VERSION 5.8 ;
BUSBITCHARS "[]" ;
DIVIDERCHAR "/" ;
UNITS
    DATABASE MICRONS 1000 ;
END UNITS

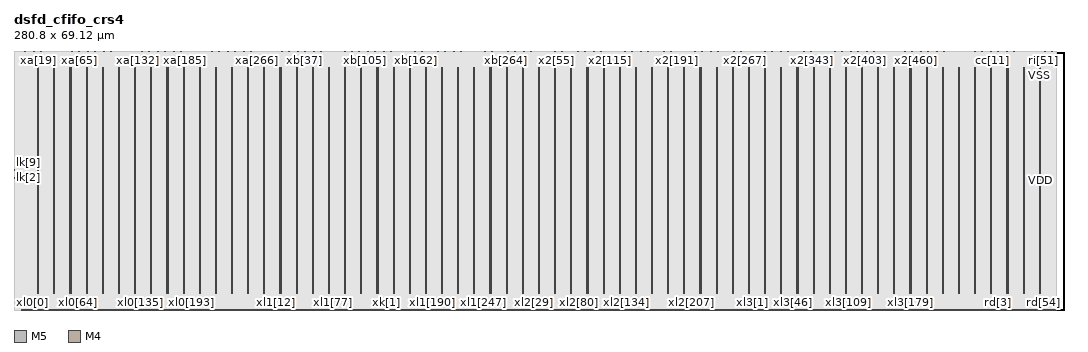
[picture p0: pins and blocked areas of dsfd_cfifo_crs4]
MACRO dsfd_cfifo_crs4
  FOREIGN dsfd_cfifo_crs4 0 0 ;
  CLASS BLOCK ;
  SIZE 280.8 BY 69.12 ;
  PIN cc[0]
    DIRECTION OUTPUT ;
    USE SIGNAL ;
    PORT
      LAYER M5 ;
        RECT  259.104 69.036 259.128 69.12 ;
    END
  END cc[0]
  PIN cc[10]
    DIRECTION OUTPUT ;
    USE SIGNAL ;
    PORT
      LAYER M5 ;
        RECT  261.504 69.036 261.528 69.12 ;
    END
  END cc[10]
  PIN cc[11]
    DIRECTION OUTPUT ;
    USE SIGNAL ;
    PORT
      LAYER M5 ;
        RECT  261.744 69.036 261.768 69.12 ;
    END
  END cc[11]
  PIN cc[12]
    DIRECTION OUTPUT ;
    USE SIGNAL ;
    PORT
      LAYER M5 ;
        RECT  261.984 69.036 262.008 69.12 ;
    END
  END cc[12]
  PIN cc[13]
    DIRECTION OUTPUT ;
    USE SIGNAL ;
    PORT
      LAYER M5 ;
        RECT  262.176 69.036 262.2 69.12 ;
    END
  END cc[13]
  PIN cc[14]
    DIRECTION OUTPUT ;
    USE SIGNAL ;
    PORT
      LAYER M5 ;
        RECT  262.416 69.036 262.44 69.12 ;
    END
  END cc[14]
  PIN cc[1]
    DIRECTION OUTPUT ;
    USE SIGNAL ;
    PORT
      LAYER M5 ;
        RECT  259.344 69.036 259.368 69.12 ;
    END
  END cc[1]
  PIN cc[2]
    DIRECTION OUTPUT ;
    USE SIGNAL ;
    PORT
      LAYER M5 ;
        RECT  259.584 69.036 259.608 69.12 ;
    END
  END cc[2]
  PIN cc[3]
    DIRECTION OUTPUT ;
    USE SIGNAL ;
    PORT
      LAYER M5 ;
        RECT  259.824 69.036 259.848 69.12 ;
    END
  END cc[3]
  PIN cc[4]
    DIRECTION OUTPUT ;
    USE SIGNAL ;
    PORT
      LAYER M5 ;
        RECT  260.064 69.036 260.088 69.12 ;
    END
  END cc[4]
  PIN cc[5]
    DIRECTION OUTPUT ;
    USE SIGNAL ;
    PORT
      LAYER M5 ;
        RECT  260.304 69.036 260.328 69.12 ;
    END
  END cc[5]
  PIN cc[6]
    DIRECTION OUTPUT ;
    USE SIGNAL ;
    PORT
      LAYER M5 ;
        RECT  260.544 69.036 260.568 69.12 ;
    END
  END cc[6]
  PIN cc[7]
    DIRECTION OUTPUT ;
    USE SIGNAL ;
    PORT
      LAYER M5 ;
        RECT  260.784 69.036 260.808 69.12 ;
    END
  END cc[7]
  PIN cc[8]
    DIRECTION OUTPUT ;
    USE SIGNAL ;
    PORT
      LAYER M5 ;
        RECT  261.024 69.036 261.048 69.12 ;
    END
  END cc[8]
  PIN cc[9]
    DIRECTION OUTPUT ;
    USE SIGNAL ;
    PORT
      LAYER M5 ;
        RECT  261.264 69.036 261.288 69.12 ;
    END
  END cc[9]
  PIN cr
    DIRECTION INPUT ;
    USE SIGNAL ;
    PORT
      LAYER M5 ;
        RECT  140.304 69.036 140.328 69.12 ;
    END
  END cr
  PIN cr_s
    DIRECTION INPUT ;
    USE SIGNAL ;
    PORT
      LAYER M5 ;
        RECT  270.624 0 270.648 0.084 ;
    END
  END cr_s
  PIN lk[0]
    DIRECTION INPUT ;
    USE SIGNAL ;
    PORT
      LAYER M4 ;
        RECT  0 35.04 0.084 35.064 ;
    END
  END lk[0]
  PIN lk[10]
    DIRECTION INPUT ;
    USE SIGNAL ;
    PORT
      LAYER M4 ;
        RECT  0 37.44 0.084 37.464 ;
    END
  END lk[10]
  PIN lk[11]
    DIRECTION INPUT ;
    USE SIGNAL ;
    PORT
      LAYER M4 ;
        RECT  0 37.68 0.084 37.704 ;
    END
  END lk[11]
  PIN lk[1]
    DIRECTION INPUT ;
    USE SIGNAL ;
    PORT
      LAYER M4 ;
        RECT  0 35.28 0.084 35.304 ;
    END
  END lk[1]
  PIN lk[2]
    DIRECTION INPUT ;
    USE SIGNAL ;
    PORT
      LAYER M4 ;
        RECT  0 35.52 0.084 35.544 ;
    END
  END lk[2]
  PIN lk[3]
    DIRECTION INPUT ;
    USE SIGNAL ;
    PORT
      LAYER M4 ;
        RECT  0 35.76 0.084 35.784 ;
    END
  END lk[3]
  PIN lk[4]
    DIRECTION INPUT ;
    USE SIGNAL ;
    PORT
      LAYER M4 ;
        RECT  0 36 0.084 36.024 ;
    END
  END lk[4]
  PIN lk[5]
    DIRECTION INPUT ;
    USE SIGNAL ;
    PORT
      LAYER M4 ;
        RECT  0 36.24 0.084 36.264 ;
    END
  END lk[5]
  PIN lk[6]
    DIRECTION INPUT ;
    USE SIGNAL ;
    PORT
      LAYER M4 ;
        RECT  0 36.48 0.084 36.504 ;
    END
  END lk[6]
  PIN lk[7]
    DIRECTION INPUT ;
    USE SIGNAL ;
    PORT
      LAYER M4 ;
        RECT  0 36.72 0.084 36.744 ;
    END
  END lk[7]
  PIN lk[8]
    DIRECTION INPUT ;
    USE SIGNAL ;
    PORT
      LAYER M4 ;
        RECT  0 36.96 0.084 36.984 ;
    END
  END lk[8]
  PIN lk[9]
    DIRECTION INPUT ;
    USE SIGNAL ;
    PORT
      LAYER M4 ;
        RECT  0 37.2 0.084 37.224 ;
    END
  END lk[9]
  PIN rd[0]
    DIRECTION OUTPUT ;
    USE SIGNAL ;
    PORT
      LAYER M5 ;
        RECT  262.512 0 262.536 0.084 ;
    END
  END rd[0]
  PIN rd[10]
    DIRECTION OUTPUT ;
    USE SIGNAL ;
    PORT
      LAYER M5 ;
        RECT  264.864 0 264.888 0.084 ;
    END
  END rd[10]
  PIN rd[11]
    DIRECTION OUTPUT ;
    USE SIGNAL ;
    PORT
      LAYER M5 ;
        RECT  265.104 0 265.128 0.084 ;
    END
  END rd[11]
  PIN rd[12]
    DIRECTION OUTPUT ;
    USE SIGNAL ;
    PORT
      LAYER M5 ;
        RECT  265.344 0 265.368 0.084 ;
    END
  END rd[12]
  PIN rd[13]
    DIRECTION OUTPUT ;
    USE SIGNAL ;
    PORT
      LAYER M5 ;
        RECT  265.584 0 265.608 0.084 ;
    END
  END rd[13]
  PIN rd[14]
    DIRECTION OUTPUT ;
    USE SIGNAL ;
    PORT
      LAYER M5 ;
        RECT  265.824 0 265.848 0.084 ;
    END
  END rd[14]
  PIN rd[15]
    DIRECTION OUTPUT ;
    USE SIGNAL ;
    PORT
      LAYER M5 ;
        RECT  266.064 0 266.088 0.084 ;
    END
  END rd[15]
  PIN rd[16]
    DIRECTION OUTPUT ;
    USE SIGNAL ;
    PORT
      LAYER M5 ;
        RECT  266.304 0 266.328 0.084 ;
    END
  END rd[16]
  PIN rd[17]
    DIRECTION OUTPUT ;
    USE SIGNAL ;
    PORT
      LAYER M5 ;
        RECT  266.496 0 266.52 0.084 ;
    END
  END rd[17]
  PIN rd[18]
    DIRECTION OUTPUT ;
    USE SIGNAL ;
    PORT
      LAYER M5 ;
        RECT  266.736 0 266.76 0.084 ;
    END
  END rd[18]
  PIN rd[19]
    DIRECTION OUTPUT ;
    USE SIGNAL ;
    PORT
      LAYER M5 ;
        RECT  266.976 0 267 0.084 ;
    END
  END rd[19]
  PIN rd[1]
    DIRECTION OUTPUT ;
    USE SIGNAL ;
    PORT
      LAYER M5 ;
        RECT  262.752 0 262.776 0.084 ;
    END
  END rd[1]
  PIN rd[20]
    DIRECTION OUTPUT ;
    USE SIGNAL ;
    PORT
      LAYER M5 ;
        RECT  267.216 0 267.24 0.084 ;
    END
  END rd[20]
  PIN rd[21]
    DIRECTION OUTPUT ;
    USE SIGNAL ;
    PORT
      LAYER M5 ;
        RECT  267.456 0 267.48 0.084 ;
    END
  END rd[21]
  PIN rd[22]
    DIRECTION OUTPUT ;
    USE SIGNAL ;
    PORT
      LAYER M5 ;
        RECT  267.696 0 267.72 0.084 ;
    END
  END rd[22]
  PIN rd[23]
    DIRECTION OUTPUT ;
    USE SIGNAL ;
    PORT
      LAYER M5 ;
        RECT  267.936 0 267.96 0.084 ;
    END
  END rd[23]
  PIN rd[24]
    DIRECTION OUTPUT ;
    USE SIGNAL ;
    PORT
      LAYER M5 ;
        RECT  268.176 0 268.2 0.084 ;
    END
  END rd[24]
  PIN rd[25]
    DIRECTION OUTPUT ;
    USE SIGNAL ;
    PORT
      LAYER M5 ;
        RECT  268.416 0 268.44 0.084 ;
    END
  END rd[25]
  PIN rd[26]
    DIRECTION OUTPUT ;
    USE SIGNAL ;
    PORT
      LAYER M5 ;
        RECT  268.656 0 268.68 0.084 ;
    END
  END rd[26]
  PIN rd[27]
    DIRECTION OUTPUT ;
    USE SIGNAL ;
    PORT
      LAYER M5 ;
        RECT  268.896 0 268.92 0.084 ;
    END
  END rd[27]
  PIN rd[28]
    DIRECTION OUTPUT ;
    USE SIGNAL ;
    PORT
      LAYER M5 ;
        RECT  269.136 0 269.16 0.084 ;
    END
  END rd[28]
  PIN rd[29]
    DIRECTION OUTPUT ;
    USE SIGNAL ;
    PORT
      LAYER M5 ;
        RECT  269.328 0 269.352 0.084 ;
    END
  END rd[29]
  PIN rd[2]
    DIRECTION OUTPUT ;
    USE SIGNAL ;
    PORT
      LAYER M5 ;
        RECT  262.992 0 263.016 0.084 ;
    END
  END rd[2]
  PIN rd[30]
    DIRECTION OUTPUT ;
    USE SIGNAL ;
    PORT
      LAYER M5 ;
        RECT  269.568 0 269.592 0.084 ;
    END
  END rd[30]
  PIN rd[31]
    DIRECTION OUTPUT ;
    USE SIGNAL ;
    PORT
      LAYER M5 ;
        RECT  269.808 0 269.832 0.084 ;
    END
  END rd[31]
  PIN rd[32]
    DIRECTION OUTPUT ;
    USE SIGNAL ;
    PORT
      LAYER M5 ;
        RECT  270.048 0 270.072 0.084 ;
    END
  END rd[32]
  PIN rd[33]
    DIRECTION OUTPUT ;
    USE SIGNAL ;
    PORT
      LAYER M5 ;
        RECT  270.288 0 270.312 0.084 ;
    END
  END rd[33]
  PIN rd[34]
    DIRECTION OUTPUT ;
    USE SIGNAL ;
    PORT
      LAYER M5 ;
        RECT  270.528 0 270.552 0.084 ;
    END
  END rd[34]
  PIN rd[35]
    DIRECTION OUTPUT ;
    USE SIGNAL ;
    PORT
      LAYER M5 ;
        RECT  270.768 0 270.792 0.084 ;
    END
  END rd[35]
  PIN rd[36]
    DIRECTION OUTPUT ;
    USE SIGNAL ;
    PORT
      LAYER M5 ;
        RECT  271.008 0 271.032 0.084 ;
    END
  END rd[36]
  PIN rd[37]
    DIRECTION OUTPUT ;
    USE SIGNAL ;
    PORT
      LAYER M5 ;
        RECT  271.248 0 271.272 0.084 ;
    END
  END rd[37]
  PIN rd[38]
    DIRECTION OUTPUT ;
    USE SIGNAL ;
    PORT
      LAYER M5 ;
        RECT  271.488 0 271.512 0.084 ;
    END
  END rd[38]
  PIN rd[39]
    DIRECTION OUTPUT ;
    USE SIGNAL ;
    PORT
      LAYER M5 ;
        RECT  271.728 0 271.752 0.084 ;
    END
  END rd[39]
  PIN rd[3]
    DIRECTION OUTPUT ;
    USE SIGNAL ;
    PORT
      LAYER M5 ;
        RECT  263.232 0 263.256 0.084 ;
    END
  END rd[3]
  PIN rd[40]
    DIRECTION OUTPUT ;
    USE SIGNAL ;
    PORT
      LAYER M5 ;
        RECT  271.968 0 271.992 0.084 ;
    END
  END rd[40]
  PIN rd[41]
    DIRECTION OUTPUT ;
    USE SIGNAL ;
    PORT
      LAYER M5 ;
        RECT  272.16 0 272.184 0.084 ;
    END
  END rd[41]
  PIN rd[42]
    DIRECTION OUTPUT ;
    USE SIGNAL ;
    PORT
      LAYER M5 ;
        RECT  272.4 0 272.424 0.084 ;
    END
  END rd[42]
  PIN rd[43]
    DIRECTION OUTPUT ;
    USE SIGNAL ;
    PORT
      LAYER M5 ;
        RECT  272.64 0 272.664 0.084 ;
    END
  END rd[43]
  PIN rd[44]
    DIRECTION OUTPUT ;
    USE SIGNAL ;
    PORT
      LAYER M5 ;
        RECT  272.88 0 272.904 0.084 ;
    END
  END rd[44]
  PIN rd[45]
    DIRECTION OUTPUT ;
    USE SIGNAL ;
    PORT
      LAYER M5 ;
        RECT  273.12 0 273.144 0.084 ;
    END
  END rd[45]
  PIN rd[46]
    DIRECTION OUTPUT ;
    USE SIGNAL ;
    PORT
      LAYER M5 ;
        RECT  273.36 0 273.384 0.084 ;
    END
  END rd[46]
  PIN rd[47]
    DIRECTION OUTPUT ;
    USE SIGNAL ;
    PORT
      LAYER M5 ;
        RECT  273.6 0 273.624 0.084 ;
    END
  END rd[47]
  PIN rd[48]
    DIRECTION OUTPUT ;
    USE SIGNAL ;
    PORT
      LAYER M5 ;
        RECT  273.84 0 273.864 0.084 ;
    END
  END rd[48]
  PIN rd[49]
    DIRECTION OUTPUT ;
    USE SIGNAL ;
    PORT
      LAYER M5 ;
        RECT  274.08 0 274.104 0.084 ;
    END
  END rd[49]
  PIN rd[4]
    DIRECTION OUTPUT ;
    USE SIGNAL ;
    PORT
      LAYER M5 ;
        RECT  263.472 0 263.496 0.084 ;
    END
  END rd[4]
  PIN rd[50]
    DIRECTION OUTPUT ;
    USE SIGNAL ;
    PORT
      LAYER M5 ;
        RECT  274.32 0 274.344 0.084 ;
    END
  END rd[50]
  PIN rd[51]
    DIRECTION OUTPUT ;
    USE SIGNAL ;
    PORT
      LAYER M5 ;
        RECT  274.56 0 274.584 0.084 ;
    END
  END rd[51]
  PIN rd[52]
    DIRECTION OUTPUT ;
    USE SIGNAL ;
    PORT
      LAYER M5 ;
        RECT  274.8 0 274.824 0.084 ;
    END
  END rd[52]
  PIN rd[53]
    DIRECTION OUTPUT ;
    USE SIGNAL ;
    PORT
      LAYER M5 ;
        RECT  274.992 0 275.016 0.084 ;
    END
  END rd[53]
  PIN rd[54]
    DIRECTION OUTPUT ;
    USE SIGNAL ;
    PORT
      LAYER M5 ;
        RECT  275.232 0 275.256 0.084 ;
    END
  END rd[54]
  PIN rd[55]
    DIRECTION OUTPUT ;
    USE SIGNAL ;
    PORT
      LAYER M5 ;
        RECT  275.472 0 275.496 0.084 ;
    END
  END rd[55]
  PIN rd[56]
    DIRECTION OUTPUT ;
    USE SIGNAL ;
    PORT
      LAYER M5 ;
        RECT  275.712 0 275.736 0.084 ;
    END
  END rd[56]
  PIN rd[57]
    DIRECTION OUTPUT ;
    USE SIGNAL ;
    PORT
      LAYER M5 ;
        RECT  275.952 0 275.976 0.084 ;
    END
  END rd[57]
  PIN rd[58]
    DIRECTION OUTPUT ;
    USE SIGNAL ;
    PORT
      LAYER M5 ;
        RECT  276.192 0 276.216 0.084 ;
    END
  END rd[58]
  PIN rd[59]
    DIRECTION OUTPUT ;
    USE SIGNAL ;
    PORT
      LAYER M5 ;
        RECT  276.432 0 276.456 0.084 ;
    END
  END rd[59]
  PIN rd[5]
    DIRECTION OUTPUT ;
    USE SIGNAL ;
    PORT
      LAYER M5 ;
        RECT  263.664 0 263.688 0.084 ;
    END
  END rd[5]
  PIN rd[60]
    DIRECTION OUTPUT ;
    USE SIGNAL ;
    PORT
      LAYER M5 ;
        RECT  276.672 0 276.696 0.084 ;
    END
  END rd[60]
  PIN rd[61]
    DIRECTION OUTPUT ;
    USE SIGNAL ;
    PORT
      LAYER M5 ;
        RECT  276.912 0 276.936 0.084 ;
    END
  END rd[61]
  PIN rd[62]
    DIRECTION OUTPUT ;
    USE SIGNAL ;
    PORT
      LAYER M5 ;
        RECT  277.152 0 277.176 0.084 ;
    END
  END rd[62]
  PIN rd[63]
    DIRECTION OUTPUT ;
    USE SIGNAL ;
    PORT
      LAYER M5 ;
        RECT  277.392 0 277.416 0.084 ;
    END
  END rd[63]
  PIN rd[64]
    DIRECTION OUTPUT ;
    USE SIGNAL ;
    PORT
      LAYER M5 ;
        RECT  277.632 0 277.656 0.084 ;
    END
  END rd[64]
  PIN rd[65]
    DIRECTION OUTPUT ;
    USE SIGNAL ;
    PORT
      LAYER M5 ;
        RECT  277.824 0 277.848 0.084 ;
    END
  END rd[65]
  PIN rd[66]
    DIRECTION OUTPUT ;
    USE SIGNAL ;
    PORT
      LAYER M5 ;
        RECT  278.064 0 278.088 0.084 ;
    END
  END rd[66]
  PIN rd[67]
    DIRECTION OUTPUT ;
    USE SIGNAL ;
    PORT
      LAYER M5 ;
        RECT  278.304 0 278.328 0.084 ;
    END
  END rd[67]
  PIN rd[68]
    DIRECTION OUTPUT ;
    USE SIGNAL ;
    PORT
      LAYER M5 ;
        RECT  278.544 0 278.568 0.084 ;
    END
  END rd[68]
  PIN rd[69]
    DIRECTION OUTPUT ;
    USE SIGNAL ;
    PORT
      LAYER M5 ;
        RECT  278.784 0 278.808 0.084 ;
    END
  END rd[69]
  PIN rd[6]
    DIRECTION OUTPUT ;
    USE SIGNAL ;
    PORT
      LAYER M5 ;
        RECT  263.904 0 263.928 0.084 ;
    END
  END rd[6]
  PIN rd[7]
    DIRECTION OUTPUT ;
    USE SIGNAL ;
    PORT
      LAYER M5 ;
        RECT  264.144 0 264.168 0.084 ;
    END
  END rd[7]
  PIN rd[8]
    DIRECTION OUTPUT ;
    USE SIGNAL ;
    PORT
      LAYER M5 ;
        RECT  264.384 0 264.408 0.084 ;
    END
  END rd[8]
  PIN rd[9]
    DIRECTION OUTPUT ;
    USE SIGNAL ;
    PORT
      LAYER M5 ;
        RECT  264.624 0 264.648 0.084 ;
    END
  END rd[9]
  PIN ri[0]
    DIRECTION INPUT ;
    USE SIGNAL ;
    PORT
      LAYER M5 ;
        RECT  263.136 69.036 263.16 69.12 ;
    END
  END ri[0]
  PIN ri[10]
    DIRECTION INPUT ;
    USE SIGNAL ;
    PORT
      LAYER M5 ;
        RECT  265.536 69.036 265.56 69.12 ;
    END
  END ri[10]
  PIN ri[11]
    DIRECTION INPUT ;
    USE SIGNAL ;
    PORT
      LAYER M5 ;
        RECT  265.776 69.036 265.8 69.12 ;
    END
  END ri[11]
  PIN ri[12]
    DIRECTION INPUT ;
    USE SIGNAL ;
    PORT
      LAYER M5 ;
        RECT  265.968 69.036 265.992 69.12 ;
    END
  END ri[12]
  PIN ri[13]
    DIRECTION INPUT ;
    USE SIGNAL ;
    PORT
      LAYER M5 ;
        RECT  266.208 69.036 266.232 69.12 ;
    END
  END ri[13]
  PIN ri[14]
    DIRECTION INPUT ;
    USE SIGNAL ;
    PORT
      LAYER M5 ;
        RECT  266.448 69.036 266.472 69.12 ;
    END
  END ri[14]
  PIN ri[15]
    DIRECTION INPUT ;
    USE SIGNAL ;
    PORT
      LAYER M5 ;
        RECT  266.688 69.036 266.712 69.12 ;
    END
  END ri[15]
  PIN ri[16]
    DIRECTION INPUT ;
    USE SIGNAL ;
    PORT
      LAYER M5 ;
        RECT  266.928 69.036 266.952 69.12 ;
    END
  END ri[16]
  PIN ri[17]
    DIRECTION INPUT ;
    USE SIGNAL ;
    PORT
      LAYER M5 ;
        RECT  267.168 69.036 267.192 69.12 ;
    END
  END ri[17]
  PIN ri[18]
    DIRECTION INPUT ;
    USE SIGNAL ;
    PORT
      LAYER M5 ;
        RECT  267.408 69.036 267.432 69.12 ;
    END
  END ri[18]
  PIN ri[19]
    DIRECTION INPUT ;
    USE SIGNAL ;
    PORT
      LAYER M5 ;
        RECT  267.648 69.036 267.672 69.12 ;
    END
  END ri[19]
  PIN ri[1]
    DIRECTION INPUT ;
    USE SIGNAL ;
    PORT
      LAYER M5 ;
        RECT  263.376 69.036 263.4 69.12 ;
    END
  END ri[1]
  PIN ri[20]
    DIRECTION INPUT ;
    USE SIGNAL ;
    PORT
      LAYER M5 ;
        RECT  267.888 69.036 267.912 69.12 ;
    END
  END ri[20]
  PIN ri[21]
    DIRECTION INPUT ;
    USE SIGNAL ;
    PORT
      LAYER M5 ;
        RECT  268.128 69.036 268.152 69.12 ;
    END
  END ri[21]
  PIN ri[22]
    DIRECTION INPUT ;
    USE SIGNAL ;
    PORT
      LAYER M5 ;
        RECT  268.368 69.036 268.392 69.12 ;
    END
  END ri[22]
  PIN ri[23]
    DIRECTION INPUT ;
    USE SIGNAL ;
    PORT
      LAYER M5 ;
        RECT  268.608 69.036 268.632 69.12 ;
    END
  END ri[23]
  PIN ri[24]
    DIRECTION INPUT ;
    USE SIGNAL ;
    PORT
      LAYER M5 ;
        RECT  268.848 69.036 268.872 69.12 ;
    END
  END ri[24]
  PIN ri[25]
    DIRECTION INPUT ;
    USE SIGNAL ;
    PORT
      LAYER M5 ;
        RECT  269.088 69.036 269.112 69.12 ;
    END
  END ri[25]
  PIN ri[26]
    DIRECTION INPUT ;
    USE SIGNAL ;
    PORT
      LAYER M5 ;
        RECT  269.328 69.036 269.352 69.12 ;
    END
  END ri[26]
  PIN ri[27]
    DIRECTION INPUT ;
    USE SIGNAL ;
    PORT
      LAYER M5 ;
        RECT  269.568 69.036 269.592 69.12 ;
    END
  END ri[27]
  PIN ri[28]
    DIRECTION INPUT ;
    USE SIGNAL ;
    PORT
      LAYER M5 ;
        RECT  269.76 69.036 269.784 69.12 ;
    END
  END ri[28]
  PIN ri[29]
    DIRECTION INPUT ;
    USE SIGNAL ;
    PORT
      LAYER M5 ;
        RECT  270 69.036 270.024 69.12 ;
    END
  END ri[29]
  PIN ri[2]
    DIRECTION INPUT ;
    USE SIGNAL ;
    PORT
      LAYER M5 ;
        RECT  263.616 69.036 263.64 69.12 ;
    END
  END ri[2]
  PIN ri[30]
    DIRECTION INPUT ;
    USE SIGNAL ;
    PORT
      LAYER M5 ;
        RECT  270.24 69.036 270.264 69.12 ;
    END
  END ri[30]
  PIN ri[31]
    DIRECTION INPUT ;
    USE SIGNAL ;
    PORT
      LAYER M5 ;
        RECT  270.48 69.036 270.504 69.12 ;
    END
  END ri[31]
  PIN ri[32]
    DIRECTION INPUT ;
    USE SIGNAL ;
    PORT
      LAYER M5 ;
        RECT  270.72 69.036 270.744 69.12 ;
    END
  END ri[32]
  PIN ri[33]
    DIRECTION INPUT ;
    USE SIGNAL ;
    PORT
      LAYER M5 ;
        RECT  270.96 69.036 270.984 69.12 ;
    END
  END ri[33]
  PIN ri[34]
    DIRECTION INPUT ;
    USE SIGNAL ;
    PORT
      LAYER M5 ;
        RECT  271.2 69.036 271.224 69.12 ;
    END
  END ri[34]
  PIN ri[35]
    DIRECTION INPUT ;
    USE SIGNAL ;
    PORT
      LAYER M5 ;
        RECT  271.44 69.036 271.464 69.12 ;
    END
  END ri[35]
  PIN ri[36]
    DIRECTION INPUT ;
    USE SIGNAL ;
    PORT
      LAYER M5 ;
        RECT  271.68 69.036 271.704 69.12 ;
    END
  END ri[36]
  PIN ri[37]
    DIRECTION INPUT ;
    USE SIGNAL ;
    PORT
      LAYER M5 ;
        RECT  271.92 69.036 271.944 69.12 ;
    END
  END ri[37]
  PIN ri[38]
    DIRECTION INPUT ;
    USE SIGNAL ;
    PORT
      LAYER M5 ;
        RECT  272.16 69.036 272.184 69.12 ;
    END
  END ri[38]
  PIN ri[39]
    DIRECTION INPUT ;
    USE SIGNAL ;
    PORT
      LAYER M5 ;
        RECT  272.4 69.036 272.424 69.12 ;
    END
  END ri[39]
  PIN ri[3]
    DIRECTION INPUT ;
    USE SIGNAL ;
    PORT
      LAYER M5 ;
        RECT  263.856 69.036 263.88 69.12 ;
    END
  END ri[3]
  PIN ri[40]
    DIRECTION INPUT ;
    USE SIGNAL ;
    PORT
      LAYER M5 ;
        RECT  272.64 69.036 272.664 69.12 ;
    END
  END ri[40]
  PIN ri[41]
    DIRECTION INPUT ;
    USE SIGNAL ;
    PORT
      LAYER M5 ;
        RECT  272.88 69.036 272.904 69.12 ;
    END
  END ri[41]
  PIN ri[42]
    DIRECTION INPUT ;
    USE SIGNAL ;
    PORT
      LAYER M5 ;
        RECT  273.12 69.036 273.144 69.12 ;
    END
  END ri[42]
  PIN ri[43]
    DIRECTION INPUT ;
    USE SIGNAL ;
    PORT
      LAYER M5 ;
        RECT  273.36 69.036 273.384 69.12 ;
    END
  END ri[43]
  PIN ri[44]
    DIRECTION INPUT ;
    USE SIGNAL ;
    PORT
      LAYER M5 ;
        RECT  273.552 69.036 273.576 69.12 ;
    END
  END ri[44]
  PIN ri[45]
    DIRECTION INPUT ;
    USE SIGNAL ;
    PORT
      LAYER M5 ;
        RECT  273.792 69.036 273.816 69.12 ;
    END
  END ri[45]
  PIN ri[46]
    DIRECTION INPUT ;
    USE SIGNAL ;
    PORT
      LAYER M5 ;
        RECT  274.032 69.036 274.056 69.12 ;
    END
  END ri[46]
  PIN ri[47]
    DIRECTION INPUT ;
    USE SIGNAL ;
    PORT
      LAYER M5 ;
        RECT  274.272 69.036 274.296 69.12 ;
    END
  END ri[47]
  PIN ri[48]
    DIRECTION INPUT ;
    USE SIGNAL ;
    PORT
      LAYER M5 ;
        RECT  274.512 69.036 274.536 69.12 ;
    END
  END ri[48]
  PIN ri[49]
    DIRECTION INPUT ;
    USE SIGNAL ;
    PORT
      LAYER M5 ;
        RECT  274.752 69.036 274.776 69.12 ;
    END
  END ri[49]
  PIN ri[4]
    DIRECTION INPUT ;
    USE SIGNAL ;
    PORT
      LAYER M5 ;
        RECT  264.096 69.036 264.12 69.12 ;
    END
  END ri[4]
  PIN ri[50]
    DIRECTION INPUT ;
    USE SIGNAL ;
    PORT
      LAYER M5 ;
        RECT  274.992 69.036 275.016 69.12 ;
    END
  END ri[50]
  PIN ri[51]
    DIRECTION INPUT ;
    USE SIGNAL ;
    PORT
      LAYER M5 ;
        RECT  275.232 69.036 275.256 69.12 ;
    END
  END ri[51]
  PIN ri[52]
    DIRECTION INPUT ;
    USE SIGNAL ;
    PORT
      LAYER M5 ;
        RECT  275.472 69.036 275.496 69.12 ;
    END
  END ri[52]
  PIN ri[53]
    DIRECTION INPUT ;
    USE SIGNAL ;
    PORT
      LAYER M5 ;
        RECT  275.712 69.036 275.736 69.12 ;
    END
  END ri[53]
  PIN ri[54]
    DIRECTION INPUT ;
    USE SIGNAL ;
    PORT
      LAYER M5 ;
        RECT  275.952 69.036 275.976 69.12 ;
    END
  END ri[54]
  PIN ri[55]
    DIRECTION INPUT ;
    USE SIGNAL ;
    PORT
      LAYER M5 ;
        RECT  276.192 69.036 276.216 69.12 ;
    END
  END ri[55]
  PIN ri[56]
    DIRECTION INPUT ;
    USE SIGNAL ;
    PORT
      LAYER M5 ;
        RECT  276.432 69.036 276.456 69.12 ;
    END
  END ri[56]
  PIN ri[57]
    DIRECTION INPUT ;
    USE SIGNAL ;
    PORT
      LAYER M5 ;
        RECT  276.672 69.036 276.696 69.12 ;
    END
  END ri[57]
  PIN ri[58]
    DIRECTION INPUT ;
    USE SIGNAL ;
    PORT
      LAYER M5 ;
        RECT  276.912 69.036 276.936 69.12 ;
    END
  END ri[58]
  PIN ri[59]
    DIRECTION INPUT ;
    USE SIGNAL ;
    PORT
      LAYER M5 ;
        RECT  277.152 69.036 277.176 69.12 ;
    END
  END ri[59]
  PIN ri[5]
    DIRECTION INPUT ;
    USE SIGNAL ;
    PORT
      LAYER M5 ;
        RECT  264.336 69.036 264.36 69.12 ;
    END
  END ri[5]
  PIN ri[60]
    DIRECTION INPUT ;
    USE SIGNAL ;
    PORT
      LAYER M5 ;
        RECT  277.344 69.036 277.368 69.12 ;
    END
  END ri[60]
  PIN ri[61]
    DIRECTION INPUT ;
    USE SIGNAL ;
    PORT
      LAYER M5 ;
        RECT  277.584 69.036 277.608 69.12 ;
    END
  END ri[61]
  PIN ri[62]
    DIRECTION INPUT ;
    USE SIGNAL ;
    PORT
      LAYER M5 ;
        RECT  277.824 69.036 277.848 69.12 ;
    END
  END ri[62]
  PIN ri[63]
    DIRECTION INPUT ;
    USE SIGNAL ;
    PORT
      LAYER M5 ;
        RECT  278.064 69.036 278.088 69.12 ;
    END
  END ri[63]
  PIN ri[64]
    DIRECTION INPUT ;
    USE SIGNAL ;
    PORT
      LAYER M5 ;
        RECT  278.304 69.036 278.328 69.12 ;
    END
  END ri[64]
  PIN ri[65]
    DIRECTION INPUT ;
    USE SIGNAL ;
    PORT
      LAYER M5 ;
        RECT  278.544 69.036 278.568 69.12 ;
    END
  END ri[65]
  PIN ri[6]
    DIRECTION INPUT ;
    USE SIGNAL ;
    PORT
      LAYER M5 ;
        RECT  264.576 69.036 264.6 69.12 ;
    END
  END ri[6]
  PIN ri[7]
    DIRECTION INPUT ;
    USE SIGNAL ;
    PORT
      LAYER M5 ;
        RECT  264.816 69.036 264.84 69.12 ;
    END
  END ri[7]
  PIN ri[8]
    DIRECTION INPUT ;
    USE SIGNAL ;
    PORT
      LAYER M5 ;
        RECT  265.056 69.036 265.08 69.12 ;
    END
  END ri[8]
  PIN ri[9]
    DIRECTION INPUT ;
    USE SIGNAL ;
    PORT
      LAYER M5 ;
        RECT  265.296 69.036 265.32 69.12 ;
    END
  END ri[9]
  PIN rs
    DIRECTION OUTPUT ;
    USE SIGNAL ;
    PORT
      LAYER M5 ;
        RECT  278.784 69.036 278.808 69.12 ;
    END
  END rs
  PIN rst
    DIRECTION INPUT ;
    USE SIGNAL ;
    PORT
      LAYER M4 ;
        RECT  0 34.56 0.084 34.584 ;
    END
  END rst
  PIN st[0]
    DIRECTION INPUT ;
    USE SIGNAL ;
    PORT
      LAYER M5 ;
        RECT  262.656 69.036 262.68 69.12 ;
    END
  END st[0]
  PIN st[1]
    DIRECTION INPUT ;
    USE SIGNAL ;
    PORT
      LAYER M5 ;
        RECT  262.896 69.036 262.92 69.12 ;
    END
  END st[1]
  PIN x2[0]
    DIRECTION OUTPUT ;
    USE SIGNAL ;
    PORT
      LAYER M5 ;
        RECT  132.096 69.036 132.12 69.12 ;
    END
  END x2[0]
  PIN x2[100]
    DIRECTION OUTPUT ;
    USE SIGNAL ;
    PORT
      LAYER M5 ;
        RECT  155.808 69.036 155.832 69.12 ;
    END
  END x2[100]
  PIN x2[101]
    DIRECTION OUTPUT ;
    USE SIGNAL ;
    PORT
      LAYER M5 ;
        RECT  156.048 69.036 156.072 69.12 ;
    END
  END x2[101]
  PIN x2[102]
    DIRECTION OUTPUT ;
    USE SIGNAL ;
    PORT
      LAYER M5 ;
        RECT  156.288 69.036 156.312 69.12 ;
    END
  END x2[102]
  PIN x2[103]
    DIRECTION OUTPUT ;
    USE SIGNAL ;
    PORT
      LAYER M5 ;
        RECT  156.48 69.036 156.504 69.12 ;
    END
  END x2[103]
  PIN x2[104]
    DIRECTION OUTPUT ;
    USE SIGNAL ;
    PORT
      LAYER M5 ;
        RECT  156.72 69.036 156.744 69.12 ;
    END
  END x2[104]
  PIN x2[105]
    DIRECTION OUTPUT ;
    USE SIGNAL ;
    PORT
      LAYER M5 ;
        RECT  156.96 69.036 156.984 69.12 ;
    END
  END x2[105]
  PIN x2[106]
    DIRECTION OUTPUT ;
    USE SIGNAL ;
    PORT
      LAYER M5 ;
        RECT  157.2 69.036 157.224 69.12 ;
    END
  END x2[106]
  PIN x2[107]
    DIRECTION OUTPUT ;
    USE SIGNAL ;
    PORT
      LAYER M5 ;
        RECT  157.44 69.036 157.464 69.12 ;
    END
  END x2[107]
  PIN x2[108]
    DIRECTION OUTPUT ;
    USE SIGNAL ;
    PORT
      LAYER M5 ;
        RECT  157.68 69.036 157.704 69.12 ;
    END
  END x2[108]
  PIN x2[109]
    DIRECTION OUTPUT ;
    USE SIGNAL ;
    PORT
      LAYER M5 ;
        RECT  157.92 69.036 157.944 69.12 ;
    END
  END x2[109]
  PIN x2[10]
    DIRECTION OUTPUT ;
    USE SIGNAL ;
    PORT
      LAYER M5 ;
        RECT  134.448 69.036 134.472 69.12 ;
    END
  END x2[10]
  PIN x2[110]
    DIRECTION OUTPUT ;
    USE SIGNAL ;
    PORT
      LAYER M5 ;
        RECT  158.16 69.036 158.184 69.12 ;
    END
  END x2[110]
  PIN x2[111]
    DIRECTION OUTPUT ;
    USE SIGNAL ;
    PORT
      LAYER M5 ;
        RECT  158.4 69.036 158.424 69.12 ;
    END
  END x2[111]
  PIN x2[112]
    DIRECTION OUTPUT ;
    USE SIGNAL ;
    PORT
      LAYER M5 ;
        RECT  158.64 69.036 158.664 69.12 ;
    END
  END x2[112]
  PIN x2[113]
    DIRECTION OUTPUT ;
    USE SIGNAL ;
    PORT
      LAYER M5 ;
        RECT  158.88 69.036 158.904 69.12 ;
    END
  END x2[113]
  PIN x2[114]
    DIRECTION OUTPUT ;
    USE SIGNAL ;
    PORT
      LAYER M5 ;
        RECT  159.12 69.036 159.144 69.12 ;
    END
  END x2[114]
  PIN x2[115]
    DIRECTION OUTPUT ;
    USE SIGNAL ;
    PORT
      LAYER M5 ;
        RECT  159.36 69.036 159.384 69.12 ;
    END
  END x2[115]
  PIN x2[116]
    DIRECTION OUTPUT ;
    USE SIGNAL ;
    PORT
      LAYER M5 ;
        RECT  159.6 69.036 159.624 69.12 ;
    END
  END x2[116]
  PIN x2[117]
    DIRECTION OUTPUT ;
    USE SIGNAL ;
    PORT
      LAYER M5 ;
        RECT  159.84 69.036 159.864 69.12 ;
    END
  END x2[117]
  PIN x2[118]
    DIRECTION OUTPUT ;
    USE SIGNAL ;
    PORT
      LAYER M5 ;
        RECT  160.08 69.036 160.104 69.12 ;
    END
  END x2[118]
  PIN x2[119]
    DIRECTION OUTPUT ;
    USE SIGNAL ;
    PORT
      LAYER M5 ;
        RECT  160.272 69.036 160.296 69.12 ;
    END
  END x2[119]
  PIN x2[11]
    DIRECTION OUTPUT ;
    USE SIGNAL ;
    PORT
      LAYER M5 ;
        RECT  134.688 69.036 134.712 69.12 ;
    END
  END x2[11]
  PIN x2[120]
    DIRECTION OUTPUT ;
    USE SIGNAL ;
    PORT
      LAYER M5 ;
        RECT  160.512 69.036 160.536 69.12 ;
    END
  END x2[120]
  PIN x2[121]
    DIRECTION OUTPUT ;
    USE SIGNAL ;
    PORT
      LAYER M5 ;
        RECT  160.752 69.036 160.776 69.12 ;
    END
  END x2[121]
  PIN x2[122]
    DIRECTION OUTPUT ;
    USE SIGNAL ;
    PORT
      LAYER M5 ;
        RECT  160.992 69.036 161.016 69.12 ;
    END
  END x2[122]
  PIN x2[123]
    DIRECTION OUTPUT ;
    USE SIGNAL ;
    PORT
      LAYER M5 ;
        RECT  161.232 69.036 161.256 69.12 ;
    END
  END x2[123]
  PIN x2[124]
    DIRECTION OUTPUT ;
    USE SIGNAL ;
    PORT
      LAYER M5 ;
        RECT  161.472 69.036 161.496 69.12 ;
    END
  END x2[124]
  PIN x2[125]
    DIRECTION OUTPUT ;
    USE SIGNAL ;
    PORT
      LAYER M5 ;
        RECT  161.712 69.036 161.736 69.12 ;
    END
  END x2[125]
  PIN x2[126]
    DIRECTION OUTPUT ;
    USE SIGNAL ;
    PORT
      LAYER M5 ;
        RECT  161.952 69.036 161.976 69.12 ;
    END
  END x2[126]
  PIN x2[127]
    DIRECTION OUTPUT ;
    USE SIGNAL ;
    PORT
      LAYER M5 ;
        RECT  162.192 69.036 162.216 69.12 ;
    END
  END x2[127]
  PIN x2[128]
    DIRECTION OUTPUT ;
    USE SIGNAL ;
    PORT
      LAYER M5 ;
        RECT  162.432 69.036 162.456 69.12 ;
    END
  END x2[128]
  PIN x2[129]
    DIRECTION OUTPUT ;
    USE SIGNAL ;
    PORT
      LAYER M5 ;
        RECT  162.672 69.036 162.696 69.12 ;
    END
  END x2[129]
  PIN x2[12]
    DIRECTION OUTPUT ;
    USE SIGNAL ;
    PORT
      LAYER M5 ;
        RECT  134.928 69.036 134.952 69.12 ;
    END
  END x2[12]
  PIN x2[130]
    DIRECTION OUTPUT ;
    USE SIGNAL ;
    PORT
      LAYER M5 ;
        RECT  162.912 69.036 162.936 69.12 ;
    END
  END x2[130]
  PIN x2[131]
    DIRECTION OUTPUT ;
    USE SIGNAL ;
    PORT
      LAYER M5 ;
        RECT  163.152 69.036 163.176 69.12 ;
    END
  END x2[131]
  PIN x2[132]
    DIRECTION OUTPUT ;
    USE SIGNAL ;
    PORT
      LAYER M5 ;
        RECT  163.392 69.036 163.416 69.12 ;
    END
  END x2[132]
  PIN x2[133]
    DIRECTION OUTPUT ;
    USE SIGNAL ;
    PORT
      LAYER M5 ;
        RECT  163.632 69.036 163.656 69.12 ;
    END
  END x2[133]
  PIN x2[134]
    DIRECTION OUTPUT ;
    USE SIGNAL ;
    PORT
      LAYER M5 ;
        RECT  163.872 69.036 163.896 69.12 ;
    END
  END x2[134]
  PIN x2[135]
    DIRECTION OUTPUT ;
    USE SIGNAL ;
    PORT
      LAYER M5 ;
        RECT  164.064 69.036 164.088 69.12 ;
    END
  END x2[135]
  PIN x2[136]
    DIRECTION OUTPUT ;
    USE SIGNAL ;
    PORT
      LAYER M5 ;
        RECT  164.304 69.036 164.328 69.12 ;
    END
  END x2[136]
  PIN x2[137]
    DIRECTION OUTPUT ;
    USE SIGNAL ;
    PORT
      LAYER M5 ;
        RECT  164.544 69.036 164.568 69.12 ;
    END
  END x2[137]
  PIN x2[138]
    DIRECTION OUTPUT ;
    USE SIGNAL ;
    PORT
      LAYER M5 ;
        RECT  164.784 69.036 164.808 69.12 ;
    END
  END x2[138]
  PIN x2[139]
    DIRECTION OUTPUT ;
    USE SIGNAL ;
    PORT
      LAYER M5 ;
        RECT  165.024 69.036 165.048 69.12 ;
    END
  END x2[139]
  PIN x2[13]
    DIRECTION OUTPUT ;
    USE SIGNAL ;
    PORT
      LAYER M5 ;
        RECT  135.168 69.036 135.192 69.12 ;
    END
  END x2[13]
  PIN x2[140]
    DIRECTION OUTPUT ;
    USE SIGNAL ;
    PORT
      LAYER M5 ;
        RECT  165.264 69.036 165.288 69.12 ;
    END
  END x2[140]
  PIN x2[141]
    DIRECTION OUTPUT ;
    USE SIGNAL ;
    PORT
      LAYER M5 ;
        RECT  165.504 69.036 165.528 69.12 ;
    END
  END x2[141]
  PIN x2[142]
    DIRECTION OUTPUT ;
    USE SIGNAL ;
    PORT
      LAYER M5 ;
        RECT  165.744 69.036 165.768 69.12 ;
    END
  END x2[142]
  PIN x2[143]
    DIRECTION OUTPUT ;
    USE SIGNAL ;
    PORT
      LAYER M5 ;
        RECT  165.984 69.036 166.008 69.12 ;
    END
  END x2[143]
  PIN x2[144]
    DIRECTION OUTPUT ;
    USE SIGNAL ;
    PORT
      LAYER M5 ;
        RECT  166.224 69.036 166.248 69.12 ;
    END
  END x2[144]
  PIN x2[145]
    DIRECTION OUTPUT ;
    USE SIGNAL ;
    PORT
      LAYER M5 ;
        RECT  166.464 69.036 166.488 69.12 ;
    END
  END x2[145]
  PIN x2[146]
    DIRECTION OUTPUT ;
    USE SIGNAL ;
    PORT
      LAYER M5 ;
        RECT  166.704 69.036 166.728 69.12 ;
    END
  END x2[146]
  PIN x2[147]
    DIRECTION OUTPUT ;
    USE SIGNAL ;
    PORT
      LAYER M5 ;
        RECT  166.944 69.036 166.968 69.12 ;
    END
  END x2[147]
  PIN x2[148]
    DIRECTION OUTPUT ;
    USE SIGNAL ;
    PORT
      LAYER M5 ;
        RECT  167.184 69.036 167.208 69.12 ;
    END
  END x2[148]
  PIN x2[149]
    DIRECTION OUTPUT ;
    USE SIGNAL ;
    PORT
      LAYER M5 ;
        RECT  167.424 69.036 167.448 69.12 ;
    END
  END x2[149]
  PIN x2[14]
    DIRECTION OUTPUT ;
    USE SIGNAL ;
    PORT
      LAYER M5 ;
        RECT  135.408 69.036 135.432 69.12 ;
    END
  END x2[14]
  PIN x2[150]
    DIRECTION OUTPUT ;
    USE SIGNAL ;
    PORT
      LAYER M5 ;
        RECT  167.664 69.036 167.688 69.12 ;
    END
  END x2[150]
  PIN x2[151]
    DIRECTION OUTPUT ;
    USE SIGNAL ;
    PORT
      LAYER M5 ;
        RECT  167.856 69.036 167.88 69.12 ;
    END
  END x2[151]
  PIN x2[152]
    DIRECTION OUTPUT ;
    USE SIGNAL ;
    PORT
      LAYER M5 ;
        RECT  168.096 69.036 168.12 69.12 ;
    END
  END x2[152]
  PIN x2[153]
    DIRECTION OUTPUT ;
    USE SIGNAL ;
    PORT
      LAYER M5 ;
        RECT  168.336 69.036 168.36 69.12 ;
    END
  END x2[153]
  PIN x2[154]
    DIRECTION OUTPUT ;
    USE SIGNAL ;
    PORT
      LAYER M5 ;
        RECT  168.576 69.036 168.6 69.12 ;
    END
  END x2[154]
  PIN x2[155]
    DIRECTION OUTPUT ;
    USE SIGNAL ;
    PORT
      LAYER M5 ;
        RECT  168.816 69.036 168.84 69.12 ;
    END
  END x2[155]
  PIN x2[156]
    DIRECTION OUTPUT ;
    USE SIGNAL ;
    PORT
      LAYER M5 ;
        RECT  169.056 69.036 169.08 69.12 ;
    END
  END x2[156]
  PIN x2[157]
    DIRECTION OUTPUT ;
    USE SIGNAL ;
    PORT
      LAYER M5 ;
        RECT  169.296 69.036 169.32 69.12 ;
    END
  END x2[157]
  PIN x2[158]
    DIRECTION OUTPUT ;
    USE SIGNAL ;
    PORT
      LAYER M5 ;
        RECT  169.536 69.036 169.56 69.12 ;
    END
  END x2[158]
  PIN x2[159]
    DIRECTION OUTPUT ;
    USE SIGNAL ;
    PORT
      LAYER M5 ;
        RECT  169.776 69.036 169.8 69.12 ;
    END
  END x2[159]
  PIN x2[15]
    DIRECTION OUTPUT ;
    USE SIGNAL ;
    PORT
      LAYER M5 ;
        RECT  135.648 69.036 135.672 69.12 ;
    END
  END x2[15]
  PIN x2[160]
    DIRECTION OUTPUT ;
    USE SIGNAL ;
    PORT
      LAYER M5 ;
        RECT  170.016 69.036 170.04 69.12 ;
    END
  END x2[160]
  PIN x2[161]
    DIRECTION OUTPUT ;
    USE SIGNAL ;
    PORT
      LAYER M5 ;
        RECT  170.256 69.036 170.28 69.12 ;
    END
  END x2[161]
  PIN x2[162]
    DIRECTION OUTPUT ;
    USE SIGNAL ;
    PORT
      LAYER M5 ;
        RECT  170.496 69.036 170.52 69.12 ;
    END
  END x2[162]
  PIN x2[163]
    DIRECTION OUTPUT ;
    USE SIGNAL ;
    PORT
      LAYER M5 ;
        RECT  170.736 69.036 170.76 69.12 ;
    END
  END x2[163]
  PIN x2[164]
    DIRECTION OUTPUT ;
    USE SIGNAL ;
    PORT
      LAYER M5 ;
        RECT  170.976 69.036 171 69.12 ;
    END
  END x2[164]
  PIN x2[165]
    DIRECTION OUTPUT ;
    USE SIGNAL ;
    PORT
      LAYER M5 ;
        RECT  171.216 69.036 171.24 69.12 ;
    END
  END x2[165]
  PIN x2[166]
    DIRECTION OUTPUT ;
    USE SIGNAL ;
    PORT
      LAYER M5 ;
        RECT  171.456 69.036 171.48 69.12 ;
    END
  END x2[166]
  PIN x2[167]
    DIRECTION OUTPUT ;
    USE SIGNAL ;
    PORT
      LAYER M5 ;
        RECT  171.648 69.036 171.672 69.12 ;
    END
  END x2[167]
  PIN x2[168]
    DIRECTION OUTPUT ;
    USE SIGNAL ;
    PORT
      LAYER M5 ;
        RECT  171.888 69.036 171.912 69.12 ;
    END
  END x2[168]
  PIN x2[169]
    DIRECTION OUTPUT ;
    USE SIGNAL ;
    PORT
      LAYER M5 ;
        RECT  172.128 69.036 172.152 69.12 ;
    END
  END x2[169]
  PIN x2[16]
    DIRECTION OUTPUT ;
    USE SIGNAL ;
    PORT
      LAYER M5 ;
        RECT  135.888 69.036 135.912 69.12 ;
    END
  END x2[16]
  PIN x2[170]
    DIRECTION OUTPUT ;
    USE SIGNAL ;
    PORT
      LAYER M5 ;
        RECT  172.368 69.036 172.392 69.12 ;
    END
  END x2[170]
  PIN x2[171]
    DIRECTION OUTPUT ;
    USE SIGNAL ;
    PORT
      LAYER M5 ;
        RECT  172.608 69.036 172.632 69.12 ;
    END
  END x2[171]
  PIN x2[172]
    DIRECTION OUTPUT ;
    USE SIGNAL ;
    PORT
      LAYER M5 ;
        RECT  172.848 69.036 172.872 69.12 ;
    END
  END x2[172]
  PIN x2[173]
    DIRECTION OUTPUT ;
    USE SIGNAL ;
    PORT
      LAYER M5 ;
        RECT  173.088 69.036 173.112 69.12 ;
    END
  END x2[173]
  PIN x2[174]
    DIRECTION OUTPUT ;
    USE SIGNAL ;
    PORT
      LAYER M5 ;
        RECT  173.328 69.036 173.352 69.12 ;
    END
  END x2[174]
  PIN x2[175]
    DIRECTION OUTPUT ;
    USE SIGNAL ;
    PORT
      LAYER M5 ;
        RECT  173.568 69.036 173.592 69.12 ;
    END
  END x2[175]
  PIN x2[176]
    DIRECTION OUTPUT ;
    USE SIGNAL ;
    PORT
      LAYER M5 ;
        RECT  173.808 69.036 173.832 69.12 ;
    END
  END x2[176]
  PIN x2[177]
    DIRECTION OUTPUT ;
    USE SIGNAL ;
    PORT
      LAYER M5 ;
        RECT  174.048 69.036 174.072 69.12 ;
    END
  END x2[177]
  PIN x2[178]
    DIRECTION OUTPUT ;
    USE SIGNAL ;
    PORT
      LAYER M5 ;
        RECT  174.288 69.036 174.312 69.12 ;
    END
  END x2[178]
  PIN x2[179]
    DIRECTION OUTPUT ;
    USE SIGNAL ;
    PORT
      LAYER M5 ;
        RECT  174.528 69.036 174.552 69.12 ;
    END
  END x2[179]
  PIN x2[17]
    DIRECTION OUTPUT ;
    USE SIGNAL ;
    PORT
      LAYER M5 ;
        RECT  136.128 69.036 136.152 69.12 ;
    END
  END x2[17]
  PIN x2[180]
    DIRECTION OUTPUT ;
    USE SIGNAL ;
    PORT
      LAYER M5 ;
        RECT  174.768 69.036 174.792 69.12 ;
    END
  END x2[180]
  PIN x2[181]
    DIRECTION OUTPUT ;
    USE SIGNAL ;
    PORT
      LAYER M5 ;
        RECT  175.008 69.036 175.032 69.12 ;
    END
  END x2[181]
  PIN x2[182]
    DIRECTION OUTPUT ;
    USE SIGNAL ;
    PORT
      LAYER M5 ;
        RECT  175.248 69.036 175.272 69.12 ;
    END
  END x2[182]
  PIN x2[183]
    DIRECTION OUTPUT ;
    USE SIGNAL ;
    PORT
      LAYER M5 ;
        RECT  175.44 69.036 175.464 69.12 ;
    END
  END x2[183]
  PIN x2[184]
    DIRECTION OUTPUT ;
    USE SIGNAL ;
    PORT
      LAYER M5 ;
        RECT  175.68 69.036 175.704 69.12 ;
    END
  END x2[184]
  PIN x2[185]
    DIRECTION OUTPUT ;
    USE SIGNAL ;
    PORT
      LAYER M5 ;
        RECT  175.92 69.036 175.944 69.12 ;
    END
  END x2[185]
  PIN x2[186]
    DIRECTION OUTPUT ;
    USE SIGNAL ;
    PORT
      LAYER M5 ;
        RECT  176.16 69.036 176.184 69.12 ;
    END
  END x2[186]
  PIN x2[187]
    DIRECTION OUTPUT ;
    USE SIGNAL ;
    PORT
      LAYER M5 ;
        RECT  176.4 69.036 176.424 69.12 ;
    END
  END x2[187]
  PIN x2[188]
    DIRECTION OUTPUT ;
    USE SIGNAL ;
    PORT
      LAYER M5 ;
        RECT  176.64 69.036 176.664 69.12 ;
    END
  END x2[188]
  PIN x2[189]
    DIRECTION OUTPUT ;
    USE SIGNAL ;
    PORT
      LAYER M5 ;
        RECT  176.88 69.036 176.904 69.12 ;
    END
  END x2[189]
  PIN x2[18]
    DIRECTION OUTPUT ;
    USE SIGNAL ;
    PORT
      LAYER M5 ;
        RECT  136.368 69.036 136.392 69.12 ;
    END
  END x2[18]
  PIN x2[190]
    DIRECTION OUTPUT ;
    USE SIGNAL ;
    PORT
      LAYER M5 ;
        RECT  177.12 69.036 177.144 69.12 ;
    END
  END x2[190]
  PIN x2[191]
    DIRECTION OUTPUT ;
    USE SIGNAL ;
    PORT
      LAYER M5 ;
        RECT  177.36 69.036 177.384 69.12 ;
    END
  END x2[191]
  PIN x2[192]
    DIRECTION OUTPUT ;
    USE SIGNAL ;
    PORT
      LAYER M5 ;
        RECT  177.6 69.036 177.624 69.12 ;
    END
  END x2[192]
  PIN x2[193]
    DIRECTION OUTPUT ;
    USE SIGNAL ;
    PORT
      LAYER M5 ;
        RECT  177.84 69.036 177.864 69.12 ;
    END
  END x2[193]
  PIN x2[194]
    DIRECTION OUTPUT ;
    USE SIGNAL ;
    PORT
      LAYER M5 ;
        RECT  178.08 69.036 178.104 69.12 ;
    END
  END x2[194]
  PIN x2[195]
    DIRECTION OUTPUT ;
    USE SIGNAL ;
    PORT
      LAYER M5 ;
        RECT  178.32 69.036 178.344 69.12 ;
    END
  END x2[195]
  PIN x2[196]
    DIRECTION OUTPUT ;
    USE SIGNAL ;
    PORT
      LAYER M5 ;
        RECT  178.56 69.036 178.584 69.12 ;
    END
  END x2[196]
  PIN x2[197]
    DIRECTION OUTPUT ;
    USE SIGNAL ;
    PORT
      LAYER M5 ;
        RECT  178.8 69.036 178.824 69.12 ;
    END
  END x2[197]
  PIN x2[198]
    DIRECTION OUTPUT ;
    USE SIGNAL ;
    PORT
      LAYER M5 ;
        RECT  179.04 69.036 179.064 69.12 ;
    END
  END x2[198]
  PIN x2[199]
    DIRECTION OUTPUT ;
    USE SIGNAL ;
    PORT
      LAYER M5 ;
        RECT  179.232 69.036 179.256 69.12 ;
    END
  END x2[199]
  PIN x2[19]
    DIRECTION OUTPUT ;
    USE SIGNAL ;
    PORT
      LAYER M5 ;
        RECT  136.608 69.036 136.632 69.12 ;
    END
  END x2[19]
  PIN x2[1]
    DIRECTION OUTPUT ;
    USE SIGNAL ;
    PORT
      LAYER M5 ;
        RECT  132.336 69.036 132.36 69.12 ;
    END
  END x2[1]
  PIN x2[200]
    DIRECTION OUTPUT ;
    USE SIGNAL ;
    PORT
      LAYER M5 ;
        RECT  179.472 69.036 179.496 69.12 ;
    END
  END x2[200]
  PIN x2[201]
    DIRECTION OUTPUT ;
    USE SIGNAL ;
    PORT
      LAYER M5 ;
        RECT  179.712 69.036 179.736 69.12 ;
    END
  END x2[201]
  PIN x2[202]
    DIRECTION OUTPUT ;
    USE SIGNAL ;
    PORT
      LAYER M5 ;
        RECT  179.952 69.036 179.976 69.12 ;
    END
  END x2[202]
  PIN x2[203]
    DIRECTION OUTPUT ;
    USE SIGNAL ;
    PORT
      LAYER M5 ;
        RECT  180.192 69.036 180.216 69.12 ;
    END
  END x2[203]
  PIN x2[204]
    DIRECTION OUTPUT ;
    USE SIGNAL ;
    PORT
      LAYER M5 ;
        RECT  180.432 69.036 180.456 69.12 ;
    END
  END x2[204]
  PIN x2[205]
    DIRECTION OUTPUT ;
    USE SIGNAL ;
    PORT
      LAYER M5 ;
        RECT  180.672 69.036 180.696 69.12 ;
    END
  END x2[205]
  PIN x2[206]
    DIRECTION OUTPUT ;
    USE SIGNAL ;
    PORT
      LAYER M5 ;
        RECT  180.912 69.036 180.936 69.12 ;
    END
  END x2[206]
  PIN x2[207]
    DIRECTION OUTPUT ;
    USE SIGNAL ;
    PORT
      LAYER M5 ;
        RECT  181.152 69.036 181.176 69.12 ;
    END
  END x2[207]
  PIN x2[208]
    DIRECTION OUTPUT ;
    USE SIGNAL ;
    PORT
      LAYER M5 ;
        RECT  181.392 69.036 181.416 69.12 ;
    END
  END x2[208]
  PIN x2[209]
    DIRECTION OUTPUT ;
    USE SIGNAL ;
    PORT
      LAYER M5 ;
        RECT  181.632 69.036 181.656 69.12 ;
    END
  END x2[209]
  PIN x2[20]
    DIRECTION OUTPUT ;
    USE SIGNAL ;
    PORT
      LAYER M5 ;
        RECT  136.848 69.036 136.872 69.12 ;
    END
  END x2[20]
  PIN x2[210]
    DIRECTION OUTPUT ;
    USE SIGNAL ;
    PORT
      LAYER M5 ;
        RECT  181.872 69.036 181.896 69.12 ;
    END
  END x2[210]
  PIN x2[211]
    DIRECTION OUTPUT ;
    USE SIGNAL ;
    PORT
      LAYER M5 ;
        RECT  182.112 69.036 182.136 69.12 ;
    END
  END x2[211]
  PIN x2[212]
    DIRECTION OUTPUT ;
    USE SIGNAL ;
    PORT
      LAYER M5 ;
        RECT  182.352 69.036 182.376 69.12 ;
    END
  END x2[212]
  PIN x2[213]
    DIRECTION OUTPUT ;
    USE SIGNAL ;
    PORT
      LAYER M5 ;
        RECT  182.592 69.036 182.616 69.12 ;
    END
  END x2[213]
  PIN x2[214]
    DIRECTION OUTPUT ;
    USE SIGNAL ;
    PORT
      LAYER M5 ;
        RECT  182.832 69.036 182.856 69.12 ;
    END
  END x2[214]
  PIN x2[215]
    DIRECTION OUTPUT ;
    USE SIGNAL ;
    PORT
      LAYER M5 ;
        RECT  183.024 69.036 183.048 69.12 ;
    END
  END x2[215]
  PIN x2[216]
    DIRECTION OUTPUT ;
    USE SIGNAL ;
    PORT
      LAYER M5 ;
        RECT  183.264 69.036 183.288 69.12 ;
    END
  END x2[216]
  PIN x2[217]
    DIRECTION OUTPUT ;
    USE SIGNAL ;
    PORT
      LAYER M5 ;
        RECT  183.504 69.036 183.528 69.12 ;
    END
  END x2[217]
  PIN x2[218]
    DIRECTION OUTPUT ;
    USE SIGNAL ;
    PORT
      LAYER M5 ;
        RECT  183.744 69.036 183.768 69.12 ;
    END
  END x2[218]
  PIN x2[219]
    DIRECTION OUTPUT ;
    USE SIGNAL ;
    PORT
      LAYER M5 ;
        RECT  183.984 69.036 184.008 69.12 ;
    END
  END x2[219]
  PIN x2[21]
    DIRECTION OUTPUT ;
    USE SIGNAL ;
    PORT
      LAYER M5 ;
        RECT  137.088 69.036 137.112 69.12 ;
    END
  END x2[21]
  PIN x2[220]
    DIRECTION OUTPUT ;
    USE SIGNAL ;
    PORT
      LAYER M5 ;
        RECT  184.224 69.036 184.248 69.12 ;
    END
  END x2[220]
  PIN x2[221]
    DIRECTION OUTPUT ;
    USE SIGNAL ;
    PORT
      LAYER M5 ;
        RECT  184.464 69.036 184.488 69.12 ;
    END
  END x2[221]
  PIN x2[222]
    DIRECTION OUTPUT ;
    USE SIGNAL ;
    PORT
      LAYER M5 ;
        RECT  184.704 69.036 184.728 69.12 ;
    END
  END x2[222]
  PIN x2[223]
    DIRECTION OUTPUT ;
    USE SIGNAL ;
    PORT
      LAYER M5 ;
        RECT  184.944 69.036 184.968 69.12 ;
    END
  END x2[223]
  PIN x2[224]
    DIRECTION OUTPUT ;
    USE SIGNAL ;
    PORT
      LAYER M5 ;
        RECT  185.184 69.036 185.208 69.12 ;
    END
  END x2[224]
  PIN x2[225]
    DIRECTION OUTPUT ;
    USE SIGNAL ;
    PORT
      LAYER M5 ;
        RECT  185.424 69.036 185.448 69.12 ;
    END
  END x2[225]
  PIN x2[226]
    DIRECTION OUTPUT ;
    USE SIGNAL ;
    PORT
      LAYER M5 ;
        RECT  185.664 69.036 185.688 69.12 ;
    END
  END x2[226]
  PIN x2[227]
    DIRECTION OUTPUT ;
    USE SIGNAL ;
    PORT
      LAYER M5 ;
        RECT  185.904 69.036 185.928 69.12 ;
    END
  END x2[227]
  PIN x2[228]
    DIRECTION OUTPUT ;
    USE SIGNAL ;
    PORT
      LAYER M5 ;
        RECT  186.144 69.036 186.168 69.12 ;
    END
  END x2[228]
  PIN x2[229]
    DIRECTION OUTPUT ;
    USE SIGNAL ;
    PORT
      LAYER M5 ;
        RECT  186.384 69.036 186.408 69.12 ;
    END
  END x2[229]
  PIN x2[22]
    DIRECTION OUTPUT ;
    USE SIGNAL ;
    PORT
      LAYER M5 ;
        RECT  137.328 69.036 137.352 69.12 ;
    END
  END x2[22]
  PIN x2[230]
    DIRECTION OUTPUT ;
    USE SIGNAL ;
    PORT
      LAYER M5 ;
        RECT  186.624 69.036 186.648 69.12 ;
    END
  END x2[230]
  PIN x2[231]
    DIRECTION OUTPUT ;
    USE SIGNAL ;
    PORT
      LAYER M5 ;
        RECT  186.816 69.036 186.84 69.12 ;
    END
  END x2[231]
  PIN x2[232]
    DIRECTION OUTPUT ;
    USE SIGNAL ;
    PORT
      LAYER M5 ;
        RECT  187.056 69.036 187.08 69.12 ;
    END
  END x2[232]
  PIN x2[233]
    DIRECTION OUTPUT ;
    USE SIGNAL ;
    PORT
      LAYER M5 ;
        RECT  187.296 69.036 187.32 69.12 ;
    END
  END x2[233]
  PIN x2[234]
    DIRECTION OUTPUT ;
    USE SIGNAL ;
    PORT
      LAYER M5 ;
        RECT  187.536 69.036 187.56 69.12 ;
    END
  END x2[234]
  PIN x2[235]
    DIRECTION OUTPUT ;
    USE SIGNAL ;
    PORT
      LAYER M5 ;
        RECT  187.776 69.036 187.8 69.12 ;
    END
  END x2[235]
  PIN x2[236]
    DIRECTION OUTPUT ;
    USE SIGNAL ;
    PORT
      LAYER M5 ;
        RECT  188.016 69.036 188.04 69.12 ;
    END
  END x2[236]
  PIN x2[237]
    DIRECTION OUTPUT ;
    USE SIGNAL ;
    PORT
      LAYER M5 ;
        RECT  188.256 69.036 188.28 69.12 ;
    END
  END x2[237]
  PIN x2[238]
    DIRECTION OUTPUT ;
    USE SIGNAL ;
    PORT
      LAYER M5 ;
        RECT  188.496 69.036 188.52 69.12 ;
    END
  END x2[238]
  PIN x2[239]
    DIRECTION OUTPUT ;
    USE SIGNAL ;
    PORT
      LAYER M5 ;
        RECT  188.736 69.036 188.76 69.12 ;
    END
  END x2[239]
  PIN x2[23]
    DIRECTION OUTPUT ;
    USE SIGNAL ;
    PORT
      LAYER M5 ;
        RECT  137.568 69.036 137.592 69.12 ;
    END
  END x2[23]
  PIN x2[240]
    DIRECTION OUTPUT ;
    USE SIGNAL ;
    PORT
      LAYER M5 ;
        RECT  188.976 69.036 189 69.12 ;
    END
  END x2[240]
  PIN x2[241]
    DIRECTION OUTPUT ;
    USE SIGNAL ;
    PORT
      LAYER M5 ;
        RECT  189.216 69.036 189.24 69.12 ;
    END
  END x2[241]
  PIN x2[242]
    DIRECTION OUTPUT ;
    USE SIGNAL ;
    PORT
      LAYER M5 ;
        RECT  189.456 69.036 189.48 69.12 ;
    END
  END x2[242]
  PIN x2[243]
    DIRECTION OUTPUT ;
    USE SIGNAL ;
    PORT
      LAYER M5 ;
        RECT  189.696 69.036 189.72 69.12 ;
    END
  END x2[243]
  PIN x2[244]
    DIRECTION OUTPUT ;
    USE SIGNAL ;
    PORT
      LAYER M5 ;
        RECT  189.936 69.036 189.96 69.12 ;
    END
  END x2[244]
  PIN x2[245]
    DIRECTION OUTPUT ;
    USE SIGNAL ;
    PORT
      LAYER M5 ;
        RECT  190.176 69.036 190.2 69.12 ;
    END
  END x2[245]
  PIN x2[246]
    DIRECTION OUTPUT ;
    USE SIGNAL ;
    PORT
      LAYER M5 ;
        RECT  190.416 69.036 190.44 69.12 ;
    END
  END x2[246]
  PIN x2[247]
    DIRECTION OUTPUT ;
    USE SIGNAL ;
    PORT
      LAYER M5 ;
        RECT  190.608 69.036 190.632 69.12 ;
    END
  END x2[247]
  PIN x2[248]
    DIRECTION OUTPUT ;
    USE SIGNAL ;
    PORT
      LAYER M5 ;
        RECT  190.848 69.036 190.872 69.12 ;
    END
  END x2[248]
  PIN x2[249]
    DIRECTION OUTPUT ;
    USE SIGNAL ;
    PORT
      LAYER M5 ;
        RECT  191.088 69.036 191.112 69.12 ;
    END
  END x2[249]
  PIN x2[24]
    DIRECTION OUTPUT ;
    USE SIGNAL ;
    PORT
      LAYER M5 ;
        RECT  137.76 69.036 137.784 69.12 ;
    END
  END x2[24]
  PIN x2[250]
    DIRECTION OUTPUT ;
    USE SIGNAL ;
    PORT
      LAYER M5 ;
        RECT  191.328 69.036 191.352 69.12 ;
    END
  END x2[250]
  PIN x2[251]
    DIRECTION OUTPUT ;
    USE SIGNAL ;
    PORT
      LAYER M5 ;
        RECT  191.568 69.036 191.592 69.12 ;
    END
  END x2[251]
  PIN x2[252]
    DIRECTION OUTPUT ;
    USE SIGNAL ;
    PORT
      LAYER M5 ;
        RECT  191.808 69.036 191.832 69.12 ;
    END
  END x2[252]
  PIN x2[253]
    DIRECTION OUTPUT ;
    USE SIGNAL ;
    PORT
      LAYER M5 ;
        RECT  192.048 69.036 192.072 69.12 ;
    END
  END x2[253]
  PIN x2[254]
    DIRECTION OUTPUT ;
    USE SIGNAL ;
    PORT
      LAYER M5 ;
        RECT  192.288 69.036 192.312 69.12 ;
    END
  END x2[254]
  PIN x2[255]
    DIRECTION OUTPUT ;
    USE SIGNAL ;
    PORT
      LAYER M5 ;
        RECT  192.528 69.036 192.552 69.12 ;
    END
  END x2[255]
  PIN x2[256]
    DIRECTION OUTPUT ;
    USE SIGNAL ;
    PORT
      LAYER M5 ;
        RECT  192.768 69.036 192.792 69.12 ;
    END
  END x2[256]
  PIN x2[257]
    DIRECTION OUTPUT ;
    USE SIGNAL ;
    PORT
      LAYER M5 ;
        RECT  193.008 69.036 193.032 69.12 ;
    END
  END x2[257]
  PIN x2[258]
    DIRECTION OUTPUT ;
    USE SIGNAL ;
    PORT
      LAYER M5 ;
        RECT  193.248 69.036 193.272 69.12 ;
    END
  END x2[258]
  PIN x2[259]
    DIRECTION OUTPUT ;
    USE SIGNAL ;
    PORT
      LAYER M5 ;
        RECT  193.488 69.036 193.512 69.12 ;
    END
  END x2[259]
  PIN x2[25]
    DIRECTION OUTPUT ;
    USE SIGNAL ;
    PORT
      LAYER M5 ;
        RECT  138 69.036 138.024 69.12 ;
    END
  END x2[25]
  PIN x2[260]
    DIRECTION OUTPUT ;
    USE SIGNAL ;
    PORT
      LAYER M5 ;
        RECT  193.728 69.036 193.752 69.12 ;
    END
  END x2[260]
  PIN x2[261]
    DIRECTION OUTPUT ;
    USE SIGNAL ;
    PORT
      LAYER M5 ;
        RECT  193.968 69.036 193.992 69.12 ;
    END
  END x2[261]
  PIN x2[262]
    DIRECTION OUTPUT ;
    USE SIGNAL ;
    PORT
      LAYER M5 ;
        RECT  194.16 69.036 194.184 69.12 ;
    END
  END x2[262]
  PIN x2[263]
    DIRECTION OUTPUT ;
    USE SIGNAL ;
    PORT
      LAYER M5 ;
        RECT  194.4 69.036 194.424 69.12 ;
    END
  END x2[263]
  PIN x2[264]
    DIRECTION OUTPUT ;
    USE SIGNAL ;
    PORT
      LAYER M5 ;
        RECT  194.64 69.036 194.664 69.12 ;
    END
  END x2[264]
  PIN x2[265]
    DIRECTION OUTPUT ;
    USE SIGNAL ;
    PORT
      LAYER M5 ;
        RECT  194.88 69.036 194.904 69.12 ;
    END
  END x2[265]
  PIN x2[266]
    DIRECTION OUTPUT ;
    USE SIGNAL ;
    PORT
      LAYER M5 ;
        RECT  195.12 69.036 195.144 69.12 ;
    END
  END x2[266]
  PIN x2[267]
    DIRECTION OUTPUT ;
    USE SIGNAL ;
    PORT
      LAYER M5 ;
        RECT  195.36 69.036 195.384 69.12 ;
    END
  END x2[267]
  PIN x2[268]
    DIRECTION OUTPUT ;
    USE SIGNAL ;
    PORT
      LAYER M5 ;
        RECT  195.6 69.036 195.624 69.12 ;
    END
  END x2[268]
  PIN x2[269]
    DIRECTION OUTPUT ;
    USE SIGNAL ;
    PORT
      LAYER M5 ;
        RECT  195.84 69.036 195.864 69.12 ;
    END
  END x2[269]
  PIN x2[26]
    DIRECTION OUTPUT ;
    USE SIGNAL ;
    PORT
      LAYER M5 ;
        RECT  138.24 69.036 138.264 69.12 ;
    END
  END x2[26]
  PIN x2[270]
    DIRECTION OUTPUT ;
    USE SIGNAL ;
    PORT
      LAYER M5 ;
        RECT  196.08 69.036 196.104 69.12 ;
    END
  END x2[270]
  PIN x2[271]
    DIRECTION OUTPUT ;
    USE SIGNAL ;
    PORT
      LAYER M5 ;
        RECT  196.32 69.036 196.344 69.12 ;
    END
  END x2[271]
  PIN x2[272]
    DIRECTION OUTPUT ;
    USE SIGNAL ;
    PORT
      LAYER M5 ;
        RECT  196.56 69.036 196.584 69.12 ;
    END
  END x2[272]
  PIN x2[273]
    DIRECTION OUTPUT ;
    USE SIGNAL ;
    PORT
      LAYER M5 ;
        RECT  196.8 69.036 196.824 69.12 ;
    END
  END x2[273]
  PIN x2[274]
    DIRECTION OUTPUT ;
    USE SIGNAL ;
    PORT
      LAYER M5 ;
        RECT  197.04 69.036 197.064 69.12 ;
    END
  END x2[274]
  PIN x2[275]
    DIRECTION OUTPUT ;
    USE SIGNAL ;
    PORT
      LAYER M5 ;
        RECT  197.28 69.036 197.304 69.12 ;
    END
  END x2[275]
  PIN x2[276]
    DIRECTION OUTPUT ;
    USE SIGNAL ;
    PORT
      LAYER M5 ;
        RECT  197.52 69.036 197.544 69.12 ;
    END
  END x2[276]
  PIN x2[277]
    DIRECTION OUTPUT ;
    USE SIGNAL ;
    PORT
      LAYER M5 ;
        RECT  197.76 69.036 197.784 69.12 ;
    END
  END x2[277]
  PIN x2[278]
    DIRECTION OUTPUT ;
    USE SIGNAL ;
    PORT
      LAYER M5 ;
        RECT  197.952 69.036 197.976 69.12 ;
    END
  END x2[278]
  PIN x2[279]
    DIRECTION OUTPUT ;
    USE SIGNAL ;
    PORT
      LAYER M5 ;
        RECT  198.192 69.036 198.216 69.12 ;
    END
  END x2[279]
  PIN x2[27]
    DIRECTION OUTPUT ;
    USE SIGNAL ;
    PORT
      LAYER M5 ;
        RECT  138.48 69.036 138.504 69.12 ;
    END
  END x2[27]
  PIN x2[280]
    DIRECTION OUTPUT ;
    USE SIGNAL ;
    PORT
      LAYER M5 ;
        RECT  198.432 69.036 198.456 69.12 ;
    END
  END x2[280]
  PIN x2[281]
    DIRECTION OUTPUT ;
    USE SIGNAL ;
    PORT
      LAYER M5 ;
        RECT  198.672 69.036 198.696 69.12 ;
    END
  END x2[281]
  PIN x2[282]
    DIRECTION OUTPUT ;
    USE SIGNAL ;
    PORT
      LAYER M5 ;
        RECT  198.912 69.036 198.936 69.12 ;
    END
  END x2[282]
  PIN x2[283]
    DIRECTION OUTPUT ;
    USE SIGNAL ;
    PORT
      LAYER M5 ;
        RECT  199.152 69.036 199.176 69.12 ;
    END
  END x2[283]
  PIN x2[284]
    DIRECTION OUTPUT ;
    USE SIGNAL ;
    PORT
      LAYER M5 ;
        RECT  199.392 69.036 199.416 69.12 ;
    END
  END x2[284]
  PIN x2[285]
    DIRECTION OUTPUT ;
    USE SIGNAL ;
    PORT
      LAYER M5 ;
        RECT  199.632 69.036 199.656 69.12 ;
    END
  END x2[285]
  PIN x2[286]
    DIRECTION OUTPUT ;
    USE SIGNAL ;
    PORT
      LAYER M5 ;
        RECT  199.872 69.036 199.896 69.12 ;
    END
  END x2[286]
  PIN x2[287]
    DIRECTION OUTPUT ;
    USE SIGNAL ;
    PORT
      LAYER M5 ;
        RECT  200.112 69.036 200.136 69.12 ;
    END
  END x2[287]
  PIN x2[288]
    DIRECTION OUTPUT ;
    USE SIGNAL ;
    PORT
      LAYER M5 ;
        RECT  200.352 69.036 200.376 69.12 ;
    END
  END x2[288]
  PIN x2[289]
    DIRECTION OUTPUT ;
    USE SIGNAL ;
    PORT
      LAYER M5 ;
        RECT  200.592 69.036 200.616 69.12 ;
    END
  END x2[289]
  PIN x2[28]
    DIRECTION OUTPUT ;
    USE SIGNAL ;
    PORT
      LAYER M5 ;
        RECT  138.72 69.036 138.744 69.12 ;
    END
  END x2[28]
  PIN x2[290]
    DIRECTION OUTPUT ;
    USE SIGNAL ;
    PORT
      LAYER M5 ;
        RECT  200.832 69.036 200.856 69.12 ;
    END
  END x2[290]
  PIN x2[291]
    DIRECTION OUTPUT ;
    USE SIGNAL ;
    PORT
      LAYER M5 ;
        RECT  201.072 69.036 201.096 69.12 ;
    END
  END x2[291]
  PIN x2[292]
    DIRECTION OUTPUT ;
    USE SIGNAL ;
    PORT
      LAYER M5 ;
        RECT  201.312 69.036 201.336 69.12 ;
    END
  END x2[292]
  PIN x2[293]
    DIRECTION OUTPUT ;
    USE SIGNAL ;
    PORT
      LAYER M5 ;
        RECT  201.552 69.036 201.576 69.12 ;
    END
  END x2[293]
  PIN x2[294]
    DIRECTION OUTPUT ;
    USE SIGNAL ;
    PORT
      LAYER M5 ;
        RECT  201.744 69.036 201.768 69.12 ;
    END
  END x2[294]
  PIN x2[295]
    DIRECTION OUTPUT ;
    USE SIGNAL ;
    PORT
      LAYER M5 ;
        RECT  201.984 69.036 202.008 69.12 ;
    END
  END x2[295]
  PIN x2[296]
    DIRECTION OUTPUT ;
    USE SIGNAL ;
    PORT
      LAYER M5 ;
        RECT  202.224 69.036 202.248 69.12 ;
    END
  END x2[296]
  PIN x2[297]
    DIRECTION OUTPUT ;
    USE SIGNAL ;
    PORT
      LAYER M5 ;
        RECT  202.464 69.036 202.488 69.12 ;
    END
  END x2[297]
  PIN x2[298]
    DIRECTION OUTPUT ;
    USE SIGNAL ;
    PORT
      LAYER M5 ;
        RECT  202.704 69.036 202.728 69.12 ;
    END
  END x2[298]
  PIN x2[299]
    DIRECTION OUTPUT ;
    USE SIGNAL ;
    PORT
      LAYER M5 ;
        RECT  202.944 69.036 202.968 69.12 ;
    END
  END x2[299]
  PIN x2[29]
    DIRECTION OUTPUT ;
    USE SIGNAL ;
    PORT
      LAYER M5 ;
        RECT  138.96 69.036 138.984 69.12 ;
    END
  END x2[29]
  PIN x2[2]
    DIRECTION OUTPUT ;
    USE SIGNAL ;
    PORT
      LAYER M5 ;
        RECT  132.576 69.036 132.6 69.12 ;
    END
  END x2[2]
  PIN x2[300]
    DIRECTION OUTPUT ;
    USE SIGNAL ;
    PORT
      LAYER M5 ;
        RECT  203.184 69.036 203.208 69.12 ;
    END
  END x2[300]
  PIN x2[301]
    DIRECTION OUTPUT ;
    USE SIGNAL ;
    PORT
      LAYER M5 ;
        RECT  203.424 69.036 203.448 69.12 ;
    END
  END x2[301]
  PIN x2[302]
    DIRECTION OUTPUT ;
    USE SIGNAL ;
    PORT
      LAYER M5 ;
        RECT  203.664 69.036 203.688 69.12 ;
    END
  END x2[302]
  PIN x2[303]
    DIRECTION OUTPUT ;
    USE SIGNAL ;
    PORT
      LAYER M5 ;
        RECT  203.904 69.036 203.928 69.12 ;
    END
  END x2[303]
  PIN x2[304]
    DIRECTION OUTPUT ;
    USE SIGNAL ;
    PORT
      LAYER M5 ;
        RECT  204.144 69.036 204.168 69.12 ;
    END
  END x2[304]
  PIN x2[305]
    DIRECTION OUTPUT ;
    USE SIGNAL ;
    PORT
      LAYER M5 ;
        RECT  204.384 69.036 204.408 69.12 ;
    END
  END x2[305]
  PIN x2[306]
    DIRECTION OUTPUT ;
    USE SIGNAL ;
    PORT
      LAYER M5 ;
        RECT  204.624 69.036 204.648 69.12 ;
    END
  END x2[306]
  PIN x2[307]
    DIRECTION OUTPUT ;
    USE SIGNAL ;
    PORT
      LAYER M5 ;
        RECT  204.864 69.036 204.888 69.12 ;
    END
  END x2[307]
  PIN x2[308]
    DIRECTION OUTPUT ;
    USE SIGNAL ;
    PORT
      LAYER M5 ;
        RECT  205.104 69.036 205.128 69.12 ;
    END
  END x2[308]
  PIN x2[309]
    DIRECTION OUTPUT ;
    USE SIGNAL ;
    PORT
      LAYER M5 ;
        RECT  205.344 69.036 205.368 69.12 ;
    END
  END x2[309]
  PIN x2[30]
    DIRECTION OUTPUT ;
    USE SIGNAL ;
    PORT
      LAYER M5 ;
        RECT  139.2 69.036 139.224 69.12 ;
    END
  END x2[30]
  PIN x2[310]
    DIRECTION OUTPUT ;
    USE SIGNAL ;
    PORT
      LAYER M5 ;
        RECT  205.536 69.036 205.56 69.12 ;
    END
  END x2[310]
  PIN x2[311]
    DIRECTION OUTPUT ;
    USE SIGNAL ;
    PORT
      LAYER M5 ;
        RECT  205.776 69.036 205.8 69.12 ;
    END
  END x2[311]
  PIN x2[312]
    DIRECTION OUTPUT ;
    USE SIGNAL ;
    PORT
      LAYER M5 ;
        RECT  206.016 69.036 206.04 69.12 ;
    END
  END x2[312]
  PIN x2[313]
    DIRECTION OUTPUT ;
    USE SIGNAL ;
    PORT
      LAYER M5 ;
        RECT  206.256 69.036 206.28 69.12 ;
    END
  END x2[313]
  PIN x2[314]
    DIRECTION OUTPUT ;
    USE SIGNAL ;
    PORT
      LAYER M5 ;
        RECT  206.496 69.036 206.52 69.12 ;
    END
  END x2[314]
  PIN x2[315]
    DIRECTION OUTPUT ;
    USE SIGNAL ;
    PORT
      LAYER M5 ;
        RECT  206.736 69.036 206.76 69.12 ;
    END
  END x2[315]
  PIN x2[316]
    DIRECTION OUTPUT ;
    USE SIGNAL ;
    PORT
      LAYER M5 ;
        RECT  206.976 69.036 207 69.12 ;
    END
  END x2[316]
  PIN x2[317]
    DIRECTION OUTPUT ;
    USE SIGNAL ;
    PORT
      LAYER M5 ;
        RECT  207.216 69.036 207.24 69.12 ;
    END
  END x2[317]
  PIN x2[318]
    DIRECTION OUTPUT ;
    USE SIGNAL ;
    PORT
      LAYER M5 ;
        RECT  207.456 69.036 207.48 69.12 ;
    END
  END x2[318]
  PIN x2[319]
    DIRECTION OUTPUT ;
    USE SIGNAL ;
    PORT
      LAYER M5 ;
        RECT  207.696 69.036 207.72 69.12 ;
    END
  END x2[319]
  PIN x2[31]
    DIRECTION OUTPUT ;
    USE SIGNAL ;
    PORT
      LAYER M5 ;
        RECT  139.44 69.036 139.464 69.12 ;
    END
  END x2[31]
  PIN x2[320]
    DIRECTION OUTPUT ;
    USE SIGNAL ;
    PORT
      LAYER M5 ;
        RECT  207.936 69.036 207.96 69.12 ;
    END
  END x2[320]
  PIN x2[321]
    DIRECTION OUTPUT ;
    USE SIGNAL ;
    PORT
      LAYER M5 ;
        RECT  208.176 69.036 208.2 69.12 ;
    END
  END x2[321]
  PIN x2[322]
    DIRECTION OUTPUT ;
    USE SIGNAL ;
    PORT
      LAYER M5 ;
        RECT  208.416 69.036 208.44 69.12 ;
    END
  END x2[322]
  PIN x2[323]
    DIRECTION OUTPUT ;
    USE SIGNAL ;
    PORT
      LAYER M5 ;
        RECT  208.656 69.036 208.68 69.12 ;
    END
  END x2[323]
  PIN x2[324]
    DIRECTION OUTPUT ;
    USE SIGNAL ;
    PORT
      LAYER M5 ;
        RECT  208.896 69.036 208.92 69.12 ;
    END
  END x2[324]
  PIN x2[325]
    DIRECTION OUTPUT ;
    USE SIGNAL ;
    PORT
      LAYER M5 ;
        RECT  209.136 69.036 209.16 69.12 ;
    END
  END x2[325]
  PIN x2[326]
    DIRECTION OUTPUT ;
    USE SIGNAL ;
    PORT
      LAYER M5 ;
        RECT  209.328 69.036 209.352 69.12 ;
    END
  END x2[326]
  PIN x2[327]
    DIRECTION OUTPUT ;
    USE SIGNAL ;
    PORT
      LAYER M5 ;
        RECT  209.568 69.036 209.592 69.12 ;
    END
  END x2[327]
  PIN x2[328]
    DIRECTION OUTPUT ;
    USE SIGNAL ;
    PORT
      LAYER M5 ;
        RECT  209.808 69.036 209.832 69.12 ;
    END
  END x2[328]
  PIN x2[329]
    DIRECTION OUTPUT ;
    USE SIGNAL ;
    PORT
      LAYER M5 ;
        RECT  210.048 69.036 210.072 69.12 ;
    END
  END x2[329]
  PIN x2[32]
    DIRECTION OUTPUT ;
    USE SIGNAL ;
    PORT
      LAYER M5 ;
        RECT  139.68 69.036 139.704 69.12 ;
    END
  END x2[32]
  PIN x2[330]
    DIRECTION OUTPUT ;
    USE SIGNAL ;
    PORT
      LAYER M5 ;
        RECT  210.288 69.036 210.312 69.12 ;
    END
  END x2[330]
  PIN x2[331]
    DIRECTION OUTPUT ;
    USE SIGNAL ;
    PORT
      LAYER M5 ;
        RECT  210.528 69.036 210.552 69.12 ;
    END
  END x2[331]
  PIN x2[332]
    DIRECTION OUTPUT ;
    USE SIGNAL ;
    PORT
      LAYER M5 ;
        RECT  210.768 69.036 210.792 69.12 ;
    END
  END x2[332]
  PIN x2[333]
    DIRECTION OUTPUT ;
    USE SIGNAL ;
    PORT
      LAYER M5 ;
        RECT  211.008 69.036 211.032 69.12 ;
    END
  END x2[333]
  PIN x2[334]
    DIRECTION OUTPUT ;
    USE SIGNAL ;
    PORT
      LAYER M5 ;
        RECT  211.248 69.036 211.272 69.12 ;
    END
  END x2[334]
  PIN x2[335]
    DIRECTION OUTPUT ;
    USE SIGNAL ;
    PORT
      LAYER M5 ;
        RECT  211.488 69.036 211.512 69.12 ;
    END
  END x2[335]
  PIN x2[336]
    DIRECTION OUTPUT ;
    USE SIGNAL ;
    PORT
      LAYER M5 ;
        RECT  211.728 69.036 211.752 69.12 ;
    END
  END x2[336]
  PIN x2[337]
    DIRECTION OUTPUT ;
    USE SIGNAL ;
    PORT
      LAYER M5 ;
        RECT  211.968 69.036 211.992 69.12 ;
    END
  END x2[337]
  PIN x2[338]
    DIRECTION OUTPUT ;
    USE SIGNAL ;
    PORT
      LAYER M5 ;
        RECT  212.208 69.036 212.232 69.12 ;
    END
  END x2[338]
  PIN x2[339]
    DIRECTION OUTPUT ;
    USE SIGNAL ;
    PORT
      LAYER M5 ;
        RECT  212.448 69.036 212.472 69.12 ;
    END
  END x2[339]
  PIN x2[33]
    DIRECTION OUTPUT ;
    USE SIGNAL ;
    PORT
      LAYER M5 ;
        RECT  139.92 69.036 139.944 69.12 ;
    END
  END x2[33]
  PIN x2[340]
    DIRECTION OUTPUT ;
    USE SIGNAL ;
    PORT
      LAYER M5 ;
        RECT  212.688 69.036 212.712 69.12 ;
    END
  END x2[340]
  PIN x2[341]
    DIRECTION OUTPUT ;
    USE SIGNAL ;
    PORT
      LAYER M5 ;
        RECT  212.928 69.036 212.952 69.12 ;
    END
  END x2[341]
  PIN x2[342]
    DIRECTION OUTPUT ;
    USE SIGNAL ;
    PORT
      LAYER M5 ;
        RECT  213.12 69.036 213.144 69.12 ;
    END
  END x2[342]
  PIN x2[343]
    DIRECTION OUTPUT ;
    USE SIGNAL ;
    PORT
      LAYER M5 ;
        RECT  213.36 69.036 213.384 69.12 ;
    END
  END x2[343]
  PIN x2[344]
    DIRECTION OUTPUT ;
    USE SIGNAL ;
    PORT
      LAYER M5 ;
        RECT  213.6 69.036 213.624 69.12 ;
    END
  END x2[344]
  PIN x2[345]
    DIRECTION OUTPUT ;
    USE SIGNAL ;
    PORT
      LAYER M5 ;
        RECT  213.84 69.036 213.864 69.12 ;
    END
  END x2[345]
  PIN x2[346]
    DIRECTION OUTPUT ;
    USE SIGNAL ;
    PORT
      LAYER M5 ;
        RECT  214.08 69.036 214.104 69.12 ;
    END
  END x2[346]
  PIN x2[347]
    DIRECTION OUTPUT ;
    USE SIGNAL ;
    PORT
      LAYER M5 ;
        RECT  214.32 69.036 214.344 69.12 ;
    END
  END x2[347]
  PIN x2[348]
    DIRECTION OUTPUT ;
    USE SIGNAL ;
    PORT
      LAYER M5 ;
        RECT  214.56 69.036 214.584 69.12 ;
    END
  END x2[348]
  PIN x2[349]
    DIRECTION OUTPUT ;
    USE SIGNAL ;
    PORT
      LAYER M5 ;
        RECT  214.8 69.036 214.824 69.12 ;
    END
  END x2[349]
  PIN x2[34]
    DIRECTION OUTPUT ;
    USE SIGNAL ;
    PORT
      LAYER M5 ;
        RECT  140.16 69.036 140.184 69.12 ;
    END
  END x2[34]
  PIN x2[350]
    DIRECTION OUTPUT ;
    USE SIGNAL ;
    PORT
      LAYER M5 ;
        RECT  215.04 69.036 215.064 69.12 ;
    END
  END x2[350]
  PIN x2[351]
    DIRECTION OUTPUT ;
    USE SIGNAL ;
    PORT
      LAYER M5 ;
        RECT  215.28 69.036 215.304 69.12 ;
    END
  END x2[351]
  PIN x2[352]
    DIRECTION OUTPUT ;
    USE SIGNAL ;
    PORT
      LAYER M5 ;
        RECT  215.52 69.036 215.544 69.12 ;
    END
  END x2[352]
  PIN x2[353]
    DIRECTION OUTPUT ;
    USE SIGNAL ;
    PORT
      LAYER M5 ;
        RECT  215.76 69.036 215.784 69.12 ;
    END
  END x2[353]
  PIN x2[354]
    DIRECTION OUTPUT ;
    USE SIGNAL ;
    PORT
      LAYER M5 ;
        RECT  216 69.036 216.024 69.12 ;
    END
  END x2[354]
  PIN x2[355]
    DIRECTION OUTPUT ;
    USE SIGNAL ;
    PORT
      LAYER M5 ;
        RECT  216.24 69.036 216.264 69.12 ;
    END
  END x2[355]
  PIN x2[356]
    DIRECTION OUTPUT ;
    USE SIGNAL ;
    PORT
      LAYER M5 ;
        RECT  216.48 69.036 216.504 69.12 ;
    END
  END x2[356]
  PIN x2[357]
    DIRECTION OUTPUT ;
    USE SIGNAL ;
    PORT
      LAYER M5 ;
        RECT  216.72 69.036 216.744 69.12 ;
    END
  END x2[357]
  PIN x2[358]
    DIRECTION OUTPUT ;
    USE SIGNAL ;
    PORT
      LAYER M5 ;
        RECT  216.912 69.036 216.936 69.12 ;
    END
  END x2[358]
  PIN x2[359]
    DIRECTION OUTPUT ;
    USE SIGNAL ;
    PORT
      LAYER M5 ;
        RECT  217.152 69.036 217.176 69.12 ;
    END
  END x2[359]
  PIN x2[35]
    DIRECTION OUTPUT ;
    USE SIGNAL ;
    PORT
      LAYER M5 ;
        RECT  140.4 69.036 140.424 69.12 ;
    END
  END x2[35]
  PIN x2[360]
    DIRECTION OUTPUT ;
    USE SIGNAL ;
    PORT
      LAYER M5 ;
        RECT  217.392 69.036 217.416 69.12 ;
    END
  END x2[360]
  PIN x2[361]
    DIRECTION OUTPUT ;
    USE SIGNAL ;
    PORT
      LAYER M5 ;
        RECT  217.632 69.036 217.656 69.12 ;
    END
  END x2[361]
  PIN x2[362]
    DIRECTION OUTPUT ;
    USE SIGNAL ;
    PORT
      LAYER M5 ;
        RECT  217.872 69.036 217.896 69.12 ;
    END
  END x2[362]
  PIN x2[363]
    DIRECTION OUTPUT ;
    USE SIGNAL ;
    PORT
      LAYER M5 ;
        RECT  218.112 69.036 218.136 69.12 ;
    END
  END x2[363]
  PIN x2[364]
    DIRECTION OUTPUT ;
    USE SIGNAL ;
    PORT
      LAYER M5 ;
        RECT  218.352 69.036 218.376 69.12 ;
    END
  END x2[364]
  PIN x2[365]
    DIRECTION OUTPUT ;
    USE SIGNAL ;
    PORT
      LAYER M5 ;
        RECT  218.592 69.036 218.616 69.12 ;
    END
  END x2[365]
  PIN x2[366]
    DIRECTION OUTPUT ;
    USE SIGNAL ;
    PORT
      LAYER M5 ;
        RECT  218.832 69.036 218.856 69.12 ;
    END
  END x2[366]
  PIN x2[367]
    DIRECTION OUTPUT ;
    USE SIGNAL ;
    PORT
      LAYER M5 ;
        RECT  219.072 69.036 219.096 69.12 ;
    END
  END x2[367]
  PIN x2[368]
    DIRECTION OUTPUT ;
    USE SIGNAL ;
    PORT
      LAYER M5 ;
        RECT  219.312 69.036 219.336 69.12 ;
    END
  END x2[368]
  PIN x2[369]
    DIRECTION OUTPUT ;
    USE SIGNAL ;
    PORT
      LAYER M5 ;
        RECT  219.552 69.036 219.576 69.12 ;
    END
  END x2[369]
  PIN x2[36]
    DIRECTION OUTPUT ;
    USE SIGNAL ;
    PORT
      LAYER M5 ;
        RECT  140.64 69.036 140.664 69.12 ;
    END
  END x2[36]
  PIN x2[370]
    DIRECTION OUTPUT ;
    USE SIGNAL ;
    PORT
      LAYER M5 ;
        RECT  219.792 69.036 219.816 69.12 ;
    END
  END x2[370]
  PIN x2[371]
    DIRECTION OUTPUT ;
    USE SIGNAL ;
    PORT
      LAYER M5 ;
        RECT  220.032 69.036 220.056 69.12 ;
    END
  END x2[371]
  PIN x2[372]
    DIRECTION OUTPUT ;
    USE SIGNAL ;
    PORT
      LAYER M5 ;
        RECT  220.272 69.036 220.296 69.12 ;
    END
  END x2[372]
  PIN x2[373]
    DIRECTION OUTPUT ;
    USE SIGNAL ;
    PORT
      LAYER M5 ;
        RECT  220.512 69.036 220.536 69.12 ;
    END
  END x2[373]
  PIN x2[374]
    DIRECTION OUTPUT ;
    USE SIGNAL ;
    PORT
      LAYER M5 ;
        RECT  220.704 69.036 220.728 69.12 ;
    END
  END x2[374]
  PIN x2[375]
    DIRECTION OUTPUT ;
    USE SIGNAL ;
    PORT
      LAYER M5 ;
        RECT  220.944 69.036 220.968 69.12 ;
    END
  END x2[375]
  PIN x2[376]
    DIRECTION OUTPUT ;
    USE SIGNAL ;
    PORT
      LAYER M5 ;
        RECT  221.184 69.036 221.208 69.12 ;
    END
  END x2[376]
  PIN x2[377]
    DIRECTION OUTPUT ;
    USE SIGNAL ;
    PORT
      LAYER M5 ;
        RECT  221.424 69.036 221.448 69.12 ;
    END
  END x2[377]
  PIN x2[378]
    DIRECTION OUTPUT ;
    USE SIGNAL ;
    PORT
      LAYER M5 ;
        RECT  221.664 69.036 221.688 69.12 ;
    END
  END x2[378]
  PIN x2[379]
    DIRECTION OUTPUT ;
    USE SIGNAL ;
    PORT
      LAYER M5 ;
        RECT  221.904 69.036 221.928 69.12 ;
    END
  END x2[379]
  PIN x2[37]
    DIRECTION OUTPUT ;
    USE SIGNAL ;
    PORT
      LAYER M5 ;
        RECT  140.88 69.036 140.904 69.12 ;
    END
  END x2[37]
  PIN x2[380]
    DIRECTION OUTPUT ;
    USE SIGNAL ;
    PORT
      LAYER M5 ;
        RECT  222.144 69.036 222.168 69.12 ;
    END
  END x2[380]
  PIN x2[381]
    DIRECTION OUTPUT ;
    USE SIGNAL ;
    PORT
      LAYER M5 ;
        RECT  222.384 69.036 222.408 69.12 ;
    END
  END x2[381]
  PIN x2[382]
    DIRECTION OUTPUT ;
    USE SIGNAL ;
    PORT
      LAYER M5 ;
        RECT  222.624 69.036 222.648 69.12 ;
    END
  END x2[382]
  PIN x2[383]
    DIRECTION OUTPUT ;
    USE SIGNAL ;
    PORT
      LAYER M5 ;
        RECT  222.864 69.036 222.888 69.12 ;
    END
  END x2[383]
  PIN x2[384]
    DIRECTION OUTPUT ;
    USE SIGNAL ;
    PORT
      LAYER M5 ;
        RECT  223.104 69.036 223.128 69.12 ;
    END
  END x2[384]
  PIN x2[385]
    DIRECTION OUTPUT ;
    USE SIGNAL ;
    PORT
      LAYER M5 ;
        RECT  223.344 69.036 223.368 69.12 ;
    END
  END x2[385]
  PIN x2[386]
    DIRECTION OUTPUT ;
    USE SIGNAL ;
    PORT
      LAYER M5 ;
        RECT  223.584 69.036 223.608 69.12 ;
    END
  END x2[386]
  PIN x2[387]
    DIRECTION OUTPUT ;
    USE SIGNAL ;
    PORT
      LAYER M5 ;
        RECT  223.824 69.036 223.848 69.12 ;
    END
  END x2[387]
  PIN x2[388]
    DIRECTION OUTPUT ;
    USE SIGNAL ;
    PORT
      LAYER M5 ;
        RECT  224.064 69.036 224.088 69.12 ;
    END
  END x2[388]
  PIN x2[389]
    DIRECTION OUTPUT ;
    USE SIGNAL ;
    PORT
      LAYER M5 ;
        RECT  224.304 69.036 224.328 69.12 ;
    END
  END x2[389]
  PIN x2[38]
    DIRECTION OUTPUT ;
    USE SIGNAL ;
    PORT
      LAYER M5 ;
        RECT  141.12 69.036 141.144 69.12 ;
    END
  END x2[38]
  PIN x2[390]
    DIRECTION OUTPUT ;
    USE SIGNAL ;
    PORT
      LAYER M5 ;
        RECT  224.496 69.036 224.52 69.12 ;
    END
  END x2[390]
  PIN x2[391]
    DIRECTION OUTPUT ;
    USE SIGNAL ;
    PORT
      LAYER M5 ;
        RECT  224.736 69.036 224.76 69.12 ;
    END
  END x2[391]
  PIN x2[392]
    DIRECTION OUTPUT ;
    USE SIGNAL ;
    PORT
      LAYER M5 ;
        RECT  224.976 69.036 225 69.12 ;
    END
  END x2[392]
  PIN x2[393]
    DIRECTION OUTPUT ;
    USE SIGNAL ;
    PORT
      LAYER M5 ;
        RECT  225.216 69.036 225.24 69.12 ;
    END
  END x2[393]
  PIN x2[394]
    DIRECTION OUTPUT ;
    USE SIGNAL ;
    PORT
      LAYER M5 ;
        RECT  225.456 69.036 225.48 69.12 ;
    END
  END x2[394]
  PIN x2[395]
    DIRECTION OUTPUT ;
    USE SIGNAL ;
    PORT
      LAYER M5 ;
        RECT  225.696 69.036 225.72 69.12 ;
    END
  END x2[395]
  PIN x2[396]
    DIRECTION OUTPUT ;
    USE SIGNAL ;
    PORT
      LAYER M5 ;
        RECT  225.936 69.036 225.96 69.12 ;
    END
  END x2[396]
  PIN x2[397]
    DIRECTION OUTPUT ;
    USE SIGNAL ;
    PORT
      LAYER M5 ;
        RECT  226.176 69.036 226.2 69.12 ;
    END
  END x2[397]
  PIN x2[398]
    DIRECTION OUTPUT ;
    USE SIGNAL ;
    PORT
      LAYER M5 ;
        RECT  226.416 69.036 226.44 69.12 ;
    END
  END x2[398]
  PIN x2[399]
    DIRECTION OUTPUT ;
    USE SIGNAL ;
    PORT
      LAYER M5 ;
        RECT  226.656 69.036 226.68 69.12 ;
    END
  END x2[399]
  PIN x2[39]
    DIRECTION OUTPUT ;
    USE SIGNAL ;
    PORT
      LAYER M5 ;
        RECT  141.312 69.036 141.336 69.12 ;
    END
  END x2[39]
  PIN x2[3]
    DIRECTION OUTPUT ;
    USE SIGNAL ;
    PORT
      LAYER M5 ;
        RECT  132.816 69.036 132.84 69.12 ;
    END
  END x2[3]
  PIN x2[400]
    DIRECTION OUTPUT ;
    USE SIGNAL ;
    PORT
      LAYER M5 ;
        RECT  226.896 69.036 226.92 69.12 ;
    END
  END x2[400]
  PIN x2[401]
    DIRECTION OUTPUT ;
    USE SIGNAL ;
    PORT
      LAYER M5 ;
        RECT  227.136 69.036 227.16 69.12 ;
    END
  END x2[401]
  PIN x2[402]
    DIRECTION OUTPUT ;
    USE SIGNAL ;
    PORT
      LAYER M5 ;
        RECT  227.376 69.036 227.4 69.12 ;
    END
  END x2[402]
  PIN x2[403]
    DIRECTION OUTPUT ;
    USE SIGNAL ;
    PORT
      LAYER M5 ;
        RECT  227.616 69.036 227.64 69.12 ;
    END
  END x2[403]
  PIN x2[404]
    DIRECTION OUTPUT ;
    USE SIGNAL ;
    PORT
      LAYER M5 ;
        RECT  227.856 69.036 227.88 69.12 ;
    END
  END x2[404]
  PIN x2[405]
    DIRECTION OUTPUT ;
    USE SIGNAL ;
    PORT
      LAYER M5 ;
        RECT  228.096 69.036 228.12 69.12 ;
    END
  END x2[405]
  PIN x2[406]
    DIRECTION OUTPUT ;
    USE SIGNAL ;
    PORT
      LAYER M5 ;
        RECT  228.288 69.036 228.312 69.12 ;
    END
  END x2[406]
  PIN x2[407]
    DIRECTION OUTPUT ;
    USE SIGNAL ;
    PORT
      LAYER M5 ;
        RECT  228.528 69.036 228.552 69.12 ;
    END
  END x2[407]
  PIN x2[408]
    DIRECTION OUTPUT ;
    USE SIGNAL ;
    PORT
      LAYER M5 ;
        RECT  228.768 69.036 228.792 69.12 ;
    END
  END x2[408]
  PIN x2[409]
    DIRECTION OUTPUT ;
    USE SIGNAL ;
    PORT
      LAYER M5 ;
        RECT  229.008 69.036 229.032 69.12 ;
    END
  END x2[409]
  PIN x2[40]
    DIRECTION OUTPUT ;
    USE SIGNAL ;
    PORT
      LAYER M5 ;
        RECT  141.552 69.036 141.576 69.12 ;
    END
  END x2[40]
  PIN x2[410]
    DIRECTION OUTPUT ;
    USE SIGNAL ;
    PORT
      LAYER M5 ;
        RECT  229.248 69.036 229.272 69.12 ;
    END
  END x2[410]
  PIN x2[411]
    DIRECTION OUTPUT ;
    USE SIGNAL ;
    PORT
      LAYER M5 ;
        RECT  229.488 69.036 229.512 69.12 ;
    END
  END x2[411]
  PIN x2[412]
    DIRECTION OUTPUT ;
    USE SIGNAL ;
    PORT
      LAYER M5 ;
        RECT  229.728 69.036 229.752 69.12 ;
    END
  END x2[412]
  PIN x2[413]
    DIRECTION OUTPUT ;
    USE SIGNAL ;
    PORT
      LAYER M5 ;
        RECT  229.968 69.036 229.992 69.12 ;
    END
  END x2[413]
  PIN x2[414]
    DIRECTION OUTPUT ;
    USE SIGNAL ;
    PORT
      LAYER M5 ;
        RECT  230.208 69.036 230.232 69.12 ;
    END
  END x2[414]
  PIN x2[415]
    DIRECTION OUTPUT ;
    USE SIGNAL ;
    PORT
      LAYER M5 ;
        RECT  230.448 69.036 230.472 69.12 ;
    END
  END x2[415]
  PIN x2[416]
    DIRECTION OUTPUT ;
    USE SIGNAL ;
    PORT
      LAYER M5 ;
        RECT  230.688 69.036 230.712 69.12 ;
    END
  END x2[416]
  PIN x2[417]
    DIRECTION OUTPUT ;
    USE SIGNAL ;
    PORT
      LAYER M5 ;
        RECT  230.928 69.036 230.952 69.12 ;
    END
  END x2[417]
  PIN x2[418]
    DIRECTION OUTPUT ;
    USE SIGNAL ;
    PORT
      LAYER M5 ;
        RECT  231.168 69.036 231.192 69.12 ;
    END
  END x2[418]
  PIN x2[419]
    DIRECTION OUTPUT ;
    USE SIGNAL ;
    PORT
      LAYER M5 ;
        RECT  231.408 69.036 231.432 69.12 ;
    END
  END x2[419]
  PIN x2[41]
    DIRECTION OUTPUT ;
    USE SIGNAL ;
    PORT
      LAYER M5 ;
        RECT  141.792 69.036 141.816 69.12 ;
    END
  END x2[41]
  PIN x2[420]
    DIRECTION OUTPUT ;
    USE SIGNAL ;
    PORT
      LAYER M5 ;
        RECT  231.648 69.036 231.672 69.12 ;
    END
  END x2[420]
  PIN x2[421]
    DIRECTION OUTPUT ;
    USE SIGNAL ;
    PORT
      LAYER M5 ;
        RECT  231.888 69.036 231.912 69.12 ;
    END
  END x2[421]
  PIN x2[422]
    DIRECTION OUTPUT ;
    USE SIGNAL ;
    PORT
      LAYER M5 ;
        RECT  232.08 69.036 232.104 69.12 ;
    END
  END x2[422]
  PIN x2[423]
    DIRECTION OUTPUT ;
    USE SIGNAL ;
    PORT
      LAYER M5 ;
        RECT  232.32 69.036 232.344 69.12 ;
    END
  END x2[423]
  PIN x2[424]
    DIRECTION OUTPUT ;
    USE SIGNAL ;
    PORT
      LAYER M5 ;
        RECT  232.56 69.036 232.584 69.12 ;
    END
  END x2[424]
  PIN x2[425]
    DIRECTION OUTPUT ;
    USE SIGNAL ;
    PORT
      LAYER M5 ;
        RECT  232.8 69.036 232.824 69.12 ;
    END
  END x2[425]
  PIN x2[426]
    DIRECTION OUTPUT ;
    USE SIGNAL ;
    PORT
      LAYER M5 ;
        RECT  233.04 69.036 233.064 69.12 ;
    END
  END x2[426]
  PIN x2[427]
    DIRECTION OUTPUT ;
    USE SIGNAL ;
    PORT
      LAYER M5 ;
        RECT  233.28 69.036 233.304 69.12 ;
    END
  END x2[427]
  PIN x2[428]
    DIRECTION OUTPUT ;
    USE SIGNAL ;
    PORT
      LAYER M5 ;
        RECT  233.52 69.036 233.544 69.12 ;
    END
  END x2[428]
  PIN x2[429]
    DIRECTION OUTPUT ;
    USE SIGNAL ;
    PORT
      LAYER M5 ;
        RECT  233.76 69.036 233.784 69.12 ;
    END
  END x2[429]
  PIN x2[42]
    DIRECTION OUTPUT ;
    USE SIGNAL ;
    PORT
      LAYER M5 ;
        RECT  142.032 69.036 142.056 69.12 ;
    END
  END x2[42]
  PIN x2[430]
    DIRECTION OUTPUT ;
    USE SIGNAL ;
    PORT
      LAYER M5 ;
        RECT  234 69.036 234.024 69.12 ;
    END
  END x2[430]
  PIN x2[431]
    DIRECTION OUTPUT ;
    USE SIGNAL ;
    PORT
      LAYER M5 ;
        RECT  234.24 69.036 234.264 69.12 ;
    END
  END x2[431]
  PIN x2[432]
    DIRECTION OUTPUT ;
    USE SIGNAL ;
    PORT
      LAYER M5 ;
        RECT  234.48 69.036 234.504 69.12 ;
    END
  END x2[432]
  PIN x2[433]
    DIRECTION OUTPUT ;
    USE SIGNAL ;
    PORT
      LAYER M5 ;
        RECT  234.72 69.036 234.744 69.12 ;
    END
  END x2[433]
  PIN x2[434]
    DIRECTION OUTPUT ;
    USE SIGNAL ;
    PORT
      LAYER M5 ;
        RECT  234.96 69.036 234.984 69.12 ;
    END
  END x2[434]
  PIN x2[435]
    DIRECTION OUTPUT ;
    USE SIGNAL ;
    PORT
      LAYER M5 ;
        RECT  235.2 69.036 235.224 69.12 ;
    END
  END x2[435]
  PIN x2[436]
    DIRECTION OUTPUT ;
    USE SIGNAL ;
    PORT
      LAYER M5 ;
        RECT  235.44 69.036 235.464 69.12 ;
    END
  END x2[436]
  PIN x2[437]
    DIRECTION OUTPUT ;
    USE SIGNAL ;
    PORT
      LAYER M5 ;
        RECT  235.68 69.036 235.704 69.12 ;
    END
  END x2[437]
  PIN x2[438]
    DIRECTION OUTPUT ;
    USE SIGNAL ;
    PORT
      LAYER M5 ;
        RECT  235.872 69.036 235.896 69.12 ;
    END
  END x2[438]
  PIN x2[439]
    DIRECTION OUTPUT ;
    USE SIGNAL ;
    PORT
      LAYER M5 ;
        RECT  236.112 69.036 236.136 69.12 ;
    END
  END x2[439]
  PIN x2[43]
    DIRECTION OUTPUT ;
    USE SIGNAL ;
    PORT
      LAYER M5 ;
        RECT  142.272 69.036 142.296 69.12 ;
    END
  END x2[43]
  PIN x2[440]
    DIRECTION OUTPUT ;
    USE SIGNAL ;
    PORT
      LAYER M5 ;
        RECT  236.352 69.036 236.376 69.12 ;
    END
  END x2[440]
  PIN x2[441]
    DIRECTION OUTPUT ;
    USE SIGNAL ;
    PORT
      LAYER M5 ;
        RECT  236.592 69.036 236.616 69.12 ;
    END
  END x2[441]
  PIN x2[442]
    DIRECTION OUTPUT ;
    USE SIGNAL ;
    PORT
      LAYER M5 ;
        RECT  236.832 69.036 236.856 69.12 ;
    END
  END x2[442]
  PIN x2[443]
    DIRECTION OUTPUT ;
    USE SIGNAL ;
    PORT
      LAYER M5 ;
        RECT  237.072 69.036 237.096 69.12 ;
    END
  END x2[443]
  PIN x2[444]
    DIRECTION OUTPUT ;
    USE SIGNAL ;
    PORT
      LAYER M5 ;
        RECT  237.312 69.036 237.336 69.12 ;
    END
  END x2[444]
  PIN x2[445]
    DIRECTION OUTPUT ;
    USE SIGNAL ;
    PORT
      LAYER M5 ;
        RECT  237.552 69.036 237.576 69.12 ;
    END
  END x2[445]
  PIN x2[446]
    DIRECTION OUTPUT ;
    USE SIGNAL ;
    PORT
      LAYER M5 ;
        RECT  237.792 69.036 237.816 69.12 ;
    END
  END x2[446]
  PIN x2[447]
    DIRECTION OUTPUT ;
    USE SIGNAL ;
    PORT
      LAYER M5 ;
        RECT  238.032 69.036 238.056 69.12 ;
    END
  END x2[447]
  PIN x2[448]
    DIRECTION OUTPUT ;
    USE SIGNAL ;
    PORT
      LAYER M5 ;
        RECT  238.272 69.036 238.296 69.12 ;
    END
  END x2[448]
  PIN x2[449]
    DIRECTION OUTPUT ;
    USE SIGNAL ;
    PORT
      LAYER M5 ;
        RECT  238.512 69.036 238.536 69.12 ;
    END
  END x2[449]
  PIN x2[44]
    DIRECTION OUTPUT ;
    USE SIGNAL ;
    PORT
      LAYER M5 ;
        RECT  142.512 69.036 142.536 69.12 ;
    END
  END x2[44]
  PIN x2[450]
    DIRECTION OUTPUT ;
    USE SIGNAL ;
    PORT
      LAYER M5 ;
        RECT  238.752 69.036 238.776 69.12 ;
    END
  END x2[450]
  PIN x2[451]
    DIRECTION OUTPUT ;
    USE SIGNAL ;
    PORT
      LAYER M5 ;
        RECT  238.992 69.036 239.016 69.12 ;
    END
  END x2[451]
  PIN x2[452]
    DIRECTION OUTPUT ;
    USE SIGNAL ;
    PORT
      LAYER M5 ;
        RECT  239.232 69.036 239.256 69.12 ;
    END
  END x2[452]
  PIN x2[453]
    DIRECTION OUTPUT ;
    USE SIGNAL ;
    PORT
      LAYER M5 ;
        RECT  239.472 69.036 239.496 69.12 ;
    END
  END x2[453]
  PIN x2[454]
    DIRECTION OUTPUT ;
    USE SIGNAL ;
    PORT
      LAYER M5 ;
        RECT  239.664 69.036 239.688 69.12 ;
    END
  END x2[454]
  PIN x2[455]
    DIRECTION OUTPUT ;
    USE SIGNAL ;
    PORT
      LAYER M5 ;
        RECT  239.904 69.036 239.928 69.12 ;
    END
  END x2[455]
  PIN x2[456]
    DIRECTION OUTPUT ;
    USE SIGNAL ;
    PORT
      LAYER M5 ;
        RECT  240.144 69.036 240.168 69.12 ;
    END
  END x2[456]
  PIN x2[457]
    DIRECTION OUTPUT ;
    USE SIGNAL ;
    PORT
      LAYER M5 ;
        RECT  240.384 69.036 240.408 69.12 ;
    END
  END x2[457]
  PIN x2[458]
    DIRECTION OUTPUT ;
    USE SIGNAL ;
    PORT
      LAYER M5 ;
        RECT  240.624 69.036 240.648 69.12 ;
    END
  END x2[458]
  PIN x2[459]
    DIRECTION OUTPUT ;
    USE SIGNAL ;
    PORT
      LAYER M5 ;
        RECT  240.864 69.036 240.888 69.12 ;
    END
  END x2[459]
  PIN x2[45]
    DIRECTION OUTPUT ;
    USE SIGNAL ;
    PORT
      LAYER M5 ;
        RECT  142.752 69.036 142.776 69.12 ;
    END
  END x2[45]
  PIN x2[460]
    DIRECTION OUTPUT ;
    USE SIGNAL ;
    PORT
      LAYER M5 ;
        RECT  241.104 69.036 241.128 69.12 ;
    END
  END x2[460]
  PIN x2[461]
    DIRECTION OUTPUT ;
    USE SIGNAL ;
    PORT
      LAYER M5 ;
        RECT  241.344 69.036 241.368 69.12 ;
    END
  END x2[461]
  PIN x2[462]
    DIRECTION OUTPUT ;
    USE SIGNAL ;
    PORT
      LAYER M5 ;
        RECT  241.584 69.036 241.608 69.12 ;
    END
  END x2[462]
  PIN x2[463]
    DIRECTION OUTPUT ;
    USE SIGNAL ;
    PORT
      LAYER M5 ;
        RECT  241.824 69.036 241.848 69.12 ;
    END
  END x2[463]
  PIN x2[464]
    DIRECTION OUTPUT ;
    USE SIGNAL ;
    PORT
      LAYER M5 ;
        RECT  242.064 69.036 242.088 69.12 ;
    END
  END x2[464]
  PIN x2[465]
    DIRECTION OUTPUT ;
    USE SIGNAL ;
    PORT
      LAYER M5 ;
        RECT  242.304 69.036 242.328 69.12 ;
    END
  END x2[465]
  PIN x2[466]
    DIRECTION OUTPUT ;
    USE SIGNAL ;
    PORT
      LAYER M5 ;
        RECT  242.544 69.036 242.568 69.12 ;
    END
  END x2[466]
  PIN x2[467]
    DIRECTION OUTPUT ;
    USE SIGNAL ;
    PORT
      LAYER M5 ;
        RECT  242.784 69.036 242.808 69.12 ;
    END
  END x2[467]
  PIN x2[468]
    DIRECTION OUTPUT ;
    USE SIGNAL ;
    PORT
      LAYER M5 ;
        RECT  243.024 69.036 243.048 69.12 ;
    END
  END x2[468]
  PIN x2[469]
    DIRECTION OUTPUT ;
    USE SIGNAL ;
    PORT
      LAYER M5 ;
        RECT  243.264 69.036 243.288 69.12 ;
    END
  END x2[469]
  PIN x2[46]
    DIRECTION OUTPUT ;
    USE SIGNAL ;
    PORT
      LAYER M5 ;
        RECT  142.992 69.036 143.016 69.12 ;
    END
  END x2[46]
  PIN x2[470]
    DIRECTION OUTPUT ;
    USE SIGNAL ;
    PORT
      LAYER M5 ;
        RECT  243.456 69.036 243.48 69.12 ;
    END
  END x2[470]
  PIN x2[471]
    DIRECTION OUTPUT ;
    USE SIGNAL ;
    PORT
      LAYER M5 ;
        RECT  243.696 69.036 243.72 69.12 ;
    END
  END x2[471]
  PIN x2[472]
    DIRECTION OUTPUT ;
    USE SIGNAL ;
    PORT
      LAYER M5 ;
        RECT  243.936 69.036 243.96 69.12 ;
    END
  END x2[472]
  PIN x2[473]
    DIRECTION OUTPUT ;
    USE SIGNAL ;
    PORT
      LAYER M5 ;
        RECT  244.176 69.036 244.2 69.12 ;
    END
  END x2[473]
  PIN x2[474]
    DIRECTION OUTPUT ;
    USE SIGNAL ;
    PORT
      LAYER M5 ;
        RECT  244.416 69.036 244.44 69.12 ;
    END
  END x2[474]
  PIN x2[475]
    DIRECTION OUTPUT ;
    USE SIGNAL ;
    PORT
      LAYER M5 ;
        RECT  244.656 69.036 244.68 69.12 ;
    END
  END x2[475]
  PIN x2[476]
    DIRECTION OUTPUT ;
    USE SIGNAL ;
    PORT
      LAYER M5 ;
        RECT  244.896 69.036 244.92 69.12 ;
    END
  END x2[476]
  PIN x2[477]
    DIRECTION OUTPUT ;
    USE SIGNAL ;
    PORT
      LAYER M5 ;
        RECT  245.136 69.036 245.16 69.12 ;
    END
  END x2[477]
  PIN x2[478]
    DIRECTION OUTPUT ;
    USE SIGNAL ;
    PORT
      LAYER M5 ;
        RECT  245.376 69.036 245.4 69.12 ;
    END
  END x2[478]
  PIN x2[479]
    DIRECTION OUTPUT ;
    USE SIGNAL ;
    PORT
      LAYER M5 ;
        RECT  245.616 69.036 245.64 69.12 ;
    END
  END x2[479]
  PIN x2[47]
    DIRECTION OUTPUT ;
    USE SIGNAL ;
    PORT
      LAYER M5 ;
        RECT  143.232 69.036 143.256 69.12 ;
    END
  END x2[47]
  PIN x2[480]
    DIRECTION OUTPUT ;
    USE SIGNAL ;
    PORT
      LAYER M5 ;
        RECT  245.856 69.036 245.88 69.12 ;
    END
  END x2[480]
  PIN x2[481]
    DIRECTION OUTPUT ;
    USE SIGNAL ;
    PORT
      LAYER M5 ;
        RECT  246.096 69.036 246.12 69.12 ;
    END
  END x2[481]
  PIN x2[482]
    DIRECTION OUTPUT ;
    USE SIGNAL ;
    PORT
      LAYER M5 ;
        RECT  246.336 69.036 246.36 69.12 ;
    END
  END x2[482]
  PIN x2[483]
    DIRECTION OUTPUT ;
    USE SIGNAL ;
    PORT
      LAYER M5 ;
        RECT  246.576 69.036 246.6 69.12 ;
    END
  END x2[483]
  PIN x2[484]
    DIRECTION OUTPUT ;
    USE SIGNAL ;
    PORT
      LAYER M5 ;
        RECT  246.816 69.036 246.84 69.12 ;
    END
  END x2[484]
  PIN x2[485]
    DIRECTION OUTPUT ;
    USE SIGNAL ;
    PORT
      LAYER M5 ;
        RECT  247.008 69.036 247.032 69.12 ;
    END
  END x2[485]
  PIN x2[486]
    DIRECTION OUTPUT ;
    USE SIGNAL ;
    PORT
      LAYER M5 ;
        RECT  247.248 69.036 247.272 69.12 ;
    END
  END x2[486]
  PIN x2[487]
    DIRECTION OUTPUT ;
    USE SIGNAL ;
    PORT
      LAYER M5 ;
        RECT  247.488 69.036 247.512 69.12 ;
    END
  END x2[487]
  PIN x2[488]
    DIRECTION OUTPUT ;
    USE SIGNAL ;
    PORT
      LAYER M5 ;
        RECT  247.728 69.036 247.752 69.12 ;
    END
  END x2[488]
  PIN x2[489]
    DIRECTION OUTPUT ;
    USE SIGNAL ;
    PORT
      LAYER M5 ;
        RECT  247.968 69.036 247.992 69.12 ;
    END
  END x2[489]
  PIN x2[48]
    DIRECTION OUTPUT ;
    USE SIGNAL ;
    PORT
      LAYER M5 ;
        RECT  143.472 69.036 143.496 69.12 ;
    END
  END x2[48]
  PIN x2[490]
    DIRECTION OUTPUT ;
    USE SIGNAL ;
    PORT
      LAYER M5 ;
        RECT  248.208 69.036 248.232 69.12 ;
    END
  END x2[490]
  PIN x2[491]
    DIRECTION OUTPUT ;
    USE SIGNAL ;
    PORT
      LAYER M5 ;
        RECT  248.448 69.036 248.472 69.12 ;
    END
  END x2[491]
  PIN x2[492]
    DIRECTION OUTPUT ;
    USE SIGNAL ;
    PORT
      LAYER M5 ;
        RECT  248.688 69.036 248.712 69.12 ;
    END
  END x2[492]
  PIN x2[493]
    DIRECTION OUTPUT ;
    USE SIGNAL ;
    PORT
      LAYER M5 ;
        RECT  248.928 69.036 248.952 69.12 ;
    END
  END x2[493]
  PIN x2[494]
    DIRECTION OUTPUT ;
    USE SIGNAL ;
    PORT
      LAYER M5 ;
        RECT  249.168 69.036 249.192 69.12 ;
    END
  END x2[494]
  PIN x2[495]
    DIRECTION OUTPUT ;
    USE SIGNAL ;
    PORT
      LAYER M5 ;
        RECT  249.408 69.036 249.432 69.12 ;
    END
  END x2[495]
  PIN x2[496]
    DIRECTION OUTPUT ;
    USE SIGNAL ;
    PORT
      LAYER M5 ;
        RECT  249.648 69.036 249.672 69.12 ;
    END
  END x2[496]
  PIN x2[497]
    DIRECTION OUTPUT ;
    USE SIGNAL ;
    PORT
      LAYER M5 ;
        RECT  249.888 69.036 249.912 69.12 ;
    END
  END x2[497]
  PIN x2[498]
    DIRECTION OUTPUT ;
    USE SIGNAL ;
    PORT
      LAYER M5 ;
        RECT  250.128 69.036 250.152 69.12 ;
    END
  END x2[498]
  PIN x2[499]
    DIRECTION OUTPUT ;
    USE SIGNAL ;
    PORT
      LAYER M5 ;
        RECT  250.368 69.036 250.392 69.12 ;
    END
  END x2[499]
  PIN x2[49]
    DIRECTION OUTPUT ;
    USE SIGNAL ;
    PORT
      LAYER M5 ;
        RECT  143.712 69.036 143.736 69.12 ;
    END
  END x2[49]
  PIN x2[4]
    DIRECTION OUTPUT ;
    USE SIGNAL ;
    PORT
      LAYER M5 ;
        RECT  133.056 69.036 133.08 69.12 ;
    END
  END x2[4]
  PIN x2[500]
    DIRECTION OUTPUT ;
    USE SIGNAL ;
    PORT
      LAYER M5 ;
        RECT  250.608 69.036 250.632 69.12 ;
    END
  END x2[500]
  PIN x2[501]
    DIRECTION OUTPUT ;
    USE SIGNAL ;
    PORT
      LAYER M5 ;
        RECT  250.8 69.036 250.824 69.12 ;
    END
  END x2[501]
  PIN x2[502]
    DIRECTION OUTPUT ;
    USE SIGNAL ;
    PORT
      LAYER M5 ;
        RECT  251.04 69.036 251.064 69.12 ;
    END
  END x2[502]
  PIN x2[503]
    DIRECTION OUTPUT ;
    USE SIGNAL ;
    PORT
      LAYER M5 ;
        RECT  251.28 69.036 251.304 69.12 ;
    END
  END x2[503]
  PIN x2[504]
    DIRECTION OUTPUT ;
    USE SIGNAL ;
    PORT
      LAYER M5 ;
        RECT  251.52 69.036 251.544 69.12 ;
    END
  END x2[504]
  PIN x2[505]
    DIRECTION OUTPUT ;
    USE SIGNAL ;
    PORT
      LAYER M5 ;
        RECT  251.76 69.036 251.784 69.12 ;
    END
  END x2[505]
  PIN x2[506]
    DIRECTION OUTPUT ;
    USE SIGNAL ;
    PORT
      LAYER M5 ;
        RECT  252 69.036 252.024 69.12 ;
    END
  END x2[506]
  PIN x2[507]
    DIRECTION OUTPUT ;
    USE SIGNAL ;
    PORT
      LAYER M5 ;
        RECT  252.24 69.036 252.264 69.12 ;
    END
  END x2[507]
  PIN x2[508]
    DIRECTION OUTPUT ;
    USE SIGNAL ;
    PORT
      LAYER M5 ;
        RECT  252.48 69.036 252.504 69.12 ;
    END
  END x2[508]
  PIN x2[509]
    DIRECTION OUTPUT ;
    USE SIGNAL ;
    PORT
      LAYER M5 ;
        RECT  252.72 69.036 252.744 69.12 ;
    END
  END x2[509]
  PIN x2[50]
    DIRECTION OUTPUT ;
    USE SIGNAL ;
    PORT
      LAYER M5 ;
        RECT  143.952 69.036 143.976 69.12 ;
    END
  END x2[50]
  PIN x2[510]
    DIRECTION OUTPUT ;
    USE SIGNAL ;
    PORT
      LAYER M5 ;
        RECT  252.96 69.036 252.984 69.12 ;
    END
  END x2[510]
  PIN x2[511]
    DIRECTION OUTPUT ;
    USE SIGNAL ;
    PORT
      LAYER M5 ;
        RECT  253.2 69.036 253.224 69.12 ;
    END
  END x2[511]
  PIN x2[512]
    DIRECTION OUTPUT ;
    USE SIGNAL ;
    PORT
      LAYER M5 ;
        RECT  253.44 69.036 253.464 69.12 ;
    END
  END x2[512]
  PIN x2[513]
    DIRECTION OUTPUT ;
    USE SIGNAL ;
    PORT
      LAYER M5 ;
        RECT  253.68 69.036 253.704 69.12 ;
    END
  END x2[513]
  PIN x2[514]
    DIRECTION OUTPUT ;
    USE SIGNAL ;
    PORT
      LAYER M5 ;
        RECT  253.92 69.036 253.944 69.12 ;
    END
  END x2[514]
  PIN x2[515]
    DIRECTION OUTPUT ;
    USE SIGNAL ;
    PORT
      LAYER M5 ;
        RECT  254.16 69.036 254.184 69.12 ;
    END
  END x2[515]
  PIN x2[516]
    DIRECTION OUTPUT ;
    USE SIGNAL ;
    PORT
      LAYER M5 ;
        RECT  254.4 69.036 254.424 69.12 ;
    END
  END x2[516]
  PIN x2[517]
    DIRECTION OUTPUT ;
    USE SIGNAL ;
    PORT
      LAYER M5 ;
        RECT  254.592 69.036 254.616 69.12 ;
    END
  END x2[517]
  PIN x2[518]
    DIRECTION OUTPUT ;
    USE SIGNAL ;
    PORT
      LAYER M5 ;
        RECT  254.832 69.036 254.856 69.12 ;
    END
  END x2[518]
  PIN x2[519]
    DIRECTION OUTPUT ;
    USE SIGNAL ;
    PORT
      LAYER M5 ;
        RECT  255.072 69.036 255.096 69.12 ;
    END
  END x2[519]
  PIN x2[51]
    DIRECTION OUTPUT ;
    USE SIGNAL ;
    PORT
      LAYER M5 ;
        RECT  144.192 69.036 144.216 69.12 ;
    END
  END x2[51]
  PIN x2[520]
    DIRECTION OUTPUT ;
    USE SIGNAL ;
    PORT
      LAYER M5 ;
        RECT  255.312 69.036 255.336 69.12 ;
    END
  END x2[520]
  PIN x2[521]
    DIRECTION OUTPUT ;
    USE SIGNAL ;
    PORT
      LAYER M5 ;
        RECT  255.552 69.036 255.576 69.12 ;
    END
  END x2[521]
  PIN x2[522]
    DIRECTION OUTPUT ;
    USE SIGNAL ;
    PORT
      LAYER M5 ;
        RECT  255.792 69.036 255.816 69.12 ;
    END
  END x2[522]
  PIN x2[523]
    DIRECTION OUTPUT ;
    USE SIGNAL ;
    PORT
      LAYER M5 ;
        RECT  256.032 69.036 256.056 69.12 ;
    END
  END x2[523]
  PIN x2[524]
    DIRECTION OUTPUT ;
    USE SIGNAL ;
    PORT
      LAYER M5 ;
        RECT  256.272 69.036 256.296 69.12 ;
    END
  END x2[524]
  PIN x2[525]
    DIRECTION OUTPUT ;
    USE SIGNAL ;
    PORT
      LAYER M5 ;
        RECT  256.512 69.036 256.536 69.12 ;
    END
  END x2[525]
  PIN x2[526]
    DIRECTION OUTPUT ;
    USE SIGNAL ;
    PORT
      LAYER M5 ;
        RECT  256.752 69.036 256.776 69.12 ;
    END
  END x2[526]
  PIN x2[527]
    DIRECTION OUTPUT ;
    USE SIGNAL ;
    PORT
      LAYER M5 ;
        RECT  256.992 69.036 257.016 69.12 ;
    END
  END x2[527]
  PIN x2[528]
    DIRECTION OUTPUT ;
    USE SIGNAL ;
    PORT
      LAYER M5 ;
        RECT  257.232 69.036 257.256 69.12 ;
    END
  END x2[528]
  PIN x2[529]
    DIRECTION OUTPUT ;
    USE SIGNAL ;
    PORT
      LAYER M5 ;
        RECT  257.472 69.036 257.496 69.12 ;
    END
  END x2[529]
  PIN x2[52]
    DIRECTION OUTPUT ;
    USE SIGNAL ;
    PORT
      LAYER M5 ;
        RECT  144.432 69.036 144.456 69.12 ;
    END
  END x2[52]
  PIN x2[530]
    DIRECTION OUTPUT ;
    USE SIGNAL ;
    PORT
      LAYER M5 ;
        RECT  257.712 69.036 257.736 69.12 ;
    END
  END x2[530]
  PIN x2[531]
    DIRECTION OUTPUT ;
    USE SIGNAL ;
    PORT
      LAYER M5 ;
        RECT  257.952 69.036 257.976 69.12 ;
    END
  END x2[531]
  PIN x2[532]
    DIRECTION OUTPUT ;
    USE SIGNAL ;
    PORT
      LAYER M5 ;
        RECT  258.192 69.036 258.216 69.12 ;
    END
  END x2[532]
  PIN x2[533]
    DIRECTION OUTPUT ;
    USE SIGNAL ;
    PORT
      LAYER M5 ;
        RECT  258.384 69.036 258.408 69.12 ;
    END
  END x2[533]
  PIN x2[534]
    DIRECTION OUTPUT ;
    USE SIGNAL ;
    PORT
      LAYER M5 ;
        RECT  258.624 69.036 258.648 69.12 ;
    END
  END x2[534]
  PIN x2[535]
    DIRECTION OUTPUT ;
    USE SIGNAL ;
    PORT
      LAYER M5 ;
        RECT  258.864 69.036 258.888 69.12 ;
    END
  END x2[535]
  PIN x2[53]
    DIRECTION OUTPUT ;
    USE SIGNAL ;
    PORT
      LAYER M5 ;
        RECT  144.672 69.036 144.696 69.12 ;
    END
  END x2[53]
  PIN x2[54]
    DIRECTION OUTPUT ;
    USE SIGNAL ;
    PORT
      LAYER M5 ;
        RECT  144.912 69.036 144.936 69.12 ;
    END
  END x2[54]
  PIN x2[55]
    DIRECTION OUTPUT ;
    USE SIGNAL ;
    PORT
      LAYER M5 ;
        RECT  145.104 69.036 145.128 69.12 ;
    END
  END x2[55]
  PIN x2[56]
    DIRECTION OUTPUT ;
    USE SIGNAL ;
    PORT
      LAYER M5 ;
        RECT  145.344 69.036 145.368 69.12 ;
    END
  END x2[56]
  PIN x2[57]
    DIRECTION OUTPUT ;
    USE SIGNAL ;
    PORT
      LAYER M5 ;
        RECT  145.584 69.036 145.608 69.12 ;
    END
  END x2[57]
  PIN x2[58]
    DIRECTION OUTPUT ;
    USE SIGNAL ;
    PORT
      LAYER M5 ;
        RECT  145.824 69.036 145.848 69.12 ;
    END
  END x2[58]
  PIN x2[59]
    DIRECTION OUTPUT ;
    USE SIGNAL ;
    PORT
      LAYER M5 ;
        RECT  146.064 69.036 146.088 69.12 ;
    END
  END x2[59]
  PIN x2[5]
    DIRECTION OUTPUT ;
    USE SIGNAL ;
    PORT
      LAYER M5 ;
        RECT  133.296 69.036 133.32 69.12 ;
    END
  END x2[5]
  PIN x2[60]
    DIRECTION OUTPUT ;
    USE SIGNAL ;
    PORT
      LAYER M5 ;
        RECT  146.304 69.036 146.328 69.12 ;
    END
  END x2[60]
  PIN x2[61]
    DIRECTION OUTPUT ;
    USE SIGNAL ;
    PORT
      LAYER M5 ;
        RECT  146.544 69.036 146.568 69.12 ;
    END
  END x2[61]
  PIN x2[62]
    DIRECTION OUTPUT ;
    USE SIGNAL ;
    PORT
      LAYER M5 ;
        RECT  146.784 69.036 146.808 69.12 ;
    END
  END x2[62]
  PIN x2[63]
    DIRECTION OUTPUT ;
    USE SIGNAL ;
    PORT
      LAYER M5 ;
        RECT  147.024 69.036 147.048 69.12 ;
    END
  END x2[63]
  PIN x2[64]
    DIRECTION OUTPUT ;
    USE SIGNAL ;
    PORT
      LAYER M5 ;
        RECT  147.264 69.036 147.288 69.12 ;
    END
  END x2[64]
  PIN x2[65]
    DIRECTION OUTPUT ;
    USE SIGNAL ;
    PORT
      LAYER M5 ;
        RECT  147.504 69.036 147.528 69.12 ;
    END
  END x2[65]
  PIN x2[66]
    DIRECTION OUTPUT ;
    USE SIGNAL ;
    PORT
      LAYER M5 ;
        RECT  147.744 69.036 147.768 69.12 ;
    END
  END x2[66]
  PIN x2[67]
    DIRECTION OUTPUT ;
    USE SIGNAL ;
    PORT
      LAYER M5 ;
        RECT  147.984 69.036 148.008 69.12 ;
    END
  END x2[67]
  PIN x2[68]
    DIRECTION OUTPUT ;
    USE SIGNAL ;
    PORT
      LAYER M5 ;
        RECT  148.224 69.036 148.248 69.12 ;
    END
  END x2[68]
  PIN x2[69]
    DIRECTION OUTPUT ;
    USE SIGNAL ;
    PORT
      LAYER M5 ;
        RECT  148.464 69.036 148.488 69.12 ;
    END
  END x2[69]
  PIN x2[6]
    DIRECTION OUTPUT ;
    USE SIGNAL ;
    PORT
      LAYER M5 ;
        RECT  133.536 69.036 133.56 69.12 ;
    END
  END x2[6]
  PIN x2[70]
    DIRECTION OUTPUT ;
    USE SIGNAL ;
    PORT
      LAYER M5 ;
        RECT  148.704 69.036 148.728 69.12 ;
    END
  END x2[70]
  PIN x2[71]
    DIRECTION OUTPUT ;
    USE SIGNAL ;
    PORT
      LAYER M5 ;
        RECT  148.896 69.036 148.92 69.12 ;
    END
  END x2[71]
  PIN x2[72]
    DIRECTION OUTPUT ;
    USE SIGNAL ;
    PORT
      LAYER M5 ;
        RECT  149.136 69.036 149.16 69.12 ;
    END
  END x2[72]
  PIN x2[73]
    DIRECTION OUTPUT ;
    USE SIGNAL ;
    PORT
      LAYER M5 ;
        RECT  149.376 69.036 149.4 69.12 ;
    END
  END x2[73]
  PIN x2[74]
    DIRECTION OUTPUT ;
    USE SIGNAL ;
    PORT
      LAYER M5 ;
        RECT  149.616 69.036 149.64 69.12 ;
    END
  END x2[74]
  PIN x2[75]
    DIRECTION OUTPUT ;
    USE SIGNAL ;
    PORT
      LAYER M5 ;
        RECT  149.856 69.036 149.88 69.12 ;
    END
  END x2[75]
  PIN x2[76]
    DIRECTION OUTPUT ;
    USE SIGNAL ;
    PORT
      LAYER M5 ;
        RECT  150.096 69.036 150.12 69.12 ;
    END
  END x2[76]
  PIN x2[77]
    DIRECTION OUTPUT ;
    USE SIGNAL ;
    PORT
      LAYER M5 ;
        RECT  150.336 69.036 150.36 69.12 ;
    END
  END x2[77]
  PIN x2[78]
    DIRECTION OUTPUT ;
    USE SIGNAL ;
    PORT
      LAYER M5 ;
        RECT  150.576 69.036 150.6 69.12 ;
    END
  END x2[78]
  PIN x2[79]
    DIRECTION OUTPUT ;
    USE SIGNAL ;
    PORT
      LAYER M5 ;
        RECT  150.816 69.036 150.84 69.12 ;
    END
  END x2[79]
  PIN x2[7]
    DIRECTION OUTPUT ;
    USE SIGNAL ;
    PORT
      LAYER M5 ;
        RECT  133.776 69.036 133.8 69.12 ;
    END
  END x2[7]
  PIN x2[80]
    DIRECTION OUTPUT ;
    USE SIGNAL ;
    PORT
      LAYER M5 ;
        RECT  151.056 69.036 151.08 69.12 ;
    END
  END x2[80]
  PIN x2[81]
    DIRECTION OUTPUT ;
    USE SIGNAL ;
    PORT
      LAYER M5 ;
        RECT  151.296 69.036 151.32 69.12 ;
    END
  END x2[81]
  PIN x2[82]
    DIRECTION OUTPUT ;
    USE SIGNAL ;
    PORT
      LAYER M5 ;
        RECT  151.536 69.036 151.56 69.12 ;
    END
  END x2[82]
  PIN x2[83]
    DIRECTION OUTPUT ;
    USE SIGNAL ;
    PORT
      LAYER M5 ;
        RECT  151.776 69.036 151.8 69.12 ;
    END
  END x2[83]
  PIN x2[84]
    DIRECTION OUTPUT ;
    USE SIGNAL ;
    PORT
      LAYER M5 ;
        RECT  152.016 69.036 152.04 69.12 ;
    END
  END x2[84]
  PIN x2[85]
    DIRECTION OUTPUT ;
    USE SIGNAL ;
    PORT
      LAYER M5 ;
        RECT  152.256 69.036 152.28 69.12 ;
    END
  END x2[85]
  PIN x2[86]
    DIRECTION OUTPUT ;
    USE SIGNAL ;
    PORT
      LAYER M5 ;
        RECT  152.496 69.036 152.52 69.12 ;
    END
  END x2[86]
  PIN x2[87]
    DIRECTION OUTPUT ;
    USE SIGNAL ;
    PORT
      LAYER M5 ;
        RECT  152.688 69.036 152.712 69.12 ;
    END
  END x2[87]
  PIN x2[88]
    DIRECTION OUTPUT ;
    USE SIGNAL ;
    PORT
      LAYER M5 ;
        RECT  152.928 69.036 152.952 69.12 ;
    END
  END x2[88]
  PIN x2[89]
    DIRECTION OUTPUT ;
    USE SIGNAL ;
    PORT
      LAYER M5 ;
        RECT  153.168 69.036 153.192 69.12 ;
    END
  END x2[89]
  PIN x2[8]
    DIRECTION OUTPUT ;
    USE SIGNAL ;
    PORT
      LAYER M5 ;
        RECT  133.968 69.036 133.992 69.12 ;
    END
  END x2[8]
  PIN x2[90]
    DIRECTION OUTPUT ;
    USE SIGNAL ;
    PORT
      LAYER M5 ;
        RECT  153.408 69.036 153.432 69.12 ;
    END
  END x2[90]
  PIN x2[91]
    DIRECTION OUTPUT ;
    USE SIGNAL ;
    PORT
      LAYER M5 ;
        RECT  153.648 69.036 153.672 69.12 ;
    END
  END x2[91]
  PIN x2[92]
    DIRECTION OUTPUT ;
    USE SIGNAL ;
    PORT
      LAYER M5 ;
        RECT  153.888 69.036 153.912 69.12 ;
    END
  END x2[92]
  PIN x2[93]
    DIRECTION OUTPUT ;
    USE SIGNAL ;
    PORT
      LAYER M5 ;
        RECT  154.128 69.036 154.152 69.12 ;
    END
  END x2[93]
  PIN x2[94]
    DIRECTION OUTPUT ;
    USE SIGNAL ;
    PORT
      LAYER M5 ;
        RECT  154.368 69.036 154.392 69.12 ;
    END
  END x2[94]
  PIN x2[95]
    DIRECTION OUTPUT ;
    USE SIGNAL ;
    PORT
      LAYER M5 ;
        RECT  154.608 69.036 154.632 69.12 ;
    END
  END x2[95]
  PIN x2[96]
    DIRECTION OUTPUT ;
    USE SIGNAL ;
    PORT
      LAYER M5 ;
        RECT  154.848 69.036 154.872 69.12 ;
    END
  END x2[96]
  PIN x2[97]
    DIRECTION OUTPUT ;
    USE SIGNAL ;
    PORT
      LAYER M5 ;
        RECT  155.088 69.036 155.112 69.12 ;
    END
  END x2[97]
  PIN x2[98]
    DIRECTION OUTPUT ;
    USE SIGNAL ;
    PORT
      LAYER M5 ;
        RECT  155.328 69.036 155.352 69.12 ;
    END
  END x2[98]
  PIN x2[99]
    DIRECTION OUTPUT ;
    USE SIGNAL ;
    PORT
      LAYER M5 ;
        RECT  155.568 69.036 155.592 69.12 ;
    END
  END x2[99]
  PIN x2[9]
    DIRECTION OUTPUT ;
    USE SIGNAL ;
    PORT
      LAYER M5 ;
        RECT  134.208 69.036 134.232 69.12 ;
    END
  END x2[9]
  PIN xa[0]
    DIRECTION OUTPUT ;
    USE SIGNAL ;
    PORT
      LAYER M5 ;
        RECT  1.968 69.036 1.992 69.12 ;
    END
  END xa[0]
  PIN xa[100]
    DIRECTION OUTPUT ;
    USE SIGNAL ;
    PORT
      LAYER M5 ;
        RECT  25.68 69.036 25.704 69.12 ;
    END
  END xa[100]
  PIN xa[101]
    DIRECTION OUTPUT ;
    USE SIGNAL ;
    PORT
      LAYER M5 ;
        RECT  25.92 69.036 25.944 69.12 ;
    END
  END xa[101]
  PIN xa[102]
    DIRECTION OUTPUT ;
    USE SIGNAL ;
    PORT
      LAYER M5 ;
        RECT  26.16 69.036 26.184 69.12 ;
    END
  END xa[102]
  PIN xa[103]
    DIRECTION OUTPUT ;
    USE SIGNAL ;
    PORT
      LAYER M5 ;
        RECT  26.4 69.036 26.424 69.12 ;
    END
  END xa[103]
  PIN xa[104]
    DIRECTION OUTPUT ;
    USE SIGNAL ;
    PORT
      LAYER M5 ;
        RECT  26.64 69.036 26.664 69.12 ;
    END
  END xa[104]
  PIN xa[105]
    DIRECTION OUTPUT ;
    USE SIGNAL ;
    PORT
      LAYER M5 ;
        RECT  26.88 69.036 26.904 69.12 ;
    END
  END xa[105]
  PIN xa[106]
    DIRECTION OUTPUT ;
    USE SIGNAL ;
    PORT
      LAYER M5 ;
        RECT  27.12 69.036 27.144 69.12 ;
    END
  END xa[106]
  PIN xa[107]
    DIRECTION OUTPUT ;
    USE SIGNAL ;
    PORT
      LAYER M5 ;
        RECT  27.36 69.036 27.384 69.12 ;
    END
  END xa[107]
  PIN xa[108]
    DIRECTION OUTPUT ;
    USE SIGNAL ;
    PORT
      LAYER M5 ;
        RECT  27.6 69.036 27.624 69.12 ;
    END
  END xa[108]
  PIN xa[109]
    DIRECTION OUTPUT ;
    USE SIGNAL ;
    PORT
      LAYER M5 ;
        RECT  27.84 69.036 27.864 69.12 ;
    END
  END xa[109]
  PIN xa[10]
    DIRECTION OUTPUT ;
    USE SIGNAL ;
    PORT
      LAYER M5 ;
        RECT  4.368 69.036 4.392 69.12 ;
    END
  END xa[10]
  PIN xa[110]
    DIRECTION OUTPUT ;
    USE SIGNAL ;
    PORT
      LAYER M5 ;
        RECT  28.08 69.036 28.104 69.12 ;
    END
  END xa[110]
  PIN xa[111]
    DIRECTION OUTPUT ;
    USE SIGNAL ;
    PORT
      LAYER M5 ;
        RECT  28.272 69.036 28.296 69.12 ;
    END
  END xa[111]
  PIN xa[112]
    DIRECTION OUTPUT ;
    USE SIGNAL ;
    PORT
      LAYER M5 ;
        RECT  28.512 69.036 28.536 69.12 ;
    END
  END xa[112]
  PIN xa[113]
    DIRECTION OUTPUT ;
    USE SIGNAL ;
    PORT
      LAYER M5 ;
        RECT  28.752 69.036 28.776 69.12 ;
    END
  END xa[113]
  PIN xa[114]
    DIRECTION OUTPUT ;
    USE SIGNAL ;
    PORT
      LAYER M5 ;
        RECT  28.992 69.036 29.016 69.12 ;
    END
  END xa[114]
  PIN xa[115]
    DIRECTION OUTPUT ;
    USE SIGNAL ;
    PORT
      LAYER M5 ;
        RECT  29.232 69.036 29.256 69.12 ;
    END
  END xa[115]
  PIN xa[116]
    DIRECTION OUTPUT ;
    USE SIGNAL ;
    PORT
      LAYER M5 ;
        RECT  29.472 69.036 29.496 69.12 ;
    END
  END xa[116]
  PIN xa[117]
    DIRECTION OUTPUT ;
    USE SIGNAL ;
    PORT
      LAYER M5 ;
        RECT  29.712 69.036 29.736 69.12 ;
    END
  END xa[117]
  PIN xa[118]
    DIRECTION OUTPUT ;
    USE SIGNAL ;
    PORT
      LAYER M5 ;
        RECT  29.952 69.036 29.976 69.12 ;
    END
  END xa[118]
  PIN xa[119]
    DIRECTION OUTPUT ;
    USE SIGNAL ;
    PORT
      LAYER M5 ;
        RECT  30.192 69.036 30.216 69.12 ;
    END
  END xa[119]
  PIN xa[11]
    DIRECTION OUTPUT ;
    USE SIGNAL ;
    PORT
      LAYER M5 ;
        RECT  4.608 69.036 4.632 69.12 ;
    END
  END xa[11]
  PIN xa[120]
    DIRECTION OUTPUT ;
    USE SIGNAL ;
    PORT
      LAYER M5 ;
        RECT  30.432 69.036 30.456 69.12 ;
    END
  END xa[120]
  PIN xa[121]
    DIRECTION OUTPUT ;
    USE SIGNAL ;
    PORT
      LAYER M5 ;
        RECT  30.672 69.036 30.696 69.12 ;
    END
  END xa[121]
  PIN xa[122]
    DIRECTION OUTPUT ;
    USE SIGNAL ;
    PORT
      LAYER M5 ;
        RECT  30.912 69.036 30.936 69.12 ;
    END
  END xa[122]
  PIN xa[123]
    DIRECTION OUTPUT ;
    USE SIGNAL ;
    PORT
      LAYER M5 ;
        RECT  31.152 69.036 31.176 69.12 ;
    END
  END xa[123]
  PIN xa[124]
    DIRECTION OUTPUT ;
    USE SIGNAL ;
    PORT
      LAYER M5 ;
        RECT  31.392 69.036 31.416 69.12 ;
    END
  END xa[124]
  PIN xa[125]
    DIRECTION OUTPUT ;
    USE SIGNAL ;
    PORT
      LAYER M5 ;
        RECT  31.632 69.036 31.656 69.12 ;
    END
  END xa[125]
  PIN xa[126]
    DIRECTION OUTPUT ;
    USE SIGNAL ;
    PORT
      LAYER M5 ;
        RECT  31.872 69.036 31.896 69.12 ;
    END
  END xa[126]
  PIN xa[127]
    DIRECTION OUTPUT ;
    USE SIGNAL ;
    PORT
      LAYER M5 ;
        RECT  32.064 69.036 32.088 69.12 ;
    END
  END xa[127]
  PIN xa[128]
    DIRECTION OUTPUT ;
    USE SIGNAL ;
    PORT
      LAYER M5 ;
        RECT  32.304 69.036 32.328 69.12 ;
    END
  END xa[128]
  PIN xa[129]
    DIRECTION OUTPUT ;
    USE SIGNAL ;
    PORT
      LAYER M5 ;
        RECT  32.544 69.036 32.568 69.12 ;
    END
  END xa[129]
  PIN xa[12]
    DIRECTION OUTPUT ;
    USE SIGNAL ;
    PORT
      LAYER M5 ;
        RECT  4.848 69.036 4.872 69.12 ;
    END
  END xa[12]
  PIN xa[130]
    DIRECTION OUTPUT ;
    USE SIGNAL ;
    PORT
      LAYER M5 ;
        RECT  32.784 69.036 32.808 69.12 ;
    END
  END xa[130]
  PIN xa[131]
    DIRECTION OUTPUT ;
    USE SIGNAL ;
    PORT
      LAYER M5 ;
        RECT  33.024 69.036 33.048 69.12 ;
    END
  END xa[131]
  PIN xa[132]
    DIRECTION OUTPUT ;
    USE SIGNAL ;
    PORT
      LAYER M5 ;
        RECT  33.264 69.036 33.288 69.12 ;
    END
  END xa[132]
  PIN xa[133]
    DIRECTION OUTPUT ;
    USE SIGNAL ;
    PORT
      LAYER M5 ;
        RECT  33.504 69.036 33.528 69.12 ;
    END
  END xa[133]
  PIN xa[134]
    DIRECTION OUTPUT ;
    USE SIGNAL ;
    PORT
      LAYER M5 ;
        RECT  33.744 69.036 33.768 69.12 ;
    END
  END xa[134]
  PIN xa[135]
    DIRECTION OUTPUT ;
    USE SIGNAL ;
    PORT
      LAYER M5 ;
        RECT  33.984 69.036 34.008 69.12 ;
    END
  END xa[135]
  PIN xa[136]
    DIRECTION OUTPUT ;
    USE SIGNAL ;
    PORT
      LAYER M5 ;
        RECT  34.224 69.036 34.248 69.12 ;
    END
  END xa[136]
  PIN xa[137]
    DIRECTION OUTPUT ;
    USE SIGNAL ;
    PORT
      LAYER M5 ;
        RECT  34.464 69.036 34.488 69.12 ;
    END
  END xa[137]
  PIN xa[138]
    DIRECTION OUTPUT ;
    USE SIGNAL ;
    PORT
      LAYER M5 ;
        RECT  34.704 69.036 34.728 69.12 ;
    END
  END xa[138]
  PIN xa[139]
    DIRECTION OUTPUT ;
    USE SIGNAL ;
    PORT
      LAYER M5 ;
        RECT  34.944 69.036 34.968 69.12 ;
    END
  END xa[139]
  PIN xa[13]
    DIRECTION OUTPUT ;
    USE SIGNAL ;
    PORT
      LAYER M5 ;
        RECT  5.088 69.036 5.112 69.12 ;
    END
  END xa[13]
  PIN xa[140]
    DIRECTION OUTPUT ;
    USE SIGNAL ;
    PORT
      LAYER M5 ;
        RECT  35.184 69.036 35.208 69.12 ;
    END
  END xa[140]
  PIN xa[141]
    DIRECTION OUTPUT ;
    USE SIGNAL ;
    PORT
      LAYER M5 ;
        RECT  35.424 69.036 35.448 69.12 ;
    END
  END xa[141]
  PIN xa[142]
    DIRECTION OUTPUT ;
    USE SIGNAL ;
    PORT
      LAYER M5 ;
        RECT  35.664 69.036 35.688 69.12 ;
    END
  END xa[142]
  PIN xa[143]
    DIRECTION OUTPUT ;
    USE SIGNAL ;
    PORT
      LAYER M5 ;
        RECT  35.856 69.036 35.88 69.12 ;
    END
  END xa[143]
  PIN xa[144]
    DIRECTION OUTPUT ;
    USE SIGNAL ;
    PORT
      LAYER M5 ;
        RECT  36.096 69.036 36.12 69.12 ;
    END
  END xa[144]
  PIN xa[145]
    DIRECTION OUTPUT ;
    USE SIGNAL ;
    PORT
      LAYER M5 ;
        RECT  36.336 69.036 36.36 69.12 ;
    END
  END xa[145]
  PIN xa[146]
    DIRECTION OUTPUT ;
    USE SIGNAL ;
    PORT
      LAYER M5 ;
        RECT  36.576 69.036 36.6 69.12 ;
    END
  END xa[146]
  PIN xa[147]
    DIRECTION OUTPUT ;
    USE SIGNAL ;
    PORT
      LAYER M5 ;
        RECT  36.816 69.036 36.84 69.12 ;
    END
  END xa[147]
  PIN xa[148]
    DIRECTION OUTPUT ;
    USE SIGNAL ;
    PORT
      LAYER M5 ;
        RECT  37.056 69.036 37.08 69.12 ;
    END
  END xa[148]
  PIN xa[149]
    DIRECTION OUTPUT ;
    USE SIGNAL ;
    PORT
      LAYER M5 ;
        RECT  37.296 69.036 37.32 69.12 ;
    END
  END xa[149]
  PIN xa[14]
    DIRECTION OUTPUT ;
    USE SIGNAL ;
    PORT
      LAYER M5 ;
        RECT  5.328 69.036 5.352 69.12 ;
    END
  END xa[14]
  PIN xa[150]
    DIRECTION OUTPUT ;
    USE SIGNAL ;
    PORT
      LAYER M5 ;
        RECT  37.536 69.036 37.56 69.12 ;
    END
  END xa[150]
  PIN xa[151]
    DIRECTION OUTPUT ;
    USE SIGNAL ;
    PORT
      LAYER M5 ;
        RECT  37.776 69.036 37.8 69.12 ;
    END
  END xa[151]
  PIN xa[152]
    DIRECTION OUTPUT ;
    USE SIGNAL ;
    PORT
      LAYER M5 ;
        RECT  38.016 69.036 38.04 69.12 ;
    END
  END xa[152]
  PIN xa[153]
    DIRECTION OUTPUT ;
    USE SIGNAL ;
    PORT
      LAYER M5 ;
        RECT  38.256 69.036 38.28 69.12 ;
    END
  END xa[153]
  PIN xa[154]
    DIRECTION OUTPUT ;
    USE SIGNAL ;
    PORT
      LAYER M5 ;
        RECT  38.496 69.036 38.52 69.12 ;
    END
  END xa[154]
  PIN xa[155]
    DIRECTION OUTPUT ;
    USE SIGNAL ;
    PORT
      LAYER M5 ;
        RECT  38.736 69.036 38.76 69.12 ;
    END
  END xa[155]
  PIN xa[156]
    DIRECTION OUTPUT ;
    USE SIGNAL ;
    PORT
      LAYER M5 ;
        RECT  38.976 69.036 39 69.12 ;
    END
  END xa[156]
  PIN xa[157]
    DIRECTION OUTPUT ;
    USE SIGNAL ;
    PORT
      LAYER M5 ;
        RECT  39.216 69.036 39.24 69.12 ;
    END
  END xa[157]
  PIN xa[158]
    DIRECTION OUTPUT ;
    USE SIGNAL ;
    PORT
      LAYER M5 ;
        RECT  39.408 69.036 39.432 69.12 ;
    END
  END xa[158]
  PIN xa[159]
    DIRECTION OUTPUT ;
    USE SIGNAL ;
    PORT
      LAYER M5 ;
        RECT  39.648 69.036 39.672 69.12 ;
    END
  END xa[159]
  PIN xa[15]
    DIRECTION OUTPUT ;
    USE SIGNAL ;
    PORT
      LAYER M5 ;
        RECT  5.52 69.036 5.544 69.12 ;
    END
  END xa[15]
  PIN xa[160]
    DIRECTION OUTPUT ;
    USE SIGNAL ;
    PORT
      LAYER M5 ;
        RECT  39.888 69.036 39.912 69.12 ;
    END
  END xa[160]
  PIN xa[161]
    DIRECTION OUTPUT ;
    USE SIGNAL ;
    PORT
      LAYER M5 ;
        RECT  40.128 69.036 40.152 69.12 ;
    END
  END xa[161]
  PIN xa[162]
    DIRECTION OUTPUT ;
    USE SIGNAL ;
    PORT
      LAYER M5 ;
        RECT  40.368 69.036 40.392 69.12 ;
    END
  END xa[162]
  PIN xa[163]
    DIRECTION OUTPUT ;
    USE SIGNAL ;
    PORT
      LAYER M5 ;
        RECT  40.608 69.036 40.632 69.12 ;
    END
  END xa[163]
  PIN xa[164]
    DIRECTION OUTPUT ;
    USE SIGNAL ;
    PORT
      LAYER M5 ;
        RECT  40.848 69.036 40.872 69.12 ;
    END
  END xa[164]
  PIN xa[165]
    DIRECTION OUTPUT ;
    USE SIGNAL ;
    PORT
      LAYER M5 ;
        RECT  41.088 69.036 41.112 69.12 ;
    END
  END xa[165]
  PIN xa[166]
    DIRECTION OUTPUT ;
    USE SIGNAL ;
    PORT
      LAYER M5 ;
        RECT  41.328 69.036 41.352 69.12 ;
    END
  END xa[166]
  PIN xa[167]
    DIRECTION OUTPUT ;
    USE SIGNAL ;
    PORT
      LAYER M5 ;
        RECT  41.568 69.036 41.592 69.12 ;
    END
  END xa[167]
  PIN xa[168]
    DIRECTION OUTPUT ;
    USE SIGNAL ;
    PORT
      LAYER M5 ;
        RECT  41.808 69.036 41.832 69.12 ;
    END
  END xa[168]
  PIN xa[169]
    DIRECTION OUTPUT ;
    USE SIGNAL ;
    PORT
      LAYER M5 ;
        RECT  42.048 69.036 42.072 69.12 ;
    END
  END xa[169]
  PIN xa[16]
    DIRECTION OUTPUT ;
    USE SIGNAL ;
    PORT
      LAYER M5 ;
        RECT  5.76 69.036 5.784 69.12 ;
    END
  END xa[16]
  PIN xa[170]
    DIRECTION OUTPUT ;
    USE SIGNAL ;
    PORT
      LAYER M5 ;
        RECT  42.288 69.036 42.312 69.12 ;
    END
  END xa[170]
  PIN xa[171]
    DIRECTION OUTPUT ;
    USE SIGNAL ;
    PORT
      LAYER M5 ;
        RECT  42.528 69.036 42.552 69.12 ;
    END
  END xa[171]
  PIN xa[172]
    DIRECTION OUTPUT ;
    USE SIGNAL ;
    PORT
      LAYER M5 ;
        RECT  42.768 69.036 42.792 69.12 ;
    END
  END xa[172]
  PIN xa[173]
    DIRECTION OUTPUT ;
    USE SIGNAL ;
    PORT
      LAYER M5 ;
        RECT  43.008 69.036 43.032 69.12 ;
    END
  END xa[173]
  PIN xa[174]
    DIRECTION OUTPUT ;
    USE SIGNAL ;
    PORT
      LAYER M5 ;
        RECT  43.2 69.036 43.224 69.12 ;
    END
  END xa[174]
  PIN xa[175]
    DIRECTION OUTPUT ;
    USE SIGNAL ;
    PORT
      LAYER M5 ;
        RECT  43.44 69.036 43.464 69.12 ;
    END
  END xa[175]
  PIN xa[176]
    DIRECTION OUTPUT ;
    USE SIGNAL ;
    PORT
      LAYER M5 ;
        RECT  43.68 69.036 43.704 69.12 ;
    END
  END xa[176]
  PIN xa[177]
    DIRECTION OUTPUT ;
    USE SIGNAL ;
    PORT
      LAYER M5 ;
        RECT  43.92 69.036 43.944 69.12 ;
    END
  END xa[177]
  PIN xa[178]
    DIRECTION OUTPUT ;
    USE SIGNAL ;
    PORT
      LAYER M5 ;
        RECT  44.16 69.036 44.184 69.12 ;
    END
  END xa[178]
  PIN xa[179]
    DIRECTION OUTPUT ;
    USE SIGNAL ;
    PORT
      LAYER M5 ;
        RECT  44.4 69.036 44.424 69.12 ;
    END
  END xa[179]
  PIN xa[17]
    DIRECTION OUTPUT ;
    USE SIGNAL ;
    PORT
      LAYER M5 ;
        RECT  6 69.036 6.024 69.12 ;
    END
  END xa[17]
  PIN xa[180]
    DIRECTION OUTPUT ;
    USE SIGNAL ;
    PORT
      LAYER M5 ;
        RECT  44.64 69.036 44.664 69.12 ;
    END
  END xa[180]
  PIN xa[181]
    DIRECTION OUTPUT ;
    USE SIGNAL ;
    PORT
      LAYER M5 ;
        RECT  44.88 69.036 44.904 69.12 ;
    END
  END xa[181]
  PIN xa[182]
    DIRECTION OUTPUT ;
    USE SIGNAL ;
    PORT
      LAYER M5 ;
        RECT  45.12 69.036 45.144 69.12 ;
    END
  END xa[182]
  PIN xa[183]
    DIRECTION OUTPUT ;
    USE SIGNAL ;
    PORT
      LAYER M5 ;
        RECT  45.36 69.036 45.384 69.12 ;
    END
  END xa[183]
  PIN xa[184]
    DIRECTION OUTPUT ;
    USE SIGNAL ;
    PORT
      LAYER M5 ;
        RECT  45.6 69.036 45.624 69.12 ;
    END
  END xa[184]
  PIN xa[185]
    DIRECTION OUTPUT ;
    USE SIGNAL ;
    PORT
      LAYER M5 ;
        RECT  45.84 69.036 45.864 69.12 ;
    END
  END xa[185]
  PIN xa[186]
    DIRECTION OUTPUT ;
    USE SIGNAL ;
    PORT
      LAYER M5 ;
        RECT  46.08 69.036 46.104 69.12 ;
    END
  END xa[186]
  PIN xa[187]
    DIRECTION OUTPUT ;
    USE SIGNAL ;
    PORT
      LAYER M5 ;
        RECT  46.32 69.036 46.344 69.12 ;
    END
  END xa[187]
  PIN xa[188]
    DIRECTION OUTPUT ;
    USE SIGNAL ;
    PORT
      LAYER M5 ;
        RECT  46.56 69.036 46.584 69.12 ;
    END
  END xa[188]
  PIN xa[189]
    DIRECTION OUTPUT ;
    USE SIGNAL ;
    PORT
      LAYER M5 ;
        RECT  46.8 69.036 46.824 69.12 ;
    END
  END xa[189]
  PIN xa[18]
    DIRECTION OUTPUT ;
    USE SIGNAL ;
    PORT
      LAYER M5 ;
        RECT  6.24 69.036 6.264 69.12 ;
    END
  END xa[18]
  PIN xa[190]
    DIRECTION OUTPUT ;
    USE SIGNAL ;
    PORT
      LAYER M5 ;
        RECT  46.992 69.036 47.016 69.12 ;
    END
  END xa[190]
  PIN xa[191]
    DIRECTION OUTPUT ;
    USE SIGNAL ;
    PORT
      LAYER M5 ;
        RECT  47.232 69.036 47.256 69.12 ;
    END
  END xa[191]
  PIN xa[192]
    DIRECTION OUTPUT ;
    USE SIGNAL ;
    PORT
      LAYER M5 ;
        RECT  47.472 69.036 47.496 69.12 ;
    END
  END xa[192]
  PIN xa[193]
    DIRECTION OUTPUT ;
    USE SIGNAL ;
    PORT
      LAYER M5 ;
        RECT  47.712 69.036 47.736 69.12 ;
    END
  END xa[193]
  PIN xa[194]
    DIRECTION OUTPUT ;
    USE SIGNAL ;
    PORT
      LAYER M5 ;
        RECT  47.952 69.036 47.976 69.12 ;
    END
  END xa[194]
  PIN xa[195]
    DIRECTION OUTPUT ;
    USE SIGNAL ;
    PORT
      LAYER M5 ;
        RECT  48.192 69.036 48.216 69.12 ;
    END
  END xa[195]
  PIN xa[196]
    DIRECTION OUTPUT ;
    USE SIGNAL ;
    PORT
      LAYER M5 ;
        RECT  48.432 69.036 48.456 69.12 ;
    END
  END xa[196]
  PIN xa[197]
    DIRECTION OUTPUT ;
    USE SIGNAL ;
    PORT
      LAYER M5 ;
        RECT  48.672 69.036 48.696 69.12 ;
    END
  END xa[197]
  PIN xa[198]
    DIRECTION OUTPUT ;
    USE SIGNAL ;
    PORT
      LAYER M5 ;
        RECT  48.912 69.036 48.936 69.12 ;
    END
  END xa[198]
  PIN xa[199]
    DIRECTION OUTPUT ;
    USE SIGNAL ;
    PORT
      LAYER M5 ;
        RECT  49.152 69.036 49.176 69.12 ;
    END
  END xa[199]
  PIN xa[19]
    DIRECTION OUTPUT ;
    USE SIGNAL ;
    PORT
      LAYER M5 ;
        RECT  6.48 69.036 6.504 69.12 ;
    END
  END xa[19]
  PIN xa[1]
    DIRECTION OUTPUT ;
    USE SIGNAL ;
    PORT
      LAYER M5 ;
        RECT  2.208 69.036 2.232 69.12 ;
    END
  END xa[1]
  PIN xa[200]
    DIRECTION OUTPUT ;
    USE SIGNAL ;
    PORT
      LAYER M5 ;
        RECT  49.392 69.036 49.416 69.12 ;
    END
  END xa[200]
  PIN xa[201]
    DIRECTION OUTPUT ;
    USE SIGNAL ;
    PORT
      LAYER M5 ;
        RECT  49.632 69.036 49.656 69.12 ;
    END
  END xa[201]
  PIN xa[202]
    DIRECTION OUTPUT ;
    USE SIGNAL ;
    PORT
      LAYER M5 ;
        RECT  49.872 69.036 49.896 69.12 ;
    END
  END xa[202]
  PIN xa[203]
    DIRECTION OUTPUT ;
    USE SIGNAL ;
    PORT
      LAYER M5 ;
        RECT  50.112 69.036 50.136 69.12 ;
    END
  END xa[203]
  PIN xa[204]
    DIRECTION OUTPUT ;
    USE SIGNAL ;
    PORT
      LAYER M5 ;
        RECT  50.352 69.036 50.376 69.12 ;
    END
  END xa[204]
  PIN xa[205]
    DIRECTION OUTPUT ;
    USE SIGNAL ;
    PORT
      LAYER M5 ;
        RECT  50.592 69.036 50.616 69.12 ;
    END
  END xa[205]
  PIN xa[206]
    DIRECTION OUTPUT ;
    USE SIGNAL ;
    PORT
      LAYER M5 ;
        RECT  50.784 69.036 50.808 69.12 ;
    END
  END xa[206]
  PIN xa[207]
    DIRECTION OUTPUT ;
    USE SIGNAL ;
    PORT
      LAYER M5 ;
        RECT  51.024 69.036 51.048 69.12 ;
    END
  END xa[207]
  PIN xa[208]
    DIRECTION OUTPUT ;
    USE SIGNAL ;
    PORT
      LAYER M5 ;
        RECT  51.264 69.036 51.288 69.12 ;
    END
  END xa[208]
  PIN xa[209]
    DIRECTION OUTPUT ;
    USE SIGNAL ;
    PORT
      LAYER M5 ;
        RECT  51.504 69.036 51.528 69.12 ;
    END
  END xa[209]
  PIN xa[20]
    DIRECTION OUTPUT ;
    USE SIGNAL ;
    PORT
      LAYER M5 ;
        RECT  6.72 69.036 6.744 69.12 ;
    END
  END xa[20]
  PIN xa[210]
    DIRECTION OUTPUT ;
    USE SIGNAL ;
    PORT
      LAYER M5 ;
        RECT  51.744 69.036 51.768 69.12 ;
    END
  END xa[210]
  PIN xa[211]
    DIRECTION OUTPUT ;
    USE SIGNAL ;
    PORT
      LAYER M5 ;
        RECT  51.984 69.036 52.008 69.12 ;
    END
  END xa[211]
  PIN xa[212]
    DIRECTION OUTPUT ;
    USE SIGNAL ;
    PORT
      LAYER M5 ;
        RECT  52.224 69.036 52.248 69.12 ;
    END
  END xa[212]
  PIN xa[213]
    DIRECTION OUTPUT ;
    USE SIGNAL ;
    PORT
      LAYER M5 ;
        RECT  52.464 69.036 52.488 69.12 ;
    END
  END xa[213]
  PIN xa[214]
    DIRECTION OUTPUT ;
    USE SIGNAL ;
    PORT
      LAYER M5 ;
        RECT  52.704 69.036 52.728 69.12 ;
    END
  END xa[214]
  PIN xa[215]
    DIRECTION OUTPUT ;
    USE SIGNAL ;
    PORT
      LAYER M5 ;
        RECT  52.944 69.036 52.968 69.12 ;
    END
  END xa[215]
  PIN xa[216]
    DIRECTION OUTPUT ;
    USE SIGNAL ;
    PORT
      LAYER M5 ;
        RECT  53.184 69.036 53.208 69.12 ;
    END
  END xa[216]
  PIN xa[217]
    DIRECTION OUTPUT ;
    USE SIGNAL ;
    PORT
      LAYER M5 ;
        RECT  53.424 69.036 53.448 69.12 ;
    END
  END xa[217]
  PIN xa[218]
    DIRECTION OUTPUT ;
    USE SIGNAL ;
    PORT
      LAYER M5 ;
        RECT  53.664 69.036 53.688 69.12 ;
    END
  END xa[218]
  PIN xa[219]
    DIRECTION OUTPUT ;
    USE SIGNAL ;
    PORT
      LAYER M5 ;
        RECT  53.904 69.036 53.928 69.12 ;
    END
  END xa[219]
  PIN xa[21]
    DIRECTION OUTPUT ;
    USE SIGNAL ;
    PORT
      LAYER M5 ;
        RECT  6.96 69.036 6.984 69.12 ;
    END
  END xa[21]
  PIN xa[220]
    DIRECTION OUTPUT ;
    USE SIGNAL ;
    PORT
      LAYER M5 ;
        RECT  54.144 69.036 54.168 69.12 ;
    END
  END xa[220]
  PIN xa[221]
    DIRECTION OUTPUT ;
    USE SIGNAL ;
    PORT
      LAYER M5 ;
        RECT  54.384 69.036 54.408 69.12 ;
    END
  END xa[221]
  PIN xa[222]
    DIRECTION OUTPUT ;
    USE SIGNAL ;
    PORT
      LAYER M5 ;
        RECT  54.576 69.036 54.6 69.12 ;
    END
  END xa[222]
  PIN xa[223]
    DIRECTION OUTPUT ;
    USE SIGNAL ;
    PORT
      LAYER M5 ;
        RECT  54.816 69.036 54.84 69.12 ;
    END
  END xa[223]
  PIN xa[224]
    DIRECTION OUTPUT ;
    USE SIGNAL ;
    PORT
      LAYER M5 ;
        RECT  55.056 69.036 55.08 69.12 ;
    END
  END xa[224]
  PIN xa[225]
    DIRECTION OUTPUT ;
    USE SIGNAL ;
    PORT
      LAYER M5 ;
        RECT  55.296 69.036 55.32 69.12 ;
    END
  END xa[225]
  PIN xa[226]
    DIRECTION OUTPUT ;
    USE SIGNAL ;
    PORT
      LAYER M5 ;
        RECT  55.536 69.036 55.56 69.12 ;
    END
  END xa[226]
  PIN xa[227]
    DIRECTION OUTPUT ;
    USE SIGNAL ;
    PORT
      LAYER M5 ;
        RECT  55.776 69.036 55.8 69.12 ;
    END
  END xa[227]
  PIN xa[228]
    DIRECTION OUTPUT ;
    USE SIGNAL ;
    PORT
      LAYER M5 ;
        RECT  56.016 69.036 56.04 69.12 ;
    END
  END xa[228]
  PIN xa[229]
    DIRECTION OUTPUT ;
    USE SIGNAL ;
    PORT
      LAYER M5 ;
        RECT  56.256 69.036 56.28 69.12 ;
    END
  END xa[229]
  PIN xa[22]
    DIRECTION OUTPUT ;
    USE SIGNAL ;
    PORT
      LAYER M5 ;
        RECT  7.2 69.036 7.224 69.12 ;
    END
  END xa[22]
  PIN xa[230]
    DIRECTION OUTPUT ;
    USE SIGNAL ;
    PORT
      LAYER M5 ;
        RECT  56.496 69.036 56.52 69.12 ;
    END
  END xa[230]
  PIN xa[231]
    DIRECTION OUTPUT ;
    USE SIGNAL ;
    PORT
      LAYER M5 ;
        RECT  56.736 69.036 56.76 69.12 ;
    END
  END xa[231]
  PIN xa[232]
    DIRECTION OUTPUT ;
    USE SIGNAL ;
    PORT
      LAYER M5 ;
        RECT  56.976 69.036 57 69.12 ;
    END
  END xa[232]
  PIN xa[233]
    DIRECTION OUTPUT ;
    USE SIGNAL ;
    PORT
      LAYER M5 ;
        RECT  57.216 69.036 57.24 69.12 ;
    END
  END xa[233]
  PIN xa[234]
    DIRECTION OUTPUT ;
    USE SIGNAL ;
    PORT
      LAYER M5 ;
        RECT  57.456 69.036 57.48 69.12 ;
    END
  END xa[234]
  PIN xa[235]
    DIRECTION OUTPUT ;
    USE SIGNAL ;
    PORT
      LAYER M5 ;
        RECT  57.696 69.036 57.72 69.12 ;
    END
  END xa[235]
  PIN xa[236]
    DIRECTION OUTPUT ;
    USE SIGNAL ;
    PORT
      LAYER M5 ;
        RECT  57.936 69.036 57.96 69.12 ;
    END
  END xa[236]
  PIN xa[237]
    DIRECTION OUTPUT ;
    USE SIGNAL ;
    PORT
      LAYER M5 ;
        RECT  58.176 69.036 58.2 69.12 ;
    END
  END xa[237]
  PIN xa[238]
    DIRECTION OUTPUT ;
    USE SIGNAL ;
    PORT
      LAYER M5 ;
        RECT  58.368 69.036 58.392 69.12 ;
    END
  END xa[238]
  PIN xa[239]
    DIRECTION OUTPUT ;
    USE SIGNAL ;
    PORT
      LAYER M5 ;
        RECT  58.608 69.036 58.632 69.12 ;
    END
  END xa[239]
  PIN xa[23]
    DIRECTION OUTPUT ;
    USE SIGNAL ;
    PORT
      LAYER M5 ;
        RECT  7.44 69.036 7.464 69.12 ;
    END
  END xa[23]
  PIN xa[240]
    DIRECTION OUTPUT ;
    USE SIGNAL ;
    PORT
      LAYER M5 ;
        RECT  58.848 69.036 58.872 69.12 ;
    END
  END xa[240]
  PIN xa[241]
    DIRECTION OUTPUT ;
    USE SIGNAL ;
    PORT
      LAYER M5 ;
        RECT  59.088 69.036 59.112 69.12 ;
    END
  END xa[241]
  PIN xa[242]
    DIRECTION OUTPUT ;
    USE SIGNAL ;
    PORT
      LAYER M5 ;
        RECT  59.328 69.036 59.352 69.12 ;
    END
  END xa[242]
  PIN xa[243]
    DIRECTION OUTPUT ;
    USE SIGNAL ;
    PORT
      LAYER M5 ;
        RECT  59.568 69.036 59.592 69.12 ;
    END
  END xa[243]
  PIN xa[244]
    DIRECTION OUTPUT ;
    USE SIGNAL ;
    PORT
      LAYER M5 ;
        RECT  59.808 69.036 59.832 69.12 ;
    END
  END xa[244]
  PIN xa[245]
    DIRECTION OUTPUT ;
    USE SIGNAL ;
    PORT
      LAYER M5 ;
        RECT  60.048 69.036 60.072 69.12 ;
    END
  END xa[245]
  PIN xa[246]
    DIRECTION OUTPUT ;
    USE SIGNAL ;
    PORT
      LAYER M5 ;
        RECT  60.288 69.036 60.312 69.12 ;
    END
  END xa[246]
  PIN xa[247]
    DIRECTION OUTPUT ;
    USE SIGNAL ;
    PORT
      LAYER M5 ;
        RECT  60.528 69.036 60.552 69.12 ;
    END
  END xa[247]
  PIN xa[248]
    DIRECTION OUTPUT ;
    USE SIGNAL ;
    PORT
      LAYER M5 ;
        RECT  60.768 69.036 60.792 69.12 ;
    END
  END xa[248]
  PIN xa[249]
    DIRECTION OUTPUT ;
    USE SIGNAL ;
    PORT
      LAYER M5 ;
        RECT  61.008 69.036 61.032 69.12 ;
    END
  END xa[249]
  PIN xa[24]
    DIRECTION OUTPUT ;
    USE SIGNAL ;
    PORT
      LAYER M5 ;
        RECT  7.68 69.036 7.704 69.12 ;
    END
  END xa[24]
  PIN xa[250]
    DIRECTION OUTPUT ;
    USE SIGNAL ;
    PORT
      LAYER M5 ;
        RECT  61.248 69.036 61.272 69.12 ;
    END
  END xa[250]
  PIN xa[251]
    DIRECTION OUTPUT ;
    USE SIGNAL ;
    PORT
      LAYER M5 ;
        RECT  61.488 69.036 61.512 69.12 ;
    END
  END xa[251]
  PIN xa[252]
    DIRECTION OUTPUT ;
    USE SIGNAL ;
    PORT
      LAYER M5 ;
        RECT  61.728 69.036 61.752 69.12 ;
    END
  END xa[252]
  PIN xa[253]
    DIRECTION OUTPUT ;
    USE SIGNAL ;
    PORT
      LAYER M5 ;
        RECT  61.968 69.036 61.992 69.12 ;
    END
  END xa[253]
  PIN xa[254]
    DIRECTION OUTPUT ;
    USE SIGNAL ;
    PORT
      LAYER M5 ;
        RECT  62.16 69.036 62.184 69.12 ;
    END
  END xa[254]
  PIN xa[255]
    DIRECTION OUTPUT ;
    USE SIGNAL ;
    PORT
      LAYER M5 ;
        RECT  62.4 69.036 62.424 69.12 ;
    END
  END xa[255]
  PIN xa[256]
    DIRECTION OUTPUT ;
    USE SIGNAL ;
    PORT
      LAYER M5 ;
        RECT  62.64 69.036 62.664 69.12 ;
    END
  END xa[256]
  PIN xa[257]
    DIRECTION OUTPUT ;
    USE SIGNAL ;
    PORT
      LAYER M5 ;
        RECT  62.88 69.036 62.904 69.12 ;
    END
  END xa[257]
  PIN xa[258]
    DIRECTION OUTPUT ;
    USE SIGNAL ;
    PORT
      LAYER M5 ;
        RECT  63.12 69.036 63.144 69.12 ;
    END
  END xa[258]
  PIN xa[259]
    DIRECTION OUTPUT ;
    USE SIGNAL ;
    PORT
      LAYER M5 ;
        RECT  63.36 69.036 63.384 69.12 ;
    END
  END xa[259]
  PIN xa[25]
    DIRECTION OUTPUT ;
    USE SIGNAL ;
    PORT
      LAYER M5 ;
        RECT  7.92 69.036 7.944 69.12 ;
    END
  END xa[25]
  PIN xa[260]
    DIRECTION OUTPUT ;
    USE SIGNAL ;
    PORT
      LAYER M5 ;
        RECT  63.6 69.036 63.624 69.12 ;
    END
  END xa[260]
  PIN xa[261]
    DIRECTION OUTPUT ;
    USE SIGNAL ;
    PORT
      LAYER M5 ;
        RECT  63.84 69.036 63.864 69.12 ;
    END
  END xa[261]
  PIN xa[262]
    DIRECTION OUTPUT ;
    USE SIGNAL ;
    PORT
      LAYER M5 ;
        RECT  64.08 69.036 64.104 69.12 ;
    END
  END xa[262]
  PIN xa[263]
    DIRECTION OUTPUT ;
    USE SIGNAL ;
    PORT
      LAYER M5 ;
        RECT  64.32 69.036 64.344 69.12 ;
    END
  END xa[263]
  PIN xa[264]
    DIRECTION OUTPUT ;
    USE SIGNAL ;
    PORT
      LAYER M5 ;
        RECT  64.56 69.036 64.584 69.12 ;
    END
  END xa[264]
  PIN xa[265]
    DIRECTION OUTPUT ;
    USE SIGNAL ;
    PORT
      LAYER M5 ;
        RECT  64.8 69.036 64.824 69.12 ;
    END
  END xa[265]
  PIN xa[266]
    DIRECTION OUTPUT ;
    USE SIGNAL ;
    PORT
      LAYER M5 ;
        RECT  65.04 69.036 65.064 69.12 ;
    END
  END xa[266]
  PIN xa[267]
    DIRECTION OUTPUT ;
    USE SIGNAL ;
    PORT
      LAYER M5 ;
        RECT  65.28 69.036 65.304 69.12 ;
    END
  END xa[267]
  PIN xa[268]
    DIRECTION OUTPUT ;
    USE SIGNAL ;
    PORT
      LAYER M5 ;
        RECT  65.52 69.036 65.544 69.12 ;
    END
  END xa[268]
  PIN xa[269]
    DIRECTION OUTPUT ;
    USE SIGNAL ;
    PORT
      LAYER M5 ;
        RECT  65.76 69.036 65.784 69.12 ;
    END
  END xa[269]
  PIN xa[26]
    DIRECTION OUTPUT ;
    USE SIGNAL ;
    PORT
      LAYER M5 ;
        RECT  8.16 69.036 8.184 69.12 ;
    END
  END xa[26]
  PIN xa[270]
    DIRECTION OUTPUT ;
    USE SIGNAL ;
    PORT
      LAYER M5 ;
        RECT  65.952 69.036 65.976 69.12 ;
    END
  END xa[270]
  PIN xa[271]
    DIRECTION OUTPUT ;
    USE SIGNAL ;
    PORT
      LAYER M5 ;
        RECT  66.192 69.036 66.216 69.12 ;
    END
  END xa[271]
  PIN xa[272]
    DIRECTION OUTPUT ;
    USE SIGNAL ;
    PORT
      LAYER M5 ;
        RECT  66.432 69.036 66.456 69.12 ;
    END
  END xa[272]
  PIN xa[273]
    DIRECTION OUTPUT ;
    USE SIGNAL ;
    PORT
      LAYER M5 ;
        RECT  66.672 69.036 66.696 69.12 ;
    END
  END xa[273]
  PIN xa[274]
    DIRECTION OUTPUT ;
    USE SIGNAL ;
    PORT
      LAYER M5 ;
        RECT  66.912 69.036 66.936 69.12 ;
    END
  END xa[274]
  PIN xa[275]
    DIRECTION OUTPUT ;
    USE SIGNAL ;
    PORT
      LAYER M5 ;
        RECT  67.152 69.036 67.176 69.12 ;
    END
  END xa[275]
  PIN xa[276]
    DIRECTION OUTPUT ;
    USE SIGNAL ;
    PORT
      LAYER M5 ;
        RECT  67.392 69.036 67.416 69.12 ;
    END
  END xa[276]
  PIN xa[277]
    DIRECTION OUTPUT ;
    USE SIGNAL ;
    PORT
      LAYER M5 ;
        RECT  67.632 69.036 67.656 69.12 ;
    END
  END xa[277]
  PIN xa[278]
    DIRECTION OUTPUT ;
    USE SIGNAL ;
    PORT
      LAYER M5 ;
        RECT  67.872 69.036 67.896 69.12 ;
    END
  END xa[278]
  PIN xa[279]
    DIRECTION OUTPUT ;
    USE SIGNAL ;
    PORT
      LAYER M5 ;
        RECT  68.112 69.036 68.136 69.12 ;
    END
  END xa[279]
  PIN xa[27]
    DIRECTION OUTPUT ;
    USE SIGNAL ;
    PORT
      LAYER M5 ;
        RECT  8.4 69.036 8.424 69.12 ;
    END
  END xa[27]
  PIN xa[280]
    DIRECTION OUTPUT ;
    USE SIGNAL ;
    PORT
      LAYER M5 ;
        RECT  68.352 69.036 68.376 69.12 ;
    END
  END xa[280]
  PIN xa[281]
    DIRECTION OUTPUT ;
    USE SIGNAL ;
    PORT
      LAYER M5 ;
        RECT  68.592 69.036 68.616 69.12 ;
    END
  END xa[281]
  PIN xa[282]
    DIRECTION OUTPUT ;
    USE SIGNAL ;
    PORT
      LAYER M5 ;
        RECT  68.832 69.036 68.856 69.12 ;
    END
  END xa[282]
  PIN xa[28]
    DIRECTION OUTPUT ;
    USE SIGNAL ;
    PORT
      LAYER M5 ;
        RECT  8.64 69.036 8.664 69.12 ;
    END
  END xa[28]
  PIN xa[29]
    DIRECTION OUTPUT ;
    USE SIGNAL ;
    PORT
      LAYER M5 ;
        RECT  8.88 69.036 8.904 69.12 ;
    END
  END xa[29]
  PIN xa[2]
    DIRECTION OUTPUT ;
    USE SIGNAL ;
    PORT
      LAYER M5 ;
        RECT  2.448 69.036 2.472 69.12 ;
    END
  END xa[2]
  PIN xa[30]
    DIRECTION OUTPUT ;
    USE SIGNAL ;
    PORT
      LAYER M5 ;
        RECT  9.12 69.036 9.144 69.12 ;
    END
  END xa[30]
  PIN xa[31]
    DIRECTION OUTPUT ;
    USE SIGNAL ;
    PORT
      LAYER M5 ;
        RECT  9.312 69.036 9.336 69.12 ;
    END
  END xa[31]
  PIN xa[32]
    DIRECTION OUTPUT ;
    USE SIGNAL ;
    PORT
      LAYER M5 ;
        RECT  9.552 69.036 9.576 69.12 ;
    END
  END xa[32]
  PIN xa[33]
    DIRECTION OUTPUT ;
    USE SIGNAL ;
    PORT
      LAYER M5 ;
        RECT  9.792 69.036 9.816 69.12 ;
    END
  END xa[33]
  PIN xa[34]
    DIRECTION OUTPUT ;
    USE SIGNAL ;
    PORT
      LAYER M5 ;
        RECT  10.032 69.036 10.056 69.12 ;
    END
  END xa[34]
  PIN xa[35]
    DIRECTION OUTPUT ;
    USE SIGNAL ;
    PORT
      LAYER M5 ;
        RECT  10.272 69.036 10.296 69.12 ;
    END
  END xa[35]
  PIN xa[36]
    DIRECTION OUTPUT ;
    USE SIGNAL ;
    PORT
      LAYER M5 ;
        RECT  10.512 69.036 10.536 69.12 ;
    END
  END xa[36]
  PIN xa[37]
    DIRECTION OUTPUT ;
    USE SIGNAL ;
    PORT
      LAYER M5 ;
        RECT  10.752 69.036 10.776 69.12 ;
    END
  END xa[37]
  PIN xa[38]
    DIRECTION OUTPUT ;
    USE SIGNAL ;
    PORT
      LAYER M5 ;
        RECT  10.992 69.036 11.016 69.12 ;
    END
  END xa[38]
  PIN xa[39]
    DIRECTION OUTPUT ;
    USE SIGNAL ;
    PORT
      LAYER M5 ;
        RECT  11.232 69.036 11.256 69.12 ;
    END
  END xa[39]
  PIN xa[3]
    DIRECTION OUTPUT ;
    USE SIGNAL ;
    PORT
      LAYER M5 ;
        RECT  2.688 69.036 2.712 69.12 ;
    END
  END xa[3]
  PIN xa[40]
    DIRECTION OUTPUT ;
    USE SIGNAL ;
    PORT
      LAYER M5 ;
        RECT  11.472 69.036 11.496 69.12 ;
    END
  END xa[40]
  PIN xa[41]
    DIRECTION OUTPUT ;
    USE SIGNAL ;
    PORT
      LAYER M5 ;
        RECT  11.712 69.036 11.736 69.12 ;
    END
  END xa[41]
  PIN xa[42]
    DIRECTION OUTPUT ;
    USE SIGNAL ;
    PORT
      LAYER M5 ;
        RECT  11.952 69.036 11.976 69.12 ;
    END
  END xa[42]
  PIN xa[43]
    DIRECTION OUTPUT ;
    USE SIGNAL ;
    PORT
      LAYER M5 ;
        RECT  12.192 69.036 12.216 69.12 ;
    END
  END xa[43]
  PIN xa[44]
    DIRECTION OUTPUT ;
    USE SIGNAL ;
    PORT
      LAYER M5 ;
        RECT  12.432 69.036 12.456 69.12 ;
    END
  END xa[44]
  PIN xa[45]
    DIRECTION OUTPUT ;
    USE SIGNAL ;
    PORT
      LAYER M5 ;
        RECT  12.672 69.036 12.696 69.12 ;
    END
  END xa[45]
  PIN xa[46]
    DIRECTION OUTPUT ;
    USE SIGNAL ;
    PORT
      LAYER M5 ;
        RECT  12.912 69.036 12.936 69.12 ;
    END
  END xa[46]
  PIN xa[47]
    DIRECTION OUTPUT ;
    USE SIGNAL ;
    PORT
      LAYER M5 ;
        RECT  13.104 69.036 13.128 69.12 ;
    END
  END xa[47]
  PIN xa[48]
    DIRECTION OUTPUT ;
    USE SIGNAL ;
    PORT
      LAYER M5 ;
        RECT  13.344 69.036 13.368 69.12 ;
    END
  END xa[48]
  PIN xa[49]
    DIRECTION OUTPUT ;
    USE SIGNAL ;
    PORT
      LAYER M5 ;
        RECT  13.584 69.036 13.608 69.12 ;
    END
  END xa[49]
  PIN xa[4]
    DIRECTION OUTPUT ;
    USE SIGNAL ;
    PORT
      LAYER M5 ;
        RECT  2.928 69.036 2.952 69.12 ;
    END
  END xa[4]
  PIN xa[50]
    DIRECTION OUTPUT ;
    USE SIGNAL ;
    PORT
      LAYER M5 ;
        RECT  13.824 69.036 13.848 69.12 ;
    END
  END xa[50]
  PIN xa[51]
    DIRECTION OUTPUT ;
    USE SIGNAL ;
    PORT
      LAYER M5 ;
        RECT  14.064 69.036 14.088 69.12 ;
    END
  END xa[51]
  PIN xa[52]
    DIRECTION OUTPUT ;
    USE SIGNAL ;
    PORT
      LAYER M5 ;
        RECT  14.304 69.036 14.328 69.12 ;
    END
  END xa[52]
  PIN xa[53]
    DIRECTION OUTPUT ;
    USE SIGNAL ;
    PORT
      LAYER M5 ;
        RECT  14.544 69.036 14.568 69.12 ;
    END
  END xa[53]
  PIN xa[54]
    DIRECTION OUTPUT ;
    USE SIGNAL ;
    PORT
      LAYER M5 ;
        RECT  14.784 69.036 14.808 69.12 ;
    END
  END xa[54]
  PIN xa[55]
    DIRECTION OUTPUT ;
    USE SIGNAL ;
    PORT
      LAYER M5 ;
        RECT  15.024 69.036 15.048 69.12 ;
    END
  END xa[55]
  PIN xa[56]
    DIRECTION OUTPUT ;
    USE SIGNAL ;
    PORT
      LAYER M5 ;
        RECT  15.264 69.036 15.288 69.12 ;
    END
  END xa[56]
  PIN xa[57]
    DIRECTION OUTPUT ;
    USE SIGNAL ;
    PORT
      LAYER M5 ;
        RECT  15.504 69.036 15.528 69.12 ;
    END
  END xa[57]
  PIN xa[58]
    DIRECTION OUTPUT ;
    USE SIGNAL ;
    PORT
      LAYER M5 ;
        RECT  15.744 69.036 15.768 69.12 ;
    END
  END xa[58]
  PIN xa[59]
    DIRECTION OUTPUT ;
    USE SIGNAL ;
    PORT
      LAYER M5 ;
        RECT  15.984 69.036 16.008 69.12 ;
    END
  END xa[59]
  PIN xa[5]
    DIRECTION OUTPUT ;
    USE SIGNAL ;
    PORT
      LAYER M5 ;
        RECT  3.168 69.036 3.192 69.12 ;
    END
  END xa[5]
  PIN xa[60]
    DIRECTION OUTPUT ;
    USE SIGNAL ;
    PORT
      LAYER M5 ;
        RECT  16.224 69.036 16.248 69.12 ;
    END
  END xa[60]
  PIN xa[61]
    DIRECTION OUTPUT ;
    USE SIGNAL ;
    PORT
      LAYER M5 ;
        RECT  16.464 69.036 16.488 69.12 ;
    END
  END xa[61]
  PIN xa[62]
    DIRECTION OUTPUT ;
    USE SIGNAL ;
    PORT
      LAYER M5 ;
        RECT  16.704 69.036 16.728 69.12 ;
    END
  END xa[62]
  PIN xa[63]
    DIRECTION OUTPUT ;
    USE SIGNAL ;
    PORT
      LAYER M5 ;
        RECT  16.896 69.036 16.92 69.12 ;
    END
  END xa[63]
  PIN xa[64]
    DIRECTION OUTPUT ;
    USE SIGNAL ;
    PORT
      LAYER M5 ;
        RECT  17.136 69.036 17.16 69.12 ;
    END
  END xa[64]
  PIN xa[65]
    DIRECTION OUTPUT ;
    USE SIGNAL ;
    PORT
      LAYER M5 ;
        RECT  17.376 69.036 17.4 69.12 ;
    END
  END xa[65]
  PIN xa[66]
    DIRECTION OUTPUT ;
    USE SIGNAL ;
    PORT
      LAYER M5 ;
        RECT  17.616 69.036 17.64 69.12 ;
    END
  END xa[66]
  PIN xa[67]
    DIRECTION OUTPUT ;
    USE SIGNAL ;
    PORT
      LAYER M5 ;
        RECT  17.856 69.036 17.88 69.12 ;
    END
  END xa[67]
  PIN xa[68]
    DIRECTION OUTPUT ;
    USE SIGNAL ;
    PORT
      LAYER M5 ;
        RECT  18.096 69.036 18.12 69.12 ;
    END
  END xa[68]
  PIN xa[69]
    DIRECTION OUTPUT ;
    USE SIGNAL ;
    PORT
      LAYER M5 ;
        RECT  18.336 69.036 18.36 69.12 ;
    END
  END xa[69]
  PIN xa[6]
    DIRECTION OUTPUT ;
    USE SIGNAL ;
    PORT
      LAYER M5 ;
        RECT  3.408 69.036 3.432 69.12 ;
    END
  END xa[6]
  PIN xa[70]
    DIRECTION OUTPUT ;
    USE SIGNAL ;
    PORT
      LAYER M5 ;
        RECT  18.576 69.036 18.6 69.12 ;
    END
  END xa[70]
  PIN xa[71]
    DIRECTION OUTPUT ;
    USE SIGNAL ;
    PORT
      LAYER M5 ;
        RECT  18.816 69.036 18.84 69.12 ;
    END
  END xa[71]
  PIN xa[72]
    DIRECTION OUTPUT ;
    USE SIGNAL ;
    PORT
      LAYER M5 ;
        RECT  19.056 69.036 19.08 69.12 ;
    END
  END xa[72]
  PIN xa[73]
    DIRECTION OUTPUT ;
    USE SIGNAL ;
    PORT
      LAYER M5 ;
        RECT  19.296 69.036 19.32 69.12 ;
    END
  END xa[73]
  PIN xa[74]
    DIRECTION OUTPUT ;
    USE SIGNAL ;
    PORT
      LAYER M5 ;
        RECT  19.536 69.036 19.56 69.12 ;
    END
  END xa[74]
  PIN xa[75]
    DIRECTION OUTPUT ;
    USE SIGNAL ;
    PORT
      LAYER M5 ;
        RECT  19.776 69.036 19.8 69.12 ;
    END
  END xa[75]
  PIN xa[76]
    DIRECTION OUTPUT ;
    USE SIGNAL ;
    PORT
      LAYER M5 ;
        RECT  20.016 69.036 20.04 69.12 ;
    END
  END xa[76]
  PIN xa[77]
    DIRECTION OUTPUT ;
    USE SIGNAL ;
    PORT
      LAYER M5 ;
        RECT  20.256 69.036 20.28 69.12 ;
    END
  END xa[77]
  PIN xa[78]
    DIRECTION OUTPUT ;
    USE SIGNAL ;
    PORT
      LAYER M5 ;
        RECT  20.496 69.036 20.52 69.12 ;
    END
  END xa[78]
  PIN xa[79]
    DIRECTION OUTPUT ;
    USE SIGNAL ;
    PORT
      LAYER M5 ;
        RECT  20.688 69.036 20.712 69.12 ;
    END
  END xa[79]
  PIN xa[7]
    DIRECTION OUTPUT ;
    USE SIGNAL ;
    PORT
      LAYER M5 ;
        RECT  3.648 69.036 3.672 69.12 ;
    END
  END xa[7]
  PIN xa[80]
    DIRECTION OUTPUT ;
    USE SIGNAL ;
    PORT
      LAYER M5 ;
        RECT  20.928 69.036 20.952 69.12 ;
    END
  END xa[80]
  PIN xa[81]
    DIRECTION OUTPUT ;
    USE SIGNAL ;
    PORT
      LAYER M5 ;
        RECT  21.168 69.036 21.192 69.12 ;
    END
  END xa[81]
  PIN xa[82]
    DIRECTION OUTPUT ;
    USE SIGNAL ;
    PORT
      LAYER M5 ;
        RECT  21.408 69.036 21.432 69.12 ;
    END
  END xa[82]
  PIN xa[83]
    DIRECTION OUTPUT ;
    USE SIGNAL ;
    PORT
      LAYER M5 ;
        RECT  21.648 69.036 21.672 69.12 ;
    END
  END xa[83]
  PIN xa[84]
    DIRECTION OUTPUT ;
    USE SIGNAL ;
    PORT
      LAYER M5 ;
        RECT  21.888 69.036 21.912 69.12 ;
    END
  END xa[84]
  PIN xa[85]
    DIRECTION OUTPUT ;
    USE SIGNAL ;
    PORT
      LAYER M5 ;
        RECT  22.128 69.036 22.152 69.12 ;
    END
  END xa[85]
  PIN xa[86]
    DIRECTION OUTPUT ;
    USE SIGNAL ;
    PORT
      LAYER M5 ;
        RECT  22.368 69.036 22.392 69.12 ;
    END
  END xa[86]
  PIN xa[87]
    DIRECTION OUTPUT ;
    USE SIGNAL ;
    PORT
      LAYER M5 ;
        RECT  22.608 69.036 22.632 69.12 ;
    END
  END xa[87]
  PIN xa[88]
    DIRECTION OUTPUT ;
    USE SIGNAL ;
    PORT
      LAYER M5 ;
        RECT  22.848 69.036 22.872 69.12 ;
    END
  END xa[88]
  PIN xa[89]
    DIRECTION OUTPUT ;
    USE SIGNAL ;
    PORT
      LAYER M5 ;
        RECT  23.088 69.036 23.112 69.12 ;
    END
  END xa[89]
  PIN xa[8]
    DIRECTION OUTPUT ;
    USE SIGNAL ;
    PORT
      LAYER M5 ;
        RECT  3.888 69.036 3.912 69.12 ;
    END
  END xa[8]
  PIN xa[90]
    DIRECTION OUTPUT ;
    USE SIGNAL ;
    PORT
      LAYER M5 ;
        RECT  23.328 69.036 23.352 69.12 ;
    END
  END xa[90]
  PIN xa[91]
    DIRECTION OUTPUT ;
    USE SIGNAL ;
    PORT
      LAYER M5 ;
        RECT  23.568 69.036 23.592 69.12 ;
    END
  END xa[91]
  PIN xa[92]
    DIRECTION OUTPUT ;
    USE SIGNAL ;
    PORT
      LAYER M5 ;
        RECT  23.808 69.036 23.832 69.12 ;
    END
  END xa[92]
  PIN xa[93]
    DIRECTION OUTPUT ;
    USE SIGNAL ;
    PORT
      LAYER M5 ;
        RECT  24.048 69.036 24.072 69.12 ;
    END
  END xa[93]
  PIN xa[94]
    DIRECTION OUTPUT ;
    USE SIGNAL ;
    PORT
      LAYER M5 ;
        RECT  24.288 69.036 24.312 69.12 ;
    END
  END xa[94]
  PIN xa[95]
    DIRECTION OUTPUT ;
    USE SIGNAL ;
    PORT
      LAYER M5 ;
        RECT  24.48 69.036 24.504 69.12 ;
    END
  END xa[95]
  PIN xa[96]
    DIRECTION OUTPUT ;
    USE SIGNAL ;
    PORT
      LAYER M5 ;
        RECT  24.72 69.036 24.744 69.12 ;
    END
  END xa[96]
  PIN xa[97]
    DIRECTION OUTPUT ;
    USE SIGNAL ;
    PORT
      LAYER M5 ;
        RECT  24.96 69.036 24.984 69.12 ;
    END
  END xa[97]
  PIN xa[98]
    DIRECTION OUTPUT ;
    USE SIGNAL ;
    PORT
      LAYER M5 ;
        RECT  25.2 69.036 25.224 69.12 ;
    END
  END xa[98]
  PIN xa[99]
    DIRECTION OUTPUT ;
    USE SIGNAL ;
    PORT
      LAYER M5 ;
        RECT  25.44 69.036 25.464 69.12 ;
    END
  END xa[99]
  PIN xa[9]
    DIRECTION OUTPUT ;
    USE SIGNAL ;
    PORT
      LAYER M5 ;
        RECT  4.128 69.036 4.152 69.12 ;
    END
  END xa[9]
  PIN xb[0]
    DIRECTION OUTPUT ;
    USE SIGNAL ;
    PORT
      LAYER M5 ;
        RECT  69.072 69.036 69.096 69.12 ;
    END
  END xb[0]
  PIN xb[100]
    DIRECTION OUTPUT ;
    USE SIGNAL ;
    PORT
      LAYER M5 ;
        RECT  92.736 69.036 92.76 69.12 ;
    END
  END xb[100]
  PIN xb[101]
    DIRECTION OUTPUT ;
    USE SIGNAL ;
    PORT
      LAYER M5 ;
        RECT  92.976 69.036 93 69.12 ;
    END
  END xb[101]
  PIN xb[102]
    DIRECTION OUTPUT ;
    USE SIGNAL ;
    PORT
      LAYER M5 ;
        RECT  93.216 69.036 93.24 69.12 ;
    END
  END xb[102]
  PIN xb[103]
    DIRECTION OUTPUT ;
    USE SIGNAL ;
    PORT
      LAYER M5 ;
        RECT  93.456 69.036 93.48 69.12 ;
    END
  END xb[103]
  PIN xb[104]
    DIRECTION OUTPUT ;
    USE SIGNAL ;
    PORT
      LAYER M5 ;
        RECT  93.696 69.036 93.72 69.12 ;
    END
  END xb[104]
  PIN xb[105]
    DIRECTION OUTPUT ;
    USE SIGNAL ;
    PORT
      LAYER M5 ;
        RECT  93.936 69.036 93.96 69.12 ;
    END
  END xb[105]
  PIN xb[106]
    DIRECTION OUTPUT ;
    USE SIGNAL ;
    PORT
      LAYER M5 ;
        RECT  94.176 69.036 94.2 69.12 ;
    END
  END xb[106]
  PIN xb[107]
    DIRECTION OUTPUT ;
    USE SIGNAL ;
    PORT
      LAYER M5 ;
        RECT  94.416 69.036 94.44 69.12 ;
    END
  END xb[107]
  PIN xb[108]
    DIRECTION OUTPUT ;
    USE SIGNAL ;
    PORT
      LAYER M5 ;
        RECT  94.656 69.036 94.68 69.12 ;
    END
  END xb[108]
  PIN xb[109]
    DIRECTION OUTPUT ;
    USE SIGNAL ;
    PORT
      LAYER M5 ;
        RECT  94.896 69.036 94.92 69.12 ;
    END
  END xb[109]
  PIN xb[10]
    DIRECTION OUTPUT ;
    USE SIGNAL ;
    PORT
      LAYER M5 ;
        RECT  71.424 69.036 71.448 69.12 ;
    END
  END xb[10]
  PIN xb[110]
    DIRECTION OUTPUT ;
    USE SIGNAL ;
    PORT
      LAYER M5 ;
        RECT  95.136 69.036 95.16 69.12 ;
    END
  END xb[110]
  PIN xb[111]
    DIRECTION OUTPUT ;
    USE SIGNAL ;
    PORT
      LAYER M5 ;
        RECT  95.376 69.036 95.4 69.12 ;
    END
  END xb[111]
  PIN xb[112]
    DIRECTION OUTPUT ;
    USE SIGNAL ;
    PORT
      LAYER M5 ;
        RECT  95.616 69.036 95.64 69.12 ;
    END
  END xb[112]
  PIN xb[113]
    DIRECTION OUTPUT ;
    USE SIGNAL ;
    PORT
      LAYER M5 ;
        RECT  95.856 69.036 95.88 69.12 ;
    END
  END xb[113]
  PIN xb[114]
    DIRECTION OUTPUT ;
    USE SIGNAL ;
    PORT
      LAYER M5 ;
        RECT  96.048 69.036 96.072 69.12 ;
    END
  END xb[114]
  PIN xb[115]
    DIRECTION OUTPUT ;
    USE SIGNAL ;
    PORT
      LAYER M5 ;
        RECT  96.288 69.036 96.312 69.12 ;
    END
  END xb[115]
  PIN xb[116]
    DIRECTION OUTPUT ;
    USE SIGNAL ;
    PORT
      LAYER M5 ;
        RECT  96.528 69.036 96.552 69.12 ;
    END
  END xb[116]
  PIN xb[117]
    DIRECTION OUTPUT ;
    USE SIGNAL ;
    PORT
      LAYER M5 ;
        RECT  96.768 69.036 96.792 69.12 ;
    END
  END xb[117]
  PIN xb[118]
    DIRECTION OUTPUT ;
    USE SIGNAL ;
    PORT
      LAYER M5 ;
        RECT  97.008 69.036 97.032 69.12 ;
    END
  END xb[118]
  PIN xb[119]
    DIRECTION OUTPUT ;
    USE SIGNAL ;
    PORT
      LAYER M5 ;
        RECT  97.248 69.036 97.272 69.12 ;
    END
  END xb[119]
  PIN xb[11]
    DIRECTION OUTPUT ;
    USE SIGNAL ;
    PORT
      LAYER M5 ;
        RECT  71.664 69.036 71.688 69.12 ;
    END
  END xb[11]
  PIN xb[120]
    DIRECTION OUTPUT ;
    USE SIGNAL ;
    PORT
      LAYER M5 ;
        RECT  97.488 69.036 97.512 69.12 ;
    END
  END xb[120]
  PIN xb[121]
    DIRECTION OUTPUT ;
    USE SIGNAL ;
    PORT
      LAYER M5 ;
        RECT  97.728 69.036 97.752 69.12 ;
    END
  END xb[121]
  PIN xb[122]
    DIRECTION OUTPUT ;
    USE SIGNAL ;
    PORT
      LAYER M5 ;
        RECT  97.968 69.036 97.992 69.12 ;
    END
  END xb[122]
  PIN xb[123]
    DIRECTION OUTPUT ;
    USE SIGNAL ;
    PORT
      LAYER M5 ;
        RECT  98.208 69.036 98.232 69.12 ;
    END
  END xb[123]
  PIN xb[124]
    DIRECTION OUTPUT ;
    USE SIGNAL ;
    PORT
      LAYER M5 ;
        RECT  98.448 69.036 98.472 69.12 ;
    END
  END xb[124]
  PIN xb[125]
    DIRECTION OUTPUT ;
    USE SIGNAL ;
    PORT
      LAYER M5 ;
        RECT  98.688 69.036 98.712 69.12 ;
    END
  END xb[125]
  PIN xb[126]
    DIRECTION OUTPUT ;
    USE SIGNAL ;
    PORT
      LAYER M5 ;
        RECT  98.928 69.036 98.952 69.12 ;
    END
  END xb[126]
  PIN xb[127]
    DIRECTION OUTPUT ;
    USE SIGNAL ;
    PORT
      LAYER M5 ;
        RECT  99.168 69.036 99.192 69.12 ;
    END
  END xb[127]
  PIN xb[128]
    DIRECTION OUTPUT ;
    USE SIGNAL ;
    PORT
      LAYER M5 ;
        RECT  99.408 69.036 99.432 69.12 ;
    END
  END xb[128]
  PIN xb[129]
    DIRECTION OUTPUT ;
    USE SIGNAL ;
    PORT
      LAYER M5 ;
        RECT  99.648 69.036 99.672 69.12 ;
    END
  END xb[129]
  PIN xb[12]
    DIRECTION OUTPUT ;
    USE SIGNAL ;
    PORT
      LAYER M5 ;
        RECT  71.904 69.036 71.928 69.12 ;
    END
  END xb[12]
  PIN xb[130]
    DIRECTION OUTPUT ;
    USE SIGNAL ;
    PORT
      LAYER M5 ;
        RECT  99.84 69.036 99.864 69.12 ;
    END
  END xb[130]
  PIN xb[131]
    DIRECTION OUTPUT ;
    USE SIGNAL ;
    PORT
      LAYER M5 ;
        RECT  100.08 69.036 100.104 69.12 ;
    END
  END xb[131]
  PIN xb[132]
    DIRECTION OUTPUT ;
    USE SIGNAL ;
    PORT
      LAYER M5 ;
        RECT  100.32 69.036 100.344 69.12 ;
    END
  END xb[132]
  PIN xb[133]
    DIRECTION OUTPUT ;
    USE SIGNAL ;
    PORT
      LAYER M5 ;
        RECT  100.56 69.036 100.584 69.12 ;
    END
  END xb[133]
  PIN xb[134]
    DIRECTION OUTPUT ;
    USE SIGNAL ;
    PORT
      LAYER M5 ;
        RECT  100.8 69.036 100.824 69.12 ;
    END
  END xb[134]
  PIN xb[135]
    DIRECTION OUTPUT ;
    USE SIGNAL ;
    PORT
      LAYER M5 ;
        RECT  101.04 69.036 101.064 69.12 ;
    END
  END xb[135]
  PIN xb[136]
    DIRECTION OUTPUT ;
    USE SIGNAL ;
    PORT
      LAYER M5 ;
        RECT  101.28 69.036 101.304 69.12 ;
    END
  END xb[136]
  PIN xb[137]
    DIRECTION OUTPUT ;
    USE SIGNAL ;
    PORT
      LAYER M5 ;
        RECT  101.52 69.036 101.544 69.12 ;
    END
  END xb[137]
  PIN xb[138]
    DIRECTION OUTPUT ;
    USE SIGNAL ;
    PORT
      LAYER M5 ;
        RECT  101.76 69.036 101.784 69.12 ;
    END
  END xb[138]
  PIN xb[139]
    DIRECTION OUTPUT ;
    USE SIGNAL ;
    PORT
      LAYER M5 ;
        RECT  102 69.036 102.024 69.12 ;
    END
  END xb[139]
  PIN xb[13]
    DIRECTION OUTPUT ;
    USE SIGNAL ;
    PORT
      LAYER M5 ;
        RECT  72.144 69.036 72.168 69.12 ;
    END
  END xb[13]
  PIN xb[140]
    DIRECTION OUTPUT ;
    USE SIGNAL ;
    PORT
      LAYER M5 ;
        RECT  102.24 69.036 102.264 69.12 ;
    END
  END xb[140]
  PIN xb[141]
    DIRECTION OUTPUT ;
    USE SIGNAL ;
    PORT
      LAYER M5 ;
        RECT  102.48 69.036 102.504 69.12 ;
    END
  END xb[141]
  PIN xb[142]
    DIRECTION OUTPUT ;
    USE SIGNAL ;
    PORT
      LAYER M5 ;
        RECT  102.72 69.036 102.744 69.12 ;
    END
  END xb[142]
  PIN xb[143]
    DIRECTION OUTPUT ;
    USE SIGNAL ;
    PORT
      LAYER M5 ;
        RECT  102.96 69.036 102.984 69.12 ;
    END
  END xb[143]
  PIN xb[144]
    DIRECTION OUTPUT ;
    USE SIGNAL ;
    PORT
      LAYER M5 ;
        RECT  103.2 69.036 103.224 69.12 ;
    END
  END xb[144]
  PIN xb[145]
    DIRECTION OUTPUT ;
    USE SIGNAL ;
    PORT
      LAYER M5 ;
        RECT  103.44 69.036 103.464 69.12 ;
    END
  END xb[145]
  PIN xb[146]
    DIRECTION OUTPUT ;
    USE SIGNAL ;
    PORT
      LAYER M5 ;
        RECT  103.632 69.036 103.656 69.12 ;
    END
  END xb[146]
  PIN xb[147]
    DIRECTION OUTPUT ;
    USE SIGNAL ;
    PORT
      LAYER M5 ;
        RECT  103.872 69.036 103.896 69.12 ;
    END
  END xb[147]
  PIN xb[148]
    DIRECTION OUTPUT ;
    USE SIGNAL ;
    PORT
      LAYER M5 ;
        RECT  104.112 69.036 104.136 69.12 ;
    END
  END xb[148]
  PIN xb[149]
    DIRECTION OUTPUT ;
    USE SIGNAL ;
    PORT
      LAYER M5 ;
        RECT  104.352 69.036 104.376 69.12 ;
    END
  END xb[149]
  PIN xb[14]
    DIRECTION OUTPUT ;
    USE SIGNAL ;
    PORT
      LAYER M5 ;
        RECT  72.384 69.036 72.408 69.12 ;
    END
  END xb[14]
  PIN xb[150]
    DIRECTION OUTPUT ;
    USE SIGNAL ;
    PORT
      LAYER M5 ;
        RECT  104.592 69.036 104.616 69.12 ;
    END
  END xb[150]
  PIN xb[151]
    DIRECTION OUTPUT ;
    USE SIGNAL ;
    PORT
      LAYER M5 ;
        RECT  104.832 69.036 104.856 69.12 ;
    END
  END xb[151]
  PIN xb[152]
    DIRECTION OUTPUT ;
    USE SIGNAL ;
    PORT
      LAYER M5 ;
        RECT  105.072 69.036 105.096 69.12 ;
    END
  END xb[152]
  PIN xb[153]
    DIRECTION OUTPUT ;
    USE SIGNAL ;
    PORT
      LAYER M5 ;
        RECT  105.312 69.036 105.336 69.12 ;
    END
  END xb[153]
  PIN xb[154]
    DIRECTION OUTPUT ;
    USE SIGNAL ;
    PORT
      LAYER M5 ;
        RECT  105.552 69.036 105.576 69.12 ;
    END
  END xb[154]
  PIN xb[155]
    DIRECTION OUTPUT ;
    USE SIGNAL ;
    PORT
      LAYER M5 ;
        RECT  105.792 69.036 105.816 69.12 ;
    END
  END xb[155]
  PIN xb[156]
    DIRECTION OUTPUT ;
    USE SIGNAL ;
    PORT
      LAYER M5 ;
        RECT  106.032 69.036 106.056 69.12 ;
    END
  END xb[156]
  PIN xb[157]
    DIRECTION OUTPUT ;
    USE SIGNAL ;
    PORT
      LAYER M5 ;
        RECT  106.272 69.036 106.296 69.12 ;
    END
  END xb[157]
  PIN xb[158]
    DIRECTION OUTPUT ;
    USE SIGNAL ;
    PORT
      LAYER M5 ;
        RECT  106.512 69.036 106.536 69.12 ;
    END
  END xb[158]
  PIN xb[159]
    DIRECTION OUTPUT ;
    USE SIGNAL ;
    PORT
      LAYER M5 ;
        RECT  106.752 69.036 106.776 69.12 ;
    END
  END xb[159]
  PIN xb[15]
    DIRECTION OUTPUT ;
    USE SIGNAL ;
    PORT
      LAYER M5 ;
        RECT  72.624 69.036 72.648 69.12 ;
    END
  END xb[15]
  PIN xb[160]
    DIRECTION OUTPUT ;
    USE SIGNAL ;
    PORT
      LAYER M5 ;
        RECT  106.992 69.036 107.016 69.12 ;
    END
  END xb[160]
  PIN xb[161]
    DIRECTION OUTPUT ;
    USE SIGNAL ;
    PORT
      LAYER M5 ;
        RECT  107.232 69.036 107.256 69.12 ;
    END
  END xb[161]
  PIN xb[162]
    DIRECTION OUTPUT ;
    USE SIGNAL ;
    PORT
      LAYER M5 ;
        RECT  107.424 69.036 107.448 69.12 ;
    END
  END xb[162]
  PIN xb[163]
    DIRECTION OUTPUT ;
    USE SIGNAL ;
    PORT
      LAYER M5 ;
        RECT  107.664 69.036 107.688 69.12 ;
    END
  END xb[163]
  PIN xb[164]
    DIRECTION OUTPUT ;
    USE SIGNAL ;
    PORT
      LAYER M5 ;
        RECT  107.904 69.036 107.928 69.12 ;
    END
  END xb[164]
  PIN xb[165]
    DIRECTION OUTPUT ;
    USE SIGNAL ;
    PORT
      LAYER M5 ;
        RECT  108.144 69.036 108.168 69.12 ;
    END
  END xb[165]
  PIN xb[166]
    DIRECTION OUTPUT ;
    USE SIGNAL ;
    PORT
      LAYER M5 ;
        RECT  108.384 69.036 108.408 69.12 ;
    END
  END xb[166]
  PIN xb[167]
    DIRECTION OUTPUT ;
    USE SIGNAL ;
    PORT
      LAYER M5 ;
        RECT  108.624 69.036 108.648 69.12 ;
    END
  END xb[167]
  PIN xb[168]
    DIRECTION OUTPUT ;
    USE SIGNAL ;
    PORT
      LAYER M5 ;
        RECT  108.864 69.036 108.888 69.12 ;
    END
  END xb[168]
  PIN xb[169]
    DIRECTION OUTPUT ;
    USE SIGNAL ;
    PORT
      LAYER M5 ;
        RECT  109.104 69.036 109.128 69.12 ;
    END
  END xb[169]
  PIN xb[16]
    DIRECTION OUTPUT ;
    USE SIGNAL ;
    PORT
      LAYER M5 ;
        RECT  72.864 69.036 72.888 69.12 ;
    END
  END xb[16]
  PIN xb[170]
    DIRECTION OUTPUT ;
    USE SIGNAL ;
    PORT
      LAYER M5 ;
        RECT  109.344 69.036 109.368 69.12 ;
    END
  END xb[170]
  PIN xb[171]
    DIRECTION OUTPUT ;
    USE SIGNAL ;
    PORT
      LAYER M5 ;
        RECT  109.584 69.036 109.608 69.12 ;
    END
  END xb[171]
  PIN xb[172]
    DIRECTION OUTPUT ;
    USE SIGNAL ;
    PORT
      LAYER M5 ;
        RECT  109.824 69.036 109.848 69.12 ;
    END
  END xb[172]
  PIN xb[173]
    DIRECTION OUTPUT ;
    USE SIGNAL ;
    PORT
      LAYER M5 ;
        RECT  110.064 69.036 110.088 69.12 ;
    END
  END xb[173]
  PIN xb[174]
    DIRECTION OUTPUT ;
    USE SIGNAL ;
    PORT
      LAYER M5 ;
        RECT  110.304 69.036 110.328 69.12 ;
    END
  END xb[174]
  PIN xb[175]
    DIRECTION OUTPUT ;
    USE SIGNAL ;
    PORT
      LAYER M5 ;
        RECT  110.544 69.036 110.568 69.12 ;
    END
  END xb[175]
  PIN xb[176]
    DIRECTION OUTPUT ;
    USE SIGNAL ;
    PORT
      LAYER M5 ;
        RECT  110.784 69.036 110.808 69.12 ;
    END
  END xb[176]
  PIN xb[177]
    DIRECTION OUTPUT ;
    USE SIGNAL ;
    PORT
      LAYER M5 ;
        RECT  111.024 69.036 111.048 69.12 ;
    END
  END xb[177]
  PIN xb[178]
    DIRECTION OUTPUT ;
    USE SIGNAL ;
    PORT
      LAYER M5 ;
        RECT  111.216 69.036 111.24 69.12 ;
    END
  END xb[178]
  PIN xb[179]
    DIRECTION OUTPUT ;
    USE SIGNAL ;
    PORT
      LAYER M5 ;
        RECT  111.456 69.036 111.48 69.12 ;
    END
  END xb[179]
  PIN xb[17]
    DIRECTION OUTPUT ;
    USE SIGNAL ;
    PORT
      LAYER M5 ;
        RECT  73.104 69.036 73.128 69.12 ;
    END
  END xb[17]
  PIN xb[180]
    DIRECTION OUTPUT ;
    USE SIGNAL ;
    PORT
      LAYER M5 ;
        RECT  111.696 69.036 111.72 69.12 ;
    END
  END xb[180]
  PIN xb[181]
    DIRECTION OUTPUT ;
    USE SIGNAL ;
    PORT
      LAYER M5 ;
        RECT  111.936 69.036 111.96 69.12 ;
    END
  END xb[181]
  PIN xb[182]
    DIRECTION OUTPUT ;
    USE SIGNAL ;
    PORT
      LAYER M5 ;
        RECT  112.176 69.036 112.2 69.12 ;
    END
  END xb[182]
  PIN xb[183]
    DIRECTION OUTPUT ;
    USE SIGNAL ;
    PORT
      LAYER M5 ;
        RECT  112.416 69.036 112.44 69.12 ;
    END
  END xb[183]
  PIN xb[184]
    DIRECTION OUTPUT ;
    USE SIGNAL ;
    PORT
      LAYER M5 ;
        RECT  112.656 69.036 112.68 69.12 ;
    END
  END xb[184]
  PIN xb[185]
    DIRECTION OUTPUT ;
    USE SIGNAL ;
    PORT
      LAYER M5 ;
        RECT  112.896 69.036 112.92 69.12 ;
    END
  END xb[185]
  PIN xb[186]
    DIRECTION OUTPUT ;
    USE SIGNAL ;
    PORT
      LAYER M5 ;
        RECT  113.136 69.036 113.16 69.12 ;
    END
  END xb[186]
  PIN xb[187]
    DIRECTION OUTPUT ;
    USE SIGNAL ;
    PORT
      LAYER M5 ;
        RECT  113.376 69.036 113.4 69.12 ;
    END
  END xb[187]
  PIN xb[188]
    DIRECTION OUTPUT ;
    USE SIGNAL ;
    PORT
      LAYER M5 ;
        RECT  113.616 69.036 113.64 69.12 ;
    END
  END xb[188]
  PIN xb[189]
    DIRECTION OUTPUT ;
    USE SIGNAL ;
    PORT
      LAYER M5 ;
        RECT  113.856 69.036 113.88 69.12 ;
    END
  END xb[189]
  PIN xb[18]
    DIRECTION OUTPUT ;
    USE SIGNAL ;
    PORT
      LAYER M5 ;
        RECT  73.344 69.036 73.368 69.12 ;
    END
  END xb[18]
  PIN xb[190]
    DIRECTION OUTPUT ;
    USE SIGNAL ;
    PORT
      LAYER M5 ;
        RECT  114.096 69.036 114.12 69.12 ;
    END
  END xb[190]
  PIN xb[191]
    DIRECTION OUTPUT ;
    USE SIGNAL ;
    PORT
      LAYER M5 ;
        RECT  114.336 69.036 114.36 69.12 ;
    END
  END xb[191]
  PIN xb[192]
    DIRECTION OUTPUT ;
    USE SIGNAL ;
    PORT
      LAYER M5 ;
        RECT  114.576 69.036 114.6 69.12 ;
    END
  END xb[192]
  PIN xb[193]
    DIRECTION OUTPUT ;
    USE SIGNAL ;
    PORT
      LAYER M5 ;
        RECT  114.816 69.036 114.84 69.12 ;
    END
  END xb[193]
  PIN xb[194]
    DIRECTION OUTPUT ;
    USE SIGNAL ;
    PORT
      LAYER M5 ;
        RECT  115.008 69.036 115.032 69.12 ;
    END
  END xb[194]
  PIN xb[195]
    DIRECTION OUTPUT ;
    USE SIGNAL ;
    PORT
      LAYER M5 ;
        RECT  115.248 69.036 115.272 69.12 ;
    END
  END xb[195]
  PIN xb[196]
    DIRECTION OUTPUT ;
    USE SIGNAL ;
    PORT
      LAYER M5 ;
        RECT  115.488 69.036 115.512 69.12 ;
    END
  END xb[196]
  PIN xb[197]
    DIRECTION OUTPUT ;
    USE SIGNAL ;
    PORT
      LAYER M5 ;
        RECT  115.728 69.036 115.752 69.12 ;
    END
  END xb[197]
  PIN xb[198]
    DIRECTION OUTPUT ;
    USE SIGNAL ;
    PORT
      LAYER M5 ;
        RECT  115.968 69.036 115.992 69.12 ;
    END
  END xb[198]
  PIN xb[199]
    DIRECTION OUTPUT ;
    USE SIGNAL ;
    PORT
      LAYER M5 ;
        RECT  116.208 69.036 116.232 69.12 ;
    END
  END xb[199]
  PIN xb[19]
    DIRECTION OUTPUT ;
    USE SIGNAL ;
    PORT
      LAYER M5 ;
        RECT  73.536 69.036 73.56 69.12 ;
    END
  END xb[19]
  PIN xb[1]
    DIRECTION OUTPUT ;
    USE SIGNAL ;
    PORT
      LAYER M5 ;
        RECT  69.312 69.036 69.336 69.12 ;
    END
  END xb[1]
  PIN xb[200]
    DIRECTION OUTPUT ;
    USE SIGNAL ;
    PORT
      LAYER M5 ;
        RECT  116.448 69.036 116.472 69.12 ;
    END
  END xb[200]
  PIN xb[201]
    DIRECTION OUTPUT ;
    USE SIGNAL ;
    PORT
      LAYER M5 ;
        RECT  116.688 69.036 116.712 69.12 ;
    END
  END xb[201]
  PIN xb[202]
    DIRECTION OUTPUT ;
    USE SIGNAL ;
    PORT
      LAYER M5 ;
        RECT  116.928 69.036 116.952 69.12 ;
    END
  END xb[202]
  PIN xb[203]
    DIRECTION OUTPUT ;
    USE SIGNAL ;
    PORT
      LAYER M5 ;
        RECT  117.168 69.036 117.192 69.12 ;
    END
  END xb[203]
  PIN xb[204]
    DIRECTION OUTPUT ;
    USE SIGNAL ;
    PORT
      LAYER M5 ;
        RECT  117.408 69.036 117.432 69.12 ;
    END
  END xb[204]
  PIN xb[205]
    DIRECTION OUTPUT ;
    USE SIGNAL ;
    PORT
      LAYER M5 ;
        RECT  117.648 69.036 117.672 69.12 ;
    END
  END xb[205]
  PIN xb[206]
    DIRECTION OUTPUT ;
    USE SIGNAL ;
    PORT
      LAYER M5 ;
        RECT  117.888 69.036 117.912 69.12 ;
    END
  END xb[206]
  PIN xb[207]
    DIRECTION OUTPUT ;
    USE SIGNAL ;
    PORT
      LAYER M5 ;
        RECT  118.128 69.036 118.152 69.12 ;
    END
  END xb[207]
  PIN xb[208]
    DIRECTION OUTPUT ;
    USE SIGNAL ;
    PORT
      LAYER M5 ;
        RECT  118.368 69.036 118.392 69.12 ;
    END
  END xb[208]
  PIN xb[209]
    DIRECTION OUTPUT ;
    USE SIGNAL ;
    PORT
      LAYER M5 ;
        RECT  118.608 69.036 118.632 69.12 ;
    END
  END xb[209]
  PIN xb[20]
    DIRECTION OUTPUT ;
    USE SIGNAL ;
    PORT
      LAYER M5 ;
        RECT  73.776 69.036 73.8 69.12 ;
    END
  END xb[20]
  PIN xb[210]
    DIRECTION OUTPUT ;
    USE SIGNAL ;
    PORT
      LAYER M5 ;
        RECT  118.8 69.036 118.824 69.12 ;
    END
  END xb[210]
  PIN xb[211]
    DIRECTION OUTPUT ;
    USE SIGNAL ;
    PORT
      LAYER M5 ;
        RECT  119.04 69.036 119.064 69.12 ;
    END
  END xb[211]
  PIN xb[212]
    DIRECTION OUTPUT ;
    USE SIGNAL ;
    PORT
      LAYER M5 ;
        RECT  119.28 69.036 119.304 69.12 ;
    END
  END xb[212]
  PIN xb[213]
    DIRECTION OUTPUT ;
    USE SIGNAL ;
    PORT
      LAYER M5 ;
        RECT  119.52 69.036 119.544 69.12 ;
    END
  END xb[213]
  PIN xb[214]
    DIRECTION OUTPUT ;
    USE SIGNAL ;
    PORT
      LAYER M5 ;
        RECT  119.76 69.036 119.784 69.12 ;
    END
  END xb[214]
  PIN xb[215]
    DIRECTION OUTPUT ;
    USE SIGNAL ;
    PORT
      LAYER M5 ;
        RECT  120 69.036 120.024 69.12 ;
    END
  END xb[215]
  PIN xb[216]
    DIRECTION OUTPUT ;
    USE SIGNAL ;
    PORT
      LAYER M5 ;
        RECT  120.24 69.036 120.264 69.12 ;
    END
  END xb[216]
  PIN xb[217]
    DIRECTION OUTPUT ;
    USE SIGNAL ;
    PORT
      LAYER M5 ;
        RECT  120.48 69.036 120.504 69.12 ;
    END
  END xb[217]
  PIN xb[218]
    DIRECTION OUTPUT ;
    USE SIGNAL ;
    PORT
      LAYER M5 ;
        RECT  120.72 69.036 120.744 69.12 ;
    END
  END xb[218]
  PIN xb[219]
    DIRECTION OUTPUT ;
    USE SIGNAL ;
    PORT
      LAYER M5 ;
        RECT  120.96 69.036 120.984 69.12 ;
    END
  END xb[219]
  PIN xb[21]
    DIRECTION OUTPUT ;
    USE SIGNAL ;
    PORT
      LAYER M5 ;
        RECT  74.016 69.036 74.04 69.12 ;
    END
  END xb[21]
  PIN xb[220]
    DIRECTION OUTPUT ;
    USE SIGNAL ;
    PORT
      LAYER M5 ;
        RECT  121.2 69.036 121.224 69.12 ;
    END
  END xb[220]
  PIN xb[221]
    DIRECTION OUTPUT ;
    USE SIGNAL ;
    PORT
      LAYER M5 ;
        RECT  121.44 69.036 121.464 69.12 ;
    END
  END xb[221]
  PIN xb[222]
    DIRECTION OUTPUT ;
    USE SIGNAL ;
    PORT
      LAYER M5 ;
        RECT  121.68 69.036 121.704 69.12 ;
    END
  END xb[222]
  PIN xb[223]
    DIRECTION OUTPUT ;
    USE SIGNAL ;
    PORT
      LAYER M5 ;
        RECT  121.92 69.036 121.944 69.12 ;
    END
  END xb[223]
  PIN xb[224]
    DIRECTION OUTPUT ;
    USE SIGNAL ;
    PORT
      LAYER M5 ;
        RECT  122.16 69.036 122.184 69.12 ;
    END
  END xb[224]
  PIN xb[225]
    DIRECTION OUTPUT ;
    USE SIGNAL ;
    PORT
      LAYER M5 ;
        RECT  122.4 69.036 122.424 69.12 ;
    END
  END xb[225]
  PIN xb[226]
    DIRECTION OUTPUT ;
    USE SIGNAL ;
    PORT
      LAYER M5 ;
        RECT  122.592 69.036 122.616 69.12 ;
    END
  END xb[226]
  PIN xb[227]
    DIRECTION OUTPUT ;
    USE SIGNAL ;
    PORT
      LAYER M5 ;
        RECT  122.832 69.036 122.856 69.12 ;
    END
  END xb[227]
  PIN xb[228]
    DIRECTION OUTPUT ;
    USE SIGNAL ;
    PORT
      LAYER M5 ;
        RECT  123.072 69.036 123.096 69.12 ;
    END
  END xb[228]
  PIN xb[229]
    DIRECTION OUTPUT ;
    USE SIGNAL ;
    PORT
      LAYER M5 ;
        RECT  123.312 69.036 123.336 69.12 ;
    END
  END xb[229]
  PIN xb[22]
    DIRECTION OUTPUT ;
    USE SIGNAL ;
    PORT
      LAYER M5 ;
        RECT  74.256 69.036 74.28 69.12 ;
    END
  END xb[22]
  PIN xb[230]
    DIRECTION OUTPUT ;
    USE SIGNAL ;
    PORT
      LAYER M5 ;
        RECT  123.552 69.036 123.576 69.12 ;
    END
  END xb[230]
  PIN xb[231]
    DIRECTION OUTPUT ;
    USE SIGNAL ;
    PORT
      LAYER M5 ;
        RECT  123.792 69.036 123.816 69.12 ;
    END
  END xb[231]
  PIN xb[232]
    DIRECTION OUTPUT ;
    USE SIGNAL ;
    PORT
      LAYER M5 ;
        RECT  124.032 69.036 124.056 69.12 ;
    END
  END xb[232]
  PIN xb[233]
    DIRECTION OUTPUT ;
    USE SIGNAL ;
    PORT
      LAYER M5 ;
        RECT  124.272 69.036 124.296 69.12 ;
    END
  END xb[233]
  PIN xb[234]
    DIRECTION OUTPUT ;
    USE SIGNAL ;
    PORT
      LAYER M5 ;
        RECT  124.512 69.036 124.536 69.12 ;
    END
  END xb[234]
  PIN xb[235]
    DIRECTION OUTPUT ;
    USE SIGNAL ;
    PORT
      LAYER M5 ;
        RECT  124.752 69.036 124.776 69.12 ;
    END
  END xb[235]
  PIN xb[236]
    DIRECTION OUTPUT ;
    USE SIGNAL ;
    PORT
      LAYER M5 ;
        RECT  124.992 69.036 125.016 69.12 ;
    END
  END xb[236]
  PIN xb[237]
    DIRECTION OUTPUT ;
    USE SIGNAL ;
    PORT
      LAYER M5 ;
        RECT  125.232 69.036 125.256 69.12 ;
    END
  END xb[237]
  PIN xb[238]
    DIRECTION OUTPUT ;
    USE SIGNAL ;
    PORT
      LAYER M5 ;
        RECT  125.472 69.036 125.496 69.12 ;
    END
  END xb[238]
  PIN xb[239]
    DIRECTION OUTPUT ;
    USE SIGNAL ;
    PORT
      LAYER M5 ;
        RECT  125.712 69.036 125.736 69.12 ;
    END
  END xb[239]
  PIN xb[23]
    DIRECTION OUTPUT ;
    USE SIGNAL ;
    PORT
      LAYER M5 ;
        RECT  74.496 69.036 74.52 69.12 ;
    END
  END xb[23]
  PIN xb[240]
    DIRECTION OUTPUT ;
    USE SIGNAL ;
    PORT
      LAYER M5 ;
        RECT  125.952 69.036 125.976 69.12 ;
    END
  END xb[240]
  PIN xb[241]
    DIRECTION OUTPUT ;
    USE SIGNAL ;
    PORT
      LAYER M5 ;
        RECT  126.192 69.036 126.216 69.12 ;
    END
  END xb[241]
  PIN xb[242]
    DIRECTION OUTPUT ;
    USE SIGNAL ;
    PORT
      LAYER M5 ;
        RECT  126.384 69.036 126.408 69.12 ;
    END
  END xb[242]
  PIN xb[243]
    DIRECTION OUTPUT ;
    USE SIGNAL ;
    PORT
      LAYER M5 ;
        RECT  126.624 69.036 126.648 69.12 ;
    END
  END xb[243]
  PIN xb[244]
    DIRECTION OUTPUT ;
    USE SIGNAL ;
    PORT
      LAYER M5 ;
        RECT  126.864 69.036 126.888 69.12 ;
    END
  END xb[244]
  PIN xb[245]
    DIRECTION OUTPUT ;
    USE SIGNAL ;
    PORT
      LAYER M5 ;
        RECT  127.104 69.036 127.128 69.12 ;
    END
  END xb[245]
  PIN xb[246]
    DIRECTION OUTPUT ;
    USE SIGNAL ;
    PORT
      LAYER M5 ;
        RECT  127.344 69.036 127.368 69.12 ;
    END
  END xb[246]
  PIN xb[247]
    DIRECTION OUTPUT ;
    USE SIGNAL ;
    PORT
      LAYER M5 ;
        RECT  127.584 69.036 127.608 69.12 ;
    END
  END xb[247]
  PIN xb[248]
    DIRECTION OUTPUT ;
    USE SIGNAL ;
    PORT
      LAYER M5 ;
        RECT  127.824 69.036 127.848 69.12 ;
    END
  END xb[248]
  PIN xb[249]
    DIRECTION OUTPUT ;
    USE SIGNAL ;
    PORT
      LAYER M5 ;
        RECT  128.064 69.036 128.088 69.12 ;
    END
  END xb[249]
  PIN xb[24]
    DIRECTION OUTPUT ;
    USE SIGNAL ;
    PORT
      LAYER M5 ;
        RECT  74.736 69.036 74.76 69.12 ;
    END
  END xb[24]
  PIN xb[250]
    DIRECTION OUTPUT ;
    USE SIGNAL ;
    PORT
      LAYER M5 ;
        RECT  128.304 69.036 128.328 69.12 ;
    END
  END xb[250]
  PIN xb[251]
    DIRECTION OUTPUT ;
    USE SIGNAL ;
    PORT
      LAYER M5 ;
        RECT  128.544 69.036 128.568 69.12 ;
    END
  END xb[251]
  PIN xb[252]
    DIRECTION OUTPUT ;
    USE SIGNAL ;
    PORT
      LAYER M5 ;
        RECT  128.784 69.036 128.808 69.12 ;
    END
  END xb[252]
  PIN xb[253]
    DIRECTION OUTPUT ;
    USE SIGNAL ;
    PORT
      LAYER M5 ;
        RECT  129.024 69.036 129.048 69.12 ;
    END
  END xb[253]
  PIN xb[254]
    DIRECTION OUTPUT ;
    USE SIGNAL ;
    PORT
      LAYER M5 ;
        RECT  129.264 69.036 129.288 69.12 ;
    END
  END xb[254]
  PIN xb[255]
    DIRECTION OUTPUT ;
    USE SIGNAL ;
    PORT
      LAYER M5 ;
        RECT  129.504 69.036 129.528 69.12 ;
    END
  END xb[255]
  PIN xb[256]
    DIRECTION OUTPUT ;
    USE SIGNAL ;
    PORT
      LAYER M5 ;
        RECT  129.744 69.036 129.768 69.12 ;
    END
  END xb[256]
  PIN xb[257]
    DIRECTION OUTPUT ;
    USE SIGNAL ;
    PORT
      LAYER M5 ;
        RECT  129.984 69.036 130.008 69.12 ;
    END
  END xb[257]
  PIN xb[258]
    DIRECTION OUTPUT ;
    USE SIGNAL ;
    PORT
      LAYER M5 ;
        RECT  130.176 69.036 130.2 69.12 ;
    END
  END xb[258]
  PIN xb[259]
    DIRECTION OUTPUT ;
    USE SIGNAL ;
    PORT
      LAYER M5 ;
        RECT  130.416 69.036 130.44 69.12 ;
    END
  END xb[259]
  PIN xb[25]
    DIRECTION OUTPUT ;
    USE SIGNAL ;
    PORT
      LAYER M5 ;
        RECT  74.976 69.036 75 69.12 ;
    END
  END xb[25]
  PIN xb[260]
    DIRECTION OUTPUT ;
    USE SIGNAL ;
    PORT
      LAYER M5 ;
        RECT  130.656 69.036 130.68 69.12 ;
    END
  END xb[260]
  PIN xb[261]
    DIRECTION OUTPUT ;
    USE SIGNAL ;
    PORT
      LAYER M5 ;
        RECT  130.896 69.036 130.92 69.12 ;
    END
  END xb[261]
  PIN xb[262]
    DIRECTION OUTPUT ;
    USE SIGNAL ;
    PORT
      LAYER M5 ;
        RECT  131.136 69.036 131.16 69.12 ;
    END
  END xb[262]
  PIN xb[263]
    DIRECTION OUTPUT ;
    USE SIGNAL ;
    PORT
      LAYER M5 ;
        RECT  131.376 69.036 131.4 69.12 ;
    END
  END xb[263]
  PIN xb[264]
    DIRECTION OUTPUT ;
    USE SIGNAL ;
    PORT
      LAYER M5 ;
        RECT  131.616 69.036 131.64 69.12 ;
    END
  END xb[264]
  PIN xb[265]
    DIRECTION OUTPUT ;
    USE SIGNAL ;
    PORT
      LAYER M5 ;
        RECT  131.856 69.036 131.88 69.12 ;
    END
  END xb[265]
  PIN xb[26]
    DIRECTION OUTPUT ;
    USE SIGNAL ;
    PORT
      LAYER M5 ;
        RECT  75.216 69.036 75.24 69.12 ;
    END
  END xb[26]
  PIN xb[27]
    DIRECTION OUTPUT ;
    USE SIGNAL ;
    PORT
      LAYER M5 ;
        RECT  75.456 69.036 75.48 69.12 ;
    END
  END xb[27]
  PIN xb[28]
    DIRECTION OUTPUT ;
    USE SIGNAL ;
    PORT
      LAYER M5 ;
        RECT  75.696 69.036 75.72 69.12 ;
    END
  END xb[28]
  PIN xb[29]
    DIRECTION OUTPUT ;
    USE SIGNAL ;
    PORT
      LAYER M5 ;
        RECT  75.936 69.036 75.96 69.12 ;
    END
  END xb[29]
  PIN xb[2]
    DIRECTION OUTPUT ;
    USE SIGNAL ;
    PORT
      LAYER M5 ;
        RECT  69.552 69.036 69.576 69.12 ;
    END
  END xb[2]
  PIN xb[30]
    DIRECTION OUTPUT ;
    USE SIGNAL ;
    PORT
      LAYER M5 ;
        RECT  76.176 69.036 76.2 69.12 ;
    END
  END xb[30]
  PIN xb[31]
    DIRECTION OUTPUT ;
    USE SIGNAL ;
    PORT
      LAYER M5 ;
        RECT  76.416 69.036 76.44 69.12 ;
    END
  END xb[31]
  PIN xb[32]
    DIRECTION OUTPUT ;
    USE SIGNAL ;
    PORT
      LAYER M5 ;
        RECT  76.656 69.036 76.68 69.12 ;
    END
  END xb[32]
  PIN xb[33]
    DIRECTION OUTPUT ;
    USE SIGNAL ;
    PORT
      LAYER M5 ;
        RECT  76.896 69.036 76.92 69.12 ;
    END
  END xb[33]
  PIN xb[34]
    DIRECTION OUTPUT ;
    USE SIGNAL ;
    PORT
      LAYER M5 ;
        RECT  77.136 69.036 77.16 69.12 ;
    END
  END xb[34]
  PIN xb[35]
    DIRECTION OUTPUT ;
    USE SIGNAL ;
    PORT
      LAYER M5 ;
        RECT  77.328 69.036 77.352 69.12 ;
    END
  END xb[35]
  PIN xb[36]
    DIRECTION OUTPUT ;
    USE SIGNAL ;
    PORT
      LAYER M5 ;
        RECT  77.568 69.036 77.592 69.12 ;
    END
  END xb[36]
  PIN xb[37]
    DIRECTION OUTPUT ;
    USE SIGNAL ;
    PORT
      LAYER M5 ;
        RECT  77.808 69.036 77.832 69.12 ;
    END
  END xb[37]
  PIN xb[38]
    DIRECTION OUTPUT ;
    USE SIGNAL ;
    PORT
      LAYER M5 ;
        RECT  78.048 69.036 78.072 69.12 ;
    END
  END xb[38]
  PIN xb[39]
    DIRECTION OUTPUT ;
    USE SIGNAL ;
    PORT
      LAYER M5 ;
        RECT  78.288 69.036 78.312 69.12 ;
    END
  END xb[39]
  PIN xb[3]
    DIRECTION OUTPUT ;
    USE SIGNAL ;
    PORT
      LAYER M5 ;
        RECT  69.744 69.036 69.768 69.12 ;
    END
  END xb[3]
  PIN xb[40]
    DIRECTION OUTPUT ;
    USE SIGNAL ;
    PORT
      LAYER M5 ;
        RECT  78.528 69.036 78.552 69.12 ;
    END
  END xb[40]
  PIN xb[41]
    DIRECTION OUTPUT ;
    USE SIGNAL ;
    PORT
      LAYER M5 ;
        RECT  78.768 69.036 78.792 69.12 ;
    END
  END xb[41]
  PIN xb[42]
    DIRECTION OUTPUT ;
    USE SIGNAL ;
    PORT
      LAYER M5 ;
        RECT  79.008 69.036 79.032 69.12 ;
    END
  END xb[42]
  PIN xb[43]
    DIRECTION OUTPUT ;
    USE SIGNAL ;
    PORT
      LAYER M5 ;
        RECT  79.248 69.036 79.272 69.12 ;
    END
  END xb[43]
  PIN xb[44]
    DIRECTION OUTPUT ;
    USE SIGNAL ;
    PORT
      LAYER M5 ;
        RECT  79.488 69.036 79.512 69.12 ;
    END
  END xb[44]
  PIN xb[45]
    DIRECTION OUTPUT ;
    USE SIGNAL ;
    PORT
      LAYER M5 ;
        RECT  79.728 69.036 79.752 69.12 ;
    END
  END xb[45]
  PIN xb[46]
    DIRECTION OUTPUT ;
    USE SIGNAL ;
    PORT
      LAYER M5 ;
        RECT  79.968 69.036 79.992 69.12 ;
    END
  END xb[46]
  PIN xb[47]
    DIRECTION OUTPUT ;
    USE SIGNAL ;
    PORT
      LAYER M5 ;
        RECT  80.208 69.036 80.232 69.12 ;
    END
  END xb[47]
  PIN xb[48]
    DIRECTION OUTPUT ;
    USE SIGNAL ;
    PORT
      LAYER M5 ;
        RECT  80.448 69.036 80.472 69.12 ;
    END
  END xb[48]
  PIN xb[49]
    DIRECTION OUTPUT ;
    USE SIGNAL ;
    PORT
      LAYER M5 ;
        RECT  80.688 69.036 80.712 69.12 ;
    END
  END xb[49]
  PIN xb[4]
    DIRECTION OUTPUT ;
    USE SIGNAL ;
    PORT
      LAYER M5 ;
        RECT  69.984 69.036 70.008 69.12 ;
    END
  END xb[4]
  PIN xb[50]
    DIRECTION OUTPUT ;
    USE SIGNAL ;
    PORT
      LAYER M5 ;
        RECT  80.928 69.036 80.952 69.12 ;
    END
  END xb[50]
  PIN xb[51]
    DIRECTION OUTPUT ;
    USE SIGNAL ;
    PORT
      LAYER M5 ;
        RECT  81.12 69.036 81.144 69.12 ;
    END
  END xb[51]
  PIN xb[52]
    DIRECTION OUTPUT ;
    USE SIGNAL ;
    PORT
      LAYER M5 ;
        RECT  81.36 69.036 81.384 69.12 ;
    END
  END xb[52]
  PIN xb[53]
    DIRECTION OUTPUT ;
    USE SIGNAL ;
    PORT
      LAYER M5 ;
        RECT  81.6 69.036 81.624 69.12 ;
    END
  END xb[53]
  PIN xb[54]
    DIRECTION OUTPUT ;
    USE SIGNAL ;
    PORT
      LAYER M5 ;
        RECT  81.84 69.036 81.864 69.12 ;
    END
  END xb[54]
  PIN xb[55]
    DIRECTION OUTPUT ;
    USE SIGNAL ;
    PORT
      LAYER M5 ;
        RECT  82.08 69.036 82.104 69.12 ;
    END
  END xb[55]
  PIN xb[56]
    DIRECTION OUTPUT ;
    USE SIGNAL ;
    PORT
      LAYER M5 ;
        RECT  82.32 69.036 82.344 69.12 ;
    END
  END xb[56]
  PIN xb[57]
    DIRECTION OUTPUT ;
    USE SIGNAL ;
    PORT
      LAYER M5 ;
        RECT  82.56 69.036 82.584 69.12 ;
    END
  END xb[57]
  PIN xb[58]
    DIRECTION OUTPUT ;
    USE SIGNAL ;
    PORT
      LAYER M5 ;
        RECT  82.8 69.036 82.824 69.12 ;
    END
  END xb[58]
  PIN xb[59]
    DIRECTION OUTPUT ;
    USE SIGNAL ;
    PORT
      LAYER M5 ;
        RECT  83.04 69.036 83.064 69.12 ;
    END
  END xb[59]
  PIN xb[5]
    DIRECTION OUTPUT ;
    USE SIGNAL ;
    PORT
      LAYER M5 ;
        RECT  70.224 69.036 70.248 69.12 ;
    END
  END xb[5]
  PIN xb[60]
    DIRECTION OUTPUT ;
    USE SIGNAL ;
    PORT
      LAYER M5 ;
        RECT  83.28 69.036 83.304 69.12 ;
    END
  END xb[60]
  PIN xb[61]
    DIRECTION OUTPUT ;
    USE SIGNAL ;
    PORT
      LAYER M5 ;
        RECT  83.52 69.036 83.544 69.12 ;
    END
  END xb[61]
  PIN xb[62]
    DIRECTION OUTPUT ;
    USE SIGNAL ;
    PORT
      LAYER M5 ;
        RECT  83.76 69.036 83.784 69.12 ;
    END
  END xb[62]
  PIN xb[63]
    DIRECTION OUTPUT ;
    USE SIGNAL ;
    PORT
      LAYER M5 ;
        RECT  84 69.036 84.024 69.12 ;
    END
  END xb[63]
  PIN xb[64]
    DIRECTION OUTPUT ;
    USE SIGNAL ;
    PORT
      LAYER M5 ;
        RECT  84.24 69.036 84.264 69.12 ;
    END
  END xb[64]
  PIN xb[65]
    DIRECTION OUTPUT ;
    USE SIGNAL ;
    PORT
      LAYER M5 ;
        RECT  84.48 69.036 84.504 69.12 ;
    END
  END xb[65]
  PIN xb[66]
    DIRECTION OUTPUT ;
    USE SIGNAL ;
    PORT
      LAYER M5 ;
        RECT  84.72 69.036 84.744 69.12 ;
    END
  END xb[66]
  PIN xb[67]
    DIRECTION OUTPUT ;
    USE SIGNAL ;
    PORT
      LAYER M5 ;
        RECT  84.912 69.036 84.936 69.12 ;
    END
  END xb[67]
  PIN xb[68]
    DIRECTION OUTPUT ;
    USE SIGNAL ;
    PORT
      LAYER M5 ;
        RECT  85.152 69.036 85.176 69.12 ;
    END
  END xb[68]
  PIN xb[69]
    DIRECTION OUTPUT ;
    USE SIGNAL ;
    PORT
      LAYER M5 ;
        RECT  85.392 69.036 85.416 69.12 ;
    END
  END xb[69]
  PIN xb[6]
    DIRECTION OUTPUT ;
    USE SIGNAL ;
    PORT
      LAYER M5 ;
        RECT  70.464 69.036 70.488 69.12 ;
    END
  END xb[6]
  PIN xb[70]
    DIRECTION OUTPUT ;
    USE SIGNAL ;
    PORT
      LAYER M5 ;
        RECT  85.632 69.036 85.656 69.12 ;
    END
  END xb[70]
  PIN xb[71]
    DIRECTION OUTPUT ;
    USE SIGNAL ;
    PORT
      LAYER M5 ;
        RECT  85.872 69.036 85.896 69.12 ;
    END
  END xb[71]
  PIN xb[72]
    DIRECTION OUTPUT ;
    USE SIGNAL ;
    PORT
      LAYER M5 ;
        RECT  86.112 69.036 86.136 69.12 ;
    END
  END xb[72]
  PIN xb[73]
    DIRECTION OUTPUT ;
    USE SIGNAL ;
    PORT
      LAYER M5 ;
        RECT  86.352 69.036 86.376 69.12 ;
    END
  END xb[73]
  PIN xb[74]
    DIRECTION OUTPUT ;
    USE SIGNAL ;
    PORT
      LAYER M5 ;
        RECT  86.592 69.036 86.616 69.12 ;
    END
  END xb[74]
  PIN xb[75]
    DIRECTION OUTPUT ;
    USE SIGNAL ;
    PORT
      LAYER M5 ;
        RECT  86.832 69.036 86.856 69.12 ;
    END
  END xb[75]
  PIN xb[76]
    DIRECTION OUTPUT ;
    USE SIGNAL ;
    PORT
      LAYER M5 ;
        RECT  87.072 69.036 87.096 69.12 ;
    END
  END xb[76]
  PIN xb[77]
    DIRECTION OUTPUT ;
    USE SIGNAL ;
    PORT
      LAYER M5 ;
        RECT  87.312 69.036 87.336 69.12 ;
    END
  END xb[77]
  PIN xb[78]
    DIRECTION OUTPUT ;
    USE SIGNAL ;
    PORT
      LAYER M5 ;
        RECT  87.552 69.036 87.576 69.12 ;
    END
  END xb[78]
  PIN xb[79]
    DIRECTION OUTPUT ;
    USE SIGNAL ;
    PORT
      LAYER M5 ;
        RECT  87.792 69.036 87.816 69.12 ;
    END
  END xb[79]
  PIN xb[7]
    DIRECTION OUTPUT ;
    USE SIGNAL ;
    PORT
      LAYER M5 ;
        RECT  70.704 69.036 70.728 69.12 ;
    END
  END xb[7]
  PIN xb[80]
    DIRECTION OUTPUT ;
    USE SIGNAL ;
    PORT
      LAYER M5 ;
        RECT  88.032 69.036 88.056 69.12 ;
    END
  END xb[80]
  PIN xb[81]
    DIRECTION OUTPUT ;
    USE SIGNAL ;
    PORT
      LAYER M5 ;
        RECT  88.272 69.036 88.296 69.12 ;
    END
  END xb[81]
  PIN xb[82]
    DIRECTION OUTPUT ;
    USE SIGNAL ;
    PORT
      LAYER M5 ;
        RECT  88.512 69.036 88.536 69.12 ;
    END
  END xb[82]
  PIN xb[83]
    DIRECTION OUTPUT ;
    USE SIGNAL ;
    PORT
      LAYER M5 ;
        RECT  88.704 69.036 88.728 69.12 ;
    END
  END xb[83]
  PIN xb[84]
    DIRECTION OUTPUT ;
    USE SIGNAL ;
    PORT
      LAYER M5 ;
        RECT  88.944 69.036 88.968 69.12 ;
    END
  END xb[84]
  PIN xb[85]
    DIRECTION OUTPUT ;
    USE SIGNAL ;
    PORT
      LAYER M5 ;
        RECT  89.184 69.036 89.208 69.12 ;
    END
  END xb[85]
  PIN xb[86]
    DIRECTION OUTPUT ;
    USE SIGNAL ;
    PORT
      LAYER M5 ;
        RECT  89.424 69.036 89.448 69.12 ;
    END
  END xb[86]
  PIN xb[87]
    DIRECTION OUTPUT ;
    USE SIGNAL ;
    PORT
      LAYER M5 ;
        RECT  89.664 69.036 89.688 69.12 ;
    END
  END xb[87]
  PIN xb[88]
    DIRECTION OUTPUT ;
    USE SIGNAL ;
    PORT
      LAYER M5 ;
        RECT  89.904 69.036 89.928 69.12 ;
    END
  END xb[88]
  PIN xb[89]
    DIRECTION OUTPUT ;
    USE SIGNAL ;
    PORT
      LAYER M5 ;
        RECT  90.144 69.036 90.168 69.12 ;
    END
  END xb[89]
  PIN xb[8]
    DIRECTION OUTPUT ;
    USE SIGNAL ;
    PORT
      LAYER M5 ;
        RECT  70.944 69.036 70.968 69.12 ;
    END
  END xb[8]
  PIN xb[90]
    DIRECTION OUTPUT ;
    USE SIGNAL ;
    PORT
      LAYER M5 ;
        RECT  90.384 69.036 90.408 69.12 ;
    END
  END xb[90]
  PIN xb[91]
    DIRECTION OUTPUT ;
    USE SIGNAL ;
    PORT
      LAYER M5 ;
        RECT  90.624 69.036 90.648 69.12 ;
    END
  END xb[91]
  PIN xb[92]
    DIRECTION OUTPUT ;
    USE SIGNAL ;
    PORT
      LAYER M5 ;
        RECT  90.864 69.036 90.888 69.12 ;
    END
  END xb[92]
  PIN xb[93]
    DIRECTION OUTPUT ;
    USE SIGNAL ;
    PORT
      LAYER M5 ;
        RECT  91.104 69.036 91.128 69.12 ;
    END
  END xb[93]
  PIN xb[94]
    DIRECTION OUTPUT ;
    USE SIGNAL ;
    PORT
      LAYER M5 ;
        RECT  91.344 69.036 91.368 69.12 ;
    END
  END xb[94]
  PIN xb[95]
    DIRECTION OUTPUT ;
    USE SIGNAL ;
    PORT
      LAYER M5 ;
        RECT  91.584 69.036 91.608 69.12 ;
    END
  END xb[95]
  PIN xb[96]
    DIRECTION OUTPUT ;
    USE SIGNAL ;
    PORT
      LAYER M5 ;
        RECT  91.824 69.036 91.848 69.12 ;
    END
  END xb[96]
  PIN xb[97]
    DIRECTION OUTPUT ;
    USE SIGNAL ;
    PORT
      LAYER M5 ;
        RECT  92.064 69.036 92.088 69.12 ;
    END
  END xb[97]
  PIN xb[98]
    DIRECTION OUTPUT ;
    USE SIGNAL ;
    PORT
      LAYER M5 ;
        RECT  92.256 69.036 92.28 69.12 ;
    END
  END xb[98]
  PIN xb[99]
    DIRECTION OUTPUT ;
    USE SIGNAL ;
    PORT
      LAYER M5 ;
        RECT  92.496 69.036 92.52 69.12 ;
    END
  END xb[99]
  PIN xb[9]
    DIRECTION OUTPUT ;
    USE SIGNAL ;
    PORT
      LAYER M5 ;
        RECT  71.184 69.036 71.208 69.12 ;
    END
  END xb[9]
  PIN xk[0]
    DIRECTION INPUT ;
    USE SIGNAL ;
    PORT
      LAYER M5 ;
        RECT  34.416 0 34.44 0.084 ;
    END
  END xk[0]
  PIN xk[1]
    DIRECTION INPUT ;
    USE SIGNAL ;
    PORT
      LAYER M5 ;
        RECT  99.552 0 99.576 0.084 ;
    END
  END xk[1]
  PIN xk[2]
    DIRECTION INPUT ;
    USE SIGNAL ;
    PORT
      LAYER M5 ;
        RECT  164.688 0 164.712 0.084 ;
    END
  END xk[2]
  PIN xk[3]
    DIRECTION INPUT ;
    USE SIGNAL ;
    PORT
      LAYER M5 ;
        RECT  229.824 0 229.848 0.084 ;
    END
  END xk[3]
  PIN xl0[0]
    DIRECTION INPUT ;
    USE SIGNAL ;
    PORT
      LAYER M5 ;
        RECT  1.968 0 1.992 0.084 ;
    END
  END xl0[0]
  PIN xl0[100]
    DIRECTION INPUT ;
    USE SIGNAL ;
    PORT
      LAYER M5 ;
        RECT  25.584 0 25.608 0.084 ;
    END
  END xl0[100]
  PIN xl0[101]
    DIRECTION INPUT ;
    USE SIGNAL ;
    PORT
      LAYER M5 ;
        RECT  25.824 0 25.848 0.084 ;
    END
  END xl0[101]
  PIN xl0[102]
    DIRECTION INPUT ;
    USE SIGNAL ;
    PORT
      LAYER M5 ;
        RECT  26.064 0 26.088 0.084 ;
    END
  END xl0[102]
  PIN xl0[103]
    DIRECTION INPUT ;
    USE SIGNAL ;
    PORT
      LAYER M5 ;
        RECT  26.304 0 26.328 0.084 ;
    END
  END xl0[103]
  PIN xl0[104]
    DIRECTION INPUT ;
    USE SIGNAL ;
    PORT
      LAYER M5 ;
        RECT  26.544 0 26.568 0.084 ;
    END
  END xl0[104]
  PIN xl0[105]
    DIRECTION INPUT ;
    USE SIGNAL ;
    PORT
      LAYER M5 ;
        RECT  26.784 0 26.808 0.084 ;
    END
  END xl0[105]
  PIN xl0[106]
    DIRECTION INPUT ;
    USE SIGNAL ;
    PORT
      LAYER M5 ;
        RECT  27.024 0 27.048 0.084 ;
    END
  END xl0[106]
  PIN xl0[107]
    DIRECTION INPUT ;
    USE SIGNAL ;
    PORT
      LAYER M5 ;
        RECT  27.216 0 27.24 0.084 ;
    END
  END xl0[107]
  PIN xl0[108]
    DIRECTION INPUT ;
    USE SIGNAL ;
    PORT
      LAYER M5 ;
        RECT  27.456 0 27.48 0.084 ;
    END
  END xl0[108]
  PIN xl0[109]
    DIRECTION INPUT ;
    USE SIGNAL ;
    PORT
      LAYER M5 ;
        RECT  27.696 0 27.72 0.084 ;
    END
  END xl0[109]
  PIN xl0[10]
    DIRECTION INPUT ;
    USE SIGNAL ;
    PORT
      LAYER M5 ;
        RECT  4.368 0 4.392 0.084 ;
    END
  END xl0[10]
  PIN xl0[110]
    DIRECTION INPUT ;
    USE SIGNAL ;
    PORT
      LAYER M5 ;
        RECT  27.936 0 27.96 0.084 ;
    END
  END xl0[110]
  PIN xl0[111]
    DIRECTION INPUT ;
    USE SIGNAL ;
    PORT
      LAYER M5 ;
        RECT  28.176 0 28.2 0.084 ;
    END
  END xl0[111]
  PIN xl0[112]
    DIRECTION INPUT ;
    USE SIGNAL ;
    PORT
      LAYER M5 ;
        RECT  28.416 0 28.44 0.084 ;
    END
  END xl0[112]
  PIN xl0[113]
    DIRECTION INPUT ;
    USE SIGNAL ;
    PORT
      LAYER M5 ;
        RECT  28.656 0 28.68 0.084 ;
    END
  END xl0[113]
  PIN xl0[114]
    DIRECTION INPUT ;
    USE SIGNAL ;
    PORT
      LAYER M5 ;
        RECT  28.896 0 28.92 0.084 ;
    END
  END xl0[114]
  PIN xl0[115]
    DIRECTION INPUT ;
    USE SIGNAL ;
    PORT
      LAYER M5 ;
        RECT  29.136 0 29.16 0.084 ;
    END
  END xl0[115]
  PIN xl0[116]
    DIRECTION INPUT ;
    USE SIGNAL ;
    PORT
      LAYER M5 ;
        RECT  29.376 0 29.4 0.084 ;
    END
  END xl0[116]
  PIN xl0[117]
    DIRECTION INPUT ;
    USE SIGNAL ;
    PORT
      LAYER M5 ;
        RECT  29.616 0 29.64 0.084 ;
    END
  END xl0[117]
  PIN xl0[118]
    DIRECTION INPUT ;
    USE SIGNAL ;
    PORT
      LAYER M5 ;
        RECT  29.856 0 29.88 0.084 ;
    END
  END xl0[118]
  PIN xl0[119]
    DIRECTION INPUT ;
    USE SIGNAL ;
    PORT
      LAYER M5 ;
        RECT  30.048 0 30.072 0.084 ;
    END
  END xl0[119]
  PIN xl0[11]
    DIRECTION INPUT ;
    USE SIGNAL ;
    PORT
      LAYER M5 ;
        RECT  4.56 0 4.584 0.084 ;
    END
  END xl0[11]
  PIN xl0[120]
    DIRECTION INPUT ;
    USE SIGNAL ;
    PORT
      LAYER M5 ;
        RECT  30.288 0 30.312 0.084 ;
    END
  END xl0[120]
  PIN xl0[121]
    DIRECTION INPUT ;
    USE SIGNAL ;
    PORT
      LAYER M5 ;
        RECT  30.528 0 30.552 0.084 ;
    END
  END xl0[121]
  PIN xl0[122]
    DIRECTION INPUT ;
    USE SIGNAL ;
    PORT
      LAYER M5 ;
        RECT  30.768 0 30.792 0.084 ;
    END
  END xl0[122]
  PIN xl0[123]
    DIRECTION INPUT ;
    USE SIGNAL ;
    PORT
      LAYER M5 ;
        RECT  31.008 0 31.032 0.084 ;
    END
  END xl0[123]
  PIN xl0[124]
    DIRECTION INPUT ;
    USE SIGNAL ;
    PORT
      LAYER M5 ;
        RECT  31.248 0 31.272 0.084 ;
    END
  END xl0[124]
  PIN xl0[125]
    DIRECTION INPUT ;
    USE SIGNAL ;
    PORT
      LAYER M5 ;
        RECT  31.488 0 31.512 0.084 ;
    END
  END xl0[125]
  PIN xl0[126]
    DIRECTION INPUT ;
    USE SIGNAL ;
    PORT
      LAYER M5 ;
        RECT  31.728 0 31.752 0.084 ;
    END
  END xl0[126]
  PIN xl0[127]
    DIRECTION INPUT ;
    USE SIGNAL ;
    PORT
      LAYER M5 ;
        RECT  31.968 0 31.992 0.084 ;
    END
  END xl0[127]
  PIN xl0[128]
    DIRECTION INPUT ;
    USE SIGNAL ;
    PORT
      LAYER M5 ;
        RECT  32.208 0 32.232 0.084 ;
    END
  END xl0[128]
  PIN xl0[129]
    DIRECTION INPUT ;
    USE SIGNAL ;
    PORT
      LAYER M5 ;
        RECT  32.448 0 32.472 0.084 ;
    END
  END xl0[129]
  PIN xl0[12]
    DIRECTION INPUT ;
    USE SIGNAL ;
    PORT
      LAYER M5 ;
        RECT  4.8 0 4.824 0.084 ;
    END
  END xl0[12]
  PIN xl0[130]
    DIRECTION INPUT ;
    USE SIGNAL ;
    PORT
      LAYER M5 ;
        RECT  32.688 0 32.712 0.084 ;
    END
  END xl0[130]
  PIN xl0[131]
    DIRECTION INPUT ;
    USE SIGNAL ;
    PORT
      LAYER M5 ;
        RECT  32.88 0 32.904 0.084 ;
    END
  END xl0[131]
  PIN xl0[132]
    DIRECTION INPUT ;
    USE SIGNAL ;
    PORT
      LAYER M5 ;
        RECT  33.12 0 33.144 0.084 ;
    END
  END xl0[132]
  PIN xl0[133]
    DIRECTION INPUT ;
    USE SIGNAL ;
    PORT
      LAYER M5 ;
        RECT  33.36 0 33.384 0.084 ;
    END
  END xl0[133]
  PIN xl0[134]
    DIRECTION INPUT ;
    USE SIGNAL ;
    PORT
      LAYER M5 ;
        RECT  33.6 0 33.624 0.084 ;
    END
  END xl0[134]
  PIN xl0[135]
    DIRECTION INPUT ;
    USE SIGNAL ;
    PORT
      LAYER M5 ;
        RECT  33.84 0 33.864 0.084 ;
    END
  END xl0[135]
  PIN xl0[136]
    DIRECTION INPUT ;
    USE SIGNAL ;
    PORT
      LAYER M5 ;
        RECT  34.08 0 34.104 0.084 ;
    END
  END xl0[136]
  PIN xl0[137]
    DIRECTION INPUT ;
    USE SIGNAL ;
    PORT
      LAYER M5 ;
        RECT  34.32 0 34.344 0.084 ;
    END
  END xl0[137]
  PIN xl0[138]
    DIRECTION INPUT ;
    USE SIGNAL ;
    PORT
      LAYER M5 ;
        RECT  34.56 0 34.584 0.084 ;
    END
  END xl0[138]
  PIN xl0[139]
    DIRECTION INPUT ;
    USE SIGNAL ;
    PORT
      LAYER M5 ;
        RECT  34.8 0 34.824 0.084 ;
    END
  END xl0[139]
  PIN xl0[13]
    DIRECTION INPUT ;
    USE SIGNAL ;
    PORT
      LAYER M5 ;
        RECT  5.04 0 5.064 0.084 ;
    END
  END xl0[13]
  PIN xl0[140]
    DIRECTION INPUT ;
    USE SIGNAL ;
    PORT
      LAYER M5 ;
        RECT  35.04 0 35.064 0.084 ;
    END
  END xl0[140]
  PIN xl0[141]
    DIRECTION INPUT ;
    USE SIGNAL ;
    PORT
      LAYER M5 ;
        RECT  35.28 0 35.304 0.084 ;
    END
  END xl0[141]
  PIN xl0[142]
    DIRECTION INPUT ;
    USE SIGNAL ;
    PORT
      LAYER M5 ;
        RECT  35.52 0 35.544 0.084 ;
    END
  END xl0[142]
  PIN xl0[143]
    DIRECTION INPUT ;
    USE SIGNAL ;
    PORT
      LAYER M5 ;
        RECT  35.712 0 35.736 0.084 ;
    END
  END xl0[143]
  PIN xl0[144]
    DIRECTION INPUT ;
    USE SIGNAL ;
    PORT
      LAYER M5 ;
        RECT  35.952 0 35.976 0.084 ;
    END
  END xl0[144]
  PIN xl0[145]
    DIRECTION INPUT ;
    USE SIGNAL ;
    PORT
      LAYER M5 ;
        RECT  36.192 0 36.216 0.084 ;
    END
  END xl0[145]
  PIN xl0[146]
    DIRECTION INPUT ;
    USE SIGNAL ;
    PORT
      LAYER M5 ;
        RECT  36.432 0 36.456 0.084 ;
    END
  END xl0[146]
  PIN xl0[147]
    DIRECTION INPUT ;
    USE SIGNAL ;
    PORT
      LAYER M5 ;
        RECT  36.672 0 36.696 0.084 ;
    END
  END xl0[147]
  PIN xl0[148]
    DIRECTION INPUT ;
    USE SIGNAL ;
    PORT
      LAYER M5 ;
        RECT  36.912 0 36.936 0.084 ;
    END
  END xl0[148]
  PIN xl0[149]
    DIRECTION INPUT ;
    USE SIGNAL ;
    PORT
      LAYER M5 ;
        RECT  37.152 0 37.176 0.084 ;
    END
  END xl0[149]
  PIN xl0[14]
    DIRECTION INPUT ;
    USE SIGNAL ;
    PORT
      LAYER M5 ;
        RECT  5.28 0 5.304 0.084 ;
    END
  END xl0[14]
  PIN xl0[150]
    DIRECTION INPUT ;
    USE SIGNAL ;
    PORT
      LAYER M5 ;
        RECT  37.392 0 37.416 0.084 ;
    END
  END xl0[150]
  PIN xl0[151]
    DIRECTION INPUT ;
    USE SIGNAL ;
    PORT
      LAYER M5 ;
        RECT  37.632 0 37.656 0.084 ;
    END
  END xl0[151]
  PIN xl0[152]
    DIRECTION INPUT ;
    USE SIGNAL ;
    PORT
      LAYER M5 ;
        RECT  37.872 0 37.896 0.084 ;
    END
  END xl0[152]
  PIN xl0[153]
    DIRECTION INPUT ;
    USE SIGNAL ;
    PORT
      LAYER M5 ;
        RECT  38.112 0 38.136 0.084 ;
    END
  END xl0[153]
  PIN xl0[154]
    DIRECTION INPUT ;
    USE SIGNAL ;
    PORT
      LAYER M5 ;
        RECT  38.352 0 38.376 0.084 ;
    END
  END xl0[154]
  PIN xl0[155]
    DIRECTION INPUT ;
    USE SIGNAL ;
    PORT
      LAYER M5 ;
        RECT  38.544 0 38.568 0.084 ;
    END
  END xl0[155]
  PIN xl0[156]
    DIRECTION INPUT ;
    USE SIGNAL ;
    PORT
      LAYER M5 ;
        RECT  38.784 0 38.808 0.084 ;
    END
  END xl0[156]
  PIN xl0[157]
    DIRECTION INPUT ;
    USE SIGNAL ;
    PORT
      LAYER M5 ;
        RECT  39.024 0 39.048 0.084 ;
    END
  END xl0[157]
  PIN xl0[158]
    DIRECTION INPUT ;
    USE SIGNAL ;
    PORT
      LAYER M5 ;
        RECT  39.264 0 39.288 0.084 ;
    END
  END xl0[158]
  PIN xl0[159]
    DIRECTION INPUT ;
    USE SIGNAL ;
    PORT
      LAYER M5 ;
        RECT  39.504 0 39.528 0.084 ;
    END
  END xl0[159]
  PIN xl0[15]
    DIRECTION INPUT ;
    USE SIGNAL ;
    PORT
      LAYER M5 ;
        RECT  5.52 0 5.544 0.084 ;
    END
  END xl0[15]
  PIN xl0[160]
    DIRECTION INPUT ;
    USE SIGNAL ;
    PORT
      LAYER M5 ;
        RECT  39.744 0 39.768 0.084 ;
    END
  END xl0[160]
  PIN xl0[161]
    DIRECTION INPUT ;
    USE SIGNAL ;
    PORT
      LAYER M5 ;
        RECT  39.984 0 40.008 0.084 ;
    END
  END xl0[161]
  PIN xl0[162]
    DIRECTION INPUT ;
    USE SIGNAL ;
    PORT
      LAYER M5 ;
        RECT  40.224 0 40.248 0.084 ;
    END
  END xl0[162]
  PIN xl0[163]
    DIRECTION INPUT ;
    USE SIGNAL ;
    PORT
      LAYER M5 ;
        RECT  40.464 0 40.488 0.084 ;
    END
  END xl0[163]
  PIN xl0[164]
    DIRECTION INPUT ;
    USE SIGNAL ;
    PORT
      LAYER M5 ;
        RECT  40.704 0 40.728 0.084 ;
    END
  END xl0[164]
  PIN xl0[165]
    DIRECTION INPUT ;
    USE SIGNAL ;
    PORT
      LAYER M5 ;
        RECT  40.944 0 40.968 0.084 ;
    END
  END xl0[165]
  PIN xl0[166]
    DIRECTION INPUT ;
    USE SIGNAL ;
    PORT
      LAYER M5 ;
        RECT  41.184 0 41.208 0.084 ;
    END
  END xl0[166]
  PIN xl0[167]
    DIRECTION INPUT ;
    USE SIGNAL ;
    PORT
      LAYER M5 ;
        RECT  41.376 0 41.4 0.084 ;
    END
  END xl0[167]
  PIN xl0[168]
    DIRECTION INPUT ;
    USE SIGNAL ;
    PORT
      LAYER M5 ;
        RECT  41.616 0 41.64 0.084 ;
    END
  END xl0[168]
  PIN xl0[169]
    DIRECTION INPUT ;
    USE SIGNAL ;
    PORT
      LAYER M5 ;
        RECT  41.856 0 41.88 0.084 ;
    END
  END xl0[169]
  PIN xl0[16]
    DIRECTION INPUT ;
    USE SIGNAL ;
    PORT
      LAYER M5 ;
        RECT  5.76 0 5.784 0.084 ;
    END
  END xl0[16]
  PIN xl0[170]
    DIRECTION INPUT ;
    USE SIGNAL ;
    PORT
      LAYER M5 ;
        RECT  42.096 0 42.12 0.084 ;
    END
  END xl0[170]
  PIN xl0[171]
    DIRECTION INPUT ;
    USE SIGNAL ;
    PORT
      LAYER M5 ;
        RECT  42.336 0 42.36 0.084 ;
    END
  END xl0[171]
  PIN xl0[172]
    DIRECTION INPUT ;
    USE SIGNAL ;
    PORT
      LAYER M5 ;
        RECT  42.576 0 42.6 0.084 ;
    END
  END xl0[172]
  PIN xl0[173]
    DIRECTION INPUT ;
    USE SIGNAL ;
    PORT
      LAYER M5 ;
        RECT  42.816 0 42.84 0.084 ;
    END
  END xl0[173]
  PIN xl0[174]
    DIRECTION INPUT ;
    USE SIGNAL ;
    PORT
      LAYER M5 ;
        RECT  43.056 0 43.08 0.084 ;
    END
  END xl0[174]
  PIN xl0[175]
    DIRECTION INPUT ;
    USE SIGNAL ;
    PORT
      LAYER M5 ;
        RECT  43.296 0 43.32 0.084 ;
    END
  END xl0[175]
  PIN xl0[176]
    DIRECTION INPUT ;
    USE SIGNAL ;
    PORT
      LAYER M5 ;
        RECT  43.536 0 43.56 0.084 ;
    END
  END xl0[176]
  PIN xl0[177]
    DIRECTION INPUT ;
    USE SIGNAL ;
    PORT
      LAYER M5 ;
        RECT  43.776 0 43.8 0.084 ;
    END
  END xl0[177]
  PIN xl0[178]
    DIRECTION INPUT ;
    USE SIGNAL ;
    PORT
      LAYER M5 ;
        RECT  43.968 0 43.992 0.084 ;
    END
  END xl0[178]
  PIN xl0[179]
    DIRECTION INPUT ;
    USE SIGNAL ;
    PORT
      LAYER M5 ;
        RECT  44.208 0 44.232 0.084 ;
    END
  END xl0[179]
  PIN xl0[17]
    DIRECTION INPUT ;
    USE SIGNAL ;
    PORT
      LAYER M5 ;
        RECT  6 0 6.024 0.084 ;
    END
  END xl0[17]
  PIN xl0[180]
    DIRECTION INPUT ;
    USE SIGNAL ;
    PORT
      LAYER M5 ;
        RECT  44.448 0 44.472 0.084 ;
    END
  END xl0[180]
  PIN xl0[181]
    DIRECTION INPUT ;
    USE SIGNAL ;
    PORT
      LAYER M5 ;
        RECT  44.688 0 44.712 0.084 ;
    END
  END xl0[181]
  PIN xl0[182]
    DIRECTION INPUT ;
    USE SIGNAL ;
    PORT
      LAYER M5 ;
        RECT  44.928 0 44.952 0.084 ;
    END
  END xl0[182]
  PIN xl0[183]
    DIRECTION INPUT ;
    USE SIGNAL ;
    PORT
      LAYER M5 ;
        RECT  45.168 0 45.192 0.084 ;
    END
  END xl0[183]
  PIN xl0[184]
    DIRECTION INPUT ;
    USE SIGNAL ;
    PORT
      LAYER M5 ;
        RECT  45.408 0 45.432 0.084 ;
    END
  END xl0[184]
  PIN xl0[185]
    DIRECTION INPUT ;
    USE SIGNAL ;
    PORT
      LAYER M5 ;
        RECT  45.648 0 45.672 0.084 ;
    END
  END xl0[185]
  PIN xl0[186]
    DIRECTION INPUT ;
    USE SIGNAL ;
    PORT
      LAYER M5 ;
        RECT  45.888 0 45.912 0.084 ;
    END
  END xl0[186]
  PIN xl0[187]
    DIRECTION INPUT ;
    USE SIGNAL ;
    PORT
      LAYER M5 ;
        RECT  46.128 0 46.152 0.084 ;
    END
  END xl0[187]
  PIN xl0[188]
    DIRECTION INPUT ;
    USE SIGNAL ;
    PORT
      LAYER M5 ;
        RECT  46.368 0 46.392 0.084 ;
    END
  END xl0[188]
  PIN xl0[189]
    DIRECTION INPUT ;
    USE SIGNAL ;
    PORT
      LAYER M5 ;
        RECT  46.608 0 46.632 0.084 ;
    END
  END xl0[189]
  PIN xl0[18]
    DIRECTION INPUT ;
    USE SIGNAL ;
    PORT
      LAYER M5 ;
        RECT  6.24 0 6.264 0.084 ;
    END
  END xl0[18]
  PIN xl0[190]
    DIRECTION INPUT ;
    USE SIGNAL ;
    PORT
      LAYER M5 ;
        RECT  46.8 0 46.824 0.084 ;
    END
  END xl0[190]
  PIN xl0[191]
    DIRECTION INPUT ;
    USE SIGNAL ;
    PORT
      LAYER M5 ;
        RECT  47.04 0 47.064 0.084 ;
    END
  END xl0[191]
  PIN xl0[192]
    DIRECTION INPUT ;
    USE SIGNAL ;
    PORT
      LAYER M5 ;
        RECT  47.28 0 47.304 0.084 ;
    END
  END xl0[192]
  PIN xl0[193]
    DIRECTION INPUT ;
    USE SIGNAL ;
    PORT
      LAYER M5 ;
        RECT  47.52 0 47.544 0.084 ;
    END
  END xl0[193]
  PIN xl0[194]
    DIRECTION INPUT ;
    USE SIGNAL ;
    PORT
      LAYER M5 ;
        RECT  47.76 0 47.784 0.084 ;
    END
  END xl0[194]
  PIN xl0[195]
    DIRECTION INPUT ;
    USE SIGNAL ;
    PORT
      LAYER M5 ;
        RECT  48 0 48.024 0.084 ;
    END
  END xl0[195]
  PIN xl0[196]
    DIRECTION INPUT ;
    USE SIGNAL ;
    PORT
      LAYER M5 ;
        RECT  48.24 0 48.264 0.084 ;
    END
  END xl0[196]
  PIN xl0[197]
    DIRECTION INPUT ;
    USE SIGNAL ;
    PORT
      LAYER M5 ;
        RECT  48.48 0 48.504 0.084 ;
    END
  END xl0[197]
  PIN xl0[198]
    DIRECTION INPUT ;
    USE SIGNAL ;
    PORT
      LAYER M5 ;
        RECT  48.72 0 48.744 0.084 ;
    END
  END xl0[198]
  PIN xl0[199]
    DIRECTION INPUT ;
    USE SIGNAL ;
    PORT
      LAYER M5 ;
        RECT  48.96 0 48.984 0.084 ;
    END
  END xl0[199]
  PIN xl0[19]
    DIRECTION INPUT ;
    USE SIGNAL ;
    PORT
      LAYER M5 ;
        RECT  6.48 0 6.504 0.084 ;
    END
  END xl0[19]
  PIN xl0[1]
    DIRECTION INPUT ;
    USE SIGNAL ;
    PORT
      LAYER M5 ;
        RECT  2.208 0 2.232 0.084 ;
    END
  END xl0[1]
  PIN xl0[200]
    DIRECTION INPUT ;
    USE SIGNAL ;
    PORT
      LAYER M5 ;
        RECT  49.2 0 49.224 0.084 ;
    END
  END xl0[200]
  PIN xl0[201]
    DIRECTION INPUT ;
    USE SIGNAL ;
    PORT
      LAYER M5 ;
        RECT  49.44 0 49.464 0.084 ;
    END
  END xl0[201]
  PIN xl0[202]
    DIRECTION INPUT ;
    USE SIGNAL ;
    PORT
      LAYER M5 ;
        RECT  49.632 0 49.656 0.084 ;
    END
  END xl0[202]
  PIN xl0[203]
    DIRECTION INPUT ;
    USE SIGNAL ;
    PORT
      LAYER M5 ;
        RECT  49.872 0 49.896 0.084 ;
    END
  END xl0[203]
  PIN xl0[204]
    DIRECTION INPUT ;
    USE SIGNAL ;
    PORT
      LAYER M5 ;
        RECT  50.112 0 50.136 0.084 ;
    END
  END xl0[204]
  PIN xl0[205]
    DIRECTION INPUT ;
    USE SIGNAL ;
    PORT
      LAYER M5 ;
        RECT  50.352 0 50.376 0.084 ;
    END
  END xl0[205]
  PIN xl0[206]
    DIRECTION INPUT ;
    USE SIGNAL ;
    PORT
      LAYER M5 ;
        RECT  50.592 0 50.616 0.084 ;
    END
  END xl0[206]
  PIN xl0[207]
    DIRECTION INPUT ;
    USE SIGNAL ;
    PORT
      LAYER M5 ;
        RECT  50.832 0 50.856 0.084 ;
    END
  END xl0[207]
  PIN xl0[208]
    DIRECTION INPUT ;
    USE SIGNAL ;
    PORT
      LAYER M5 ;
        RECT  51.072 0 51.096 0.084 ;
    END
  END xl0[208]
  PIN xl0[209]
    DIRECTION INPUT ;
    USE SIGNAL ;
    PORT
      LAYER M5 ;
        RECT  51.312 0 51.336 0.084 ;
    END
  END xl0[209]
  PIN xl0[20]
    DIRECTION INPUT ;
    USE SIGNAL ;
    PORT
      LAYER M5 ;
        RECT  6.72 0 6.744 0.084 ;
    END
  END xl0[20]
  PIN xl0[210]
    DIRECTION INPUT ;
    USE SIGNAL ;
    PORT
      LAYER M5 ;
        RECT  51.552 0 51.576 0.084 ;
    END
  END xl0[210]
  PIN xl0[211]
    DIRECTION INPUT ;
    USE SIGNAL ;
    PORT
      LAYER M5 ;
        RECT  51.792 0 51.816 0.084 ;
    END
  END xl0[211]
  PIN xl0[212]
    DIRECTION INPUT ;
    USE SIGNAL ;
    PORT
      LAYER M5 ;
        RECT  52.032 0 52.056 0.084 ;
    END
  END xl0[212]
  PIN xl0[213]
    DIRECTION INPUT ;
    USE SIGNAL ;
    PORT
      LAYER M5 ;
        RECT  52.272 0 52.296 0.084 ;
    END
  END xl0[213]
  PIN xl0[214]
    DIRECTION INPUT ;
    USE SIGNAL ;
    PORT
      LAYER M5 ;
        RECT  52.464 0 52.488 0.084 ;
    END
  END xl0[214]
  PIN xl0[215]
    DIRECTION INPUT ;
    USE SIGNAL ;
    PORT
      LAYER M5 ;
        RECT  52.704 0 52.728 0.084 ;
    END
  END xl0[215]
  PIN xl0[216]
    DIRECTION INPUT ;
    USE SIGNAL ;
    PORT
      LAYER M5 ;
        RECT  52.944 0 52.968 0.084 ;
    END
  END xl0[216]
  PIN xl0[217]
    DIRECTION INPUT ;
    USE SIGNAL ;
    PORT
      LAYER M5 ;
        RECT  53.184 0 53.208 0.084 ;
    END
  END xl0[217]
  PIN xl0[218]
    DIRECTION INPUT ;
    USE SIGNAL ;
    PORT
      LAYER M5 ;
        RECT  53.424 0 53.448 0.084 ;
    END
  END xl0[218]
  PIN xl0[219]
    DIRECTION INPUT ;
    USE SIGNAL ;
    PORT
      LAYER M5 ;
        RECT  53.664 0 53.688 0.084 ;
    END
  END xl0[219]
  PIN xl0[21]
    DIRECTION INPUT ;
    USE SIGNAL ;
    PORT
      LAYER M5 ;
        RECT  6.96 0 6.984 0.084 ;
    END
  END xl0[21]
  PIN xl0[220]
    DIRECTION INPUT ;
    USE SIGNAL ;
    PORT
      LAYER M5 ;
        RECT  53.904 0 53.928 0.084 ;
    END
  END xl0[220]
  PIN xl0[221]
    DIRECTION INPUT ;
    USE SIGNAL ;
    PORT
      LAYER M5 ;
        RECT  54.144 0 54.168 0.084 ;
    END
  END xl0[221]
  PIN xl0[222]
    DIRECTION INPUT ;
    USE SIGNAL ;
    PORT
      LAYER M5 ;
        RECT  54.384 0 54.408 0.084 ;
    END
  END xl0[222]
  PIN xl0[223]
    DIRECTION INPUT ;
    USE SIGNAL ;
    PORT
      LAYER M5 ;
        RECT  54.624 0 54.648 0.084 ;
    END
  END xl0[223]
  PIN xl0[224]
    DIRECTION INPUT ;
    USE SIGNAL ;
    PORT
      LAYER M5 ;
        RECT  54.864 0 54.888 0.084 ;
    END
  END xl0[224]
  PIN xl0[225]
    DIRECTION INPUT ;
    USE SIGNAL ;
    PORT
      LAYER M5 ;
        RECT  55.104 0 55.128 0.084 ;
    END
  END xl0[225]
  PIN xl0[226]
    DIRECTION INPUT ;
    USE SIGNAL ;
    PORT
      LAYER M5 ;
        RECT  55.296 0 55.32 0.084 ;
    END
  END xl0[226]
  PIN xl0[227]
    DIRECTION INPUT ;
    USE SIGNAL ;
    PORT
      LAYER M5 ;
        RECT  55.536 0 55.56 0.084 ;
    END
  END xl0[227]
  PIN xl0[228]
    DIRECTION INPUT ;
    USE SIGNAL ;
    PORT
      LAYER M5 ;
        RECT  55.776 0 55.8 0.084 ;
    END
  END xl0[228]
  PIN xl0[229]
    DIRECTION INPUT ;
    USE SIGNAL ;
    PORT
      LAYER M5 ;
        RECT  56.016 0 56.04 0.084 ;
    END
  END xl0[229]
  PIN xl0[22]
    DIRECTION INPUT ;
    USE SIGNAL ;
    PORT
      LAYER M5 ;
        RECT  7.2 0 7.224 0.084 ;
    END
  END xl0[22]
  PIN xl0[230]
    DIRECTION INPUT ;
    USE SIGNAL ;
    PORT
      LAYER M5 ;
        RECT  56.256 0 56.28 0.084 ;
    END
  END xl0[230]
  PIN xl0[231]
    DIRECTION INPUT ;
    USE SIGNAL ;
    PORT
      LAYER M5 ;
        RECT  56.496 0 56.52 0.084 ;
    END
  END xl0[231]
  PIN xl0[232]
    DIRECTION INPUT ;
    USE SIGNAL ;
    PORT
      LAYER M5 ;
        RECT  56.736 0 56.76 0.084 ;
    END
  END xl0[232]
  PIN xl0[233]
    DIRECTION INPUT ;
    USE SIGNAL ;
    PORT
      LAYER M5 ;
        RECT  56.976 0 57 0.084 ;
    END
  END xl0[233]
  PIN xl0[234]
    DIRECTION INPUT ;
    USE SIGNAL ;
    PORT
      LAYER M5 ;
        RECT  57.216 0 57.24 0.084 ;
    END
  END xl0[234]
  PIN xl0[235]
    DIRECTION INPUT ;
    USE SIGNAL ;
    PORT
      LAYER M5 ;
        RECT  57.456 0 57.48 0.084 ;
    END
  END xl0[235]
  PIN xl0[236]
    DIRECTION INPUT ;
    USE SIGNAL ;
    PORT
      LAYER M5 ;
        RECT  57.696 0 57.72 0.084 ;
    END
  END xl0[236]
  PIN xl0[237]
    DIRECTION INPUT ;
    USE SIGNAL ;
    PORT
      LAYER M5 ;
        RECT  57.936 0 57.96 0.084 ;
    END
  END xl0[237]
  PIN xl0[238]
    DIRECTION INPUT ;
    USE SIGNAL ;
    PORT
      LAYER M5 ;
        RECT  58.128 0 58.152 0.084 ;
    END
  END xl0[238]
  PIN xl0[239]
    DIRECTION INPUT ;
    USE SIGNAL ;
    PORT
      LAYER M5 ;
        RECT  58.368 0 58.392 0.084 ;
    END
  END xl0[239]
  PIN xl0[23]
    DIRECTION INPUT ;
    USE SIGNAL ;
    PORT
      LAYER M5 ;
        RECT  7.392 0 7.416 0.084 ;
    END
  END xl0[23]
  PIN xl0[240]
    DIRECTION INPUT ;
    USE SIGNAL ;
    PORT
      LAYER M5 ;
        RECT  58.608 0 58.632 0.084 ;
    END
  END xl0[240]
  PIN xl0[241]
    DIRECTION INPUT ;
    USE SIGNAL ;
    PORT
      LAYER M5 ;
        RECT  58.848 0 58.872 0.084 ;
    END
  END xl0[241]
  PIN xl0[242]
    DIRECTION INPUT ;
    USE SIGNAL ;
    PORT
      LAYER M5 ;
        RECT  59.088 0 59.112 0.084 ;
    END
  END xl0[242]
  PIN xl0[243]
    DIRECTION INPUT ;
    USE SIGNAL ;
    PORT
      LAYER M5 ;
        RECT  59.328 0 59.352 0.084 ;
    END
  END xl0[243]
  PIN xl0[244]
    DIRECTION INPUT ;
    USE SIGNAL ;
    PORT
      LAYER M5 ;
        RECT  59.568 0 59.592 0.084 ;
    END
  END xl0[244]
  PIN xl0[245]
    DIRECTION INPUT ;
    USE SIGNAL ;
    PORT
      LAYER M5 ;
        RECT  59.808 0 59.832 0.084 ;
    END
  END xl0[245]
  PIN xl0[246]
    DIRECTION INPUT ;
    USE SIGNAL ;
    PORT
      LAYER M5 ;
        RECT  60.048 0 60.072 0.084 ;
    END
  END xl0[246]
  PIN xl0[247]
    DIRECTION INPUT ;
    USE SIGNAL ;
    PORT
      LAYER M5 ;
        RECT  60.288 0 60.312 0.084 ;
    END
  END xl0[247]
  PIN xl0[248]
    DIRECTION INPUT ;
    USE SIGNAL ;
    PORT
      LAYER M5 ;
        RECT  60.528 0 60.552 0.084 ;
    END
  END xl0[248]
  PIN xl0[249]
    DIRECTION INPUT ;
    USE SIGNAL ;
    PORT
      LAYER M5 ;
        RECT  60.768 0 60.792 0.084 ;
    END
  END xl0[249]
  PIN xl0[24]
    DIRECTION INPUT ;
    USE SIGNAL ;
    PORT
      LAYER M5 ;
        RECT  7.632 0 7.656 0.084 ;
    END
  END xl0[24]
  PIN xl0[250]
    DIRECTION INPUT ;
    USE SIGNAL ;
    PORT
      LAYER M5 ;
        RECT  60.96 0 60.984 0.084 ;
    END
  END xl0[250]
  PIN xl0[251]
    DIRECTION INPUT ;
    USE SIGNAL ;
    PORT
      LAYER M5 ;
        RECT  61.2 0 61.224 0.084 ;
    END
  END xl0[251]
  PIN xl0[252]
    DIRECTION INPUT ;
    USE SIGNAL ;
    PORT
      LAYER M5 ;
        RECT  61.44 0 61.464 0.084 ;
    END
  END xl0[252]
  PIN xl0[253]
    DIRECTION INPUT ;
    USE SIGNAL ;
    PORT
      LAYER M5 ;
        RECT  61.68 0 61.704 0.084 ;
    END
  END xl0[253]
  PIN xl0[254]
    DIRECTION INPUT ;
    USE SIGNAL ;
    PORT
      LAYER M5 ;
        RECT  61.92 0 61.944 0.084 ;
    END
  END xl0[254]
  PIN xl0[255]
    DIRECTION INPUT ;
    USE SIGNAL ;
    PORT
      LAYER M5 ;
        RECT  62.16 0 62.184 0.084 ;
    END
  END xl0[255]
  PIN xl0[256]
    DIRECTION INPUT ;
    USE SIGNAL ;
    PORT
      LAYER M5 ;
        RECT  62.4 0 62.424 0.084 ;
    END
  END xl0[256]
  PIN xl0[257]
    DIRECTION INPUT ;
    USE SIGNAL ;
    PORT
      LAYER M5 ;
        RECT  62.64 0 62.664 0.084 ;
    END
  END xl0[257]
  PIN xl0[258]
    DIRECTION INPUT ;
    USE SIGNAL ;
    PORT
      LAYER M5 ;
        RECT  62.88 0 62.904 0.084 ;
    END
  END xl0[258]
  PIN xl0[259]
    DIRECTION INPUT ;
    USE SIGNAL ;
    PORT
      LAYER M5 ;
        RECT  63.12 0 63.144 0.084 ;
    END
  END xl0[259]
  PIN xl0[25]
    DIRECTION INPUT ;
    USE SIGNAL ;
    PORT
      LAYER M5 ;
        RECT  7.872 0 7.896 0.084 ;
    END
  END xl0[25]
  PIN xl0[260]
    DIRECTION INPUT ;
    USE SIGNAL ;
    PORT
      LAYER M5 ;
        RECT  63.36 0 63.384 0.084 ;
    END
  END xl0[260]
  PIN xl0[261]
    DIRECTION INPUT ;
    USE SIGNAL ;
    PORT
      LAYER M5 ;
        RECT  63.6 0 63.624 0.084 ;
    END
  END xl0[261]
  PIN xl0[262]
    DIRECTION INPUT ;
    USE SIGNAL ;
    PORT
      LAYER M5 ;
        RECT  63.792 0 63.816 0.084 ;
    END
  END xl0[262]
  PIN xl0[263]
    DIRECTION INPUT ;
    USE SIGNAL ;
    PORT
      LAYER M5 ;
        RECT  64.032 0 64.056 0.084 ;
    END
  END xl0[263]
  PIN xl0[264]
    DIRECTION INPUT ;
    USE SIGNAL ;
    PORT
      LAYER M5 ;
        RECT  64.272 0 64.296 0.084 ;
    END
  END xl0[264]
  PIN xl0[265]
    DIRECTION INPUT ;
    USE SIGNAL ;
    PORT
      LAYER M5 ;
        RECT  64.512 0 64.536 0.084 ;
    END
  END xl0[265]
  PIN xl0[266]
    DIRECTION INPUT ;
    USE SIGNAL ;
    PORT
      LAYER M5 ;
        RECT  64.752 0 64.776 0.084 ;
    END
  END xl0[266]
  PIN xl0[267]
    DIRECTION INPUT ;
    USE SIGNAL ;
    PORT
      LAYER M5 ;
        RECT  64.992 0 65.016 0.084 ;
    END
  END xl0[267]
  PIN xl0[268]
    DIRECTION INPUT ;
    USE SIGNAL ;
    PORT
      LAYER M5 ;
        RECT  65.232 0 65.256 0.084 ;
    END
  END xl0[268]
  PIN xl0[269]
    DIRECTION INPUT ;
    USE SIGNAL ;
    PORT
      LAYER M5 ;
        RECT  65.472 0 65.496 0.084 ;
    END
  END xl0[269]
  PIN xl0[26]
    DIRECTION INPUT ;
    USE SIGNAL ;
    PORT
      LAYER M5 ;
        RECT  8.112 0 8.136 0.084 ;
    END
  END xl0[26]
  PIN xl0[270]
    DIRECTION INPUT ;
    USE SIGNAL ;
    PORT
      LAYER M5 ;
        RECT  65.712 0 65.736 0.084 ;
    END
  END xl0[270]
  PIN xl0[271]
    DIRECTION INPUT ;
    USE SIGNAL ;
    PORT
      LAYER M5 ;
        RECT  65.952 0 65.976 0.084 ;
    END
  END xl0[271]
  PIN xl0[272]
    DIRECTION INPUT ;
    USE SIGNAL ;
    PORT
      LAYER M5 ;
        RECT  66.192 0 66.216 0.084 ;
    END
  END xl0[272]
  PIN xl0[273]
    DIRECTION INPUT ;
    USE SIGNAL ;
    PORT
      LAYER M5 ;
        RECT  66.432 0 66.456 0.084 ;
    END
  END xl0[273]
  PIN xl0[274]
    DIRECTION INPUT ;
    USE SIGNAL ;
    PORT
      LAYER M5 ;
        RECT  66.624 0 66.648 0.084 ;
    END
  END xl0[274]
  PIN xl0[275]
    DIRECTION INPUT ;
    USE SIGNAL ;
    PORT
      LAYER M5 ;
        RECT  66.864 0 66.888 0.084 ;
    END
  END xl0[275]
  PIN xl0[27]
    DIRECTION INPUT ;
    USE SIGNAL ;
    PORT
      LAYER M5 ;
        RECT  8.352 0 8.376 0.084 ;
    END
  END xl0[27]
  PIN xl0[28]
    DIRECTION INPUT ;
    USE SIGNAL ;
    PORT
      LAYER M5 ;
        RECT  8.592 0 8.616 0.084 ;
    END
  END xl0[28]
  PIN xl0[29]
    DIRECTION INPUT ;
    USE SIGNAL ;
    PORT
      LAYER M5 ;
        RECT  8.832 0 8.856 0.084 ;
    END
  END xl0[29]
  PIN xl0[2]
    DIRECTION INPUT ;
    USE SIGNAL ;
    PORT
      LAYER M5 ;
        RECT  2.448 0 2.472 0.084 ;
    END
  END xl0[2]
  PIN xl0[30]
    DIRECTION INPUT ;
    USE SIGNAL ;
    PORT
      LAYER M5 ;
        RECT  9.072 0 9.096 0.084 ;
    END
  END xl0[30]
  PIN xl0[31]
    DIRECTION INPUT ;
    USE SIGNAL ;
    PORT
      LAYER M5 ;
        RECT  9.312 0 9.336 0.084 ;
    END
  END xl0[31]
  PIN xl0[32]
    DIRECTION INPUT ;
    USE SIGNAL ;
    PORT
      LAYER M5 ;
        RECT  9.552 0 9.576 0.084 ;
    END
  END xl0[32]
  PIN xl0[33]
    DIRECTION INPUT ;
    USE SIGNAL ;
    PORT
      LAYER M5 ;
        RECT  9.792 0 9.816 0.084 ;
    END
  END xl0[33]
  PIN xl0[34]
    DIRECTION INPUT ;
    USE SIGNAL ;
    PORT
      LAYER M5 ;
        RECT  10.032 0 10.056 0.084 ;
    END
  END xl0[34]
  PIN xl0[35]
    DIRECTION INPUT ;
    USE SIGNAL ;
    PORT
      LAYER M5 ;
        RECT  10.224 0 10.248 0.084 ;
    END
  END xl0[35]
  PIN xl0[36]
    DIRECTION INPUT ;
    USE SIGNAL ;
    PORT
      LAYER M5 ;
        RECT  10.464 0 10.488 0.084 ;
    END
  END xl0[36]
  PIN xl0[37]
    DIRECTION INPUT ;
    USE SIGNAL ;
    PORT
      LAYER M5 ;
        RECT  10.704 0 10.728 0.084 ;
    END
  END xl0[37]
  PIN xl0[38]
    DIRECTION INPUT ;
    USE SIGNAL ;
    PORT
      LAYER M5 ;
        RECT  10.944 0 10.968 0.084 ;
    END
  END xl0[38]
  PIN xl0[39]
    DIRECTION INPUT ;
    USE SIGNAL ;
    PORT
      LAYER M5 ;
        RECT  11.184 0 11.208 0.084 ;
    END
  END xl0[39]
  PIN xl0[3]
    DIRECTION INPUT ;
    USE SIGNAL ;
    PORT
      LAYER M5 ;
        RECT  2.688 0 2.712 0.084 ;
    END
  END xl0[3]
  PIN xl0[40]
    DIRECTION INPUT ;
    USE SIGNAL ;
    PORT
      LAYER M5 ;
        RECT  11.424 0 11.448 0.084 ;
    END
  END xl0[40]
  PIN xl0[41]
    DIRECTION INPUT ;
    USE SIGNAL ;
    PORT
      LAYER M5 ;
        RECT  11.664 0 11.688 0.084 ;
    END
  END xl0[41]
  PIN xl0[42]
    DIRECTION INPUT ;
    USE SIGNAL ;
    PORT
      LAYER M5 ;
        RECT  11.904 0 11.928 0.084 ;
    END
  END xl0[42]
  PIN xl0[43]
    DIRECTION INPUT ;
    USE SIGNAL ;
    PORT
      LAYER M5 ;
        RECT  12.144 0 12.168 0.084 ;
    END
  END xl0[43]
  PIN xl0[44]
    DIRECTION INPUT ;
    USE SIGNAL ;
    PORT
      LAYER M5 ;
        RECT  12.384 0 12.408 0.084 ;
    END
  END xl0[44]
  PIN xl0[45]
    DIRECTION INPUT ;
    USE SIGNAL ;
    PORT
      LAYER M5 ;
        RECT  12.624 0 12.648 0.084 ;
    END
  END xl0[45]
  PIN xl0[46]
    DIRECTION INPUT ;
    USE SIGNAL ;
    PORT
      LAYER M5 ;
        RECT  12.864 0 12.888 0.084 ;
    END
  END xl0[46]
  PIN xl0[47]
    DIRECTION INPUT ;
    USE SIGNAL ;
    PORT
      LAYER M5 ;
        RECT  13.056 0 13.08 0.084 ;
    END
  END xl0[47]
  PIN xl0[48]
    DIRECTION INPUT ;
    USE SIGNAL ;
    PORT
      LAYER M5 ;
        RECT  13.296 0 13.32 0.084 ;
    END
  END xl0[48]
  PIN xl0[49]
    DIRECTION INPUT ;
    USE SIGNAL ;
    PORT
      LAYER M5 ;
        RECT  13.536 0 13.56 0.084 ;
    END
  END xl0[49]
  PIN xl0[4]
    DIRECTION INPUT ;
    USE SIGNAL ;
    PORT
      LAYER M5 ;
        RECT  2.928 0 2.952 0.084 ;
    END
  END xl0[4]
  PIN xl0[50]
    DIRECTION INPUT ;
    USE SIGNAL ;
    PORT
      LAYER M5 ;
        RECT  13.776 0 13.8 0.084 ;
    END
  END xl0[50]
  PIN xl0[51]
    DIRECTION INPUT ;
    USE SIGNAL ;
    PORT
      LAYER M5 ;
        RECT  14.016 0 14.04 0.084 ;
    END
  END xl0[51]
  PIN xl0[52]
    DIRECTION INPUT ;
    USE SIGNAL ;
    PORT
      LAYER M5 ;
        RECT  14.256 0 14.28 0.084 ;
    END
  END xl0[52]
  PIN xl0[53]
    DIRECTION INPUT ;
    USE SIGNAL ;
    PORT
      LAYER M5 ;
        RECT  14.496 0 14.52 0.084 ;
    END
  END xl0[53]
  PIN xl0[54]
    DIRECTION INPUT ;
    USE SIGNAL ;
    PORT
      LAYER M5 ;
        RECT  14.736 0 14.76 0.084 ;
    END
  END xl0[54]
  PIN xl0[55]
    DIRECTION INPUT ;
    USE SIGNAL ;
    PORT
      LAYER M5 ;
        RECT  14.976 0 15 0.084 ;
    END
  END xl0[55]
  PIN xl0[56]
    DIRECTION INPUT ;
    USE SIGNAL ;
    PORT
      LAYER M5 ;
        RECT  15.216 0 15.24 0.084 ;
    END
  END xl0[56]
  PIN xl0[57]
    DIRECTION INPUT ;
    USE SIGNAL ;
    PORT
      LAYER M5 ;
        RECT  15.456 0 15.48 0.084 ;
    END
  END xl0[57]
  PIN xl0[58]
    DIRECTION INPUT ;
    USE SIGNAL ;
    PORT
      LAYER M5 ;
        RECT  15.696 0 15.72 0.084 ;
    END
  END xl0[58]
  PIN xl0[59]
    DIRECTION INPUT ;
    USE SIGNAL ;
    PORT
      LAYER M5 ;
        RECT  15.888 0 15.912 0.084 ;
    END
  END xl0[59]
  PIN xl0[5]
    DIRECTION INPUT ;
    USE SIGNAL ;
    PORT
      LAYER M5 ;
        RECT  3.168 0 3.192 0.084 ;
    END
  END xl0[5]
  PIN xl0[60]
    DIRECTION INPUT ;
    USE SIGNAL ;
    PORT
      LAYER M5 ;
        RECT  16.128 0 16.152 0.084 ;
    END
  END xl0[60]
  PIN xl0[61]
    DIRECTION INPUT ;
    USE SIGNAL ;
    PORT
      LAYER M5 ;
        RECT  16.368 0 16.392 0.084 ;
    END
  END xl0[61]
  PIN xl0[62]
    DIRECTION INPUT ;
    USE SIGNAL ;
    PORT
      LAYER M5 ;
        RECT  16.608 0 16.632 0.084 ;
    END
  END xl0[62]
  PIN xl0[63]
    DIRECTION INPUT ;
    USE SIGNAL ;
    PORT
      LAYER M5 ;
        RECT  16.848 0 16.872 0.084 ;
    END
  END xl0[63]
  PIN xl0[64]
    DIRECTION INPUT ;
    USE SIGNAL ;
    PORT
      LAYER M5 ;
        RECT  17.088 0 17.112 0.084 ;
    END
  END xl0[64]
  PIN xl0[65]
    DIRECTION INPUT ;
    USE SIGNAL ;
    PORT
      LAYER M5 ;
        RECT  17.328 0 17.352 0.084 ;
    END
  END xl0[65]
  PIN xl0[66]
    DIRECTION INPUT ;
    USE SIGNAL ;
    PORT
      LAYER M5 ;
        RECT  17.568 0 17.592 0.084 ;
    END
  END xl0[66]
  PIN xl0[67]
    DIRECTION INPUT ;
    USE SIGNAL ;
    PORT
      LAYER M5 ;
        RECT  17.808 0 17.832 0.084 ;
    END
  END xl0[67]
  PIN xl0[68]
    DIRECTION INPUT ;
    USE SIGNAL ;
    PORT
      LAYER M5 ;
        RECT  18.048 0 18.072 0.084 ;
    END
  END xl0[68]
  PIN xl0[69]
    DIRECTION INPUT ;
    USE SIGNAL ;
    PORT
      LAYER M5 ;
        RECT  18.288 0 18.312 0.084 ;
    END
  END xl0[69]
  PIN xl0[6]
    DIRECTION INPUT ;
    USE SIGNAL ;
    PORT
      LAYER M5 ;
        RECT  3.408 0 3.432 0.084 ;
    END
  END xl0[6]
  PIN xl0[70]
    DIRECTION INPUT ;
    USE SIGNAL ;
    PORT
      LAYER M5 ;
        RECT  18.528 0 18.552 0.084 ;
    END
  END xl0[70]
  PIN xl0[71]
    DIRECTION INPUT ;
    USE SIGNAL ;
    PORT
      LAYER M5 ;
        RECT  18.72 0 18.744 0.084 ;
    END
  END xl0[71]
  PIN xl0[72]
    DIRECTION INPUT ;
    USE SIGNAL ;
    PORT
      LAYER M5 ;
        RECT  18.96 0 18.984 0.084 ;
    END
  END xl0[72]
  PIN xl0[73]
    DIRECTION INPUT ;
    USE SIGNAL ;
    PORT
      LAYER M5 ;
        RECT  19.2 0 19.224 0.084 ;
    END
  END xl0[73]
  PIN xl0[74]
    DIRECTION INPUT ;
    USE SIGNAL ;
    PORT
      LAYER M5 ;
        RECT  19.44 0 19.464 0.084 ;
    END
  END xl0[74]
  PIN xl0[75]
    DIRECTION INPUT ;
    USE SIGNAL ;
    PORT
      LAYER M5 ;
        RECT  19.68 0 19.704 0.084 ;
    END
  END xl0[75]
  PIN xl0[76]
    DIRECTION INPUT ;
    USE SIGNAL ;
    PORT
      LAYER M5 ;
        RECT  19.92 0 19.944 0.084 ;
    END
  END xl0[76]
  PIN xl0[77]
    DIRECTION INPUT ;
    USE SIGNAL ;
    PORT
      LAYER M5 ;
        RECT  20.16 0 20.184 0.084 ;
    END
  END xl0[77]
  PIN xl0[78]
    DIRECTION INPUT ;
    USE SIGNAL ;
    PORT
      LAYER M5 ;
        RECT  20.4 0 20.424 0.084 ;
    END
  END xl0[78]
  PIN xl0[79]
    DIRECTION INPUT ;
    USE SIGNAL ;
    PORT
      LAYER M5 ;
        RECT  20.64 0 20.664 0.084 ;
    END
  END xl0[79]
  PIN xl0[7]
    DIRECTION INPUT ;
    USE SIGNAL ;
    PORT
      LAYER M5 ;
        RECT  3.648 0 3.672 0.084 ;
    END
  END xl0[7]
  PIN xl0[80]
    DIRECTION INPUT ;
    USE SIGNAL ;
    PORT
      LAYER M5 ;
        RECT  20.88 0 20.904 0.084 ;
    END
  END xl0[80]
  PIN xl0[81]
    DIRECTION INPUT ;
    USE SIGNAL ;
    PORT
      LAYER M5 ;
        RECT  21.12 0 21.144 0.084 ;
    END
  END xl0[81]
  PIN xl0[82]
    DIRECTION INPUT ;
    USE SIGNAL ;
    PORT
      LAYER M5 ;
        RECT  21.36 0 21.384 0.084 ;
    END
  END xl0[82]
  PIN xl0[83]
    DIRECTION INPUT ;
    USE SIGNAL ;
    PORT
      LAYER M5 ;
        RECT  21.552 0 21.576 0.084 ;
    END
  END xl0[83]
  PIN xl0[84]
    DIRECTION INPUT ;
    USE SIGNAL ;
    PORT
      LAYER M5 ;
        RECT  21.792 0 21.816 0.084 ;
    END
  END xl0[84]
  PIN xl0[85]
    DIRECTION INPUT ;
    USE SIGNAL ;
    PORT
      LAYER M5 ;
        RECT  22.032 0 22.056 0.084 ;
    END
  END xl0[85]
  PIN xl0[86]
    DIRECTION INPUT ;
    USE SIGNAL ;
    PORT
      LAYER M5 ;
        RECT  22.272 0 22.296 0.084 ;
    END
  END xl0[86]
  PIN xl0[87]
    DIRECTION INPUT ;
    USE SIGNAL ;
    PORT
      LAYER M5 ;
        RECT  22.512 0 22.536 0.084 ;
    END
  END xl0[87]
  PIN xl0[88]
    DIRECTION INPUT ;
    USE SIGNAL ;
    PORT
      LAYER M5 ;
        RECT  22.752 0 22.776 0.084 ;
    END
  END xl0[88]
  PIN xl0[89]
    DIRECTION INPUT ;
    USE SIGNAL ;
    PORT
      LAYER M5 ;
        RECT  22.992 0 23.016 0.084 ;
    END
  END xl0[89]
  PIN xl0[8]
    DIRECTION INPUT ;
    USE SIGNAL ;
    PORT
      LAYER M5 ;
        RECT  3.888 0 3.912 0.084 ;
    END
  END xl0[8]
  PIN xl0[90]
    DIRECTION INPUT ;
    USE SIGNAL ;
    PORT
      LAYER M5 ;
        RECT  23.232 0 23.256 0.084 ;
    END
  END xl0[90]
  PIN xl0[91]
    DIRECTION INPUT ;
    USE SIGNAL ;
    PORT
      LAYER M5 ;
        RECT  23.472 0 23.496 0.084 ;
    END
  END xl0[91]
  PIN xl0[92]
    DIRECTION INPUT ;
    USE SIGNAL ;
    PORT
      LAYER M5 ;
        RECT  23.712 0 23.736 0.084 ;
    END
  END xl0[92]
  PIN xl0[93]
    DIRECTION INPUT ;
    USE SIGNAL ;
    PORT
      LAYER M5 ;
        RECT  23.952 0 23.976 0.084 ;
    END
  END xl0[93]
  PIN xl0[94]
    DIRECTION INPUT ;
    USE SIGNAL ;
    PORT
      LAYER M5 ;
        RECT  24.192 0 24.216 0.084 ;
    END
  END xl0[94]
  PIN xl0[95]
    DIRECTION INPUT ;
    USE SIGNAL ;
    PORT
      LAYER M5 ;
        RECT  24.384 0 24.408 0.084 ;
    END
  END xl0[95]
  PIN xl0[96]
    DIRECTION INPUT ;
    USE SIGNAL ;
    PORT
      LAYER M5 ;
        RECT  24.624 0 24.648 0.084 ;
    END
  END xl0[96]
  PIN xl0[97]
    DIRECTION INPUT ;
    USE SIGNAL ;
    PORT
      LAYER M5 ;
        RECT  24.864 0 24.888 0.084 ;
    END
  END xl0[97]
  PIN xl0[98]
    DIRECTION INPUT ;
    USE SIGNAL ;
    PORT
      LAYER M5 ;
        RECT  25.104 0 25.128 0.084 ;
    END
  END xl0[98]
  PIN xl0[99]
    DIRECTION INPUT ;
    USE SIGNAL ;
    PORT
      LAYER M5 ;
        RECT  25.344 0 25.368 0.084 ;
    END
  END xl0[99]
  PIN xl0[9]
    DIRECTION INPUT ;
    USE SIGNAL ;
    PORT
      LAYER M5 ;
        RECT  4.128 0 4.152 0.084 ;
    END
  END xl0[9]
  PIN xl1[0]
    DIRECTION INPUT ;
    USE SIGNAL ;
    PORT
      LAYER M5 ;
        RECT  67.104 0 67.128 0.084 ;
    END
  END xl1[0]
  PIN xl1[100]
    DIRECTION INPUT ;
    USE SIGNAL ;
    PORT
      LAYER M5 ;
        RECT  90.72 0 90.744 0.084 ;
    END
  END xl1[100]
  PIN xl1[101]
    DIRECTION INPUT ;
    USE SIGNAL ;
    PORT
      LAYER M5 ;
        RECT  90.96 0 90.984 0.084 ;
    END
  END xl1[101]
  PIN xl1[102]
    DIRECTION INPUT ;
    USE SIGNAL ;
    PORT
      LAYER M5 ;
        RECT  91.2 0 91.224 0.084 ;
    END
  END xl1[102]
  PIN xl1[103]
    DIRECTION INPUT ;
    USE SIGNAL ;
    PORT
      LAYER M5 ;
        RECT  91.44 0 91.464 0.084 ;
    END
  END xl1[103]
  PIN xl1[104]
    DIRECTION INPUT ;
    USE SIGNAL ;
    PORT
      LAYER M5 ;
        RECT  91.68 0 91.704 0.084 ;
    END
  END xl1[104]
  PIN xl1[105]
    DIRECTION INPUT ;
    USE SIGNAL ;
    PORT
      LAYER M5 ;
        RECT  91.872 0 91.896 0.084 ;
    END
  END xl1[105]
  PIN xl1[106]
    DIRECTION INPUT ;
    USE SIGNAL ;
    PORT
      LAYER M5 ;
        RECT  92.112 0 92.136 0.084 ;
    END
  END xl1[106]
  PIN xl1[107]
    DIRECTION INPUT ;
    USE SIGNAL ;
    PORT
      LAYER M5 ;
        RECT  92.352 0 92.376 0.084 ;
    END
  END xl1[107]
  PIN xl1[108]
    DIRECTION INPUT ;
    USE SIGNAL ;
    PORT
      LAYER M5 ;
        RECT  92.592 0 92.616 0.084 ;
    END
  END xl1[108]
  PIN xl1[109]
    DIRECTION INPUT ;
    USE SIGNAL ;
    PORT
      LAYER M5 ;
        RECT  92.832 0 92.856 0.084 ;
    END
  END xl1[109]
  PIN xl1[10]
    DIRECTION INPUT ;
    USE SIGNAL ;
    PORT
      LAYER M5 ;
        RECT  69.456 0 69.48 0.084 ;
    END
  END xl1[10]
  PIN xl1[110]
    DIRECTION INPUT ;
    USE SIGNAL ;
    PORT
      LAYER M5 ;
        RECT  93.072 0 93.096 0.084 ;
    END
  END xl1[110]
  PIN xl1[111]
    DIRECTION INPUT ;
    USE SIGNAL ;
    PORT
      LAYER M5 ;
        RECT  93.312 0 93.336 0.084 ;
    END
  END xl1[111]
  PIN xl1[112]
    DIRECTION INPUT ;
    USE SIGNAL ;
    PORT
      LAYER M5 ;
        RECT  93.552 0 93.576 0.084 ;
    END
  END xl1[112]
  PIN xl1[113]
    DIRECTION INPUT ;
    USE SIGNAL ;
    PORT
      LAYER M5 ;
        RECT  93.792 0 93.816 0.084 ;
    END
  END xl1[113]
  PIN xl1[114]
    DIRECTION INPUT ;
    USE SIGNAL ;
    PORT
      LAYER M5 ;
        RECT  94.032 0 94.056 0.084 ;
    END
  END xl1[114]
  PIN xl1[115]
    DIRECTION INPUT ;
    USE SIGNAL ;
    PORT
      LAYER M5 ;
        RECT  94.272 0 94.296 0.084 ;
    END
  END xl1[115]
  PIN xl1[116]
    DIRECTION INPUT ;
    USE SIGNAL ;
    PORT
      LAYER M5 ;
        RECT  94.512 0 94.536 0.084 ;
    END
  END xl1[116]
  PIN xl1[117]
    DIRECTION INPUT ;
    USE SIGNAL ;
    PORT
      LAYER M5 ;
        RECT  94.704 0 94.728 0.084 ;
    END
  END xl1[117]
  PIN xl1[118]
    DIRECTION INPUT ;
    USE SIGNAL ;
    PORT
      LAYER M5 ;
        RECT  94.944 0 94.968 0.084 ;
    END
  END xl1[118]
  PIN xl1[119]
    DIRECTION INPUT ;
    USE SIGNAL ;
    PORT
      LAYER M5 ;
        RECT  95.184 0 95.208 0.084 ;
    END
  END xl1[119]
  PIN xl1[11]
    DIRECTION INPUT ;
    USE SIGNAL ;
    PORT
      LAYER M5 ;
        RECT  69.696 0 69.72 0.084 ;
    END
  END xl1[11]
  PIN xl1[120]
    DIRECTION INPUT ;
    USE SIGNAL ;
    PORT
      LAYER M5 ;
        RECT  95.424 0 95.448 0.084 ;
    END
  END xl1[120]
  PIN xl1[121]
    DIRECTION INPUT ;
    USE SIGNAL ;
    PORT
      LAYER M5 ;
        RECT  95.664 0 95.688 0.084 ;
    END
  END xl1[121]
  PIN xl1[122]
    DIRECTION INPUT ;
    USE SIGNAL ;
    PORT
      LAYER M5 ;
        RECT  95.904 0 95.928 0.084 ;
    END
  END xl1[122]
  PIN xl1[123]
    DIRECTION INPUT ;
    USE SIGNAL ;
    PORT
      LAYER M5 ;
        RECT  96.144 0 96.168 0.084 ;
    END
  END xl1[123]
  PIN xl1[124]
    DIRECTION INPUT ;
    USE SIGNAL ;
    PORT
      LAYER M5 ;
        RECT  96.384 0 96.408 0.084 ;
    END
  END xl1[124]
  PIN xl1[125]
    DIRECTION INPUT ;
    USE SIGNAL ;
    PORT
      LAYER M5 ;
        RECT  96.624 0 96.648 0.084 ;
    END
  END xl1[125]
  PIN xl1[126]
    DIRECTION INPUT ;
    USE SIGNAL ;
    PORT
      LAYER M5 ;
        RECT  96.864 0 96.888 0.084 ;
    END
  END xl1[126]
  PIN xl1[127]
    DIRECTION INPUT ;
    USE SIGNAL ;
    PORT
      LAYER M5 ;
        RECT  97.104 0 97.128 0.084 ;
    END
  END xl1[127]
  PIN xl1[128]
    DIRECTION INPUT ;
    USE SIGNAL ;
    PORT
      LAYER M5 ;
        RECT  97.344 0 97.368 0.084 ;
    END
  END xl1[128]
  PIN xl1[129]
    DIRECTION INPUT ;
    USE SIGNAL ;
    PORT
      LAYER M5 ;
        RECT  97.536 0 97.56 0.084 ;
    END
  END xl1[129]
  PIN xl1[12]
    DIRECTION INPUT ;
    USE SIGNAL ;
    PORT
      LAYER M5 ;
        RECT  69.936 0 69.96 0.084 ;
    END
  END xl1[12]
  PIN xl1[130]
    DIRECTION INPUT ;
    USE SIGNAL ;
    PORT
      LAYER M5 ;
        RECT  97.776 0 97.8 0.084 ;
    END
  END xl1[130]
  PIN xl1[131]
    DIRECTION INPUT ;
    USE SIGNAL ;
    PORT
      LAYER M5 ;
        RECT  98.016 0 98.04 0.084 ;
    END
  END xl1[131]
  PIN xl1[132]
    DIRECTION INPUT ;
    USE SIGNAL ;
    PORT
      LAYER M5 ;
        RECT  98.256 0 98.28 0.084 ;
    END
  END xl1[132]
  PIN xl1[133]
    DIRECTION INPUT ;
    USE SIGNAL ;
    PORT
      LAYER M5 ;
        RECT  98.496 0 98.52 0.084 ;
    END
  END xl1[133]
  PIN xl1[134]
    DIRECTION INPUT ;
    USE SIGNAL ;
    PORT
      LAYER M5 ;
        RECT  98.736 0 98.76 0.084 ;
    END
  END xl1[134]
  PIN xl1[135]
    DIRECTION INPUT ;
    USE SIGNAL ;
    PORT
      LAYER M5 ;
        RECT  98.976 0 99 0.084 ;
    END
  END xl1[135]
  PIN xl1[136]
    DIRECTION INPUT ;
    USE SIGNAL ;
    PORT
      LAYER M5 ;
        RECT  99.216 0 99.24 0.084 ;
    END
  END xl1[136]
  PIN xl1[137]
    DIRECTION INPUT ;
    USE SIGNAL ;
    PORT
      LAYER M5 ;
        RECT  99.456 0 99.48 0.084 ;
    END
  END xl1[137]
  PIN xl1[138]
    DIRECTION INPUT ;
    USE SIGNAL ;
    PORT
      LAYER M5 ;
        RECT  99.696 0 99.72 0.084 ;
    END
  END xl1[138]
  PIN xl1[139]
    DIRECTION INPUT ;
    USE SIGNAL ;
    PORT
      LAYER M5 ;
        RECT  99.936 0 99.96 0.084 ;
    END
  END xl1[139]
  PIN xl1[13]
    DIRECTION INPUT ;
    USE SIGNAL ;
    PORT
      LAYER M5 ;
        RECT  70.176 0 70.2 0.084 ;
    END
  END xl1[13]
  PIN xl1[140]
    DIRECTION INPUT ;
    USE SIGNAL ;
    PORT
      LAYER M5 ;
        RECT  100.176 0 100.2 0.084 ;
    END
  END xl1[140]
  PIN xl1[141]
    DIRECTION INPUT ;
    USE SIGNAL ;
    PORT
      LAYER M5 ;
        RECT  100.368 0 100.392 0.084 ;
    END
  END xl1[141]
  PIN xl1[142]
    DIRECTION INPUT ;
    USE SIGNAL ;
    PORT
      LAYER M5 ;
        RECT  100.608 0 100.632 0.084 ;
    END
  END xl1[142]
  PIN xl1[143]
    DIRECTION INPUT ;
    USE SIGNAL ;
    PORT
      LAYER M5 ;
        RECT  100.848 0 100.872 0.084 ;
    END
  END xl1[143]
  PIN xl1[144]
    DIRECTION INPUT ;
    USE SIGNAL ;
    PORT
      LAYER M5 ;
        RECT  101.088 0 101.112 0.084 ;
    END
  END xl1[144]
  PIN xl1[145]
    DIRECTION INPUT ;
    USE SIGNAL ;
    PORT
      LAYER M5 ;
        RECT  101.328 0 101.352 0.084 ;
    END
  END xl1[145]
  PIN xl1[146]
    DIRECTION INPUT ;
    USE SIGNAL ;
    PORT
      LAYER M5 ;
        RECT  101.568 0 101.592 0.084 ;
    END
  END xl1[146]
  PIN xl1[147]
    DIRECTION INPUT ;
    USE SIGNAL ;
    PORT
      LAYER M5 ;
        RECT  101.808 0 101.832 0.084 ;
    END
  END xl1[147]
  PIN xl1[148]
    DIRECTION INPUT ;
    USE SIGNAL ;
    PORT
      LAYER M5 ;
        RECT  102.048 0 102.072 0.084 ;
    END
  END xl1[148]
  PIN xl1[149]
    DIRECTION INPUT ;
    USE SIGNAL ;
    PORT
      LAYER M5 ;
        RECT  102.288 0 102.312 0.084 ;
    END
  END xl1[149]
  PIN xl1[14]
    DIRECTION INPUT ;
    USE SIGNAL ;
    PORT
      LAYER M5 ;
        RECT  70.416 0 70.44 0.084 ;
    END
  END xl1[14]
  PIN xl1[150]
    DIRECTION INPUT ;
    USE SIGNAL ;
    PORT
      LAYER M5 ;
        RECT  102.528 0 102.552 0.084 ;
    END
  END xl1[150]
  PIN xl1[151]
    DIRECTION INPUT ;
    USE SIGNAL ;
    PORT
      LAYER M5 ;
        RECT  102.768 0 102.792 0.084 ;
    END
  END xl1[151]
  PIN xl1[152]
    DIRECTION INPUT ;
    USE SIGNAL ;
    PORT
      LAYER M5 ;
        RECT  103.008 0 103.032 0.084 ;
    END
  END xl1[152]
  PIN xl1[153]
    DIRECTION INPUT ;
    USE SIGNAL ;
    PORT
      LAYER M5 ;
        RECT  103.2 0 103.224 0.084 ;
    END
  END xl1[153]
  PIN xl1[154]
    DIRECTION INPUT ;
    USE SIGNAL ;
    PORT
      LAYER M5 ;
        RECT  103.44 0 103.464 0.084 ;
    END
  END xl1[154]
  PIN xl1[155]
    DIRECTION INPUT ;
    USE SIGNAL ;
    PORT
      LAYER M5 ;
        RECT  103.68 0 103.704 0.084 ;
    END
  END xl1[155]
  PIN xl1[156]
    DIRECTION INPUT ;
    USE SIGNAL ;
    PORT
      LAYER M5 ;
        RECT  103.92 0 103.944 0.084 ;
    END
  END xl1[156]
  PIN xl1[157]
    DIRECTION INPUT ;
    USE SIGNAL ;
    PORT
      LAYER M5 ;
        RECT  104.16 0 104.184 0.084 ;
    END
  END xl1[157]
  PIN xl1[158]
    DIRECTION INPUT ;
    USE SIGNAL ;
    PORT
      LAYER M5 ;
        RECT  104.4 0 104.424 0.084 ;
    END
  END xl1[158]
  PIN xl1[159]
    DIRECTION INPUT ;
    USE SIGNAL ;
    PORT
      LAYER M5 ;
        RECT  104.64 0 104.664 0.084 ;
    END
  END xl1[159]
  PIN xl1[15]
    DIRECTION INPUT ;
    USE SIGNAL ;
    PORT
      LAYER M5 ;
        RECT  70.656 0 70.68 0.084 ;
    END
  END xl1[15]
  PIN xl1[160]
    DIRECTION INPUT ;
    USE SIGNAL ;
    PORT
      LAYER M5 ;
        RECT  104.88 0 104.904 0.084 ;
    END
  END xl1[160]
  PIN xl1[161]
    DIRECTION INPUT ;
    USE SIGNAL ;
    PORT
      LAYER M5 ;
        RECT  105.12 0 105.144 0.084 ;
    END
  END xl1[161]
  PIN xl1[162]
    DIRECTION INPUT ;
    USE SIGNAL ;
    PORT
      LAYER M5 ;
        RECT  105.36 0 105.384 0.084 ;
    END
  END xl1[162]
  PIN xl1[163]
    DIRECTION INPUT ;
    USE SIGNAL ;
    PORT
      LAYER M5 ;
        RECT  105.6 0 105.624 0.084 ;
    END
  END xl1[163]
  PIN xl1[164]
    DIRECTION INPUT ;
    USE SIGNAL ;
    PORT
      LAYER M5 ;
        RECT  105.84 0 105.864 0.084 ;
    END
  END xl1[164]
  PIN xl1[165]
    DIRECTION INPUT ;
    USE SIGNAL ;
    PORT
      LAYER M5 ;
        RECT  106.032 0 106.056 0.084 ;
    END
  END xl1[165]
  PIN xl1[166]
    DIRECTION INPUT ;
    USE SIGNAL ;
    PORT
      LAYER M5 ;
        RECT  106.272 0 106.296 0.084 ;
    END
  END xl1[166]
  PIN xl1[167]
    DIRECTION INPUT ;
    USE SIGNAL ;
    PORT
      LAYER M5 ;
        RECT  106.512 0 106.536 0.084 ;
    END
  END xl1[167]
  PIN xl1[168]
    DIRECTION INPUT ;
    USE SIGNAL ;
    PORT
      LAYER M5 ;
        RECT  106.752 0 106.776 0.084 ;
    END
  END xl1[168]
  PIN xl1[169]
    DIRECTION INPUT ;
    USE SIGNAL ;
    PORT
      LAYER M5 ;
        RECT  106.992 0 107.016 0.084 ;
    END
  END xl1[169]
  PIN xl1[16]
    DIRECTION INPUT ;
    USE SIGNAL ;
    PORT
      LAYER M5 ;
        RECT  70.896 0 70.92 0.084 ;
    END
  END xl1[16]
  PIN xl1[170]
    DIRECTION INPUT ;
    USE SIGNAL ;
    PORT
      LAYER M5 ;
        RECT  107.232 0 107.256 0.084 ;
    END
  END xl1[170]
  PIN xl1[171]
    DIRECTION INPUT ;
    USE SIGNAL ;
    PORT
      LAYER M5 ;
        RECT  107.472 0 107.496 0.084 ;
    END
  END xl1[171]
  PIN xl1[172]
    DIRECTION INPUT ;
    USE SIGNAL ;
    PORT
      LAYER M5 ;
        RECT  107.712 0 107.736 0.084 ;
    END
  END xl1[172]
  PIN xl1[173]
    DIRECTION INPUT ;
    USE SIGNAL ;
    PORT
      LAYER M5 ;
        RECT  107.952 0 107.976 0.084 ;
    END
  END xl1[173]
  PIN xl1[174]
    DIRECTION INPUT ;
    USE SIGNAL ;
    PORT
      LAYER M5 ;
        RECT  108.192 0 108.216 0.084 ;
    END
  END xl1[174]
  PIN xl1[175]
    DIRECTION INPUT ;
    USE SIGNAL ;
    PORT
      LAYER M5 ;
        RECT  108.432 0 108.456 0.084 ;
    END
  END xl1[175]
  PIN xl1[176]
    DIRECTION INPUT ;
    USE SIGNAL ;
    PORT
      LAYER M5 ;
        RECT  108.672 0 108.696 0.084 ;
    END
  END xl1[176]
  PIN xl1[177]
    DIRECTION INPUT ;
    USE SIGNAL ;
    PORT
      LAYER M5 ;
        RECT  108.864 0 108.888 0.084 ;
    END
  END xl1[177]
  PIN xl1[178]
    DIRECTION INPUT ;
    USE SIGNAL ;
    PORT
      LAYER M5 ;
        RECT  109.104 0 109.128 0.084 ;
    END
  END xl1[178]
  PIN xl1[179]
    DIRECTION INPUT ;
    USE SIGNAL ;
    PORT
      LAYER M5 ;
        RECT  109.344 0 109.368 0.084 ;
    END
  END xl1[179]
  PIN xl1[17]
    DIRECTION INPUT ;
    USE SIGNAL ;
    PORT
      LAYER M5 ;
        RECT  71.136 0 71.16 0.084 ;
    END
  END xl1[17]
  PIN xl1[180]
    DIRECTION INPUT ;
    USE SIGNAL ;
    PORT
      LAYER M5 ;
        RECT  109.584 0 109.608 0.084 ;
    END
  END xl1[180]
  PIN xl1[181]
    DIRECTION INPUT ;
    USE SIGNAL ;
    PORT
      LAYER M5 ;
        RECT  109.824 0 109.848 0.084 ;
    END
  END xl1[181]
  PIN xl1[182]
    DIRECTION INPUT ;
    USE SIGNAL ;
    PORT
      LAYER M5 ;
        RECT  110.064 0 110.088 0.084 ;
    END
  END xl1[182]
  PIN xl1[183]
    DIRECTION INPUT ;
    USE SIGNAL ;
    PORT
      LAYER M5 ;
        RECT  110.304 0 110.328 0.084 ;
    END
  END xl1[183]
  PIN xl1[184]
    DIRECTION INPUT ;
    USE SIGNAL ;
    PORT
      LAYER M5 ;
        RECT  110.544 0 110.568 0.084 ;
    END
  END xl1[184]
  PIN xl1[185]
    DIRECTION INPUT ;
    USE SIGNAL ;
    PORT
      LAYER M5 ;
        RECT  110.784 0 110.808 0.084 ;
    END
  END xl1[185]
  PIN xl1[186]
    DIRECTION INPUT ;
    USE SIGNAL ;
    PORT
      LAYER M5 ;
        RECT  111.024 0 111.048 0.084 ;
    END
  END xl1[186]
  PIN xl1[187]
    DIRECTION INPUT ;
    USE SIGNAL ;
    PORT
      LAYER M5 ;
        RECT  111.264 0 111.288 0.084 ;
    END
  END xl1[187]
  PIN xl1[188]
    DIRECTION INPUT ;
    USE SIGNAL ;
    PORT
      LAYER M5 ;
        RECT  111.504 0 111.528 0.084 ;
    END
  END xl1[188]
  PIN xl1[189]
    DIRECTION INPUT ;
    USE SIGNAL ;
    PORT
      LAYER M5 ;
        RECT  111.696 0 111.72 0.084 ;
    END
  END xl1[189]
  PIN xl1[18]
    DIRECTION INPUT ;
    USE SIGNAL ;
    PORT
      LAYER M5 ;
        RECT  71.376 0 71.4 0.084 ;
    END
  END xl1[18]
  PIN xl1[190]
    DIRECTION INPUT ;
    USE SIGNAL ;
    PORT
      LAYER M5 ;
        RECT  111.936 0 111.96 0.084 ;
    END
  END xl1[190]
  PIN xl1[191]
    DIRECTION INPUT ;
    USE SIGNAL ;
    PORT
      LAYER M5 ;
        RECT  112.176 0 112.2 0.084 ;
    END
  END xl1[191]
  PIN xl1[192]
    DIRECTION INPUT ;
    USE SIGNAL ;
    PORT
      LAYER M5 ;
        RECT  112.416 0 112.44 0.084 ;
    END
  END xl1[192]
  PIN xl1[193]
    DIRECTION INPUT ;
    USE SIGNAL ;
    PORT
      LAYER M5 ;
        RECT  112.656 0 112.68 0.084 ;
    END
  END xl1[193]
  PIN xl1[194]
    DIRECTION INPUT ;
    USE SIGNAL ;
    PORT
      LAYER M5 ;
        RECT  112.896 0 112.92 0.084 ;
    END
  END xl1[194]
  PIN xl1[195]
    DIRECTION INPUT ;
    USE SIGNAL ;
    PORT
      LAYER M5 ;
        RECT  113.136 0 113.16 0.084 ;
    END
  END xl1[195]
  PIN xl1[196]
    DIRECTION INPUT ;
    USE SIGNAL ;
    PORT
      LAYER M5 ;
        RECT  113.376 0 113.4 0.084 ;
    END
  END xl1[196]
  PIN xl1[197]
    DIRECTION INPUT ;
    USE SIGNAL ;
    PORT
      LAYER M5 ;
        RECT  113.616 0 113.64 0.084 ;
    END
  END xl1[197]
  PIN xl1[198]
    DIRECTION INPUT ;
    USE SIGNAL ;
    PORT
      LAYER M5 ;
        RECT  113.856 0 113.88 0.084 ;
    END
  END xl1[198]
  PIN xl1[199]
    DIRECTION INPUT ;
    USE SIGNAL ;
    PORT
      LAYER M5 ;
        RECT  114.096 0 114.12 0.084 ;
    END
  END xl1[199]
  PIN xl1[19]
    DIRECTION INPUT ;
    USE SIGNAL ;
    PORT
      LAYER M5 ;
        RECT  71.616 0 71.64 0.084 ;
    END
  END xl1[19]
  PIN xl1[1]
    DIRECTION INPUT ;
    USE SIGNAL ;
    PORT
      LAYER M5 ;
        RECT  67.344 0 67.368 0.084 ;
    END
  END xl1[1]
  PIN xl1[200]
    DIRECTION INPUT ;
    USE SIGNAL ;
    PORT
      LAYER M5 ;
        RECT  114.336 0 114.36 0.084 ;
    END
  END xl1[200]
  PIN xl1[201]
    DIRECTION INPUT ;
    USE SIGNAL ;
    PORT
      LAYER M5 ;
        RECT  114.528 0 114.552 0.084 ;
    END
  END xl1[201]
  PIN xl1[202]
    DIRECTION INPUT ;
    USE SIGNAL ;
    PORT
      LAYER M5 ;
        RECT  114.768 0 114.792 0.084 ;
    END
  END xl1[202]
  PIN xl1[203]
    DIRECTION INPUT ;
    USE SIGNAL ;
    PORT
      LAYER M5 ;
        RECT  115.008 0 115.032 0.084 ;
    END
  END xl1[203]
  PIN xl1[204]
    DIRECTION INPUT ;
    USE SIGNAL ;
    PORT
      LAYER M5 ;
        RECT  115.248 0 115.272 0.084 ;
    END
  END xl1[204]
  PIN xl1[205]
    DIRECTION INPUT ;
    USE SIGNAL ;
    PORT
      LAYER M5 ;
        RECT  115.488 0 115.512 0.084 ;
    END
  END xl1[205]
  PIN xl1[206]
    DIRECTION INPUT ;
    USE SIGNAL ;
    PORT
      LAYER M5 ;
        RECT  115.728 0 115.752 0.084 ;
    END
  END xl1[206]
  PIN xl1[207]
    DIRECTION INPUT ;
    USE SIGNAL ;
    PORT
      LAYER M5 ;
        RECT  115.968 0 115.992 0.084 ;
    END
  END xl1[207]
  PIN xl1[208]
    DIRECTION INPUT ;
    USE SIGNAL ;
    PORT
      LAYER M5 ;
        RECT  116.208 0 116.232 0.084 ;
    END
  END xl1[208]
  PIN xl1[209]
    DIRECTION INPUT ;
    USE SIGNAL ;
    PORT
      LAYER M5 ;
        RECT  116.448 0 116.472 0.084 ;
    END
  END xl1[209]
  PIN xl1[20]
    DIRECTION INPUT ;
    USE SIGNAL ;
    PORT
      LAYER M5 ;
        RECT  71.856 0 71.88 0.084 ;
    END
  END xl1[20]
  PIN xl1[210]
    DIRECTION INPUT ;
    USE SIGNAL ;
    PORT
      LAYER M5 ;
        RECT  116.688 0 116.712 0.084 ;
    END
  END xl1[210]
  PIN xl1[211]
    DIRECTION INPUT ;
    USE SIGNAL ;
    PORT
      LAYER M5 ;
        RECT  116.928 0 116.952 0.084 ;
    END
  END xl1[211]
  PIN xl1[212]
    DIRECTION INPUT ;
    USE SIGNAL ;
    PORT
      LAYER M5 ;
        RECT  117.168 0 117.192 0.084 ;
    END
  END xl1[212]
  PIN xl1[213]
    DIRECTION INPUT ;
    USE SIGNAL ;
    PORT
      LAYER M5 ;
        RECT  117.36 0 117.384 0.084 ;
    END
  END xl1[213]
  PIN xl1[214]
    DIRECTION INPUT ;
    USE SIGNAL ;
    PORT
      LAYER M5 ;
        RECT  117.6 0 117.624 0.084 ;
    END
  END xl1[214]
  PIN xl1[215]
    DIRECTION INPUT ;
    USE SIGNAL ;
    PORT
      LAYER M5 ;
        RECT  117.84 0 117.864 0.084 ;
    END
  END xl1[215]
  PIN xl1[216]
    DIRECTION INPUT ;
    USE SIGNAL ;
    PORT
      LAYER M5 ;
        RECT  118.08 0 118.104 0.084 ;
    END
  END xl1[216]
  PIN xl1[217]
    DIRECTION INPUT ;
    USE SIGNAL ;
    PORT
      LAYER M5 ;
        RECT  118.32 0 118.344 0.084 ;
    END
  END xl1[217]
  PIN xl1[218]
    DIRECTION INPUT ;
    USE SIGNAL ;
    PORT
      LAYER M5 ;
        RECT  118.56 0 118.584 0.084 ;
    END
  END xl1[218]
  PIN xl1[219]
    DIRECTION INPUT ;
    USE SIGNAL ;
    PORT
      LAYER M5 ;
        RECT  118.8 0 118.824 0.084 ;
    END
  END xl1[219]
  PIN xl1[21]
    DIRECTION INPUT ;
    USE SIGNAL ;
    PORT
      LAYER M5 ;
        RECT  72.096 0 72.12 0.084 ;
    END
  END xl1[21]
  PIN xl1[220]
    DIRECTION INPUT ;
    USE SIGNAL ;
    PORT
      LAYER M5 ;
        RECT  119.04 0 119.064 0.084 ;
    END
  END xl1[220]
  PIN xl1[221]
    DIRECTION INPUT ;
    USE SIGNAL ;
    PORT
      LAYER M5 ;
        RECT  119.28 0 119.304 0.084 ;
    END
  END xl1[221]
  PIN xl1[222]
    DIRECTION INPUT ;
    USE SIGNAL ;
    PORT
      LAYER M5 ;
        RECT  119.52 0 119.544 0.084 ;
    END
  END xl1[222]
  PIN xl1[223]
    DIRECTION INPUT ;
    USE SIGNAL ;
    PORT
      LAYER M5 ;
        RECT  119.76 0 119.784 0.084 ;
    END
  END xl1[223]
  PIN xl1[224]
    DIRECTION INPUT ;
    USE SIGNAL ;
    PORT
      LAYER M5 ;
        RECT  120 0 120.024 0.084 ;
    END
  END xl1[224]
  PIN xl1[225]
    DIRECTION INPUT ;
    USE SIGNAL ;
    PORT
      LAYER M5 ;
        RECT  120.192 0 120.216 0.084 ;
    END
  END xl1[225]
  PIN xl1[226]
    DIRECTION INPUT ;
    USE SIGNAL ;
    PORT
      LAYER M5 ;
        RECT  120.432 0 120.456 0.084 ;
    END
  END xl1[226]
  PIN xl1[227]
    DIRECTION INPUT ;
    USE SIGNAL ;
    PORT
      LAYER M5 ;
        RECT  120.672 0 120.696 0.084 ;
    END
  END xl1[227]
  PIN xl1[228]
    DIRECTION INPUT ;
    USE SIGNAL ;
    PORT
      LAYER M5 ;
        RECT  120.912 0 120.936 0.084 ;
    END
  END xl1[228]
  PIN xl1[229]
    DIRECTION INPUT ;
    USE SIGNAL ;
    PORT
      LAYER M5 ;
        RECT  121.152 0 121.176 0.084 ;
    END
  END xl1[229]
  PIN xl1[22]
    DIRECTION INPUT ;
    USE SIGNAL ;
    PORT
      LAYER M5 ;
        RECT  72.288 0 72.312 0.084 ;
    END
  END xl1[22]
  PIN xl1[230]
    DIRECTION INPUT ;
    USE SIGNAL ;
    PORT
      LAYER M5 ;
        RECT  121.392 0 121.416 0.084 ;
    END
  END xl1[230]
  PIN xl1[231]
    DIRECTION INPUT ;
    USE SIGNAL ;
    PORT
      LAYER M5 ;
        RECT  121.632 0 121.656 0.084 ;
    END
  END xl1[231]
  PIN xl1[232]
    DIRECTION INPUT ;
    USE SIGNAL ;
    PORT
      LAYER M5 ;
        RECT  121.872 0 121.896 0.084 ;
    END
  END xl1[232]
  PIN xl1[233]
    DIRECTION INPUT ;
    USE SIGNAL ;
    PORT
      LAYER M5 ;
        RECT  122.112 0 122.136 0.084 ;
    END
  END xl1[233]
  PIN xl1[234]
    DIRECTION INPUT ;
    USE SIGNAL ;
    PORT
      LAYER M5 ;
        RECT  122.352 0 122.376 0.084 ;
    END
  END xl1[234]
  PIN xl1[235]
    DIRECTION INPUT ;
    USE SIGNAL ;
    PORT
      LAYER M5 ;
        RECT  122.592 0 122.616 0.084 ;
    END
  END xl1[235]
  PIN xl1[236]
    DIRECTION INPUT ;
    USE SIGNAL ;
    PORT
      LAYER M5 ;
        RECT  122.784 0 122.808 0.084 ;
    END
  END xl1[236]
  PIN xl1[237]
    DIRECTION INPUT ;
    USE SIGNAL ;
    PORT
      LAYER M5 ;
        RECT  123.024 0 123.048 0.084 ;
    END
  END xl1[237]
  PIN xl1[238]
    DIRECTION INPUT ;
    USE SIGNAL ;
    PORT
      LAYER M5 ;
        RECT  123.264 0 123.288 0.084 ;
    END
  END xl1[238]
  PIN xl1[239]
    DIRECTION INPUT ;
    USE SIGNAL ;
    PORT
      LAYER M5 ;
        RECT  123.504 0 123.528 0.084 ;
    END
  END xl1[239]
  PIN xl1[23]
    DIRECTION INPUT ;
    USE SIGNAL ;
    PORT
      LAYER M5 ;
        RECT  72.528 0 72.552 0.084 ;
    END
  END xl1[23]
  PIN xl1[240]
    DIRECTION INPUT ;
    USE SIGNAL ;
    PORT
      LAYER M5 ;
        RECT  123.744 0 123.768 0.084 ;
    END
  END xl1[240]
  PIN xl1[241]
    DIRECTION INPUT ;
    USE SIGNAL ;
    PORT
      LAYER M5 ;
        RECT  123.984 0 124.008 0.084 ;
    END
  END xl1[241]
  PIN xl1[242]
    DIRECTION INPUT ;
    USE SIGNAL ;
    PORT
      LAYER M5 ;
        RECT  124.224 0 124.248 0.084 ;
    END
  END xl1[242]
  PIN xl1[243]
    DIRECTION INPUT ;
    USE SIGNAL ;
    PORT
      LAYER M5 ;
        RECT  124.464 0 124.488 0.084 ;
    END
  END xl1[243]
  PIN xl1[244]
    DIRECTION INPUT ;
    USE SIGNAL ;
    PORT
      LAYER M5 ;
        RECT  124.704 0 124.728 0.084 ;
    END
  END xl1[244]
  PIN xl1[245]
    DIRECTION INPUT ;
    USE SIGNAL ;
    PORT
      LAYER M5 ;
        RECT  124.944 0 124.968 0.084 ;
    END
  END xl1[245]
  PIN xl1[246]
    DIRECTION INPUT ;
    USE SIGNAL ;
    PORT
      LAYER M5 ;
        RECT  125.184 0 125.208 0.084 ;
    END
  END xl1[246]
  PIN xl1[247]
    DIRECTION INPUT ;
    USE SIGNAL ;
    PORT
      LAYER M5 ;
        RECT  125.424 0 125.448 0.084 ;
    END
  END xl1[247]
  PIN xl1[248]
    DIRECTION INPUT ;
    USE SIGNAL ;
    PORT
      LAYER M5 ;
        RECT  125.616 0 125.64 0.084 ;
    END
  END xl1[248]
  PIN xl1[249]
    DIRECTION INPUT ;
    USE SIGNAL ;
    PORT
      LAYER M5 ;
        RECT  125.856 0 125.88 0.084 ;
    END
  END xl1[249]
  PIN xl1[24]
    DIRECTION INPUT ;
    USE SIGNAL ;
    PORT
      LAYER M5 ;
        RECT  72.768 0 72.792 0.084 ;
    END
  END xl1[24]
  PIN xl1[250]
    DIRECTION INPUT ;
    USE SIGNAL ;
    PORT
      LAYER M5 ;
        RECT  126.096 0 126.12 0.084 ;
    END
  END xl1[250]
  PIN xl1[251]
    DIRECTION INPUT ;
    USE SIGNAL ;
    PORT
      LAYER M5 ;
        RECT  126.336 0 126.36 0.084 ;
    END
  END xl1[251]
  PIN xl1[252]
    DIRECTION INPUT ;
    USE SIGNAL ;
    PORT
      LAYER M5 ;
        RECT  126.576 0 126.6 0.084 ;
    END
  END xl1[252]
  PIN xl1[253]
    DIRECTION INPUT ;
    USE SIGNAL ;
    PORT
      LAYER M5 ;
        RECT  126.816 0 126.84 0.084 ;
    END
  END xl1[253]
  PIN xl1[254]
    DIRECTION INPUT ;
    USE SIGNAL ;
    PORT
      LAYER M5 ;
        RECT  127.056 0 127.08 0.084 ;
    END
  END xl1[254]
  PIN xl1[255]
    DIRECTION INPUT ;
    USE SIGNAL ;
    PORT
      LAYER M5 ;
        RECT  127.296 0 127.32 0.084 ;
    END
  END xl1[255]
  PIN xl1[256]
    DIRECTION INPUT ;
    USE SIGNAL ;
    PORT
      LAYER M5 ;
        RECT  127.536 0 127.56 0.084 ;
    END
  END xl1[256]
  PIN xl1[257]
    DIRECTION INPUT ;
    USE SIGNAL ;
    PORT
      LAYER M5 ;
        RECT  127.776 0 127.8 0.084 ;
    END
  END xl1[257]
  PIN xl1[258]
    DIRECTION INPUT ;
    USE SIGNAL ;
    PORT
      LAYER M5 ;
        RECT  128.016 0 128.04 0.084 ;
    END
  END xl1[258]
  PIN xl1[259]
    DIRECTION INPUT ;
    USE SIGNAL ;
    PORT
      LAYER M5 ;
        RECT  128.256 0 128.28 0.084 ;
    END
  END xl1[259]
  PIN xl1[25]
    DIRECTION INPUT ;
    USE SIGNAL ;
    PORT
      LAYER M5 ;
        RECT  73.008 0 73.032 0.084 ;
    END
  END xl1[25]
  PIN xl1[260]
    DIRECTION INPUT ;
    USE SIGNAL ;
    PORT
      LAYER M5 ;
        RECT  128.448 0 128.472 0.084 ;
    END
  END xl1[260]
  PIN xl1[261]
    DIRECTION INPUT ;
    USE SIGNAL ;
    PORT
      LAYER M5 ;
        RECT  128.688 0 128.712 0.084 ;
    END
  END xl1[261]
  PIN xl1[262]
    DIRECTION INPUT ;
    USE SIGNAL ;
    PORT
      LAYER M5 ;
        RECT  128.928 0 128.952 0.084 ;
    END
  END xl1[262]
  PIN xl1[263]
    DIRECTION INPUT ;
    USE SIGNAL ;
    PORT
      LAYER M5 ;
        RECT  129.168 0 129.192 0.084 ;
    END
  END xl1[263]
  PIN xl1[264]
    DIRECTION INPUT ;
    USE SIGNAL ;
    PORT
      LAYER M5 ;
        RECT  129.408 0 129.432 0.084 ;
    END
  END xl1[264]
  PIN xl1[265]
    DIRECTION INPUT ;
    USE SIGNAL ;
    PORT
      LAYER M5 ;
        RECT  129.648 0 129.672 0.084 ;
    END
  END xl1[265]
  PIN xl1[266]
    DIRECTION INPUT ;
    USE SIGNAL ;
    PORT
      LAYER M5 ;
        RECT  129.888 0 129.912 0.084 ;
    END
  END xl1[266]
  PIN xl1[267]
    DIRECTION INPUT ;
    USE SIGNAL ;
    PORT
      LAYER M5 ;
        RECT  130.128 0 130.152 0.084 ;
    END
  END xl1[267]
  PIN xl1[268]
    DIRECTION INPUT ;
    USE SIGNAL ;
    PORT
      LAYER M5 ;
        RECT  130.368 0 130.392 0.084 ;
    END
  END xl1[268]
  PIN xl1[269]
    DIRECTION INPUT ;
    USE SIGNAL ;
    PORT
      LAYER M5 ;
        RECT  130.608 0 130.632 0.084 ;
    END
  END xl1[269]
  PIN xl1[26]
    DIRECTION INPUT ;
    USE SIGNAL ;
    PORT
      LAYER M5 ;
        RECT  73.248 0 73.272 0.084 ;
    END
  END xl1[26]
  PIN xl1[270]
    DIRECTION INPUT ;
    USE SIGNAL ;
    PORT
      LAYER M5 ;
        RECT  130.848 0 130.872 0.084 ;
    END
  END xl1[270]
  PIN xl1[271]
    DIRECTION INPUT ;
    USE SIGNAL ;
    PORT
      LAYER M5 ;
        RECT  131.088 0 131.112 0.084 ;
    END
  END xl1[271]
  PIN xl1[272]
    DIRECTION INPUT ;
    USE SIGNAL ;
    PORT
      LAYER M5 ;
        RECT  131.28 0 131.304 0.084 ;
    END
  END xl1[272]
  PIN xl1[273]
    DIRECTION INPUT ;
    USE SIGNAL ;
    PORT
      LAYER M5 ;
        RECT  131.52 0 131.544 0.084 ;
    END
  END xl1[273]
  PIN xl1[274]
    DIRECTION INPUT ;
    USE SIGNAL ;
    PORT
      LAYER M5 ;
        RECT  131.76 0 131.784 0.084 ;
    END
  END xl1[274]
  PIN xl1[275]
    DIRECTION INPUT ;
    USE SIGNAL ;
    PORT
      LAYER M5 ;
        RECT  132 0 132.024 0.084 ;
    END
  END xl1[275]
  PIN xl1[27]
    DIRECTION INPUT ;
    USE SIGNAL ;
    PORT
      LAYER M5 ;
        RECT  73.488 0 73.512 0.084 ;
    END
  END xl1[27]
  PIN xl1[28]
    DIRECTION INPUT ;
    USE SIGNAL ;
    PORT
      LAYER M5 ;
        RECT  73.728 0 73.752 0.084 ;
    END
  END xl1[28]
  PIN xl1[29]
    DIRECTION INPUT ;
    USE SIGNAL ;
    PORT
      LAYER M5 ;
        RECT  73.968 0 73.992 0.084 ;
    END
  END xl1[29]
  PIN xl1[2]
    DIRECTION INPUT ;
    USE SIGNAL ;
    PORT
      LAYER M5 ;
        RECT  67.584 0 67.608 0.084 ;
    END
  END xl1[2]
  PIN xl1[30]
    DIRECTION INPUT ;
    USE SIGNAL ;
    PORT
      LAYER M5 ;
        RECT  74.208 0 74.232 0.084 ;
    END
  END xl1[30]
  PIN xl1[31]
    DIRECTION INPUT ;
    USE SIGNAL ;
    PORT
      LAYER M5 ;
        RECT  74.448 0 74.472 0.084 ;
    END
  END xl1[31]
  PIN xl1[32]
    DIRECTION INPUT ;
    USE SIGNAL ;
    PORT
      LAYER M5 ;
        RECT  74.688 0 74.712 0.084 ;
    END
  END xl1[32]
  PIN xl1[33]
    DIRECTION INPUT ;
    USE SIGNAL ;
    PORT
      LAYER M5 ;
        RECT  74.928 0 74.952 0.084 ;
    END
  END xl1[33]
  PIN xl1[34]
    DIRECTION INPUT ;
    USE SIGNAL ;
    PORT
      LAYER M5 ;
        RECT  75.12 0 75.144 0.084 ;
    END
  END xl1[34]
  PIN xl1[35]
    DIRECTION INPUT ;
    USE SIGNAL ;
    PORT
      LAYER M5 ;
        RECT  75.36 0 75.384 0.084 ;
    END
  END xl1[35]
  PIN xl1[36]
    DIRECTION INPUT ;
    USE SIGNAL ;
    PORT
      LAYER M5 ;
        RECT  75.6 0 75.624 0.084 ;
    END
  END xl1[36]
  PIN xl1[37]
    DIRECTION INPUT ;
    USE SIGNAL ;
    PORT
      LAYER M5 ;
        RECT  75.84 0 75.864 0.084 ;
    END
  END xl1[37]
  PIN xl1[38]
    DIRECTION INPUT ;
    USE SIGNAL ;
    PORT
      LAYER M5 ;
        RECT  76.08 0 76.104 0.084 ;
    END
  END xl1[38]
  PIN xl1[39]
    DIRECTION INPUT ;
    USE SIGNAL ;
    PORT
      LAYER M5 ;
        RECT  76.32 0 76.344 0.084 ;
    END
  END xl1[39]
  PIN xl1[3]
    DIRECTION INPUT ;
    USE SIGNAL ;
    PORT
      LAYER M5 ;
        RECT  67.824 0 67.848 0.084 ;
    END
  END xl1[3]
  PIN xl1[40]
    DIRECTION INPUT ;
    USE SIGNAL ;
    PORT
      LAYER M5 ;
        RECT  76.56 0 76.584 0.084 ;
    END
  END xl1[40]
  PIN xl1[41]
    DIRECTION INPUT ;
    USE SIGNAL ;
    PORT
      LAYER M5 ;
        RECT  76.8 0 76.824 0.084 ;
    END
  END xl1[41]
  PIN xl1[42]
    DIRECTION INPUT ;
    USE SIGNAL ;
    PORT
      LAYER M5 ;
        RECT  77.04 0 77.064 0.084 ;
    END
  END xl1[42]
  PIN xl1[43]
    DIRECTION INPUT ;
    USE SIGNAL ;
    PORT
      LAYER M5 ;
        RECT  77.28 0 77.304 0.084 ;
    END
  END xl1[43]
  PIN xl1[44]
    DIRECTION INPUT ;
    USE SIGNAL ;
    PORT
      LAYER M5 ;
        RECT  77.52 0 77.544 0.084 ;
    END
  END xl1[44]
  PIN xl1[45]
    DIRECTION INPUT ;
    USE SIGNAL ;
    PORT
      LAYER M5 ;
        RECT  77.76 0 77.784 0.084 ;
    END
  END xl1[45]
  PIN xl1[46]
    DIRECTION INPUT ;
    USE SIGNAL ;
    PORT
      LAYER M5 ;
        RECT  77.952 0 77.976 0.084 ;
    END
  END xl1[46]
  PIN xl1[47]
    DIRECTION INPUT ;
    USE SIGNAL ;
    PORT
      LAYER M5 ;
        RECT  78.192 0 78.216 0.084 ;
    END
  END xl1[47]
  PIN xl1[48]
    DIRECTION INPUT ;
    USE SIGNAL ;
    PORT
      LAYER M5 ;
        RECT  78.432 0 78.456 0.084 ;
    END
  END xl1[48]
  PIN xl1[49]
    DIRECTION INPUT ;
    USE SIGNAL ;
    PORT
      LAYER M5 ;
        RECT  78.672 0 78.696 0.084 ;
    END
  END xl1[49]
  PIN xl1[4]
    DIRECTION INPUT ;
    USE SIGNAL ;
    PORT
      LAYER M5 ;
        RECT  68.064 0 68.088 0.084 ;
    END
  END xl1[4]
  PIN xl1[50]
    DIRECTION INPUT ;
    USE SIGNAL ;
    PORT
      LAYER M5 ;
        RECT  78.912 0 78.936 0.084 ;
    END
  END xl1[50]
  PIN xl1[51]
    DIRECTION INPUT ;
    USE SIGNAL ;
    PORT
      LAYER M5 ;
        RECT  79.152 0 79.176 0.084 ;
    END
  END xl1[51]
  PIN xl1[52]
    DIRECTION INPUT ;
    USE SIGNAL ;
    PORT
      LAYER M5 ;
        RECT  79.392 0 79.416 0.084 ;
    END
  END xl1[52]
  PIN xl1[53]
    DIRECTION INPUT ;
    USE SIGNAL ;
    PORT
      LAYER M5 ;
        RECT  79.632 0 79.656 0.084 ;
    END
  END xl1[53]
  PIN xl1[54]
    DIRECTION INPUT ;
    USE SIGNAL ;
    PORT
      LAYER M5 ;
        RECT  79.872 0 79.896 0.084 ;
    END
  END xl1[54]
  PIN xl1[55]
    DIRECTION INPUT ;
    USE SIGNAL ;
    PORT
      LAYER M5 ;
        RECT  80.112 0 80.136 0.084 ;
    END
  END xl1[55]
  PIN xl1[56]
    DIRECTION INPUT ;
    USE SIGNAL ;
    PORT
      LAYER M5 ;
        RECT  80.352 0 80.376 0.084 ;
    END
  END xl1[56]
  PIN xl1[57]
    DIRECTION INPUT ;
    USE SIGNAL ;
    PORT
      LAYER M5 ;
        RECT  80.592 0 80.616 0.084 ;
    END
  END xl1[57]
  PIN xl1[58]
    DIRECTION INPUT ;
    USE SIGNAL ;
    PORT
      LAYER M5 ;
        RECT  80.784 0 80.808 0.084 ;
    END
  END xl1[58]
  PIN xl1[59]
    DIRECTION INPUT ;
    USE SIGNAL ;
    PORT
      LAYER M5 ;
        RECT  81.024 0 81.048 0.084 ;
    END
  END xl1[59]
  PIN xl1[5]
    DIRECTION INPUT ;
    USE SIGNAL ;
    PORT
      LAYER M5 ;
        RECT  68.304 0 68.328 0.084 ;
    END
  END xl1[5]
  PIN xl1[60]
    DIRECTION INPUT ;
    USE SIGNAL ;
    PORT
      LAYER M5 ;
        RECT  81.264 0 81.288 0.084 ;
    END
  END xl1[60]
  PIN xl1[61]
    DIRECTION INPUT ;
    USE SIGNAL ;
    PORT
      LAYER M5 ;
        RECT  81.504 0 81.528 0.084 ;
    END
  END xl1[61]
  PIN xl1[62]
    DIRECTION INPUT ;
    USE SIGNAL ;
    PORT
      LAYER M5 ;
        RECT  81.744 0 81.768 0.084 ;
    END
  END xl1[62]
  PIN xl1[63]
    DIRECTION INPUT ;
    USE SIGNAL ;
    PORT
      LAYER M5 ;
        RECT  81.984 0 82.008 0.084 ;
    END
  END xl1[63]
  PIN xl1[64]
    DIRECTION INPUT ;
    USE SIGNAL ;
    PORT
      LAYER M5 ;
        RECT  82.224 0 82.248 0.084 ;
    END
  END xl1[64]
  PIN xl1[65]
    DIRECTION INPUT ;
    USE SIGNAL ;
    PORT
      LAYER M5 ;
        RECT  82.464 0 82.488 0.084 ;
    END
  END xl1[65]
  PIN xl1[66]
    DIRECTION INPUT ;
    USE SIGNAL ;
    PORT
      LAYER M5 ;
        RECT  82.704 0 82.728 0.084 ;
    END
  END xl1[66]
  PIN xl1[67]
    DIRECTION INPUT ;
    USE SIGNAL ;
    PORT
      LAYER M5 ;
        RECT  82.944 0 82.968 0.084 ;
    END
  END xl1[67]
  PIN xl1[68]
    DIRECTION INPUT ;
    USE SIGNAL ;
    PORT
      LAYER M5 ;
        RECT  83.184 0 83.208 0.084 ;
    END
  END xl1[68]
  PIN xl1[69]
    DIRECTION INPUT ;
    USE SIGNAL ;
    PORT
      LAYER M5 ;
        RECT  83.376 0 83.4 0.084 ;
    END
  END xl1[69]
  PIN xl1[6]
    DIRECTION INPUT ;
    USE SIGNAL ;
    PORT
      LAYER M5 ;
        RECT  68.544 0 68.568 0.084 ;
    END
  END xl1[6]
  PIN xl1[70]
    DIRECTION INPUT ;
    USE SIGNAL ;
    PORT
      LAYER M5 ;
        RECT  83.616 0 83.64 0.084 ;
    END
  END xl1[70]
  PIN xl1[71]
    DIRECTION INPUT ;
    USE SIGNAL ;
    PORT
      LAYER M5 ;
        RECT  83.856 0 83.88 0.084 ;
    END
  END xl1[71]
  PIN xl1[72]
    DIRECTION INPUT ;
    USE SIGNAL ;
    PORT
      LAYER M5 ;
        RECT  84.096 0 84.12 0.084 ;
    END
  END xl1[72]
  PIN xl1[73]
    DIRECTION INPUT ;
    USE SIGNAL ;
    PORT
      LAYER M5 ;
        RECT  84.336 0 84.36 0.084 ;
    END
  END xl1[73]
  PIN xl1[74]
    DIRECTION INPUT ;
    USE SIGNAL ;
    PORT
      LAYER M5 ;
        RECT  84.576 0 84.6 0.084 ;
    END
  END xl1[74]
  PIN xl1[75]
    DIRECTION INPUT ;
    USE SIGNAL ;
    PORT
      LAYER M5 ;
        RECT  84.816 0 84.84 0.084 ;
    END
  END xl1[75]
  PIN xl1[76]
    DIRECTION INPUT ;
    USE SIGNAL ;
    PORT
      LAYER M5 ;
        RECT  85.056 0 85.08 0.084 ;
    END
  END xl1[76]
  PIN xl1[77]
    DIRECTION INPUT ;
    USE SIGNAL ;
    PORT
      LAYER M5 ;
        RECT  85.296 0 85.32 0.084 ;
    END
  END xl1[77]
  PIN xl1[78]
    DIRECTION INPUT ;
    USE SIGNAL ;
    PORT
      LAYER M5 ;
        RECT  85.536 0 85.56 0.084 ;
    END
  END xl1[78]
  PIN xl1[79]
    DIRECTION INPUT ;
    USE SIGNAL ;
    PORT
      LAYER M5 ;
        RECT  85.776 0 85.8 0.084 ;
    END
  END xl1[79]
  PIN xl1[7]
    DIRECTION INPUT ;
    USE SIGNAL ;
    PORT
      LAYER M5 ;
        RECT  68.784 0 68.808 0.084 ;
    END
  END xl1[7]
  PIN xl1[80]
    DIRECTION INPUT ;
    USE SIGNAL ;
    PORT
      LAYER M5 ;
        RECT  86.016 0 86.04 0.084 ;
    END
  END xl1[80]
  PIN xl1[81]
    DIRECTION INPUT ;
    USE SIGNAL ;
    PORT
      LAYER M5 ;
        RECT  86.208 0 86.232 0.084 ;
    END
  END xl1[81]
  PIN xl1[82]
    DIRECTION INPUT ;
    USE SIGNAL ;
    PORT
      LAYER M5 ;
        RECT  86.448 0 86.472 0.084 ;
    END
  END xl1[82]
  PIN xl1[83]
    DIRECTION INPUT ;
    USE SIGNAL ;
    PORT
      LAYER M5 ;
        RECT  86.688 0 86.712 0.084 ;
    END
  END xl1[83]
  PIN xl1[84]
    DIRECTION INPUT ;
    USE SIGNAL ;
    PORT
      LAYER M5 ;
        RECT  86.928 0 86.952 0.084 ;
    END
  END xl1[84]
  PIN xl1[85]
    DIRECTION INPUT ;
    USE SIGNAL ;
    PORT
      LAYER M5 ;
        RECT  87.168 0 87.192 0.084 ;
    END
  END xl1[85]
  PIN xl1[86]
    DIRECTION INPUT ;
    USE SIGNAL ;
    PORT
      LAYER M5 ;
        RECT  87.408 0 87.432 0.084 ;
    END
  END xl1[86]
  PIN xl1[87]
    DIRECTION INPUT ;
    USE SIGNAL ;
    PORT
      LAYER M5 ;
        RECT  87.648 0 87.672 0.084 ;
    END
  END xl1[87]
  PIN xl1[88]
    DIRECTION INPUT ;
    USE SIGNAL ;
    PORT
      LAYER M5 ;
        RECT  87.888 0 87.912 0.084 ;
    END
  END xl1[88]
  PIN xl1[89]
    DIRECTION INPUT ;
    USE SIGNAL ;
    PORT
      LAYER M5 ;
        RECT  88.128 0 88.152 0.084 ;
    END
  END xl1[89]
  PIN xl1[8]
    DIRECTION INPUT ;
    USE SIGNAL ;
    PORT
      LAYER M5 ;
        RECT  69.024 0 69.048 0.084 ;
    END
  END xl1[8]
  PIN xl1[90]
    DIRECTION INPUT ;
    USE SIGNAL ;
    PORT
      LAYER M5 ;
        RECT  88.368 0 88.392 0.084 ;
    END
  END xl1[90]
  PIN xl1[91]
    DIRECTION INPUT ;
    USE SIGNAL ;
    PORT
      LAYER M5 ;
        RECT  88.608 0 88.632 0.084 ;
    END
  END xl1[91]
  PIN xl1[92]
    DIRECTION INPUT ;
    USE SIGNAL ;
    PORT
      LAYER M5 ;
        RECT  88.848 0 88.872 0.084 ;
    END
  END xl1[92]
  PIN xl1[93]
    DIRECTION INPUT ;
    USE SIGNAL ;
    PORT
      LAYER M5 ;
        RECT  89.04 0 89.064 0.084 ;
    END
  END xl1[93]
  PIN xl1[94]
    DIRECTION INPUT ;
    USE SIGNAL ;
    PORT
      LAYER M5 ;
        RECT  89.28 0 89.304 0.084 ;
    END
  END xl1[94]
  PIN xl1[95]
    DIRECTION INPUT ;
    USE SIGNAL ;
    PORT
      LAYER M5 ;
        RECT  89.52 0 89.544 0.084 ;
    END
  END xl1[95]
  PIN xl1[96]
    DIRECTION INPUT ;
    USE SIGNAL ;
    PORT
      LAYER M5 ;
        RECT  89.76 0 89.784 0.084 ;
    END
  END xl1[96]
  PIN xl1[97]
    DIRECTION INPUT ;
    USE SIGNAL ;
    PORT
      LAYER M5 ;
        RECT  90 0 90.024 0.084 ;
    END
  END xl1[97]
  PIN xl1[98]
    DIRECTION INPUT ;
    USE SIGNAL ;
    PORT
      LAYER M5 ;
        RECT  90.24 0 90.264 0.084 ;
    END
  END xl1[98]
  PIN xl1[99]
    DIRECTION INPUT ;
    USE SIGNAL ;
    PORT
      LAYER M5 ;
        RECT  90.48 0 90.504 0.084 ;
    END
  END xl1[99]
  PIN xl1[9]
    DIRECTION INPUT ;
    USE SIGNAL ;
    PORT
      LAYER M5 ;
        RECT  69.264 0 69.288 0.084 ;
    END
  END xl1[9]
  PIN xl2[0]
    DIRECTION INPUT ;
    USE SIGNAL ;
    PORT
      LAYER M5 ;
        RECT  132.24 0 132.264 0.084 ;
    END
  END xl2[0]
  PIN xl2[100]
    DIRECTION INPUT ;
    USE SIGNAL ;
    PORT
      LAYER M5 ;
        RECT  155.856 0 155.88 0.084 ;
    END
  END xl2[100]
  PIN xl2[101]
    DIRECTION INPUT ;
    USE SIGNAL ;
    PORT
      LAYER M5 ;
        RECT  156.096 0 156.12 0.084 ;
    END
  END xl2[101]
  PIN xl2[102]
    DIRECTION INPUT ;
    USE SIGNAL ;
    PORT
      LAYER M5 ;
        RECT  156.336 0 156.36 0.084 ;
    END
  END xl2[102]
  PIN xl2[103]
    DIRECTION INPUT ;
    USE SIGNAL ;
    PORT
      LAYER M5 ;
        RECT  156.576 0 156.6 0.084 ;
    END
  END xl2[103]
  PIN xl2[104]
    DIRECTION INPUT ;
    USE SIGNAL ;
    PORT
      LAYER M5 ;
        RECT  156.768 0 156.792 0.084 ;
    END
  END xl2[104]
  PIN xl2[105]
    DIRECTION INPUT ;
    USE SIGNAL ;
    PORT
      LAYER M5 ;
        RECT  157.008 0 157.032 0.084 ;
    END
  END xl2[105]
  PIN xl2[106]
    DIRECTION INPUT ;
    USE SIGNAL ;
    PORT
      LAYER M5 ;
        RECT  157.248 0 157.272 0.084 ;
    END
  END xl2[106]
  PIN xl2[107]
    DIRECTION INPUT ;
    USE SIGNAL ;
    PORT
      LAYER M5 ;
        RECT  157.488 0 157.512 0.084 ;
    END
  END xl2[107]
  PIN xl2[108]
    DIRECTION INPUT ;
    USE SIGNAL ;
    PORT
      LAYER M5 ;
        RECT  157.728 0 157.752 0.084 ;
    END
  END xl2[108]
  PIN xl2[109]
    DIRECTION INPUT ;
    USE SIGNAL ;
    PORT
      LAYER M5 ;
        RECT  157.968 0 157.992 0.084 ;
    END
  END xl2[109]
  PIN xl2[10]
    DIRECTION INPUT ;
    USE SIGNAL ;
    PORT
      LAYER M5 ;
        RECT  134.592 0 134.616 0.084 ;
    END
  END xl2[10]
  PIN xl2[110]
    DIRECTION INPUT ;
    USE SIGNAL ;
    PORT
      LAYER M5 ;
        RECT  158.208 0 158.232 0.084 ;
    END
  END xl2[110]
  PIN xl2[111]
    DIRECTION INPUT ;
    USE SIGNAL ;
    PORT
      LAYER M5 ;
        RECT  158.448 0 158.472 0.084 ;
    END
  END xl2[111]
  PIN xl2[112]
    DIRECTION INPUT ;
    USE SIGNAL ;
    PORT
      LAYER M5 ;
        RECT  158.688 0 158.712 0.084 ;
    END
  END xl2[112]
  PIN xl2[113]
    DIRECTION INPUT ;
    USE SIGNAL ;
    PORT
      LAYER M5 ;
        RECT  158.928 0 158.952 0.084 ;
    END
  END xl2[113]
  PIN xl2[114]
    DIRECTION INPUT ;
    USE SIGNAL ;
    PORT
      LAYER M5 ;
        RECT  159.168 0 159.192 0.084 ;
    END
  END xl2[114]
  PIN xl2[115]
    DIRECTION INPUT ;
    USE SIGNAL ;
    PORT
      LAYER M5 ;
        RECT  159.408 0 159.432 0.084 ;
    END
  END xl2[115]
  PIN xl2[116]
    DIRECTION INPUT ;
    USE SIGNAL ;
    PORT
      LAYER M5 ;
        RECT  159.6 0 159.624 0.084 ;
    END
  END xl2[116]
  PIN xl2[117]
    DIRECTION INPUT ;
    USE SIGNAL ;
    PORT
      LAYER M5 ;
        RECT  159.84 0 159.864 0.084 ;
    END
  END xl2[117]
  PIN xl2[118]
    DIRECTION INPUT ;
    USE SIGNAL ;
    PORT
      LAYER M5 ;
        RECT  160.08 0 160.104 0.084 ;
    END
  END xl2[118]
  PIN xl2[119]
    DIRECTION INPUT ;
    USE SIGNAL ;
    PORT
      LAYER M5 ;
        RECT  160.32 0 160.344 0.084 ;
    END
  END xl2[119]
  PIN xl2[11]
    DIRECTION INPUT ;
    USE SIGNAL ;
    PORT
      LAYER M5 ;
        RECT  134.832 0 134.856 0.084 ;
    END
  END xl2[11]
  PIN xl2[120]
    DIRECTION INPUT ;
    USE SIGNAL ;
    PORT
      LAYER M5 ;
        RECT  160.56 0 160.584 0.084 ;
    END
  END xl2[120]
  PIN xl2[121]
    DIRECTION INPUT ;
    USE SIGNAL ;
    PORT
      LAYER M5 ;
        RECT  160.8 0 160.824 0.084 ;
    END
  END xl2[121]
  PIN xl2[122]
    DIRECTION INPUT ;
    USE SIGNAL ;
    PORT
      LAYER M5 ;
        RECT  161.04 0 161.064 0.084 ;
    END
  END xl2[122]
  PIN xl2[123]
    DIRECTION INPUT ;
    USE SIGNAL ;
    PORT
      LAYER M5 ;
        RECT  161.28 0 161.304 0.084 ;
    END
  END xl2[123]
  PIN xl2[124]
    DIRECTION INPUT ;
    USE SIGNAL ;
    PORT
      LAYER M5 ;
        RECT  161.52 0 161.544 0.084 ;
    END
  END xl2[124]
  PIN xl2[125]
    DIRECTION INPUT ;
    USE SIGNAL ;
    PORT
      LAYER M5 ;
        RECT  161.76 0 161.784 0.084 ;
    END
  END xl2[125]
  PIN xl2[126]
    DIRECTION INPUT ;
    USE SIGNAL ;
    PORT
      LAYER M5 ;
        RECT  162 0 162.024 0.084 ;
    END
  END xl2[126]
  PIN xl2[127]
    DIRECTION INPUT ;
    USE SIGNAL ;
    PORT
      LAYER M5 ;
        RECT  162.192 0 162.216 0.084 ;
    END
  END xl2[127]
  PIN xl2[128]
    DIRECTION INPUT ;
    USE SIGNAL ;
    PORT
      LAYER M5 ;
        RECT  162.432 0 162.456 0.084 ;
    END
  END xl2[128]
  PIN xl2[129]
    DIRECTION INPUT ;
    USE SIGNAL ;
    PORT
      LAYER M5 ;
        RECT  162.672 0 162.696 0.084 ;
    END
  END xl2[129]
  PIN xl2[12]
    DIRECTION INPUT ;
    USE SIGNAL ;
    PORT
      LAYER M5 ;
        RECT  135.072 0 135.096 0.084 ;
    END
  END xl2[12]
  PIN xl2[130]
    DIRECTION INPUT ;
    USE SIGNAL ;
    PORT
      LAYER M5 ;
        RECT  162.912 0 162.936 0.084 ;
    END
  END xl2[130]
  PIN xl2[131]
    DIRECTION INPUT ;
    USE SIGNAL ;
    PORT
      LAYER M5 ;
        RECT  163.152 0 163.176 0.084 ;
    END
  END xl2[131]
  PIN xl2[132]
    DIRECTION INPUT ;
    USE SIGNAL ;
    PORT
      LAYER M5 ;
        RECT  163.392 0 163.416 0.084 ;
    END
  END xl2[132]
  PIN xl2[133]
    DIRECTION INPUT ;
    USE SIGNAL ;
    PORT
      LAYER M5 ;
        RECT  163.632 0 163.656 0.084 ;
    END
  END xl2[133]
  PIN xl2[134]
    DIRECTION INPUT ;
    USE SIGNAL ;
    PORT
      LAYER M5 ;
        RECT  163.872 0 163.896 0.084 ;
    END
  END xl2[134]
  PIN xl2[135]
    DIRECTION INPUT ;
    USE SIGNAL ;
    PORT
      LAYER M5 ;
        RECT  164.112 0 164.136 0.084 ;
    END
  END xl2[135]
  PIN xl2[136]
    DIRECTION INPUT ;
    USE SIGNAL ;
    PORT
      LAYER M5 ;
        RECT  164.352 0 164.376 0.084 ;
    END
  END xl2[136]
  PIN xl2[137]
    DIRECTION INPUT ;
    USE SIGNAL ;
    PORT
      LAYER M5 ;
        RECT  164.592 0 164.616 0.084 ;
    END
  END xl2[137]
  PIN xl2[138]
    DIRECTION INPUT ;
    USE SIGNAL ;
    PORT
      LAYER M5 ;
        RECT  164.832 0 164.856 0.084 ;
    END
  END xl2[138]
  PIN xl2[139]
    DIRECTION INPUT ;
    USE SIGNAL ;
    PORT
      LAYER M5 ;
        RECT  165.024 0 165.048 0.084 ;
    END
  END xl2[139]
  PIN xl2[13]
    DIRECTION INPUT ;
    USE SIGNAL ;
    PORT
      LAYER M5 ;
        RECT  135.312 0 135.336 0.084 ;
    END
  END xl2[13]
  PIN xl2[140]
    DIRECTION INPUT ;
    USE SIGNAL ;
    PORT
      LAYER M5 ;
        RECT  165.264 0 165.288 0.084 ;
    END
  END xl2[140]
  PIN xl2[141]
    DIRECTION INPUT ;
    USE SIGNAL ;
    PORT
      LAYER M5 ;
        RECT  165.504 0 165.528 0.084 ;
    END
  END xl2[141]
  PIN xl2[142]
    DIRECTION INPUT ;
    USE SIGNAL ;
    PORT
      LAYER M5 ;
        RECT  165.744 0 165.768 0.084 ;
    END
  END xl2[142]
  PIN xl2[143]
    DIRECTION INPUT ;
    USE SIGNAL ;
    PORT
      LAYER M5 ;
        RECT  165.984 0 166.008 0.084 ;
    END
  END xl2[143]
  PIN xl2[144]
    DIRECTION INPUT ;
    USE SIGNAL ;
    PORT
      LAYER M5 ;
        RECT  166.224 0 166.248 0.084 ;
    END
  END xl2[144]
  PIN xl2[145]
    DIRECTION INPUT ;
    USE SIGNAL ;
    PORT
      LAYER M5 ;
        RECT  166.464 0 166.488 0.084 ;
    END
  END xl2[145]
  PIN xl2[146]
    DIRECTION INPUT ;
    USE SIGNAL ;
    PORT
      LAYER M5 ;
        RECT  166.704 0 166.728 0.084 ;
    END
  END xl2[146]
  PIN xl2[147]
    DIRECTION INPUT ;
    USE SIGNAL ;
    PORT
      LAYER M5 ;
        RECT  166.944 0 166.968 0.084 ;
    END
  END xl2[147]
  PIN xl2[148]
    DIRECTION INPUT ;
    USE SIGNAL ;
    PORT
      LAYER M5 ;
        RECT  167.184 0 167.208 0.084 ;
    END
  END xl2[148]
  PIN xl2[149]
    DIRECTION INPUT ;
    USE SIGNAL ;
    PORT
      LAYER M5 ;
        RECT  167.424 0 167.448 0.084 ;
    END
  END xl2[149]
  PIN xl2[14]
    DIRECTION INPUT ;
    USE SIGNAL ;
    PORT
      LAYER M5 ;
        RECT  135.552 0 135.576 0.084 ;
    END
  END xl2[14]
  PIN xl2[150]
    DIRECTION INPUT ;
    USE SIGNAL ;
    PORT
      LAYER M5 ;
        RECT  167.664 0 167.688 0.084 ;
    END
  END xl2[150]
  PIN xl2[151]
    DIRECTION INPUT ;
    USE SIGNAL ;
    PORT
      LAYER M5 ;
        RECT  167.856 0 167.88 0.084 ;
    END
  END xl2[151]
  PIN xl2[152]
    DIRECTION INPUT ;
    USE SIGNAL ;
    PORT
      LAYER M5 ;
        RECT  168.096 0 168.12 0.084 ;
    END
  END xl2[152]
  PIN xl2[153]
    DIRECTION INPUT ;
    USE SIGNAL ;
    PORT
      LAYER M5 ;
        RECT  168.336 0 168.36 0.084 ;
    END
  END xl2[153]
  PIN xl2[154]
    DIRECTION INPUT ;
    USE SIGNAL ;
    PORT
      LAYER M5 ;
        RECT  168.576 0 168.6 0.084 ;
    END
  END xl2[154]
  PIN xl2[155]
    DIRECTION INPUT ;
    USE SIGNAL ;
    PORT
      LAYER M5 ;
        RECT  168.816 0 168.84 0.084 ;
    END
  END xl2[155]
  PIN xl2[156]
    DIRECTION INPUT ;
    USE SIGNAL ;
    PORT
      LAYER M5 ;
        RECT  169.056 0 169.08 0.084 ;
    END
  END xl2[156]
  PIN xl2[157]
    DIRECTION INPUT ;
    USE SIGNAL ;
    PORT
      LAYER M5 ;
        RECT  169.296 0 169.32 0.084 ;
    END
  END xl2[157]
  PIN xl2[158]
    DIRECTION INPUT ;
    USE SIGNAL ;
    PORT
      LAYER M5 ;
        RECT  169.536 0 169.56 0.084 ;
    END
  END xl2[158]
  PIN xl2[159]
    DIRECTION INPUT ;
    USE SIGNAL ;
    PORT
      LAYER M5 ;
        RECT  169.776 0 169.8 0.084 ;
    END
  END xl2[159]
  PIN xl2[15]
    DIRECTION INPUT ;
    USE SIGNAL ;
    PORT
      LAYER M5 ;
        RECT  135.792 0 135.816 0.084 ;
    END
  END xl2[15]
  PIN xl2[160]
    DIRECTION INPUT ;
    USE SIGNAL ;
    PORT
      LAYER M5 ;
        RECT  170.016 0 170.04 0.084 ;
    END
  END xl2[160]
  PIN xl2[161]
    DIRECTION INPUT ;
    USE SIGNAL ;
    PORT
      LAYER M5 ;
        RECT  170.256 0 170.28 0.084 ;
    END
  END xl2[161]
  PIN xl2[162]
    DIRECTION INPUT ;
    USE SIGNAL ;
    PORT
      LAYER M5 ;
        RECT  170.496 0 170.52 0.084 ;
    END
  END xl2[162]
  PIN xl2[163]
    DIRECTION INPUT ;
    USE SIGNAL ;
    PORT
      LAYER M5 ;
        RECT  170.688 0 170.712 0.084 ;
    END
  END xl2[163]
  PIN xl2[164]
    DIRECTION INPUT ;
    USE SIGNAL ;
    PORT
      LAYER M5 ;
        RECT  170.928 0 170.952 0.084 ;
    END
  END xl2[164]
  PIN xl2[165]
    DIRECTION INPUT ;
    USE SIGNAL ;
    PORT
      LAYER M5 ;
        RECT  171.168 0 171.192 0.084 ;
    END
  END xl2[165]
  PIN xl2[166]
    DIRECTION INPUT ;
    USE SIGNAL ;
    PORT
      LAYER M5 ;
        RECT  171.408 0 171.432 0.084 ;
    END
  END xl2[166]
  PIN xl2[167]
    DIRECTION INPUT ;
    USE SIGNAL ;
    PORT
      LAYER M5 ;
        RECT  171.648 0 171.672 0.084 ;
    END
  END xl2[167]
  PIN xl2[168]
    DIRECTION INPUT ;
    USE SIGNAL ;
    PORT
      LAYER M5 ;
        RECT  171.888 0 171.912 0.084 ;
    END
  END xl2[168]
  PIN xl2[169]
    DIRECTION INPUT ;
    USE SIGNAL ;
    PORT
      LAYER M5 ;
        RECT  172.128 0 172.152 0.084 ;
    END
  END xl2[169]
  PIN xl2[16]
    DIRECTION INPUT ;
    USE SIGNAL ;
    PORT
      LAYER M5 ;
        RECT  136.032 0 136.056 0.084 ;
    END
  END xl2[16]
  PIN xl2[170]
    DIRECTION INPUT ;
    USE SIGNAL ;
    PORT
      LAYER M5 ;
        RECT  172.368 0 172.392 0.084 ;
    END
  END xl2[170]
  PIN xl2[171]
    DIRECTION INPUT ;
    USE SIGNAL ;
    PORT
      LAYER M5 ;
        RECT  172.608 0 172.632 0.084 ;
    END
  END xl2[171]
  PIN xl2[172]
    DIRECTION INPUT ;
    USE SIGNAL ;
    PORT
      LAYER M5 ;
        RECT  172.848 0 172.872 0.084 ;
    END
  END xl2[172]
  PIN xl2[173]
    DIRECTION INPUT ;
    USE SIGNAL ;
    PORT
      LAYER M5 ;
        RECT  173.088 0 173.112 0.084 ;
    END
  END xl2[173]
  PIN xl2[174]
    DIRECTION INPUT ;
    USE SIGNAL ;
    PORT
      LAYER M5 ;
        RECT  173.328 0 173.352 0.084 ;
    END
  END xl2[174]
  PIN xl2[175]
    DIRECTION INPUT ;
    USE SIGNAL ;
    PORT
      LAYER M5 ;
        RECT  173.52 0 173.544 0.084 ;
    END
  END xl2[175]
  PIN xl2[176]
    DIRECTION INPUT ;
    USE SIGNAL ;
    PORT
      LAYER M5 ;
        RECT  173.76 0 173.784 0.084 ;
    END
  END xl2[176]
  PIN xl2[177]
    DIRECTION INPUT ;
    USE SIGNAL ;
    PORT
      LAYER M5 ;
        RECT  174 0 174.024 0.084 ;
    END
  END xl2[177]
  PIN xl2[178]
    DIRECTION INPUT ;
    USE SIGNAL ;
    PORT
      LAYER M5 ;
        RECT  174.24 0 174.264 0.084 ;
    END
  END xl2[178]
  PIN xl2[179]
    DIRECTION INPUT ;
    USE SIGNAL ;
    PORT
      LAYER M5 ;
        RECT  174.48 0 174.504 0.084 ;
    END
  END xl2[179]
  PIN xl2[17]
    DIRECTION INPUT ;
    USE SIGNAL ;
    PORT
      LAYER M5 ;
        RECT  136.272 0 136.296 0.084 ;
    END
  END xl2[17]
  PIN xl2[180]
    DIRECTION INPUT ;
    USE SIGNAL ;
    PORT
      LAYER M5 ;
        RECT  174.72 0 174.744 0.084 ;
    END
  END xl2[180]
  PIN xl2[181]
    DIRECTION INPUT ;
    USE SIGNAL ;
    PORT
      LAYER M5 ;
        RECT  174.96 0 174.984 0.084 ;
    END
  END xl2[181]
  PIN xl2[182]
    DIRECTION INPUT ;
    USE SIGNAL ;
    PORT
      LAYER M5 ;
        RECT  175.2 0 175.224 0.084 ;
    END
  END xl2[182]
  PIN xl2[183]
    DIRECTION INPUT ;
    USE SIGNAL ;
    PORT
      LAYER M5 ;
        RECT  175.44 0 175.464 0.084 ;
    END
  END xl2[183]
  PIN xl2[184]
    DIRECTION INPUT ;
    USE SIGNAL ;
    PORT
      LAYER M5 ;
        RECT  175.68 0 175.704 0.084 ;
    END
  END xl2[184]
  PIN xl2[185]
    DIRECTION INPUT ;
    USE SIGNAL ;
    PORT
      LAYER M5 ;
        RECT  175.92 0 175.944 0.084 ;
    END
  END xl2[185]
  PIN xl2[186]
    DIRECTION INPUT ;
    USE SIGNAL ;
    PORT
      LAYER M5 ;
        RECT  176.16 0 176.184 0.084 ;
    END
  END xl2[186]
  PIN xl2[187]
    DIRECTION INPUT ;
    USE SIGNAL ;
    PORT
      LAYER M5 ;
        RECT  176.352 0 176.376 0.084 ;
    END
  END xl2[187]
  PIN xl2[188]
    DIRECTION INPUT ;
    USE SIGNAL ;
    PORT
      LAYER M5 ;
        RECT  176.592 0 176.616 0.084 ;
    END
  END xl2[188]
  PIN xl2[189]
    DIRECTION INPUT ;
    USE SIGNAL ;
    PORT
      LAYER M5 ;
        RECT  176.832 0 176.856 0.084 ;
    END
  END xl2[189]
  PIN xl2[18]
    DIRECTION INPUT ;
    USE SIGNAL ;
    PORT
      LAYER M5 ;
        RECT  136.512 0 136.536 0.084 ;
    END
  END xl2[18]
  PIN xl2[190]
    DIRECTION INPUT ;
    USE SIGNAL ;
    PORT
      LAYER M5 ;
        RECT  177.072 0 177.096 0.084 ;
    END
  END xl2[190]
  PIN xl2[191]
    DIRECTION INPUT ;
    USE SIGNAL ;
    PORT
      LAYER M5 ;
        RECT  177.312 0 177.336 0.084 ;
    END
  END xl2[191]
  PIN xl2[192]
    DIRECTION INPUT ;
    USE SIGNAL ;
    PORT
      LAYER M5 ;
        RECT  177.552 0 177.576 0.084 ;
    END
  END xl2[192]
  PIN xl2[193]
    DIRECTION INPUT ;
    USE SIGNAL ;
    PORT
      LAYER M5 ;
        RECT  177.792 0 177.816 0.084 ;
    END
  END xl2[193]
  PIN xl2[194]
    DIRECTION INPUT ;
    USE SIGNAL ;
    PORT
      LAYER M5 ;
        RECT  178.032 0 178.056 0.084 ;
    END
  END xl2[194]
  PIN xl2[195]
    DIRECTION INPUT ;
    USE SIGNAL ;
    PORT
      LAYER M5 ;
        RECT  178.272 0 178.296 0.084 ;
    END
  END xl2[195]
  PIN xl2[196]
    DIRECTION INPUT ;
    USE SIGNAL ;
    PORT
      LAYER M5 ;
        RECT  178.512 0 178.536 0.084 ;
    END
  END xl2[196]
  PIN xl2[197]
    DIRECTION INPUT ;
    USE SIGNAL ;
    PORT
      LAYER M5 ;
        RECT  178.752 0 178.776 0.084 ;
    END
  END xl2[197]
  PIN xl2[198]
    DIRECTION INPUT ;
    USE SIGNAL ;
    PORT
      LAYER M5 ;
        RECT  178.992 0 179.016 0.084 ;
    END
  END xl2[198]
  PIN xl2[199]
    DIRECTION INPUT ;
    USE SIGNAL ;
    PORT
      LAYER M5 ;
        RECT  179.184 0 179.208 0.084 ;
    END
  END xl2[199]
  PIN xl2[19]
    DIRECTION INPUT ;
    USE SIGNAL ;
    PORT
      LAYER M5 ;
        RECT  136.752 0 136.776 0.084 ;
    END
  END xl2[19]
  PIN xl2[1]
    DIRECTION INPUT ;
    USE SIGNAL ;
    PORT
      LAYER M5 ;
        RECT  132.48 0 132.504 0.084 ;
    END
  END xl2[1]
  PIN xl2[200]
    DIRECTION INPUT ;
    USE SIGNAL ;
    PORT
      LAYER M5 ;
        RECT  179.424 0 179.448 0.084 ;
    END
  END xl2[200]
  PIN xl2[201]
    DIRECTION INPUT ;
    USE SIGNAL ;
    PORT
      LAYER M5 ;
        RECT  179.664 0 179.688 0.084 ;
    END
  END xl2[201]
  PIN xl2[202]
    DIRECTION INPUT ;
    USE SIGNAL ;
    PORT
      LAYER M5 ;
        RECT  179.904 0 179.928 0.084 ;
    END
  END xl2[202]
  PIN xl2[203]
    DIRECTION INPUT ;
    USE SIGNAL ;
    PORT
      LAYER M5 ;
        RECT  180.144 0 180.168 0.084 ;
    END
  END xl2[203]
  PIN xl2[204]
    DIRECTION INPUT ;
    USE SIGNAL ;
    PORT
      LAYER M5 ;
        RECT  180.384 0 180.408 0.084 ;
    END
  END xl2[204]
  PIN xl2[205]
    DIRECTION INPUT ;
    USE SIGNAL ;
    PORT
      LAYER M5 ;
        RECT  180.624 0 180.648 0.084 ;
    END
  END xl2[205]
  PIN xl2[206]
    DIRECTION INPUT ;
    USE SIGNAL ;
    PORT
      LAYER M5 ;
        RECT  180.864 0 180.888 0.084 ;
    END
  END xl2[206]
  PIN xl2[207]
    DIRECTION INPUT ;
    USE SIGNAL ;
    PORT
      LAYER M5 ;
        RECT  181.104 0 181.128 0.084 ;
    END
  END xl2[207]
  PIN xl2[208]
    DIRECTION INPUT ;
    USE SIGNAL ;
    PORT
      LAYER M5 ;
        RECT  181.344 0 181.368 0.084 ;
    END
  END xl2[208]
  PIN xl2[209]
    DIRECTION INPUT ;
    USE SIGNAL ;
    PORT
      LAYER M5 ;
        RECT  181.584 0 181.608 0.084 ;
    END
  END xl2[209]
  PIN xl2[20]
    DIRECTION INPUT ;
    USE SIGNAL ;
    PORT
      LAYER M5 ;
        RECT  136.944 0 136.968 0.084 ;
    END
  END xl2[20]
  PIN xl2[210]
    DIRECTION INPUT ;
    USE SIGNAL ;
    PORT
      LAYER M5 ;
        RECT  181.824 0 181.848 0.084 ;
    END
  END xl2[210]
  PIN xl2[211]
    DIRECTION INPUT ;
    USE SIGNAL ;
    PORT
      LAYER M5 ;
        RECT  182.016 0 182.04 0.084 ;
    END
  END xl2[211]
  PIN xl2[212]
    DIRECTION INPUT ;
    USE SIGNAL ;
    PORT
      LAYER M5 ;
        RECT  182.256 0 182.28 0.084 ;
    END
  END xl2[212]
  PIN xl2[213]
    DIRECTION INPUT ;
    USE SIGNAL ;
    PORT
      LAYER M5 ;
        RECT  182.496 0 182.52 0.084 ;
    END
  END xl2[213]
  PIN xl2[214]
    DIRECTION INPUT ;
    USE SIGNAL ;
    PORT
      LAYER M5 ;
        RECT  182.736 0 182.76 0.084 ;
    END
  END xl2[214]
  PIN xl2[215]
    DIRECTION INPUT ;
    USE SIGNAL ;
    PORT
      LAYER M5 ;
        RECT  182.976 0 183 0.084 ;
    END
  END xl2[215]
  PIN xl2[216]
    DIRECTION INPUT ;
    USE SIGNAL ;
    PORT
      LAYER M5 ;
        RECT  183.216 0 183.24 0.084 ;
    END
  END xl2[216]
  PIN xl2[217]
    DIRECTION INPUT ;
    USE SIGNAL ;
    PORT
      LAYER M5 ;
        RECT  183.456 0 183.48 0.084 ;
    END
  END xl2[217]
  PIN xl2[218]
    DIRECTION INPUT ;
    USE SIGNAL ;
    PORT
      LAYER M5 ;
        RECT  183.696 0 183.72 0.084 ;
    END
  END xl2[218]
  PIN xl2[219]
    DIRECTION INPUT ;
    USE SIGNAL ;
    PORT
      LAYER M5 ;
        RECT  183.936 0 183.96 0.084 ;
    END
  END xl2[219]
  PIN xl2[21]
    DIRECTION INPUT ;
    USE SIGNAL ;
    PORT
      LAYER M5 ;
        RECT  137.184 0 137.208 0.084 ;
    END
  END xl2[21]
  PIN xl2[220]
    DIRECTION INPUT ;
    USE SIGNAL ;
    PORT
      LAYER M5 ;
        RECT  184.176 0 184.2 0.084 ;
    END
  END xl2[220]
  PIN xl2[221]
    DIRECTION INPUT ;
    USE SIGNAL ;
    PORT
      LAYER M5 ;
        RECT  184.416 0 184.44 0.084 ;
    END
  END xl2[221]
  PIN xl2[222]
    DIRECTION INPUT ;
    USE SIGNAL ;
    PORT
      LAYER M5 ;
        RECT  184.656 0 184.68 0.084 ;
    END
  END xl2[222]
  PIN xl2[223]
    DIRECTION INPUT ;
    USE SIGNAL ;
    PORT
      LAYER M5 ;
        RECT  184.848 0 184.872 0.084 ;
    END
  END xl2[223]
  PIN xl2[224]
    DIRECTION INPUT ;
    USE SIGNAL ;
    PORT
      LAYER M5 ;
        RECT  185.088 0 185.112 0.084 ;
    END
  END xl2[224]
  PIN xl2[225]
    DIRECTION INPUT ;
    USE SIGNAL ;
    PORT
      LAYER M5 ;
        RECT  185.328 0 185.352 0.084 ;
    END
  END xl2[225]
  PIN xl2[226]
    DIRECTION INPUT ;
    USE SIGNAL ;
    PORT
      LAYER M5 ;
        RECT  185.568 0 185.592 0.084 ;
    END
  END xl2[226]
  PIN xl2[227]
    DIRECTION INPUT ;
    USE SIGNAL ;
    PORT
      LAYER M5 ;
        RECT  185.808 0 185.832 0.084 ;
    END
  END xl2[227]
  PIN xl2[228]
    DIRECTION INPUT ;
    USE SIGNAL ;
    PORT
      LAYER M5 ;
        RECT  186.048 0 186.072 0.084 ;
    END
  END xl2[228]
  PIN xl2[229]
    DIRECTION INPUT ;
    USE SIGNAL ;
    PORT
      LAYER M5 ;
        RECT  186.288 0 186.312 0.084 ;
    END
  END xl2[229]
  PIN xl2[22]
    DIRECTION INPUT ;
    USE SIGNAL ;
    PORT
      LAYER M5 ;
        RECT  137.424 0 137.448 0.084 ;
    END
  END xl2[22]
  PIN xl2[230]
    DIRECTION INPUT ;
    USE SIGNAL ;
    PORT
      LAYER M5 ;
        RECT  186.528 0 186.552 0.084 ;
    END
  END xl2[230]
  PIN xl2[231]
    DIRECTION INPUT ;
    USE SIGNAL ;
    PORT
      LAYER M5 ;
        RECT  186.768 0 186.792 0.084 ;
    END
  END xl2[231]
  PIN xl2[232]
    DIRECTION INPUT ;
    USE SIGNAL ;
    PORT
      LAYER M5 ;
        RECT  187.008 0 187.032 0.084 ;
    END
  END xl2[232]
  PIN xl2[233]
    DIRECTION INPUT ;
    USE SIGNAL ;
    PORT
      LAYER M5 ;
        RECT  187.248 0 187.272 0.084 ;
    END
  END xl2[233]
  PIN xl2[234]
    DIRECTION INPUT ;
    USE SIGNAL ;
    PORT
      LAYER M5 ;
        RECT  187.488 0 187.512 0.084 ;
    END
  END xl2[234]
  PIN xl2[235]
    DIRECTION INPUT ;
    USE SIGNAL ;
    PORT
      LAYER M5 ;
        RECT  187.68 0 187.704 0.084 ;
    END
  END xl2[235]
  PIN xl2[236]
    DIRECTION INPUT ;
    USE SIGNAL ;
    PORT
      LAYER M5 ;
        RECT  187.92 0 187.944 0.084 ;
    END
  END xl2[236]
  PIN xl2[237]
    DIRECTION INPUT ;
    USE SIGNAL ;
    PORT
      LAYER M5 ;
        RECT  188.16 0 188.184 0.084 ;
    END
  END xl2[237]
  PIN xl2[238]
    DIRECTION INPUT ;
    USE SIGNAL ;
    PORT
      LAYER M5 ;
        RECT  188.4 0 188.424 0.084 ;
    END
  END xl2[238]
  PIN xl2[239]
    DIRECTION INPUT ;
    USE SIGNAL ;
    PORT
      LAYER M5 ;
        RECT  188.64 0 188.664 0.084 ;
    END
  END xl2[239]
  PIN xl2[23]
    DIRECTION INPUT ;
    USE SIGNAL ;
    PORT
      LAYER M5 ;
        RECT  137.664 0 137.688 0.084 ;
    END
  END xl2[23]
  PIN xl2[240]
    DIRECTION INPUT ;
    USE SIGNAL ;
    PORT
      LAYER M5 ;
        RECT  188.88 0 188.904 0.084 ;
    END
  END xl2[240]
  PIN xl2[241]
    DIRECTION INPUT ;
    USE SIGNAL ;
    PORT
      LAYER M5 ;
        RECT  189.12 0 189.144 0.084 ;
    END
  END xl2[241]
  PIN xl2[242]
    DIRECTION INPUT ;
    USE SIGNAL ;
    PORT
      LAYER M5 ;
        RECT  189.36 0 189.384 0.084 ;
    END
  END xl2[242]
  PIN xl2[243]
    DIRECTION INPUT ;
    USE SIGNAL ;
    PORT
      LAYER M5 ;
        RECT  189.6 0 189.624 0.084 ;
    END
  END xl2[243]
  PIN xl2[244]
    DIRECTION INPUT ;
    USE SIGNAL ;
    PORT
      LAYER M5 ;
        RECT  189.84 0 189.864 0.084 ;
    END
  END xl2[244]
  PIN xl2[245]
    DIRECTION INPUT ;
    USE SIGNAL ;
    PORT
      LAYER M5 ;
        RECT  190.08 0 190.104 0.084 ;
    END
  END xl2[245]
  PIN xl2[246]
    DIRECTION INPUT ;
    USE SIGNAL ;
    PORT
      LAYER M5 ;
        RECT  190.32 0 190.344 0.084 ;
    END
  END xl2[246]
  PIN xl2[247]
    DIRECTION INPUT ;
    USE SIGNAL ;
    PORT
      LAYER M5 ;
        RECT  190.512 0 190.536 0.084 ;
    END
  END xl2[247]
  PIN xl2[248]
    DIRECTION INPUT ;
    USE SIGNAL ;
    PORT
      LAYER M5 ;
        RECT  190.752 0 190.776 0.084 ;
    END
  END xl2[248]
  PIN xl2[249]
    DIRECTION INPUT ;
    USE SIGNAL ;
    PORT
      LAYER M5 ;
        RECT  190.992 0 191.016 0.084 ;
    END
  END xl2[249]
  PIN xl2[24]
    DIRECTION INPUT ;
    USE SIGNAL ;
    PORT
      LAYER M5 ;
        RECT  137.904 0 137.928 0.084 ;
    END
  END xl2[24]
  PIN xl2[250]
    DIRECTION INPUT ;
    USE SIGNAL ;
    PORT
      LAYER M5 ;
        RECT  191.232 0 191.256 0.084 ;
    END
  END xl2[250]
  PIN xl2[251]
    DIRECTION INPUT ;
    USE SIGNAL ;
    PORT
      LAYER M5 ;
        RECT  191.472 0 191.496 0.084 ;
    END
  END xl2[251]
  PIN xl2[252]
    DIRECTION INPUT ;
    USE SIGNAL ;
    PORT
      LAYER M5 ;
        RECT  191.712 0 191.736 0.084 ;
    END
  END xl2[252]
  PIN xl2[253]
    DIRECTION INPUT ;
    USE SIGNAL ;
    PORT
      LAYER M5 ;
        RECT  191.952 0 191.976 0.084 ;
    END
  END xl2[253]
  PIN xl2[254]
    DIRECTION INPUT ;
    USE SIGNAL ;
    PORT
      LAYER M5 ;
        RECT  192.192 0 192.216 0.084 ;
    END
  END xl2[254]
  PIN xl2[255]
    DIRECTION INPUT ;
    USE SIGNAL ;
    PORT
      LAYER M5 ;
        RECT  192.432 0 192.456 0.084 ;
    END
  END xl2[255]
  PIN xl2[256]
    DIRECTION INPUT ;
    USE SIGNAL ;
    PORT
      LAYER M5 ;
        RECT  192.672 0 192.696 0.084 ;
    END
  END xl2[256]
  PIN xl2[257]
    DIRECTION INPUT ;
    USE SIGNAL ;
    PORT
      LAYER M5 ;
        RECT  192.912 0 192.936 0.084 ;
    END
  END xl2[257]
  PIN xl2[258]
    DIRECTION INPUT ;
    USE SIGNAL ;
    PORT
      LAYER M5 ;
        RECT  193.152 0 193.176 0.084 ;
    END
  END xl2[258]
  PIN xl2[259]
    DIRECTION INPUT ;
    USE SIGNAL ;
    PORT
      LAYER M5 ;
        RECT  193.344 0 193.368 0.084 ;
    END
  END xl2[259]
  PIN xl2[25]
    DIRECTION INPUT ;
    USE SIGNAL ;
    PORT
      LAYER M5 ;
        RECT  138.144 0 138.168 0.084 ;
    END
  END xl2[25]
  PIN xl2[260]
    DIRECTION INPUT ;
    USE SIGNAL ;
    PORT
      LAYER M5 ;
        RECT  193.584 0 193.608 0.084 ;
    END
  END xl2[260]
  PIN xl2[261]
    DIRECTION INPUT ;
    USE SIGNAL ;
    PORT
      LAYER M5 ;
        RECT  193.824 0 193.848 0.084 ;
    END
  END xl2[261]
  PIN xl2[262]
    DIRECTION INPUT ;
    USE SIGNAL ;
    PORT
      LAYER M5 ;
        RECT  194.064 0 194.088 0.084 ;
    END
  END xl2[262]
  PIN xl2[263]
    DIRECTION INPUT ;
    USE SIGNAL ;
    PORT
      LAYER M5 ;
        RECT  194.304 0 194.328 0.084 ;
    END
  END xl2[263]
  PIN xl2[264]
    DIRECTION INPUT ;
    USE SIGNAL ;
    PORT
      LAYER M5 ;
        RECT  194.544 0 194.568 0.084 ;
    END
  END xl2[264]
  PIN xl2[265]
    DIRECTION INPUT ;
    USE SIGNAL ;
    PORT
      LAYER M5 ;
        RECT  194.784 0 194.808 0.084 ;
    END
  END xl2[265]
  PIN xl2[266]
    DIRECTION INPUT ;
    USE SIGNAL ;
    PORT
      LAYER M5 ;
        RECT  195.024 0 195.048 0.084 ;
    END
  END xl2[266]
  PIN xl2[267]
    DIRECTION INPUT ;
    USE SIGNAL ;
    PORT
      LAYER M5 ;
        RECT  195.264 0 195.288 0.084 ;
    END
  END xl2[267]
  PIN xl2[268]
    DIRECTION INPUT ;
    USE SIGNAL ;
    PORT
      LAYER M5 ;
        RECT  195.504 0 195.528 0.084 ;
    END
  END xl2[268]
  PIN xl2[269]
    DIRECTION INPUT ;
    USE SIGNAL ;
    PORT
      LAYER M5 ;
        RECT  195.744 0 195.768 0.084 ;
    END
  END xl2[269]
  PIN xl2[26]
    DIRECTION INPUT ;
    USE SIGNAL ;
    PORT
      LAYER M5 ;
        RECT  138.384 0 138.408 0.084 ;
    END
  END xl2[26]
  PIN xl2[270]
    DIRECTION INPUT ;
    USE SIGNAL ;
    PORT
      LAYER M5 ;
        RECT  195.984 0 196.008 0.084 ;
    END
  END xl2[270]
  PIN xl2[271]
    DIRECTION INPUT ;
    USE SIGNAL ;
    PORT
      LAYER M5 ;
        RECT  196.176 0 196.2 0.084 ;
    END
  END xl2[271]
  PIN xl2[272]
    DIRECTION INPUT ;
    USE SIGNAL ;
    PORT
      LAYER M5 ;
        RECT  196.416 0 196.44 0.084 ;
    END
  END xl2[272]
  PIN xl2[273]
    DIRECTION INPUT ;
    USE SIGNAL ;
    PORT
      LAYER M5 ;
        RECT  196.656 0 196.68 0.084 ;
    END
  END xl2[273]
  PIN xl2[274]
    DIRECTION INPUT ;
    USE SIGNAL ;
    PORT
      LAYER M5 ;
        RECT  196.896 0 196.92 0.084 ;
    END
  END xl2[274]
  PIN xl2[275]
    DIRECTION INPUT ;
    USE SIGNAL ;
    PORT
      LAYER M5 ;
        RECT  197.136 0 197.16 0.084 ;
    END
  END xl2[275]
  PIN xl2[27]
    DIRECTION INPUT ;
    USE SIGNAL ;
    PORT
      LAYER M5 ;
        RECT  138.624 0 138.648 0.084 ;
    END
  END xl2[27]
  PIN xl2[28]
    DIRECTION INPUT ;
    USE SIGNAL ;
    PORT
      LAYER M5 ;
        RECT  138.864 0 138.888 0.084 ;
    END
  END xl2[28]
  PIN xl2[29]
    DIRECTION INPUT ;
    USE SIGNAL ;
    PORT
      LAYER M5 ;
        RECT  139.104 0 139.128 0.084 ;
    END
  END xl2[29]
  PIN xl2[2]
    DIRECTION INPUT ;
    USE SIGNAL ;
    PORT
      LAYER M5 ;
        RECT  132.72 0 132.744 0.084 ;
    END
  END xl2[2]
  PIN xl2[30]
    DIRECTION INPUT ;
    USE SIGNAL ;
    PORT
      LAYER M5 ;
        RECT  139.344 0 139.368 0.084 ;
    END
  END xl2[30]
  PIN xl2[31]
    DIRECTION INPUT ;
    USE SIGNAL ;
    PORT
      LAYER M5 ;
        RECT  139.584 0 139.608 0.084 ;
    END
  END xl2[31]
  PIN xl2[32]
    DIRECTION INPUT ;
    USE SIGNAL ;
    PORT
      LAYER M5 ;
        RECT  139.776 0 139.8 0.084 ;
    END
  END xl2[32]
  PIN xl2[33]
    DIRECTION INPUT ;
    USE SIGNAL ;
    PORT
      LAYER M5 ;
        RECT  140.016 0 140.04 0.084 ;
    END
  END xl2[33]
  PIN xl2[34]
    DIRECTION INPUT ;
    USE SIGNAL ;
    PORT
      LAYER M5 ;
        RECT  140.256 0 140.28 0.084 ;
    END
  END xl2[34]
  PIN xl2[35]
    DIRECTION INPUT ;
    USE SIGNAL ;
    PORT
      LAYER M5 ;
        RECT  140.496 0 140.52 0.084 ;
    END
  END xl2[35]
  PIN xl2[36]
    DIRECTION INPUT ;
    USE SIGNAL ;
    PORT
      LAYER M5 ;
        RECT  140.736 0 140.76 0.084 ;
    END
  END xl2[36]
  PIN xl2[37]
    DIRECTION INPUT ;
    USE SIGNAL ;
    PORT
      LAYER M5 ;
        RECT  140.976 0 141 0.084 ;
    END
  END xl2[37]
  PIN xl2[38]
    DIRECTION INPUT ;
    USE SIGNAL ;
    PORT
      LAYER M5 ;
        RECT  141.216 0 141.24 0.084 ;
    END
  END xl2[38]
  PIN xl2[39]
    DIRECTION INPUT ;
    USE SIGNAL ;
    PORT
      LAYER M5 ;
        RECT  141.456 0 141.48 0.084 ;
    END
  END xl2[39]
  PIN xl2[3]
    DIRECTION INPUT ;
    USE SIGNAL ;
    PORT
      LAYER M5 ;
        RECT  132.96 0 132.984 0.084 ;
    END
  END xl2[3]
  PIN xl2[40]
    DIRECTION INPUT ;
    USE SIGNAL ;
    PORT
      LAYER M5 ;
        RECT  141.696 0 141.72 0.084 ;
    END
  END xl2[40]
  PIN xl2[41]
    DIRECTION INPUT ;
    USE SIGNAL ;
    PORT
      LAYER M5 ;
        RECT  141.936 0 141.96 0.084 ;
    END
  END xl2[41]
  PIN xl2[42]
    DIRECTION INPUT ;
    USE SIGNAL ;
    PORT
      LAYER M5 ;
        RECT  142.176 0 142.2 0.084 ;
    END
  END xl2[42]
  PIN xl2[43]
    DIRECTION INPUT ;
    USE SIGNAL ;
    PORT
      LAYER M5 ;
        RECT  142.416 0 142.44 0.084 ;
    END
  END xl2[43]
  PIN xl2[44]
    DIRECTION INPUT ;
    USE SIGNAL ;
    PORT
      LAYER M5 ;
        RECT  142.608 0 142.632 0.084 ;
    END
  END xl2[44]
  PIN xl2[45]
    DIRECTION INPUT ;
    USE SIGNAL ;
    PORT
      LAYER M5 ;
        RECT  142.848 0 142.872 0.084 ;
    END
  END xl2[45]
  PIN xl2[46]
    DIRECTION INPUT ;
    USE SIGNAL ;
    PORT
      LAYER M5 ;
        RECT  143.088 0 143.112 0.084 ;
    END
  END xl2[46]
  PIN xl2[47]
    DIRECTION INPUT ;
    USE SIGNAL ;
    PORT
      LAYER M5 ;
        RECT  143.328 0 143.352 0.084 ;
    END
  END xl2[47]
  PIN xl2[48]
    DIRECTION INPUT ;
    USE SIGNAL ;
    PORT
      LAYER M5 ;
        RECT  143.568 0 143.592 0.084 ;
    END
  END xl2[48]
  PIN xl2[49]
    DIRECTION INPUT ;
    USE SIGNAL ;
    PORT
      LAYER M5 ;
        RECT  143.808 0 143.832 0.084 ;
    END
  END xl2[49]
  PIN xl2[4]
    DIRECTION INPUT ;
    USE SIGNAL ;
    PORT
      LAYER M5 ;
        RECT  133.2 0 133.224 0.084 ;
    END
  END xl2[4]
  PIN xl2[50]
    DIRECTION INPUT ;
    USE SIGNAL ;
    PORT
      LAYER M5 ;
        RECT  144.048 0 144.072 0.084 ;
    END
  END xl2[50]
  PIN xl2[51]
    DIRECTION INPUT ;
    USE SIGNAL ;
    PORT
      LAYER M5 ;
        RECT  144.288 0 144.312 0.084 ;
    END
  END xl2[51]
  PIN xl2[52]
    DIRECTION INPUT ;
    USE SIGNAL ;
    PORT
      LAYER M5 ;
        RECT  144.528 0 144.552 0.084 ;
    END
  END xl2[52]
  PIN xl2[53]
    DIRECTION INPUT ;
    USE SIGNAL ;
    PORT
      LAYER M5 ;
        RECT  144.768 0 144.792 0.084 ;
    END
  END xl2[53]
  PIN xl2[54]
    DIRECTION INPUT ;
    USE SIGNAL ;
    PORT
      LAYER M5 ;
        RECT  145.008 0 145.032 0.084 ;
    END
  END xl2[54]
  PIN xl2[55]
    DIRECTION INPUT ;
    USE SIGNAL ;
    PORT
      LAYER M5 ;
        RECT  145.248 0 145.272 0.084 ;
    END
  END xl2[55]
  PIN xl2[56]
    DIRECTION INPUT ;
    USE SIGNAL ;
    PORT
      LAYER M5 ;
        RECT  145.44 0 145.464 0.084 ;
    END
  END xl2[56]
  PIN xl2[57]
    DIRECTION INPUT ;
    USE SIGNAL ;
    PORT
      LAYER M5 ;
        RECT  145.68 0 145.704 0.084 ;
    END
  END xl2[57]
  PIN xl2[58]
    DIRECTION INPUT ;
    USE SIGNAL ;
    PORT
      LAYER M5 ;
        RECT  145.92 0 145.944 0.084 ;
    END
  END xl2[58]
  PIN xl2[59]
    DIRECTION INPUT ;
    USE SIGNAL ;
    PORT
      LAYER M5 ;
        RECT  146.16 0 146.184 0.084 ;
    END
  END xl2[59]
  PIN xl2[5]
    DIRECTION INPUT ;
    USE SIGNAL ;
    PORT
      LAYER M5 ;
        RECT  133.44 0 133.464 0.084 ;
    END
  END xl2[5]
  PIN xl2[60]
    DIRECTION INPUT ;
    USE SIGNAL ;
    PORT
      LAYER M5 ;
        RECT  146.4 0 146.424 0.084 ;
    END
  END xl2[60]
  PIN xl2[61]
    DIRECTION INPUT ;
    USE SIGNAL ;
    PORT
      LAYER M5 ;
        RECT  146.64 0 146.664 0.084 ;
    END
  END xl2[61]
  PIN xl2[62]
    DIRECTION INPUT ;
    USE SIGNAL ;
    PORT
      LAYER M5 ;
        RECT  146.88 0 146.904 0.084 ;
    END
  END xl2[62]
  PIN xl2[63]
    DIRECTION INPUT ;
    USE SIGNAL ;
    PORT
      LAYER M5 ;
        RECT  147.12 0 147.144 0.084 ;
    END
  END xl2[63]
  PIN xl2[64]
    DIRECTION INPUT ;
    USE SIGNAL ;
    PORT
      LAYER M5 ;
        RECT  147.36 0 147.384 0.084 ;
    END
  END xl2[64]
  PIN xl2[65]
    DIRECTION INPUT ;
    USE SIGNAL ;
    PORT
      LAYER M5 ;
        RECT  147.6 0 147.624 0.084 ;
    END
  END xl2[65]
  PIN xl2[66]
    DIRECTION INPUT ;
    USE SIGNAL ;
    PORT
      LAYER M5 ;
        RECT  147.84 0 147.864 0.084 ;
    END
  END xl2[66]
  PIN xl2[67]
    DIRECTION INPUT ;
    USE SIGNAL ;
    PORT
      LAYER M5 ;
        RECT  148.08 0 148.104 0.084 ;
    END
  END xl2[67]
  PIN xl2[68]
    DIRECTION INPUT ;
    USE SIGNAL ;
    PORT
      LAYER M5 ;
        RECT  148.272 0 148.296 0.084 ;
    END
  END xl2[68]
  PIN xl2[69]
    DIRECTION INPUT ;
    USE SIGNAL ;
    PORT
      LAYER M5 ;
        RECT  148.512 0 148.536 0.084 ;
    END
  END xl2[69]
  PIN xl2[6]
    DIRECTION INPUT ;
    USE SIGNAL ;
    PORT
      LAYER M5 ;
        RECT  133.68 0 133.704 0.084 ;
    END
  END xl2[6]
  PIN xl2[70]
    DIRECTION INPUT ;
    USE SIGNAL ;
    PORT
      LAYER M5 ;
        RECT  148.752 0 148.776 0.084 ;
    END
  END xl2[70]
  PIN xl2[71]
    DIRECTION INPUT ;
    USE SIGNAL ;
    PORT
      LAYER M5 ;
        RECT  148.992 0 149.016 0.084 ;
    END
  END xl2[71]
  PIN xl2[72]
    DIRECTION INPUT ;
    USE SIGNAL ;
    PORT
      LAYER M5 ;
        RECT  149.232 0 149.256 0.084 ;
    END
  END xl2[72]
  PIN xl2[73]
    DIRECTION INPUT ;
    USE SIGNAL ;
    PORT
      LAYER M5 ;
        RECT  149.472 0 149.496 0.084 ;
    END
  END xl2[73]
  PIN xl2[74]
    DIRECTION INPUT ;
    USE SIGNAL ;
    PORT
      LAYER M5 ;
        RECT  149.712 0 149.736 0.084 ;
    END
  END xl2[74]
  PIN xl2[75]
    DIRECTION INPUT ;
    USE SIGNAL ;
    PORT
      LAYER M5 ;
        RECT  149.952 0 149.976 0.084 ;
    END
  END xl2[75]
  PIN xl2[76]
    DIRECTION INPUT ;
    USE SIGNAL ;
    PORT
      LAYER M5 ;
        RECT  150.192 0 150.216 0.084 ;
    END
  END xl2[76]
  PIN xl2[77]
    DIRECTION INPUT ;
    USE SIGNAL ;
    PORT
      LAYER M5 ;
        RECT  150.432 0 150.456 0.084 ;
    END
  END xl2[77]
  PIN xl2[78]
    DIRECTION INPUT ;
    USE SIGNAL ;
    PORT
      LAYER M5 ;
        RECT  150.672 0 150.696 0.084 ;
    END
  END xl2[78]
  PIN xl2[79]
    DIRECTION INPUT ;
    USE SIGNAL ;
    PORT
      LAYER M5 ;
        RECT  150.912 0 150.936 0.084 ;
    END
  END xl2[79]
  PIN xl2[7]
    DIRECTION INPUT ;
    USE SIGNAL ;
    PORT
      LAYER M5 ;
        RECT  133.92 0 133.944 0.084 ;
    END
  END xl2[7]
  PIN xl2[80]
    DIRECTION INPUT ;
    USE SIGNAL ;
    PORT
      LAYER M5 ;
        RECT  151.104 0 151.128 0.084 ;
    END
  END xl2[80]
  PIN xl2[81]
    DIRECTION INPUT ;
    USE SIGNAL ;
    PORT
      LAYER M5 ;
        RECT  151.344 0 151.368 0.084 ;
    END
  END xl2[81]
  PIN xl2[82]
    DIRECTION INPUT ;
    USE SIGNAL ;
    PORT
      LAYER M5 ;
        RECT  151.584 0 151.608 0.084 ;
    END
  END xl2[82]
  PIN xl2[83]
    DIRECTION INPUT ;
    USE SIGNAL ;
    PORT
      LAYER M5 ;
        RECT  151.824 0 151.848 0.084 ;
    END
  END xl2[83]
  PIN xl2[84]
    DIRECTION INPUT ;
    USE SIGNAL ;
    PORT
      LAYER M5 ;
        RECT  152.064 0 152.088 0.084 ;
    END
  END xl2[84]
  PIN xl2[85]
    DIRECTION INPUT ;
    USE SIGNAL ;
    PORT
      LAYER M5 ;
        RECT  152.304 0 152.328 0.084 ;
    END
  END xl2[85]
  PIN xl2[86]
    DIRECTION INPUT ;
    USE SIGNAL ;
    PORT
      LAYER M5 ;
        RECT  152.544 0 152.568 0.084 ;
    END
  END xl2[86]
  PIN xl2[87]
    DIRECTION INPUT ;
    USE SIGNAL ;
    PORT
      LAYER M5 ;
        RECT  152.784 0 152.808 0.084 ;
    END
  END xl2[87]
  PIN xl2[88]
    DIRECTION INPUT ;
    USE SIGNAL ;
    PORT
      LAYER M5 ;
        RECT  153.024 0 153.048 0.084 ;
    END
  END xl2[88]
  PIN xl2[89]
    DIRECTION INPUT ;
    USE SIGNAL ;
    PORT
      LAYER M5 ;
        RECT  153.264 0 153.288 0.084 ;
    END
  END xl2[89]
  PIN xl2[8]
    DIRECTION INPUT ;
    USE SIGNAL ;
    PORT
      LAYER M5 ;
        RECT  134.112 0 134.136 0.084 ;
    END
  END xl2[8]
  PIN xl2[90]
    DIRECTION INPUT ;
    USE SIGNAL ;
    PORT
      LAYER M5 ;
        RECT  153.504 0 153.528 0.084 ;
    END
  END xl2[90]
  PIN xl2[91]
    DIRECTION INPUT ;
    USE SIGNAL ;
    PORT
      LAYER M5 ;
        RECT  153.744 0 153.768 0.084 ;
    END
  END xl2[91]
  PIN xl2[92]
    DIRECTION INPUT ;
    USE SIGNAL ;
    PORT
      LAYER M5 ;
        RECT  153.936 0 153.96 0.084 ;
    END
  END xl2[92]
  PIN xl2[93]
    DIRECTION INPUT ;
    USE SIGNAL ;
    PORT
      LAYER M5 ;
        RECT  154.176 0 154.2 0.084 ;
    END
  END xl2[93]
  PIN xl2[94]
    DIRECTION INPUT ;
    USE SIGNAL ;
    PORT
      LAYER M5 ;
        RECT  154.416 0 154.44 0.084 ;
    END
  END xl2[94]
  PIN xl2[95]
    DIRECTION INPUT ;
    USE SIGNAL ;
    PORT
      LAYER M5 ;
        RECT  154.656 0 154.68 0.084 ;
    END
  END xl2[95]
  PIN xl2[96]
    DIRECTION INPUT ;
    USE SIGNAL ;
    PORT
      LAYER M5 ;
        RECT  154.896 0 154.92 0.084 ;
    END
  END xl2[96]
  PIN xl2[97]
    DIRECTION INPUT ;
    USE SIGNAL ;
    PORT
      LAYER M5 ;
        RECT  155.136 0 155.16 0.084 ;
    END
  END xl2[97]
  PIN xl2[98]
    DIRECTION INPUT ;
    USE SIGNAL ;
    PORT
      LAYER M5 ;
        RECT  155.376 0 155.4 0.084 ;
    END
  END xl2[98]
  PIN xl2[99]
    DIRECTION INPUT ;
    USE SIGNAL ;
    PORT
      LAYER M5 ;
        RECT  155.616 0 155.64 0.084 ;
    END
  END xl2[99]
  PIN xl2[9]
    DIRECTION INPUT ;
    USE SIGNAL ;
    PORT
      LAYER M5 ;
        RECT  134.352 0 134.376 0.084 ;
    END
  END xl2[9]
  PIN xl3[0]
    DIRECTION INPUT ;
    USE SIGNAL ;
    PORT
      LAYER M5 ;
        RECT  197.376 0 197.4 0.084 ;
    END
  END xl3[0]
  PIN xl3[100]
    DIRECTION INPUT ;
    USE SIGNAL ;
    PORT
      LAYER M5 ;
        RECT  220.992 0 221.016 0.084 ;
    END
  END xl3[100]
  PIN xl3[101]
    DIRECTION INPUT ;
    USE SIGNAL ;
    PORT
      LAYER M5 ;
        RECT  221.232 0 221.256 0.084 ;
    END
  END xl3[101]
  PIN xl3[102]
    DIRECTION INPUT ;
    USE SIGNAL ;
    PORT
      LAYER M5 ;
        RECT  221.424 0 221.448 0.084 ;
    END
  END xl3[102]
  PIN xl3[103]
    DIRECTION INPUT ;
    USE SIGNAL ;
    PORT
      LAYER M5 ;
        RECT  221.664 0 221.688 0.084 ;
    END
  END xl3[103]
  PIN xl3[104]
    DIRECTION INPUT ;
    USE SIGNAL ;
    PORT
      LAYER M5 ;
        RECT  221.904 0 221.928 0.084 ;
    END
  END xl3[104]
  PIN xl3[105]
    DIRECTION INPUT ;
    USE SIGNAL ;
    PORT
      LAYER M5 ;
        RECT  222.144 0 222.168 0.084 ;
    END
  END xl3[105]
  PIN xl3[106]
    DIRECTION INPUT ;
    USE SIGNAL ;
    PORT
      LAYER M5 ;
        RECT  222.384 0 222.408 0.084 ;
    END
  END xl3[106]
  PIN xl3[107]
    DIRECTION INPUT ;
    USE SIGNAL ;
    PORT
      LAYER M5 ;
        RECT  222.624 0 222.648 0.084 ;
    END
  END xl3[107]
  PIN xl3[108]
    DIRECTION INPUT ;
    USE SIGNAL ;
    PORT
      LAYER M5 ;
        RECT  222.864 0 222.888 0.084 ;
    END
  END xl3[108]
  PIN xl3[109]
    DIRECTION INPUT ;
    USE SIGNAL ;
    PORT
      LAYER M5 ;
        RECT  223.104 0 223.128 0.084 ;
    END
  END xl3[109]
  PIN xl3[10]
    DIRECTION INPUT ;
    USE SIGNAL ;
    PORT
      LAYER M5 ;
        RECT  199.728 0 199.752 0.084 ;
    END
  END xl3[10]
  PIN xl3[110]
    DIRECTION INPUT ;
    USE SIGNAL ;
    PORT
      LAYER M5 ;
        RECT  223.344 0 223.368 0.084 ;
    END
  END xl3[110]
  PIN xl3[111]
    DIRECTION INPUT ;
    USE SIGNAL ;
    PORT
      LAYER M5 ;
        RECT  223.584 0 223.608 0.084 ;
    END
  END xl3[111]
  PIN xl3[112]
    DIRECTION INPUT ;
    USE SIGNAL ;
    PORT
      LAYER M5 ;
        RECT  223.824 0 223.848 0.084 ;
    END
  END xl3[112]
  PIN xl3[113]
    DIRECTION INPUT ;
    USE SIGNAL ;
    PORT
      LAYER M5 ;
        RECT  224.064 0 224.088 0.084 ;
    END
  END xl3[113]
  PIN xl3[114]
    DIRECTION INPUT ;
    USE SIGNAL ;
    PORT
      LAYER M5 ;
        RECT  224.256 0 224.28 0.084 ;
    END
  END xl3[114]
  PIN xl3[115]
    DIRECTION INPUT ;
    USE SIGNAL ;
    PORT
      LAYER M5 ;
        RECT  224.496 0 224.52 0.084 ;
    END
  END xl3[115]
  PIN xl3[116]
    DIRECTION INPUT ;
    USE SIGNAL ;
    PORT
      LAYER M5 ;
        RECT  224.736 0 224.76 0.084 ;
    END
  END xl3[116]
  PIN xl3[117]
    DIRECTION INPUT ;
    USE SIGNAL ;
    PORT
      LAYER M5 ;
        RECT  224.976 0 225 0.084 ;
    END
  END xl3[117]
  PIN xl3[118]
    DIRECTION INPUT ;
    USE SIGNAL ;
    PORT
      LAYER M5 ;
        RECT  225.216 0 225.24 0.084 ;
    END
  END xl3[118]
  PIN xl3[119]
    DIRECTION INPUT ;
    USE SIGNAL ;
    PORT
      LAYER M5 ;
        RECT  225.456 0 225.48 0.084 ;
    END
  END xl3[119]
  PIN xl3[11]
    DIRECTION INPUT ;
    USE SIGNAL ;
    PORT
      LAYER M5 ;
        RECT  199.968 0 199.992 0.084 ;
    END
  END xl3[11]
  PIN xl3[120]
    DIRECTION INPUT ;
    USE SIGNAL ;
    PORT
      LAYER M5 ;
        RECT  225.696 0 225.72 0.084 ;
    END
  END xl3[120]
  PIN xl3[121]
    DIRECTION INPUT ;
    USE SIGNAL ;
    PORT
      LAYER M5 ;
        RECT  225.936 0 225.96 0.084 ;
    END
  END xl3[121]
  PIN xl3[122]
    DIRECTION INPUT ;
    USE SIGNAL ;
    PORT
      LAYER M5 ;
        RECT  226.176 0 226.2 0.084 ;
    END
  END xl3[122]
  PIN xl3[123]
    DIRECTION INPUT ;
    USE SIGNAL ;
    PORT
      LAYER M5 ;
        RECT  226.416 0 226.44 0.084 ;
    END
  END xl3[123]
  PIN xl3[124]
    DIRECTION INPUT ;
    USE SIGNAL ;
    PORT
      LAYER M5 ;
        RECT  226.656 0 226.68 0.084 ;
    END
  END xl3[124]
  PIN xl3[125]
    DIRECTION INPUT ;
    USE SIGNAL ;
    PORT
      LAYER M5 ;
        RECT  226.896 0 226.92 0.084 ;
    END
  END xl3[125]
  PIN xl3[126]
    DIRECTION INPUT ;
    USE SIGNAL ;
    PORT
      LAYER M5 ;
        RECT  227.088 0 227.112 0.084 ;
    END
  END xl3[126]
  PIN xl3[127]
    DIRECTION INPUT ;
    USE SIGNAL ;
    PORT
      LAYER M5 ;
        RECT  227.328 0 227.352 0.084 ;
    END
  END xl3[127]
  PIN xl3[128]
    DIRECTION INPUT ;
    USE SIGNAL ;
    PORT
      LAYER M5 ;
        RECT  227.568 0 227.592 0.084 ;
    END
  END xl3[128]
  PIN xl3[129]
    DIRECTION INPUT ;
    USE SIGNAL ;
    PORT
      LAYER M5 ;
        RECT  227.808 0 227.832 0.084 ;
    END
  END xl3[129]
  PIN xl3[12]
    DIRECTION INPUT ;
    USE SIGNAL ;
    PORT
      LAYER M5 ;
        RECT  200.208 0 200.232 0.084 ;
    END
  END xl3[12]
  PIN xl3[130]
    DIRECTION INPUT ;
    USE SIGNAL ;
    PORT
      LAYER M5 ;
        RECT  228.048 0 228.072 0.084 ;
    END
  END xl3[130]
  PIN xl3[131]
    DIRECTION INPUT ;
    USE SIGNAL ;
    PORT
      LAYER M5 ;
        RECT  228.288 0 228.312 0.084 ;
    END
  END xl3[131]
  PIN xl3[132]
    DIRECTION INPUT ;
    USE SIGNAL ;
    PORT
      LAYER M5 ;
        RECT  228.528 0 228.552 0.084 ;
    END
  END xl3[132]
  PIN xl3[133]
    DIRECTION INPUT ;
    USE SIGNAL ;
    PORT
      LAYER M5 ;
        RECT  228.768 0 228.792 0.084 ;
    END
  END xl3[133]
  PIN xl3[134]
    DIRECTION INPUT ;
    USE SIGNAL ;
    PORT
      LAYER M5 ;
        RECT  229.008 0 229.032 0.084 ;
    END
  END xl3[134]
  PIN xl3[135]
    DIRECTION INPUT ;
    USE SIGNAL ;
    PORT
      LAYER M5 ;
        RECT  229.248 0 229.272 0.084 ;
    END
  END xl3[135]
  PIN xl3[136]
    DIRECTION INPUT ;
    USE SIGNAL ;
    PORT
      LAYER M5 ;
        RECT  229.488 0 229.512 0.084 ;
    END
  END xl3[136]
  PIN xl3[137]
    DIRECTION INPUT ;
    USE SIGNAL ;
    PORT
      LAYER M5 ;
        RECT  229.728 0 229.752 0.084 ;
    END
  END xl3[137]
  PIN xl3[138]
    DIRECTION INPUT ;
    USE SIGNAL ;
    PORT
      LAYER M5 ;
        RECT  229.92 0 229.944 0.084 ;
    END
  END xl3[138]
  PIN xl3[139]
    DIRECTION INPUT ;
    USE SIGNAL ;
    PORT
      LAYER M5 ;
        RECT  230.16 0 230.184 0.084 ;
    END
  END xl3[139]
  PIN xl3[13]
    DIRECTION INPUT ;
    USE SIGNAL ;
    PORT
      LAYER M5 ;
        RECT  200.448 0 200.472 0.084 ;
    END
  END xl3[13]
  PIN xl3[140]
    DIRECTION INPUT ;
    USE SIGNAL ;
    PORT
      LAYER M5 ;
        RECT  230.4 0 230.424 0.084 ;
    END
  END xl3[140]
  PIN xl3[141]
    DIRECTION INPUT ;
    USE SIGNAL ;
    PORT
      LAYER M5 ;
        RECT  230.64 0 230.664 0.084 ;
    END
  END xl3[141]
  PIN xl3[142]
    DIRECTION INPUT ;
    USE SIGNAL ;
    PORT
      LAYER M5 ;
        RECT  230.88 0 230.904 0.084 ;
    END
  END xl3[142]
  PIN xl3[143]
    DIRECTION INPUT ;
    USE SIGNAL ;
    PORT
      LAYER M5 ;
        RECT  231.12 0 231.144 0.084 ;
    END
  END xl3[143]
  PIN xl3[144]
    DIRECTION INPUT ;
    USE SIGNAL ;
    PORT
      LAYER M5 ;
        RECT  231.36 0 231.384 0.084 ;
    END
  END xl3[144]
  PIN xl3[145]
    DIRECTION INPUT ;
    USE SIGNAL ;
    PORT
      LAYER M5 ;
        RECT  231.6 0 231.624 0.084 ;
    END
  END xl3[145]
  PIN xl3[146]
    DIRECTION INPUT ;
    USE SIGNAL ;
    PORT
      LAYER M5 ;
        RECT  231.84 0 231.864 0.084 ;
    END
  END xl3[146]
  PIN xl3[147]
    DIRECTION INPUT ;
    USE SIGNAL ;
    PORT
      LAYER M5 ;
        RECT  232.08 0 232.104 0.084 ;
    END
  END xl3[147]
  PIN xl3[148]
    DIRECTION INPUT ;
    USE SIGNAL ;
    PORT
      LAYER M5 ;
        RECT  232.32 0 232.344 0.084 ;
    END
  END xl3[148]
  PIN xl3[149]
    DIRECTION INPUT ;
    USE SIGNAL ;
    PORT
      LAYER M5 ;
        RECT  232.56 0 232.584 0.084 ;
    END
  END xl3[149]
  PIN xl3[14]
    DIRECTION INPUT ;
    USE SIGNAL ;
    PORT
      LAYER M5 ;
        RECT  200.688 0 200.712 0.084 ;
    END
  END xl3[14]
  PIN xl3[150]
    DIRECTION INPUT ;
    USE SIGNAL ;
    PORT
      LAYER M5 ;
        RECT  232.752 0 232.776 0.084 ;
    END
  END xl3[150]
  PIN xl3[151]
    DIRECTION INPUT ;
    USE SIGNAL ;
    PORT
      LAYER M5 ;
        RECT  232.992 0 233.016 0.084 ;
    END
  END xl3[151]
  PIN xl3[152]
    DIRECTION INPUT ;
    USE SIGNAL ;
    PORT
      LAYER M5 ;
        RECT  233.232 0 233.256 0.084 ;
    END
  END xl3[152]
  PIN xl3[153]
    DIRECTION INPUT ;
    USE SIGNAL ;
    PORT
      LAYER M5 ;
        RECT  233.472 0 233.496 0.084 ;
    END
  END xl3[153]
  PIN xl3[154]
    DIRECTION INPUT ;
    USE SIGNAL ;
    PORT
      LAYER M5 ;
        RECT  233.712 0 233.736 0.084 ;
    END
  END xl3[154]
  PIN xl3[155]
    DIRECTION INPUT ;
    USE SIGNAL ;
    PORT
      LAYER M5 ;
        RECT  233.952 0 233.976 0.084 ;
    END
  END xl3[155]
  PIN xl3[156]
    DIRECTION INPUT ;
    USE SIGNAL ;
    PORT
      LAYER M5 ;
        RECT  234.192 0 234.216 0.084 ;
    END
  END xl3[156]
  PIN xl3[157]
    DIRECTION INPUT ;
    USE SIGNAL ;
    PORT
      LAYER M5 ;
        RECT  234.432 0 234.456 0.084 ;
    END
  END xl3[157]
  PIN xl3[158]
    DIRECTION INPUT ;
    USE SIGNAL ;
    PORT
      LAYER M5 ;
        RECT  234.672 0 234.696 0.084 ;
    END
  END xl3[158]
  PIN xl3[159]
    DIRECTION INPUT ;
    USE SIGNAL ;
    PORT
      LAYER M5 ;
        RECT  234.912 0 234.936 0.084 ;
    END
  END xl3[159]
  PIN xl3[15]
    DIRECTION INPUT ;
    USE SIGNAL ;
    PORT
      LAYER M5 ;
        RECT  200.928 0 200.952 0.084 ;
    END
  END xl3[15]
  PIN xl3[160]
    DIRECTION INPUT ;
    USE SIGNAL ;
    PORT
      LAYER M5 ;
        RECT  235.152 0 235.176 0.084 ;
    END
  END xl3[160]
  PIN xl3[161]
    DIRECTION INPUT ;
    USE SIGNAL ;
    PORT
      LAYER M5 ;
        RECT  235.392 0 235.416 0.084 ;
    END
  END xl3[161]
  PIN xl3[162]
    DIRECTION INPUT ;
    USE SIGNAL ;
    PORT
      LAYER M5 ;
        RECT  235.584 0 235.608 0.084 ;
    END
  END xl3[162]
  PIN xl3[163]
    DIRECTION INPUT ;
    USE SIGNAL ;
    PORT
      LAYER M5 ;
        RECT  235.824 0 235.848 0.084 ;
    END
  END xl3[163]
  PIN xl3[164]
    DIRECTION INPUT ;
    USE SIGNAL ;
    PORT
      LAYER M5 ;
        RECT  236.064 0 236.088 0.084 ;
    END
  END xl3[164]
  PIN xl3[165]
    DIRECTION INPUT ;
    USE SIGNAL ;
    PORT
      LAYER M5 ;
        RECT  236.304 0 236.328 0.084 ;
    END
  END xl3[165]
  PIN xl3[166]
    DIRECTION INPUT ;
    USE SIGNAL ;
    PORT
      LAYER M5 ;
        RECT  236.544 0 236.568 0.084 ;
    END
  END xl3[166]
  PIN xl3[167]
    DIRECTION INPUT ;
    USE SIGNAL ;
    PORT
      LAYER M5 ;
        RECT  236.784 0 236.808 0.084 ;
    END
  END xl3[167]
  PIN xl3[168]
    DIRECTION INPUT ;
    USE SIGNAL ;
    PORT
      LAYER M5 ;
        RECT  237.024 0 237.048 0.084 ;
    END
  END xl3[168]
  PIN xl3[169]
    DIRECTION INPUT ;
    USE SIGNAL ;
    PORT
      LAYER M5 ;
        RECT  237.264 0 237.288 0.084 ;
    END
  END xl3[169]
  PIN xl3[16]
    DIRECTION INPUT ;
    USE SIGNAL ;
    PORT
      LAYER M5 ;
        RECT  201.168 0 201.192 0.084 ;
    END
  END xl3[16]
  PIN xl3[170]
    DIRECTION INPUT ;
    USE SIGNAL ;
    PORT
      LAYER M5 ;
        RECT  237.504 0 237.528 0.084 ;
    END
  END xl3[170]
  PIN xl3[171]
    DIRECTION INPUT ;
    USE SIGNAL ;
    PORT
      LAYER M5 ;
        RECT  237.744 0 237.768 0.084 ;
    END
  END xl3[171]
  PIN xl3[172]
    DIRECTION INPUT ;
    USE SIGNAL ;
    PORT
      LAYER M5 ;
        RECT  237.984 0 238.008 0.084 ;
    END
  END xl3[172]
  PIN xl3[173]
    DIRECTION INPUT ;
    USE SIGNAL ;
    PORT
      LAYER M5 ;
        RECT  238.224 0 238.248 0.084 ;
    END
  END xl3[173]
  PIN xl3[174]
    DIRECTION INPUT ;
    USE SIGNAL ;
    PORT
      LAYER M5 ;
        RECT  238.416 0 238.44 0.084 ;
    END
  END xl3[174]
  PIN xl3[175]
    DIRECTION INPUT ;
    USE SIGNAL ;
    PORT
      LAYER M5 ;
        RECT  238.656 0 238.68 0.084 ;
    END
  END xl3[175]
  PIN xl3[176]
    DIRECTION INPUT ;
    USE SIGNAL ;
    PORT
      LAYER M5 ;
        RECT  238.896 0 238.92 0.084 ;
    END
  END xl3[176]
  PIN xl3[177]
    DIRECTION INPUT ;
    USE SIGNAL ;
    PORT
      LAYER M5 ;
        RECT  239.136 0 239.16 0.084 ;
    END
  END xl3[177]
  PIN xl3[178]
    DIRECTION INPUT ;
    USE SIGNAL ;
    PORT
      LAYER M5 ;
        RECT  239.376 0 239.4 0.084 ;
    END
  END xl3[178]
  PIN xl3[179]
    DIRECTION INPUT ;
    USE SIGNAL ;
    PORT
      LAYER M5 ;
        RECT  239.616 0 239.64 0.084 ;
    END
  END xl3[179]
  PIN xl3[17]
    DIRECTION INPUT ;
    USE SIGNAL ;
    PORT
      LAYER M5 ;
        RECT  201.408 0 201.432 0.084 ;
    END
  END xl3[17]
  PIN xl3[180]
    DIRECTION INPUT ;
    USE SIGNAL ;
    PORT
      LAYER M5 ;
        RECT  239.856 0 239.88 0.084 ;
    END
  END xl3[180]
  PIN xl3[181]
    DIRECTION INPUT ;
    USE SIGNAL ;
    PORT
      LAYER M5 ;
        RECT  240.096 0 240.12 0.084 ;
    END
  END xl3[181]
  PIN xl3[182]
    DIRECTION INPUT ;
    USE SIGNAL ;
    PORT
      LAYER M5 ;
        RECT  240.336 0 240.36 0.084 ;
    END
  END xl3[182]
  PIN xl3[183]
    DIRECTION INPUT ;
    USE SIGNAL ;
    PORT
      LAYER M5 ;
        RECT  240.576 0 240.6 0.084 ;
    END
  END xl3[183]
  PIN xl3[184]
    DIRECTION INPUT ;
    USE SIGNAL ;
    PORT
      LAYER M5 ;
        RECT  240.816 0 240.84 0.084 ;
    END
  END xl3[184]
  PIN xl3[185]
    DIRECTION INPUT ;
    USE SIGNAL ;
    PORT
      LAYER M5 ;
        RECT  241.008 0 241.032 0.084 ;
    END
  END xl3[185]
  PIN xl3[186]
    DIRECTION INPUT ;
    USE SIGNAL ;
    PORT
      LAYER M5 ;
        RECT  241.248 0 241.272 0.084 ;
    END
  END xl3[186]
  PIN xl3[187]
    DIRECTION INPUT ;
    USE SIGNAL ;
    PORT
      LAYER M5 ;
        RECT  241.488 0 241.512 0.084 ;
    END
  END xl3[187]
  PIN xl3[188]
    DIRECTION INPUT ;
    USE SIGNAL ;
    PORT
      LAYER M5 ;
        RECT  241.728 0 241.752 0.084 ;
    END
  END xl3[188]
  PIN xl3[189]
    DIRECTION INPUT ;
    USE SIGNAL ;
    PORT
      LAYER M5 ;
        RECT  241.968 0 241.992 0.084 ;
    END
  END xl3[189]
  PIN xl3[18]
    DIRECTION INPUT ;
    USE SIGNAL ;
    PORT
      LAYER M5 ;
        RECT  201.6 0 201.624 0.084 ;
    END
  END xl3[18]
  PIN xl3[190]
    DIRECTION INPUT ;
    USE SIGNAL ;
    PORT
      LAYER M5 ;
        RECT  242.208 0 242.232 0.084 ;
    END
  END xl3[190]
  PIN xl3[191]
    DIRECTION INPUT ;
    USE SIGNAL ;
    PORT
      LAYER M5 ;
        RECT  242.448 0 242.472 0.084 ;
    END
  END xl3[191]
  PIN xl3[192]
    DIRECTION INPUT ;
    USE SIGNAL ;
    PORT
      LAYER M5 ;
        RECT  242.688 0 242.712 0.084 ;
    END
  END xl3[192]
  PIN xl3[193]
    DIRECTION INPUT ;
    USE SIGNAL ;
    PORT
      LAYER M5 ;
        RECT  242.928 0 242.952 0.084 ;
    END
  END xl3[193]
  PIN xl3[194]
    DIRECTION INPUT ;
    USE SIGNAL ;
    PORT
      LAYER M5 ;
        RECT  243.168 0 243.192 0.084 ;
    END
  END xl3[194]
  PIN xl3[195]
    DIRECTION INPUT ;
    USE SIGNAL ;
    PORT
      LAYER M5 ;
        RECT  243.408 0 243.432 0.084 ;
    END
  END xl3[195]
  PIN xl3[196]
    DIRECTION INPUT ;
    USE SIGNAL ;
    PORT
      LAYER M5 ;
        RECT  243.648 0 243.672 0.084 ;
    END
  END xl3[196]
  PIN xl3[197]
    DIRECTION INPUT ;
    USE SIGNAL ;
    PORT
      LAYER M5 ;
        RECT  243.84 0 243.864 0.084 ;
    END
  END xl3[197]
  PIN xl3[198]
    DIRECTION INPUT ;
    USE SIGNAL ;
    PORT
      LAYER M5 ;
        RECT  244.08 0 244.104 0.084 ;
    END
  END xl3[198]
  PIN xl3[199]
    DIRECTION INPUT ;
    USE SIGNAL ;
    PORT
      LAYER M5 ;
        RECT  244.32 0 244.344 0.084 ;
    END
  END xl3[199]
  PIN xl3[19]
    DIRECTION INPUT ;
    USE SIGNAL ;
    PORT
      LAYER M5 ;
        RECT  201.84 0 201.864 0.084 ;
    END
  END xl3[19]
  PIN xl3[1]
    DIRECTION INPUT ;
    USE SIGNAL ;
    PORT
      LAYER M5 ;
        RECT  197.616 0 197.64 0.084 ;
    END
  END xl3[1]
  PIN xl3[200]
    DIRECTION INPUT ;
    USE SIGNAL ;
    PORT
      LAYER M5 ;
        RECT  244.56 0 244.584 0.084 ;
    END
  END xl3[200]
  PIN xl3[201]
    DIRECTION INPUT ;
    USE SIGNAL ;
    PORT
      LAYER M5 ;
        RECT  244.8 0 244.824 0.084 ;
    END
  END xl3[201]
  PIN xl3[202]
    DIRECTION INPUT ;
    USE SIGNAL ;
    PORT
      LAYER M5 ;
        RECT  245.04 0 245.064 0.084 ;
    END
  END xl3[202]
  PIN xl3[203]
    DIRECTION INPUT ;
    USE SIGNAL ;
    PORT
      LAYER M5 ;
        RECT  245.28 0 245.304 0.084 ;
    END
  END xl3[203]
  PIN xl3[204]
    DIRECTION INPUT ;
    USE SIGNAL ;
    PORT
      LAYER M5 ;
        RECT  245.52 0 245.544 0.084 ;
    END
  END xl3[204]
  PIN xl3[205]
    DIRECTION INPUT ;
    USE SIGNAL ;
    PORT
      LAYER M5 ;
        RECT  245.76 0 245.784 0.084 ;
    END
  END xl3[205]
  PIN xl3[206]
    DIRECTION INPUT ;
    USE SIGNAL ;
    PORT
      LAYER M5 ;
        RECT  246 0 246.024 0.084 ;
    END
  END xl3[206]
  PIN xl3[207]
    DIRECTION INPUT ;
    USE SIGNAL ;
    PORT
      LAYER M5 ;
        RECT  246.24 0 246.264 0.084 ;
    END
  END xl3[207]
  PIN xl3[208]
    DIRECTION INPUT ;
    USE SIGNAL ;
    PORT
      LAYER M5 ;
        RECT  246.48 0 246.504 0.084 ;
    END
  END xl3[208]
  PIN xl3[209]
    DIRECTION INPUT ;
    USE SIGNAL ;
    PORT
      LAYER M5 ;
        RECT  246.672 0 246.696 0.084 ;
    END
  END xl3[209]
  PIN xl3[20]
    DIRECTION INPUT ;
    USE SIGNAL ;
    PORT
      LAYER M5 ;
        RECT  202.08 0 202.104 0.084 ;
    END
  END xl3[20]
  PIN xl3[210]
    DIRECTION INPUT ;
    USE SIGNAL ;
    PORT
      LAYER M5 ;
        RECT  246.912 0 246.936 0.084 ;
    END
  END xl3[210]
  PIN xl3[211]
    DIRECTION INPUT ;
    USE SIGNAL ;
    PORT
      LAYER M5 ;
        RECT  247.152 0 247.176 0.084 ;
    END
  END xl3[211]
  PIN xl3[212]
    DIRECTION INPUT ;
    USE SIGNAL ;
    PORT
      LAYER M5 ;
        RECT  247.392 0 247.416 0.084 ;
    END
  END xl3[212]
  PIN xl3[213]
    DIRECTION INPUT ;
    USE SIGNAL ;
    PORT
      LAYER M5 ;
        RECT  247.632 0 247.656 0.084 ;
    END
  END xl3[213]
  PIN xl3[214]
    DIRECTION INPUT ;
    USE SIGNAL ;
    PORT
      LAYER M5 ;
        RECT  247.872 0 247.896 0.084 ;
    END
  END xl3[214]
  PIN xl3[215]
    DIRECTION INPUT ;
    USE SIGNAL ;
    PORT
      LAYER M5 ;
        RECT  248.112 0 248.136 0.084 ;
    END
  END xl3[215]
  PIN xl3[216]
    DIRECTION INPUT ;
    USE SIGNAL ;
    PORT
      LAYER M5 ;
        RECT  248.352 0 248.376 0.084 ;
    END
  END xl3[216]
  PIN xl3[217]
    DIRECTION INPUT ;
    USE SIGNAL ;
    PORT
      LAYER M5 ;
        RECT  248.592 0 248.616 0.084 ;
    END
  END xl3[217]
  PIN xl3[218]
    DIRECTION INPUT ;
    USE SIGNAL ;
    PORT
      LAYER M5 ;
        RECT  248.832 0 248.856 0.084 ;
    END
  END xl3[218]
  PIN xl3[219]
    DIRECTION INPUT ;
    USE SIGNAL ;
    PORT
      LAYER M5 ;
        RECT  249.072 0 249.096 0.084 ;
    END
  END xl3[219]
  PIN xl3[21]
    DIRECTION INPUT ;
    USE SIGNAL ;
    PORT
      LAYER M5 ;
        RECT  202.32 0 202.344 0.084 ;
    END
  END xl3[21]
  PIN xl3[220]
    DIRECTION INPUT ;
    USE SIGNAL ;
    PORT
      LAYER M5 ;
        RECT  249.312 0 249.336 0.084 ;
    END
  END xl3[220]
  PIN xl3[221]
    DIRECTION INPUT ;
    USE SIGNAL ;
    PORT
      LAYER M5 ;
        RECT  249.504 0 249.528 0.084 ;
    END
  END xl3[221]
  PIN xl3[222]
    DIRECTION INPUT ;
    USE SIGNAL ;
    PORT
      LAYER M5 ;
        RECT  249.744 0 249.768 0.084 ;
    END
  END xl3[222]
  PIN xl3[223]
    DIRECTION INPUT ;
    USE SIGNAL ;
    PORT
      LAYER M5 ;
        RECT  249.984 0 250.008 0.084 ;
    END
  END xl3[223]
  PIN xl3[224]
    DIRECTION INPUT ;
    USE SIGNAL ;
    PORT
      LAYER M5 ;
        RECT  250.224 0 250.248 0.084 ;
    END
  END xl3[224]
  PIN xl3[225]
    DIRECTION INPUT ;
    USE SIGNAL ;
    PORT
      LAYER M5 ;
        RECT  250.464 0 250.488 0.084 ;
    END
  END xl3[225]
  PIN xl3[226]
    DIRECTION INPUT ;
    USE SIGNAL ;
    PORT
      LAYER M5 ;
        RECT  250.704 0 250.728 0.084 ;
    END
  END xl3[226]
  PIN xl3[227]
    DIRECTION INPUT ;
    USE SIGNAL ;
    PORT
      LAYER M5 ;
        RECT  250.944 0 250.968 0.084 ;
    END
  END xl3[227]
  PIN xl3[228]
    DIRECTION INPUT ;
    USE SIGNAL ;
    PORT
      LAYER M5 ;
        RECT  251.184 0 251.208 0.084 ;
    END
  END xl3[228]
  PIN xl3[229]
    DIRECTION INPUT ;
    USE SIGNAL ;
    PORT
      LAYER M5 ;
        RECT  251.424 0 251.448 0.084 ;
    END
  END xl3[229]
  PIN xl3[22]
    DIRECTION INPUT ;
    USE SIGNAL ;
    PORT
      LAYER M5 ;
        RECT  202.56 0 202.584 0.084 ;
    END
  END xl3[22]
  PIN xl3[230]
    DIRECTION INPUT ;
    USE SIGNAL ;
    PORT
      LAYER M5 ;
        RECT  251.664 0 251.688 0.084 ;
    END
  END xl3[230]
  PIN xl3[231]
    DIRECTION INPUT ;
    USE SIGNAL ;
    PORT
      LAYER M5 ;
        RECT  251.904 0 251.928 0.084 ;
    END
  END xl3[231]
  PIN xl3[232]
    DIRECTION INPUT ;
    USE SIGNAL ;
    PORT
      LAYER M5 ;
        RECT  252.144 0 252.168 0.084 ;
    END
  END xl3[232]
  PIN xl3[233]
    DIRECTION INPUT ;
    USE SIGNAL ;
    PORT
      LAYER M5 ;
        RECT  252.336 0 252.36 0.084 ;
    END
  END xl3[233]
  PIN xl3[234]
    DIRECTION INPUT ;
    USE SIGNAL ;
    PORT
      LAYER M5 ;
        RECT  252.576 0 252.6 0.084 ;
    END
  END xl3[234]
  PIN xl3[235]
    DIRECTION INPUT ;
    USE SIGNAL ;
    PORT
      LAYER M5 ;
        RECT  252.816 0 252.84 0.084 ;
    END
  END xl3[235]
  PIN xl3[236]
    DIRECTION INPUT ;
    USE SIGNAL ;
    PORT
      LAYER M5 ;
        RECT  253.056 0 253.08 0.084 ;
    END
  END xl3[236]
  PIN xl3[237]
    DIRECTION INPUT ;
    USE SIGNAL ;
    PORT
      LAYER M5 ;
        RECT  253.296 0 253.32 0.084 ;
    END
  END xl3[237]
  PIN xl3[238]
    DIRECTION INPUT ;
    USE SIGNAL ;
    PORT
      LAYER M5 ;
        RECT  253.536 0 253.56 0.084 ;
    END
  END xl3[238]
  PIN xl3[239]
    DIRECTION INPUT ;
    USE SIGNAL ;
    PORT
      LAYER M5 ;
        RECT  253.776 0 253.8 0.084 ;
    END
  END xl3[239]
  PIN xl3[23]
    DIRECTION INPUT ;
    USE SIGNAL ;
    PORT
      LAYER M5 ;
        RECT  202.8 0 202.824 0.084 ;
    END
  END xl3[23]
  PIN xl3[240]
    DIRECTION INPUT ;
    USE SIGNAL ;
    PORT
      LAYER M5 ;
        RECT  254.016 0 254.04 0.084 ;
    END
  END xl3[240]
  PIN xl3[241]
    DIRECTION INPUT ;
    USE SIGNAL ;
    PORT
      LAYER M5 ;
        RECT  254.256 0 254.28 0.084 ;
    END
  END xl3[241]
  PIN xl3[242]
    DIRECTION INPUT ;
    USE SIGNAL ;
    PORT
      LAYER M5 ;
        RECT  254.496 0 254.52 0.084 ;
    END
  END xl3[242]
  PIN xl3[243]
    DIRECTION INPUT ;
    USE SIGNAL ;
    PORT
      LAYER M5 ;
        RECT  254.736 0 254.76 0.084 ;
    END
  END xl3[243]
  PIN xl3[244]
    DIRECTION INPUT ;
    USE SIGNAL ;
    PORT
      LAYER M5 ;
        RECT  254.976 0 255 0.084 ;
    END
  END xl3[244]
  PIN xl3[245]
    DIRECTION INPUT ;
    USE SIGNAL ;
    PORT
      LAYER M5 ;
        RECT  255.168 0 255.192 0.084 ;
    END
  END xl3[245]
  PIN xl3[246]
    DIRECTION INPUT ;
    USE SIGNAL ;
    PORT
      LAYER M5 ;
        RECT  255.408 0 255.432 0.084 ;
    END
  END xl3[246]
  PIN xl3[247]
    DIRECTION INPUT ;
    USE SIGNAL ;
    PORT
      LAYER M5 ;
        RECT  255.648 0 255.672 0.084 ;
    END
  END xl3[247]
  PIN xl3[248]
    DIRECTION INPUT ;
    USE SIGNAL ;
    PORT
      LAYER M5 ;
        RECT  255.888 0 255.912 0.084 ;
    END
  END xl3[248]
  PIN xl3[249]
    DIRECTION INPUT ;
    USE SIGNAL ;
    PORT
      LAYER M5 ;
        RECT  256.128 0 256.152 0.084 ;
    END
  END xl3[249]
  PIN xl3[24]
    DIRECTION INPUT ;
    USE SIGNAL ;
    PORT
      LAYER M5 ;
        RECT  203.04 0 203.064 0.084 ;
    END
  END xl3[24]
  PIN xl3[250]
    DIRECTION INPUT ;
    USE SIGNAL ;
    PORT
      LAYER M5 ;
        RECT  256.368 0 256.392 0.084 ;
    END
  END xl3[250]
  PIN xl3[251]
    DIRECTION INPUT ;
    USE SIGNAL ;
    PORT
      LAYER M5 ;
        RECT  256.608 0 256.632 0.084 ;
    END
  END xl3[251]
  PIN xl3[252]
    DIRECTION INPUT ;
    USE SIGNAL ;
    PORT
      LAYER M5 ;
        RECT  256.848 0 256.872 0.084 ;
    END
  END xl3[252]
  PIN xl3[253]
    DIRECTION INPUT ;
    USE SIGNAL ;
    PORT
      LAYER M5 ;
        RECT  257.088 0 257.112 0.084 ;
    END
  END xl3[253]
  PIN xl3[254]
    DIRECTION INPUT ;
    USE SIGNAL ;
    PORT
      LAYER M5 ;
        RECT  257.328 0 257.352 0.084 ;
    END
  END xl3[254]
  PIN xl3[255]
    DIRECTION INPUT ;
    USE SIGNAL ;
    PORT
      LAYER M5 ;
        RECT  257.568 0 257.592 0.084 ;
    END
  END xl3[255]
  PIN xl3[256]
    DIRECTION INPUT ;
    USE SIGNAL ;
    PORT
      LAYER M5 ;
        RECT  257.808 0 257.832 0.084 ;
    END
  END xl3[256]
  PIN xl3[257]
    DIRECTION INPUT ;
    USE SIGNAL ;
    PORT
      LAYER M5 ;
        RECT  258 0 258.024 0.084 ;
    END
  END xl3[257]
  PIN xl3[258]
    DIRECTION INPUT ;
    USE SIGNAL ;
    PORT
      LAYER M5 ;
        RECT  258.24 0 258.264 0.084 ;
    END
  END xl3[258]
  PIN xl3[259]
    DIRECTION INPUT ;
    USE SIGNAL ;
    PORT
      LAYER M5 ;
        RECT  258.48 0 258.504 0.084 ;
    END
  END xl3[259]
  PIN xl3[25]
    DIRECTION INPUT ;
    USE SIGNAL ;
    PORT
      LAYER M5 ;
        RECT  203.28 0 203.304 0.084 ;
    END
  END xl3[25]
  PIN xl3[260]
    DIRECTION INPUT ;
    USE SIGNAL ;
    PORT
      LAYER M5 ;
        RECT  258.72 0 258.744 0.084 ;
    END
  END xl3[260]
  PIN xl3[261]
    DIRECTION INPUT ;
    USE SIGNAL ;
    PORT
      LAYER M5 ;
        RECT  258.96 0 258.984 0.084 ;
    END
  END xl3[261]
  PIN xl3[262]
    DIRECTION INPUT ;
    USE SIGNAL ;
    PORT
      LAYER M5 ;
        RECT  259.2 0 259.224 0.084 ;
    END
  END xl3[262]
  PIN xl3[263]
    DIRECTION INPUT ;
    USE SIGNAL ;
    PORT
      LAYER M5 ;
        RECT  259.44 0 259.464 0.084 ;
    END
  END xl3[263]
  PIN xl3[264]
    DIRECTION INPUT ;
    USE SIGNAL ;
    PORT
      LAYER M5 ;
        RECT  259.68 0 259.704 0.084 ;
    END
  END xl3[264]
  PIN xl3[265]
    DIRECTION INPUT ;
    USE SIGNAL ;
    PORT
      LAYER M5 ;
        RECT  259.92 0 259.944 0.084 ;
    END
  END xl3[265]
  PIN xl3[266]
    DIRECTION INPUT ;
    USE SIGNAL ;
    PORT
      LAYER M5 ;
        RECT  260.16 0 260.184 0.084 ;
    END
  END xl3[266]
  PIN xl3[267]
    DIRECTION INPUT ;
    USE SIGNAL ;
    PORT
      LAYER M5 ;
        RECT  260.4 0 260.424 0.084 ;
    END
  END xl3[267]
  PIN xl3[268]
    DIRECTION INPUT ;
    USE SIGNAL ;
    PORT
      LAYER M5 ;
        RECT  260.64 0 260.664 0.084 ;
    END
  END xl3[268]
  PIN xl3[269]
    DIRECTION INPUT ;
    USE SIGNAL ;
    PORT
      LAYER M5 ;
        RECT  260.832 0 260.856 0.084 ;
    END
  END xl3[269]
  PIN xl3[26]
    DIRECTION INPUT ;
    USE SIGNAL ;
    PORT
      LAYER M5 ;
        RECT  203.52 0 203.544 0.084 ;
    END
  END xl3[26]
  PIN xl3[270]
    DIRECTION INPUT ;
    USE SIGNAL ;
    PORT
      LAYER M5 ;
        RECT  261.072 0 261.096 0.084 ;
    END
  END xl3[270]
  PIN xl3[271]
    DIRECTION INPUT ;
    USE SIGNAL ;
    PORT
      LAYER M5 ;
        RECT  261.312 0 261.336 0.084 ;
    END
  END xl3[271]
  PIN xl3[272]
    DIRECTION INPUT ;
    USE SIGNAL ;
    PORT
      LAYER M5 ;
        RECT  261.552 0 261.576 0.084 ;
    END
  END xl3[272]
  PIN xl3[273]
    DIRECTION INPUT ;
    USE SIGNAL ;
    PORT
      LAYER M5 ;
        RECT  261.792 0 261.816 0.084 ;
    END
  END xl3[273]
  PIN xl3[274]
    DIRECTION INPUT ;
    USE SIGNAL ;
    PORT
      LAYER M5 ;
        RECT  262.032 0 262.056 0.084 ;
    END
  END xl3[274]
  PIN xl3[275]
    DIRECTION INPUT ;
    USE SIGNAL ;
    PORT
      LAYER M5 ;
        RECT  262.272 0 262.296 0.084 ;
    END
  END xl3[275]
  PIN xl3[27]
    DIRECTION INPUT ;
    USE SIGNAL ;
    PORT
      LAYER M5 ;
        RECT  203.76 0 203.784 0.084 ;
    END
  END xl3[27]
  PIN xl3[28]
    DIRECTION INPUT ;
    USE SIGNAL ;
    PORT
      LAYER M5 ;
        RECT  204 0 204.024 0.084 ;
    END
  END xl3[28]
  PIN xl3[29]
    DIRECTION INPUT ;
    USE SIGNAL ;
    PORT
      LAYER M5 ;
        RECT  204.24 0 204.264 0.084 ;
    END
  END xl3[29]
  PIN xl3[2]
    DIRECTION INPUT ;
    USE SIGNAL ;
    PORT
      LAYER M5 ;
        RECT  197.856 0 197.88 0.084 ;
    END
  END xl3[2]
  PIN xl3[30]
    DIRECTION INPUT ;
    USE SIGNAL ;
    PORT
      LAYER M5 ;
        RECT  204.432 0 204.456 0.084 ;
    END
  END xl3[30]
  PIN xl3[31]
    DIRECTION INPUT ;
    USE SIGNAL ;
    PORT
      LAYER M5 ;
        RECT  204.672 0 204.696 0.084 ;
    END
  END xl3[31]
  PIN xl3[32]
    DIRECTION INPUT ;
    USE SIGNAL ;
    PORT
      LAYER M5 ;
        RECT  204.912 0 204.936 0.084 ;
    END
  END xl3[32]
  PIN xl3[33]
    DIRECTION INPUT ;
    USE SIGNAL ;
    PORT
      LAYER M5 ;
        RECT  205.152 0 205.176 0.084 ;
    END
  END xl3[33]
  PIN xl3[34]
    DIRECTION INPUT ;
    USE SIGNAL ;
    PORT
      LAYER M5 ;
        RECT  205.392 0 205.416 0.084 ;
    END
  END xl3[34]
  PIN xl3[35]
    DIRECTION INPUT ;
    USE SIGNAL ;
    PORT
      LAYER M5 ;
        RECT  205.632 0 205.656 0.084 ;
    END
  END xl3[35]
  PIN xl3[36]
    DIRECTION INPUT ;
    USE SIGNAL ;
    PORT
      LAYER M5 ;
        RECT  205.872 0 205.896 0.084 ;
    END
  END xl3[36]
  PIN xl3[37]
    DIRECTION INPUT ;
    USE SIGNAL ;
    PORT
      LAYER M5 ;
        RECT  206.112 0 206.136 0.084 ;
    END
  END xl3[37]
  PIN xl3[38]
    DIRECTION INPUT ;
    USE SIGNAL ;
    PORT
      LAYER M5 ;
        RECT  206.352 0 206.376 0.084 ;
    END
  END xl3[38]
  PIN xl3[39]
    DIRECTION INPUT ;
    USE SIGNAL ;
    PORT
      LAYER M5 ;
        RECT  206.592 0 206.616 0.084 ;
    END
  END xl3[39]
  PIN xl3[3]
    DIRECTION INPUT ;
    USE SIGNAL ;
    PORT
      LAYER M5 ;
        RECT  198.096 0 198.12 0.084 ;
    END
  END xl3[3]
  PIN xl3[40]
    DIRECTION INPUT ;
    USE SIGNAL ;
    PORT
      LAYER M5 ;
        RECT  206.832 0 206.856 0.084 ;
    END
  END xl3[40]
  PIN xl3[41]
    DIRECTION INPUT ;
    USE SIGNAL ;
    PORT
      LAYER M5 ;
        RECT  207.072 0 207.096 0.084 ;
    END
  END xl3[41]
  PIN xl3[42]
    DIRECTION INPUT ;
    USE SIGNAL ;
    PORT
      LAYER M5 ;
        RECT  207.264 0 207.288 0.084 ;
    END
  END xl3[42]
  PIN xl3[43]
    DIRECTION INPUT ;
    USE SIGNAL ;
    PORT
      LAYER M5 ;
        RECT  207.504 0 207.528 0.084 ;
    END
  END xl3[43]
  PIN xl3[44]
    DIRECTION INPUT ;
    USE SIGNAL ;
    PORT
      LAYER M5 ;
        RECT  207.744 0 207.768 0.084 ;
    END
  END xl3[44]
  PIN xl3[45]
    DIRECTION INPUT ;
    USE SIGNAL ;
    PORT
      LAYER M5 ;
        RECT  207.984 0 208.008 0.084 ;
    END
  END xl3[45]
  PIN xl3[46]
    DIRECTION INPUT ;
    USE SIGNAL ;
    PORT
      LAYER M5 ;
        RECT  208.224 0 208.248 0.084 ;
    END
  END xl3[46]
  PIN xl3[47]
    DIRECTION INPUT ;
    USE SIGNAL ;
    PORT
      LAYER M5 ;
        RECT  208.464 0 208.488 0.084 ;
    END
  END xl3[47]
  PIN xl3[48]
    DIRECTION INPUT ;
    USE SIGNAL ;
    PORT
      LAYER M5 ;
        RECT  208.704 0 208.728 0.084 ;
    END
  END xl3[48]
  PIN xl3[49]
    DIRECTION INPUT ;
    USE SIGNAL ;
    PORT
      LAYER M5 ;
        RECT  208.944 0 208.968 0.084 ;
    END
  END xl3[49]
  PIN xl3[4]
    DIRECTION INPUT ;
    USE SIGNAL ;
    PORT
      LAYER M5 ;
        RECT  198.336 0 198.36 0.084 ;
    END
  END xl3[4]
  PIN xl3[50]
    DIRECTION INPUT ;
    USE SIGNAL ;
    PORT
      LAYER M5 ;
        RECT  209.184 0 209.208 0.084 ;
    END
  END xl3[50]
  PIN xl3[51]
    DIRECTION INPUT ;
    USE SIGNAL ;
    PORT
      LAYER M5 ;
        RECT  209.424 0 209.448 0.084 ;
    END
  END xl3[51]
  PIN xl3[52]
    DIRECTION INPUT ;
    USE SIGNAL ;
    PORT
      LAYER M5 ;
        RECT  209.664 0 209.688 0.084 ;
    END
  END xl3[52]
  PIN xl3[53]
    DIRECTION INPUT ;
    USE SIGNAL ;
    PORT
      LAYER M5 ;
        RECT  209.904 0 209.928 0.084 ;
    END
  END xl3[53]
  PIN xl3[54]
    DIRECTION INPUT ;
    USE SIGNAL ;
    PORT
      LAYER M5 ;
        RECT  210.096 0 210.12 0.084 ;
    END
  END xl3[54]
  PIN xl3[55]
    DIRECTION INPUT ;
    USE SIGNAL ;
    PORT
      LAYER M5 ;
        RECT  210.336 0 210.36 0.084 ;
    END
  END xl3[55]
  PIN xl3[56]
    DIRECTION INPUT ;
    USE SIGNAL ;
    PORT
      LAYER M5 ;
        RECT  210.576 0 210.6 0.084 ;
    END
  END xl3[56]
  PIN xl3[57]
    DIRECTION INPUT ;
    USE SIGNAL ;
    PORT
      LAYER M5 ;
        RECT  210.816 0 210.84 0.084 ;
    END
  END xl3[57]
  PIN xl3[58]
    DIRECTION INPUT ;
    USE SIGNAL ;
    PORT
      LAYER M5 ;
        RECT  211.056 0 211.08 0.084 ;
    END
  END xl3[58]
  PIN xl3[59]
    DIRECTION INPUT ;
    USE SIGNAL ;
    PORT
      LAYER M5 ;
        RECT  211.296 0 211.32 0.084 ;
    END
  END xl3[59]
  PIN xl3[5]
    DIRECTION INPUT ;
    USE SIGNAL ;
    PORT
      LAYER M5 ;
        RECT  198.576 0 198.6 0.084 ;
    END
  END xl3[5]
  PIN xl3[60]
    DIRECTION INPUT ;
    USE SIGNAL ;
    PORT
      LAYER M5 ;
        RECT  211.536 0 211.56 0.084 ;
    END
  END xl3[60]
  PIN xl3[61]
    DIRECTION INPUT ;
    USE SIGNAL ;
    PORT
      LAYER M5 ;
        RECT  211.776 0 211.8 0.084 ;
    END
  END xl3[61]
  PIN xl3[62]
    DIRECTION INPUT ;
    USE SIGNAL ;
    PORT
      LAYER M5 ;
        RECT  212.016 0 212.04 0.084 ;
    END
  END xl3[62]
  PIN xl3[63]
    DIRECTION INPUT ;
    USE SIGNAL ;
    PORT
      LAYER M5 ;
        RECT  212.256 0 212.28 0.084 ;
    END
  END xl3[63]
  PIN xl3[64]
    DIRECTION INPUT ;
    USE SIGNAL ;
    PORT
      LAYER M5 ;
        RECT  212.496 0 212.52 0.084 ;
    END
  END xl3[64]
  PIN xl3[65]
    DIRECTION INPUT ;
    USE SIGNAL ;
    PORT
      LAYER M5 ;
        RECT  212.736 0 212.76 0.084 ;
    END
  END xl3[65]
  PIN xl3[66]
    DIRECTION INPUT ;
    USE SIGNAL ;
    PORT
      LAYER M5 ;
        RECT  212.928 0 212.952 0.084 ;
    END
  END xl3[66]
  PIN xl3[67]
    DIRECTION INPUT ;
    USE SIGNAL ;
    PORT
      LAYER M5 ;
        RECT  213.168 0 213.192 0.084 ;
    END
  END xl3[67]
  PIN xl3[68]
    DIRECTION INPUT ;
    USE SIGNAL ;
    PORT
      LAYER M5 ;
        RECT  213.408 0 213.432 0.084 ;
    END
  END xl3[68]
  PIN xl3[69]
    DIRECTION INPUT ;
    USE SIGNAL ;
    PORT
      LAYER M5 ;
        RECT  213.648 0 213.672 0.084 ;
    END
  END xl3[69]
  PIN xl3[6]
    DIRECTION INPUT ;
    USE SIGNAL ;
    PORT
      LAYER M5 ;
        RECT  198.816 0 198.84 0.084 ;
    END
  END xl3[6]
  PIN xl3[70]
    DIRECTION INPUT ;
    USE SIGNAL ;
    PORT
      LAYER M5 ;
        RECT  213.888 0 213.912 0.084 ;
    END
  END xl3[70]
  PIN xl3[71]
    DIRECTION INPUT ;
    USE SIGNAL ;
    PORT
      LAYER M5 ;
        RECT  214.128 0 214.152 0.084 ;
    END
  END xl3[71]
  PIN xl3[72]
    DIRECTION INPUT ;
    USE SIGNAL ;
    PORT
      LAYER M5 ;
        RECT  214.368 0 214.392 0.084 ;
    END
  END xl3[72]
  PIN xl3[73]
    DIRECTION INPUT ;
    USE SIGNAL ;
    PORT
      LAYER M5 ;
        RECT  214.608 0 214.632 0.084 ;
    END
  END xl3[73]
  PIN xl3[74]
    DIRECTION INPUT ;
    USE SIGNAL ;
    PORT
      LAYER M5 ;
        RECT  214.848 0 214.872 0.084 ;
    END
  END xl3[74]
  PIN xl3[75]
    DIRECTION INPUT ;
    USE SIGNAL ;
    PORT
      LAYER M5 ;
        RECT  215.088 0 215.112 0.084 ;
    END
  END xl3[75]
  PIN xl3[76]
    DIRECTION INPUT ;
    USE SIGNAL ;
    PORT
      LAYER M5 ;
        RECT  215.328 0 215.352 0.084 ;
    END
  END xl3[76]
  PIN xl3[77]
    DIRECTION INPUT ;
    USE SIGNAL ;
    PORT
      LAYER M5 ;
        RECT  215.568 0 215.592 0.084 ;
    END
  END xl3[77]
  PIN xl3[78]
    DIRECTION INPUT ;
    USE SIGNAL ;
    PORT
      LAYER M5 ;
        RECT  215.76 0 215.784 0.084 ;
    END
  END xl3[78]
  PIN xl3[79]
    DIRECTION INPUT ;
    USE SIGNAL ;
    PORT
      LAYER M5 ;
        RECT  216 0 216.024 0.084 ;
    END
  END xl3[79]
  PIN xl3[7]
    DIRECTION INPUT ;
    USE SIGNAL ;
    PORT
      LAYER M5 ;
        RECT  199.008 0 199.032 0.084 ;
    END
  END xl3[7]
  PIN xl3[80]
    DIRECTION INPUT ;
    USE SIGNAL ;
    PORT
      LAYER M5 ;
        RECT  216.24 0 216.264 0.084 ;
    END
  END xl3[80]
  PIN xl3[81]
    DIRECTION INPUT ;
    USE SIGNAL ;
    PORT
      LAYER M5 ;
        RECT  216.48 0 216.504 0.084 ;
    END
  END xl3[81]
  PIN xl3[82]
    DIRECTION INPUT ;
    USE SIGNAL ;
    PORT
      LAYER M5 ;
        RECT  216.72 0 216.744 0.084 ;
    END
  END xl3[82]
  PIN xl3[83]
    DIRECTION INPUT ;
    USE SIGNAL ;
    PORT
      LAYER M5 ;
        RECT  216.96 0 216.984 0.084 ;
    END
  END xl3[83]
  PIN xl3[84]
    DIRECTION INPUT ;
    USE SIGNAL ;
    PORT
      LAYER M5 ;
        RECT  217.2 0 217.224 0.084 ;
    END
  END xl3[84]
  PIN xl3[85]
    DIRECTION INPUT ;
    USE SIGNAL ;
    PORT
      LAYER M5 ;
        RECT  217.44 0 217.464 0.084 ;
    END
  END xl3[85]
  PIN xl3[86]
    DIRECTION INPUT ;
    USE SIGNAL ;
    PORT
      LAYER M5 ;
        RECT  217.68 0 217.704 0.084 ;
    END
  END xl3[86]
  PIN xl3[87]
    DIRECTION INPUT ;
    USE SIGNAL ;
    PORT
      LAYER M5 ;
        RECT  217.92 0 217.944 0.084 ;
    END
  END xl3[87]
  PIN xl3[88]
    DIRECTION INPUT ;
    USE SIGNAL ;
    PORT
      LAYER M5 ;
        RECT  218.16 0 218.184 0.084 ;
    END
  END xl3[88]
  PIN xl3[89]
    DIRECTION INPUT ;
    USE SIGNAL ;
    PORT
      LAYER M5 ;
        RECT  218.4 0 218.424 0.084 ;
    END
  END xl3[89]
  PIN xl3[8]
    DIRECTION INPUT ;
    USE SIGNAL ;
    PORT
      LAYER M5 ;
        RECT  199.248 0 199.272 0.084 ;
    END
  END xl3[8]
  PIN xl3[90]
    DIRECTION INPUT ;
    USE SIGNAL ;
    PORT
      LAYER M5 ;
        RECT  218.592 0 218.616 0.084 ;
    END
  END xl3[90]
  PIN xl3[91]
    DIRECTION INPUT ;
    USE SIGNAL ;
    PORT
      LAYER M5 ;
        RECT  218.832 0 218.856 0.084 ;
    END
  END xl3[91]
  PIN xl3[92]
    DIRECTION INPUT ;
    USE SIGNAL ;
    PORT
      LAYER M5 ;
        RECT  219.072 0 219.096 0.084 ;
    END
  END xl3[92]
  PIN xl3[93]
    DIRECTION INPUT ;
    USE SIGNAL ;
    PORT
      LAYER M5 ;
        RECT  219.312 0 219.336 0.084 ;
    END
  END xl3[93]
  PIN xl3[94]
    DIRECTION INPUT ;
    USE SIGNAL ;
    PORT
      LAYER M5 ;
        RECT  219.552 0 219.576 0.084 ;
    END
  END xl3[94]
  PIN xl3[95]
    DIRECTION INPUT ;
    USE SIGNAL ;
    PORT
      LAYER M5 ;
        RECT  219.792 0 219.816 0.084 ;
    END
  END xl3[95]
  PIN xl3[96]
    DIRECTION INPUT ;
    USE SIGNAL ;
    PORT
      LAYER M5 ;
        RECT  220.032 0 220.056 0.084 ;
    END
  END xl3[96]
  PIN xl3[97]
    DIRECTION INPUT ;
    USE SIGNAL ;
    PORT
      LAYER M5 ;
        RECT  220.272 0 220.296 0.084 ;
    END
  END xl3[97]
  PIN xl3[98]
    DIRECTION INPUT ;
    USE SIGNAL ;
    PORT
      LAYER M5 ;
        RECT  220.512 0 220.536 0.084 ;
    END
  END xl3[98]
  PIN xl3[99]
    DIRECTION INPUT ;
    USE SIGNAL ;
    PORT
      LAYER M5 ;
        RECT  220.752 0 220.776 0.084 ;
    END
  END xl3[99]
  PIN xl3[9]
    DIRECTION INPUT ;
    USE SIGNAL ;
    PORT
      LAYER M5 ;
        RECT  199.488 0 199.512 0.084 ;
    END
  END xl3[9]
  PIN VDD
    DIRECTION INOUT ;
    USE POWER ;
    PORT
      LAYER M5 ;
        RECT  274.356 4.311 274.476 64.809 ;
        RECT  270.036 4.311 270.156 64.809 ;
        RECT  265.716 4.311 265.836 64.809 ;
        RECT  261.396 4.311 261.516 64.809 ;
        RECT  257.076 4.311 257.196 64.809 ;
        RECT  252.756 4.311 252.876 64.809 ;
        RECT  248.436 4.311 248.556 64.809 ;
        RECT  244.116 4.311 244.236 64.809 ;
        RECT  239.796 4.311 239.916 64.809 ;
        RECT  235.476 4.311 235.596 64.809 ;
        RECT  231.156 4.311 231.276 64.809 ;
        RECT  226.836 4.311 226.956 64.809 ;
        RECT  222.516 4.311 222.636 64.809 ;
        RECT  218.196 4.311 218.316 64.809 ;
        RECT  213.876 4.311 213.996 64.809 ;
        RECT  209.556 4.311 209.676 64.809 ;
        RECT  205.236 4.311 205.356 64.809 ;
        RECT  200.916 4.311 201.036 64.809 ;
        RECT  196.596 4.311 196.716 64.809 ;
        RECT  192.276 4.311 192.396 64.809 ;
        RECT  187.956 4.311 188.076 64.809 ;
        RECT  183.636 4.311 183.756 64.809 ;
        RECT  179.316 4.311 179.436 64.809 ;
        RECT  174.996 4.311 175.116 64.809 ;
        RECT  170.676 4.311 170.796 64.809 ;
        RECT  166.356 4.311 166.476 64.809 ;
        RECT  162.036 4.311 162.156 64.809 ;
        RECT  157.716 4.311 157.836 64.809 ;
        RECT  153.396 4.311 153.516 64.809 ;
        RECT  149.076 4.311 149.196 64.809 ;
        RECT  144.756 4.311 144.876 64.809 ;
        RECT  140.436 4.311 140.556 64.809 ;
        RECT  136.116 4.311 136.236 64.809 ;
        RECT  131.796 4.311 131.916 64.809 ;
        RECT  127.476 4.311 127.596 64.809 ;
        RECT  123.156 4.311 123.276 64.809 ;
        RECT  118.836 4.311 118.956 64.809 ;
        RECT  114.516 4.311 114.636 64.809 ;
        RECT  110.196 4.311 110.316 64.809 ;
        RECT  105.876 4.311 105.996 64.809 ;
        RECT  101.556 4.311 101.676 64.809 ;
        RECT  97.236 4.311 97.356 64.809 ;
        RECT  92.916 4.311 93.036 64.809 ;
        RECT  88.596 4.311 88.716 64.809 ;
        RECT  84.276 4.311 84.396 64.809 ;
        RECT  79.956 4.311 80.076 64.809 ;
        RECT  75.636 4.311 75.756 64.809 ;
        RECT  71.316 4.311 71.436 64.809 ;
        RECT  66.996 4.311 67.116 64.809 ;
        RECT  62.676 4.311 62.796 64.809 ;
        RECT  58.356 4.311 58.476 64.809 ;
        RECT  54.036 4.311 54.156 64.809 ;
        RECT  49.716 4.311 49.836 64.809 ;
        RECT  45.396 4.311 45.516 64.809 ;
        RECT  41.076 4.311 41.196 64.809 ;
        RECT  36.756 4.311 36.876 64.809 ;
        RECT  32.436 4.311 32.556 64.809 ;
        RECT  28.116 4.311 28.236 64.809 ;
        RECT  23.796 4.311 23.916 64.809 ;
        RECT  19.476 4.311 19.596 64.809 ;
        RECT  15.156 4.311 15.276 64.809 ;
        RECT  10.836 4.311 10.956 64.809 ;
        RECT  6.516 4.311 6.636 64.809 ;
    END
  END VDD
  PIN VSS
    DIRECTION INOUT ;
    USE GROUND ;
    PORT
      LAYER M5 ;
        RECT  274.164 4.297 274.284 64.823 ;
        RECT  269.844 4.297 269.964 64.823 ;
        RECT  265.524 4.297 265.644 64.823 ;
        RECT  261.204 4.297 261.324 64.823 ;
        RECT  256.884 4.297 257.004 64.823 ;
        RECT  252.564 4.297 252.684 64.823 ;
        RECT  248.244 4.297 248.364 64.823 ;
        RECT  243.924 4.297 244.044 64.823 ;
        RECT  239.604 4.297 239.724 64.823 ;
        RECT  235.284 4.297 235.404 64.823 ;
        RECT  230.964 4.297 231.084 64.823 ;
        RECT  226.644 4.297 226.764 64.823 ;
        RECT  222.324 4.297 222.444 64.823 ;
        RECT  218.004 4.297 218.124 64.823 ;
        RECT  213.684 4.297 213.804 64.823 ;
        RECT  209.364 4.297 209.484 64.823 ;
        RECT  205.044 4.297 205.164 64.823 ;
        RECT  200.724 4.297 200.844 64.823 ;
        RECT  196.404 4.297 196.524 64.823 ;
        RECT  192.084 4.297 192.204 64.823 ;
        RECT  187.764 4.297 187.884 64.823 ;
        RECT  183.444 4.297 183.564 64.823 ;
        RECT  179.124 4.297 179.244 64.823 ;
        RECT  174.804 4.297 174.924 64.823 ;
        RECT  170.484 4.297 170.604 64.823 ;
        RECT  166.164 4.297 166.284 64.823 ;
        RECT  161.844 4.297 161.964 64.823 ;
        RECT  157.524 4.297 157.644 64.823 ;
        RECT  153.204 4.297 153.324 64.823 ;
        RECT  148.884 4.297 149.004 64.823 ;
        RECT  144.564 4.297 144.684 64.823 ;
        RECT  140.244 4.297 140.364 64.823 ;
        RECT  135.924 4.297 136.044 64.823 ;
        RECT  131.604 4.297 131.724 64.823 ;
        RECT  127.284 4.297 127.404 64.823 ;
        RECT  122.964 4.297 123.084 64.823 ;
        RECT  118.644 4.297 118.764 64.823 ;
        RECT  114.324 4.297 114.444 64.823 ;
        RECT  110.004 4.297 110.124 64.823 ;
        RECT  105.684 4.297 105.804 64.823 ;
        RECT  101.364 4.297 101.484 64.823 ;
        RECT  97.044 4.297 97.164 64.823 ;
        RECT  92.724 4.297 92.844 64.823 ;
        RECT  88.404 4.297 88.524 64.823 ;
        RECT  84.084 4.297 84.204 64.823 ;
        RECT  79.764 4.297 79.884 64.823 ;
        RECT  75.444 4.297 75.564 64.823 ;
        RECT  71.124 4.297 71.244 64.823 ;
        RECT  66.804 4.297 66.924 64.823 ;
        RECT  62.484 4.297 62.604 64.823 ;
        RECT  58.164 4.297 58.284 64.823 ;
        RECT  53.844 4.297 53.964 64.823 ;
        RECT  49.524 4.297 49.644 64.823 ;
        RECT  45.204 4.297 45.324 64.823 ;
        RECT  40.884 4.297 41.004 64.823 ;
        RECT  36.564 4.297 36.684 64.823 ;
        RECT  32.244 4.297 32.364 64.823 ;
        RECT  27.924 4.297 28.044 64.823 ;
        RECT  23.604 4.297 23.724 64.823 ;
        RECT  19.284 4.297 19.404 64.823 ;
        RECT  14.964 4.297 15.084 64.823 ;
        RECT  10.644 4.297 10.764 64.823 ;
        RECT  6.324 4.297 6.444 64.823 ;
    END
  END VSS
  OBS
    LAYER RVTN ;
     RECT  0 0 278.819 69.12 ;
    LAYER RVTP ;
     RECT  0 0 278.819 69.12 ;
    LAYER M1 ;
     RECT  0 0 278.819 69.12 ;
    LAYER M2 ;
     RECT  0 0 278.819 69.12 ;
    LAYER M3 ;
     RECT  0 0 278.819 69.12 ;
    LAYER M4 ;
     RECT  0 0 278.819 69.12 ;
    LAYER M5 ;
     RECT  0 0 278.819 69.12 ;
  END
END dsfd_cfifo_crs4
END LIBRARY
